VERSION 5.8 ;
BUSBITCHARS "[]" ;
DIVIDERCHAR "/" ;
UNITS
    DATABASE MICRONS 1000 ;
END UNITS

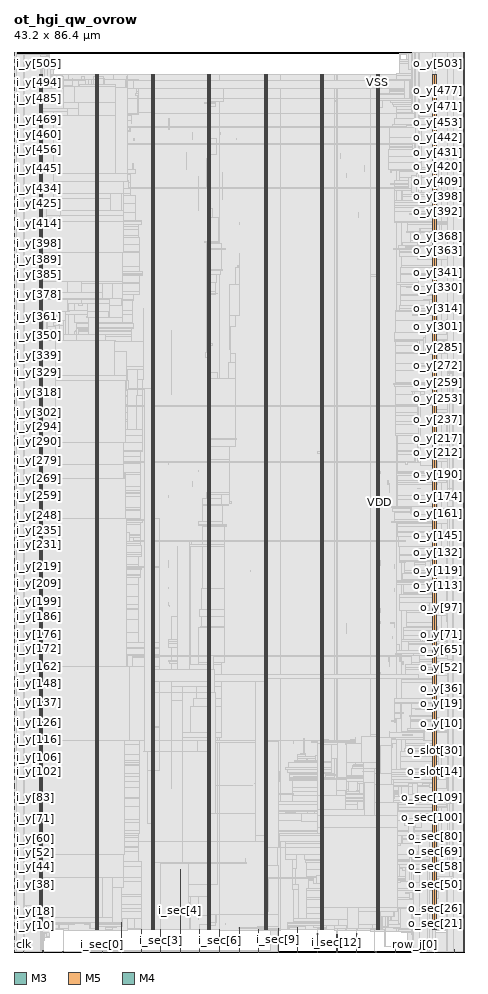
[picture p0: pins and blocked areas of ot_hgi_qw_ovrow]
MACRO ot_hgi_qw_ovrow
  FOREIGN ot_hgi_qw_ovrow 0 0 ;
  CLASS BLOCK ;
  SIZE 43.2 BY 86.4 ;
  PIN clk
    DIRECTION INPUT ;
    USE SIGNAL ;
    PORT
      LAYER M3 ;
        RECT  0.936 0 0.954 0.038 ;
    END
    PORT
      LAYER M3 ;
        RECT  0.936 0.012 0.954 0.077 ;
    END
  END clk
  PIN i_n[0]
    DIRECTION INPUT ;
    USE SIGNAL ;
    PORT
      LAYER M5 ;
        RECT  2.784 0 2.808 0.084 ;
    END
    PORT
      LAYER M5 ;
        RECT  2.784 0.016 2.808 0.037 ;
    END
    PORT
      LAYER M5 ;
        RECT  2.688 0.037 2.808 0.179 ;
    END
  END i_n[0]
  PIN i_n[1]
    DIRECTION INPUT ;
    USE SIGNAL ;
    PORT
      LAYER M3 ;
        RECT  4.68 0 4.698 0.038 ;
    END
    PORT
      LAYER M3 ;
        RECT  4.68 0.012 4.698 0.031 ;
    END
    PORT
      LAYER M3 ;
        RECT  4.68 0.031 4.77 0.059 ;
    END
  END i_n[1]
  PIN i_n[2]
    DIRECTION INPUT ;
    USE SIGNAL ;
    PORT
      LAYER M5 ;
        RECT  6.576 0 6.6 0.084 ;
    END
    PORT
      LAYER M5 ;
        RECT  6.576 0.016 6.6 0.131 ;
    END
  END i_n[2]
  PIN i_sec[0]
    DIRECTION INPUT ;
    USE SIGNAL ;
    PORT
      LAYER M3 ;
        RECT  8.46 0 8.478 0.038 ;
    END
    PORT
      LAYER M3 ;
        RECT  8.46 0.012 8.478 0.059 ;
    END
  END i_sec[0]
  PIN i_sec[10]
    DIRECTION INPUT ;
    USE SIGNAL ;
    PORT
      LAYER M3 ;
        RECT  27.216 0 27.234 0.038 ;
    END
    PORT
      LAYER M3 ;
        RECT  27.216 0.012 27.234 2.371 ;
    END
  END i_sec[10]
  PIN i_sec[11]
    DIRECTION INPUT ;
    USE SIGNAL ;
    PORT
      LAYER M5 ;
        RECT  29.088 0 29.112 0.084 ;
    END
    PORT
      LAYER M5 ;
        RECT  29.088 0.016 29.112 1.763 ;
    END
  END i_sec[11]
  PIN i_sec[12]
    DIRECTION INPUT ;
    USE SIGNAL ;
    PORT
      LAYER M3 ;
        RECT  30.996 0 31.014 0.038 ;
    END
    PORT
      LAYER M3 ;
        RECT  30.996 0.012 31.014 1.723 ;
    END
  END i_sec[12]
  PIN i_sec[13]
    DIRECTION INPUT ;
    USE SIGNAL ;
    PORT
      LAYER M5 ;
        RECT  32.88 0 32.904 0.084 ;
    END
    PORT
      LAYER M5 ;
        RECT  32.88 0.016 32.904 1.763 ;
    END
  END i_sec[13]
  PIN i_sec[14]
    DIRECTION INPUT ;
    USE SIGNAL ;
    PORT
      LAYER M3 ;
        RECT  34.74 0 34.758 0.038 ;
    END
    PORT
      LAYER M3 ;
        RECT  34.74 0.012 34.758 0.031 ;
    END
    PORT
      LAYER M3 ;
        RECT  34.596 0.031 34.758 0.059 ;
    END
  END i_sec[14]
  PIN i_sec[1]
    DIRECTION INPUT ;
    USE SIGNAL ;
    PORT
      LAYER M5 ;
        RECT  10.32 0 10.344 0.084 ;
    END
    PORT
      LAYER M5 ;
        RECT  10.32 0.016 10.344 2.821 ;
    END
  END i_sec[1]
  PIN i_sec[2]
    DIRECTION INPUT ;
    USE SIGNAL ;
    PORT
      LAYER M3 ;
        RECT  12.204 0 12.222 0.038 ;
    END
    PORT
      LAYER M3 ;
        RECT  12.204 0.012 12.222 2.191 ;
    END
  END i_sec[2]
  PIN i_sec[3]
    DIRECTION INPUT ;
    USE SIGNAL ;
    PORT
      LAYER M5 ;
        RECT  14.064 0 14.088 0.084 ;
    END
    PORT
      LAYER M5 ;
        RECT  14.064 0.016 14.088 2.137 ;
    END
  END i_sec[3]
  PIN i_sec[4]
    DIRECTION INPUT ;
    USE SIGNAL ;
    PORT
      LAYER M3 ;
        RECT  15.948 0 15.966 0.038 ;
    END
    PORT
      LAYER M3 ;
        RECT  15.948 0.012 15.966 7.889 ;
    END
  END i_sec[4]
  PIN i_sec[5]
    DIRECTION INPUT ;
    USE SIGNAL ;
    PORT
      LAYER M5 ;
        RECT  17.808 0 17.832 0.084 ;
    END
    PORT
      LAYER M5 ;
        RECT  17.808 0.016 17.832 2.137 ;
    END
  END i_sec[5]
  PIN i_sec[6]
    DIRECTION INPUT ;
    USE SIGNAL ;
    PORT
      LAYER M3 ;
        RECT  19.728 0 19.746 0.038 ;
    END
    PORT
      LAYER M3 ;
        RECT  19.728 0.012 19.746 2.129 ;
    END
  END i_sec[6]
  PIN i_sec[7]
    DIRECTION INPUT ;
    USE SIGNAL ;
    PORT
      LAYER M5 ;
        RECT  21.6 0 21.624 0.084 ;
    END
    PORT
      LAYER M5 ;
        RECT  21.6 0.016 21.624 2.339 ;
    END
  END i_sec[7]
  PIN i_sec[8]
    DIRECTION INPUT ;
    USE SIGNAL ;
    PORT
      LAYER M3 ;
        RECT  23.472 0 23.49 0.038 ;
    END
    PORT
      LAYER M3 ;
        RECT  23.472 0.012 23.49 2.143 ;
    END
  END i_sec[8]
  PIN i_sec[9]
    DIRECTION INPUT ;
    USE SIGNAL ;
    PORT
      LAYER M5 ;
        RECT  25.344 0 25.368 0.084 ;
    END
    PORT
      LAYER M5 ;
        RECT  25.344 0.016 25.368 2.291 ;
    END
  END i_sec[9]
  PIN i_v
    DIRECTION INPUT ;
    USE SIGNAL ;
    PORT
      LAYER M5 ;
        RECT  36.624 0 36.648 0.084 ;
    END
    PORT
      LAYER M5 ;
        RECT  36.624 0.016 36.648 0.563 ;
    END
  END i_v
  PIN i_y[0]
    DIRECTION INPUT ;
    USE SIGNAL ;
    PORT
      LAYER M4 ;
        RECT  0 0.096 0.084 0.12 ;
    END
  END i_y[0]
  PIN i_y[100]
    DIRECTION INPUT ;
    USE SIGNAL ;
    PORT
      LAYER M4 ;
        RECT  0 16.944 0.084 16.968 ;
    END
  END i_y[100]
  PIN i_y[101]
    DIRECTION INPUT ;
    USE SIGNAL ;
    PORT
      LAYER M4 ;
        RECT  0 17.136 0.084 17.16 ;
    END
  END i_y[101]
  PIN i_y[102]
    DIRECTION INPUT ;
    USE SIGNAL ;
    PORT
      LAYER M4 ;
        RECT  0 17.28 0.084 17.304 ;
    END
  END i_y[102]
  PIN i_y[103]
    DIRECTION INPUT ;
    USE SIGNAL ;
    PORT
      LAYER M4 ;
        RECT  0 17.472 0.084 17.496 ;
    END
  END i_y[103]
  PIN i_y[104]
    DIRECTION INPUT ;
    USE SIGNAL ;
    PORT
      LAYER M4 ;
        RECT  0 17.616 0.084 17.64 ;
    END
  END i_y[104]
  PIN i_y[105]
    DIRECTION INPUT ;
    USE SIGNAL ;
    PORT
      LAYER M4 ;
        RECT  0 17.808 0.084 17.832 ;
    END
  END i_y[105]
  PIN i_y[106]
    DIRECTION INPUT ;
    USE SIGNAL ;
    PORT
      LAYER M4 ;
        RECT  0 17.952 0.084 17.976 ;
    END
  END i_y[106]
  PIN i_y[107]
    DIRECTION INPUT ;
    USE SIGNAL ;
    PORT
      LAYER M4 ;
        RECT  0 18.144 0.084 18.168 ;
    END
  END i_y[107]
  PIN i_y[108]
    DIRECTION INPUT ;
    USE SIGNAL ;
    PORT
      LAYER M4 ;
        RECT  0 18.288 0.084 18.312 ;
    END
  END i_y[108]
  PIN i_y[109]
    DIRECTION INPUT ;
    USE SIGNAL ;
    PORT
      LAYER M4 ;
        RECT  0 18.48 0.084 18.504 ;
    END
  END i_y[109]
  PIN i_y[10]
    DIRECTION INPUT ;
    USE SIGNAL ;
    PORT
      LAYER M4 ;
        RECT  0 1.776 0.084 1.8 ;
    END
  END i_y[10]
  PIN i_y[110]
    DIRECTION INPUT ;
    USE SIGNAL ;
    PORT
      LAYER M4 ;
        RECT  0 18.624 0.084 18.648 ;
    END
  END i_y[110]
  PIN i_y[111]
    DIRECTION INPUT ;
    USE SIGNAL ;
    PORT
      LAYER M4 ;
        RECT  0 18.816 0.084 18.84 ;
    END
  END i_y[111]
  PIN i_y[112]
    DIRECTION INPUT ;
    USE SIGNAL ;
    PORT
      LAYER M4 ;
        RECT  0 18.96 0.084 18.984 ;
    END
  END i_y[112]
  PIN i_y[113]
    DIRECTION INPUT ;
    USE SIGNAL ;
    PORT
      LAYER M4 ;
        RECT  0 19.152 0.084 19.176 ;
    END
  END i_y[113]
  PIN i_y[114]
    DIRECTION INPUT ;
    USE SIGNAL ;
    PORT
      LAYER M4 ;
        RECT  0 19.296 0.084 19.32 ;
    END
  END i_y[114]
  PIN i_y[115]
    DIRECTION INPUT ;
    USE SIGNAL ;
    PORT
      LAYER M4 ;
        RECT  0 19.488 0.084 19.512 ;
    END
  END i_y[115]
  PIN i_y[116]
    DIRECTION INPUT ;
    USE SIGNAL ;
    PORT
      LAYER M4 ;
        RECT  0 19.632 0.084 19.656 ;
    END
  END i_y[116]
  PIN i_y[117]
    DIRECTION INPUT ;
    USE SIGNAL ;
    PORT
      LAYER M4 ;
        RECT  0 19.824 0.084 19.848 ;
    END
  END i_y[117]
  PIN i_y[118]
    DIRECTION INPUT ;
    USE SIGNAL ;
    PORT
      LAYER M4 ;
        RECT  0 19.968 0.084 19.992 ;
    END
  END i_y[118]
  PIN i_y[119]
    DIRECTION INPUT ;
    USE SIGNAL ;
    PORT
      LAYER M4 ;
        RECT  0 20.16 0.084 20.184 ;
    END
  END i_y[119]
  PIN i_y[11]
    DIRECTION INPUT ;
    USE SIGNAL ;
    PORT
      LAYER M4 ;
        RECT  0 1.92 0.084 1.944 ;
    END
  END i_y[11]
  PIN i_y[120]
    DIRECTION INPUT ;
    USE SIGNAL ;
    PORT
      LAYER M4 ;
        RECT  0 20.304 0.084 20.328 ;
    END
  END i_y[120]
  PIN i_y[121]
    DIRECTION INPUT ;
    USE SIGNAL ;
    PORT
      LAYER M4 ;
        RECT  0 20.496 0.084 20.52 ;
    END
  END i_y[121]
  PIN i_y[122]
    DIRECTION INPUT ;
    USE SIGNAL ;
    PORT
      LAYER M4 ;
        RECT  0 20.64 0.084 20.664 ;
    END
  END i_y[122]
  PIN i_y[123]
    DIRECTION INPUT ;
    USE SIGNAL ;
    PORT
      LAYER M4 ;
        RECT  0 20.832 0.084 20.856 ;
    END
  END i_y[123]
  PIN i_y[124]
    DIRECTION INPUT ;
    USE SIGNAL ;
    PORT
      LAYER M4 ;
        RECT  0 20.976 0.084 21 ;
    END
  END i_y[124]
  PIN i_y[125]
    DIRECTION INPUT ;
    USE SIGNAL ;
    PORT
      LAYER M4 ;
        RECT  0 21.168 0.084 21.192 ;
    END
  END i_y[125]
  PIN i_y[126]
    DIRECTION INPUT ;
    USE SIGNAL ;
    PORT
      LAYER M4 ;
        RECT  0 21.312 0.084 21.336 ;
    END
  END i_y[126]
  PIN i_y[127]
    DIRECTION INPUT ;
    USE SIGNAL ;
    PORT
      LAYER M4 ;
        RECT  0 21.504 0.084 21.528 ;
    END
  END i_y[127]
  PIN i_y[128]
    DIRECTION INPUT ;
    USE SIGNAL ;
    PORT
      LAYER M4 ;
        RECT  0 21.696 0.084 21.72 ;
    END
  END i_y[128]
  PIN i_y[129]
    DIRECTION INPUT ;
    USE SIGNAL ;
    PORT
      LAYER M4 ;
        RECT  0 21.84 0.084 21.864 ;
    END
  END i_y[129]
  PIN i_y[12]
    DIRECTION INPUT ;
    USE SIGNAL ;
    PORT
      LAYER M4 ;
        RECT  0 2.112 0.084 2.136 ;
    END
  END i_y[12]
  PIN i_y[130]
    DIRECTION INPUT ;
    USE SIGNAL ;
    PORT
      LAYER M4 ;
        RECT  0 22.032 0.084 22.056 ;
    END
  END i_y[130]
  PIN i_y[131]
    DIRECTION INPUT ;
    USE SIGNAL ;
    PORT
      LAYER M4 ;
        RECT  0 22.176 0.084 22.2 ;
    END
  END i_y[131]
  PIN i_y[132]
    DIRECTION INPUT ;
    USE SIGNAL ;
    PORT
      LAYER M4 ;
        RECT  0 22.368 0.084 22.392 ;
    END
  END i_y[132]
  PIN i_y[133]
    DIRECTION INPUT ;
    USE SIGNAL ;
    PORT
      LAYER M4 ;
        RECT  0 22.512 0.084 22.536 ;
    END
  END i_y[133]
  PIN i_y[134]
    DIRECTION INPUT ;
    USE SIGNAL ;
    PORT
      LAYER M4 ;
        RECT  0 22.704 0.084 22.728 ;
    END
  END i_y[134]
  PIN i_y[135]
    DIRECTION INPUT ;
    USE SIGNAL ;
    PORT
      LAYER M4 ;
        RECT  0 22.848 0.084 22.872 ;
    END
  END i_y[135]
  PIN i_y[136]
    DIRECTION INPUT ;
    USE SIGNAL ;
    PORT
      LAYER M4 ;
        RECT  0 23.04 0.084 23.064 ;
    END
  END i_y[136]
  PIN i_y[137]
    DIRECTION INPUT ;
    USE SIGNAL ;
    PORT
      LAYER M4 ;
        RECT  0 23.184 0.084 23.208 ;
    END
  END i_y[137]
  PIN i_y[138]
    DIRECTION INPUT ;
    USE SIGNAL ;
    PORT
      LAYER M4 ;
        RECT  0 23.376 0.084 23.4 ;
    END
  END i_y[138]
  PIN i_y[139]
    DIRECTION INPUT ;
    USE SIGNAL ;
    PORT
      LAYER M4 ;
        RECT  0 23.52 0.084 23.544 ;
    END
  END i_y[139]
  PIN i_y[13]
    DIRECTION INPUT ;
    USE SIGNAL ;
    PORT
      LAYER M4 ;
        RECT  0 2.256 0.084 2.28 ;
    END
  END i_y[13]
  PIN i_y[140]
    DIRECTION INPUT ;
    USE SIGNAL ;
    PORT
      LAYER M4 ;
        RECT  0 23.712 0.084 23.736 ;
    END
  END i_y[140]
  PIN i_y[141]
    DIRECTION INPUT ;
    USE SIGNAL ;
    PORT
      LAYER M4 ;
        RECT  0 23.856 0.084 23.88 ;
    END
  END i_y[141]
  PIN i_y[142]
    DIRECTION INPUT ;
    USE SIGNAL ;
    PORT
      LAYER M4 ;
        RECT  0 24.048 0.084 24.072 ;
    END
  END i_y[142]
  PIN i_y[143]
    DIRECTION INPUT ;
    USE SIGNAL ;
    PORT
      LAYER M4 ;
        RECT  0 24.192 0.084 24.216 ;
    END
  END i_y[143]
  PIN i_y[144]
    DIRECTION INPUT ;
    USE SIGNAL ;
    PORT
      LAYER M4 ;
        RECT  0 24.384 0.084 24.408 ;
    END
  END i_y[144]
  PIN i_y[145]
    DIRECTION INPUT ;
    USE SIGNAL ;
    PORT
      LAYER M4 ;
        RECT  0 24.528 0.084 24.552 ;
    END
  END i_y[145]
  PIN i_y[146]
    DIRECTION INPUT ;
    USE SIGNAL ;
    PORT
      LAYER M4 ;
        RECT  0 24.72 0.084 24.744 ;
    END
  END i_y[146]
  PIN i_y[147]
    DIRECTION INPUT ;
    USE SIGNAL ;
    PORT
      LAYER M4 ;
        RECT  0 24.864 0.084 24.888 ;
    END
  END i_y[147]
  PIN i_y[148]
    DIRECTION INPUT ;
    USE SIGNAL ;
    PORT
      LAYER M4 ;
        RECT  0 25.056 0.084 25.08 ;
    END
  END i_y[148]
  PIN i_y[149]
    DIRECTION INPUT ;
    USE SIGNAL ;
    PORT
      LAYER M4 ;
        RECT  0 25.2 0.084 25.224 ;
    END
  END i_y[149]
  PIN i_y[14]
    DIRECTION INPUT ;
    USE SIGNAL ;
    PORT
      LAYER M4 ;
        RECT  0 2.448 0.084 2.472 ;
    END
  END i_y[14]
  PIN i_y[150]
    DIRECTION INPUT ;
    USE SIGNAL ;
    PORT
      LAYER M4 ;
        RECT  0 25.392 0.084 25.416 ;
    END
  END i_y[150]
  PIN i_y[151]
    DIRECTION INPUT ;
    USE SIGNAL ;
    PORT
      LAYER M4 ;
        RECT  0 25.536 0.084 25.56 ;
    END
  END i_y[151]
  PIN i_y[152]
    DIRECTION INPUT ;
    USE SIGNAL ;
    PORT
      LAYER M4 ;
        RECT  0 25.728 0.084 25.752 ;
    END
  END i_y[152]
  PIN i_y[153]
    DIRECTION INPUT ;
    USE SIGNAL ;
    PORT
      LAYER M4 ;
        RECT  0 25.872 0.084 25.896 ;
    END
  END i_y[153]
  PIN i_y[154]
    DIRECTION INPUT ;
    USE SIGNAL ;
    PORT
      LAYER M4 ;
        RECT  0 26.064 0.084 26.088 ;
    END
  END i_y[154]
  PIN i_y[155]
    DIRECTION INPUT ;
    USE SIGNAL ;
    PORT
      LAYER M4 ;
        RECT  0 26.208 0.084 26.232 ;
    END
  END i_y[155]
  PIN i_y[156]
    DIRECTION INPUT ;
    USE SIGNAL ;
    PORT
      LAYER M4 ;
        RECT  0 26.4 0.084 26.424 ;
    END
  END i_y[156]
  PIN i_y[157]
    DIRECTION INPUT ;
    USE SIGNAL ;
    PORT
      LAYER M4 ;
        RECT  0 26.544 0.084 26.568 ;
    END
  END i_y[157]
  PIN i_y[158]
    DIRECTION INPUT ;
    USE SIGNAL ;
    PORT
      LAYER M4 ;
        RECT  0 26.736 0.084 26.76 ;
    END
  END i_y[158]
  PIN i_y[159]
    DIRECTION INPUT ;
    USE SIGNAL ;
    PORT
      LAYER M4 ;
        RECT  0 26.928 0.084 26.952 ;
    END
  END i_y[159]
  PIN i_y[15]
    DIRECTION INPUT ;
    USE SIGNAL ;
    PORT
      LAYER M4 ;
        RECT  0 2.592 0.084 2.616 ;
    END
  END i_y[15]
  PIN i_y[160]
    DIRECTION INPUT ;
    USE SIGNAL ;
    PORT
      LAYER M4 ;
        RECT  0 27.072 0.084 27.096 ;
    END
  END i_y[160]
  PIN i_y[161]
    DIRECTION INPUT ;
    USE SIGNAL ;
    PORT
      LAYER M4 ;
        RECT  0 27.264 0.084 27.288 ;
    END
  END i_y[161]
  PIN i_y[162]
    DIRECTION INPUT ;
    USE SIGNAL ;
    PORT
      LAYER M4 ;
        RECT  0 27.408 0.084 27.432 ;
    END
  END i_y[162]
  PIN i_y[163]
    DIRECTION INPUT ;
    USE SIGNAL ;
    PORT
      LAYER M4 ;
        RECT  0 27.6 0.084 27.624 ;
    END
  END i_y[163]
  PIN i_y[164]
    DIRECTION INPUT ;
    USE SIGNAL ;
    PORT
      LAYER M4 ;
        RECT  0 27.744 0.084 27.768 ;
    END
  END i_y[164]
  PIN i_y[165]
    DIRECTION INPUT ;
    USE SIGNAL ;
    PORT
      LAYER M4 ;
        RECT  0 27.936 0.084 27.96 ;
    END
  END i_y[165]
  PIN i_y[166]
    DIRECTION INPUT ;
    USE SIGNAL ;
    PORT
      LAYER M4 ;
        RECT  0 28.08 0.084 28.104 ;
    END
  END i_y[166]
  PIN i_y[167]
    DIRECTION INPUT ;
    USE SIGNAL ;
    PORT
      LAYER M4 ;
        RECT  0 28.272 0.084 28.296 ;
    END
  END i_y[167]
  PIN i_y[168]
    DIRECTION INPUT ;
    USE SIGNAL ;
    PORT
      LAYER M4 ;
        RECT  0 28.416 0.084 28.44 ;
    END
  END i_y[168]
  PIN i_y[169]
    DIRECTION INPUT ;
    USE SIGNAL ;
    PORT
      LAYER M4 ;
        RECT  0 28.608 0.084 28.632 ;
    END
  END i_y[169]
  PIN i_y[16]
    DIRECTION INPUT ;
    USE SIGNAL ;
    PORT
      LAYER M4 ;
        RECT  0 2.784 0.084 2.808 ;
    END
  END i_y[16]
  PIN i_y[170]
    DIRECTION INPUT ;
    USE SIGNAL ;
    PORT
      LAYER M4 ;
        RECT  0 28.752 0.084 28.776 ;
    END
  END i_y[170]
  PIN i_y[171]
    DIRECTION INPUT ;
    USE SIGNAL ;
    PORT
      LAYER M4 ;
        RECT  0 28.944 0.084 28.968 ;
    END
  END i_y[171]
  PIN i_y[172]
    DIRECTION INPUT ;
    USE SIGNAL ;
    PORT
      LAYER M4 ;
        RECT  0 29.088 0.084 29.112 ;
    END
  END i_y[172]
  PIN i_y[173]
    DIRECTION INPUT ;
    USE SIGNAL ;
    PORT
      LAYER M4 ;
        RECT  0 29.28 0.084 29.304 ;
    END
  END i_y[173]
  PIN i_y[174]
    DIRECTION INPUT ;
    USE SIGNAL ;
    PORT
      LAYER M4 ;
        RECT  0 29.424 0.084 29.448 ;
    END
  END i_y[174]
  PIN i_y[175]
    DIRECTION INPUT ;
    USE SIGNAL ;
    PORT
      LAYER M4 ;
        RECT  0 29.616 0.084 29.64 ;
    END
  END i_y[175]
  PIN i_y[176]
    DIRECTION INPUT ;
    USE SIGNAL ;
    PORT
      LAYER M4 ;
        RECT  0 29.76 0.084 29.784 ;
    END
  END i_y[176]
  PIN i_y[177]
    DIRECTION INPUT ;
    USE SIGNAL ;
    PORT
      LAYER M4 ;
        RECT  0 29.952 0.084 29.976 ;
    END
  END i_y[177]
  PIN i_y[178]
    DIRECTION INPUT ;
    USE SIGNAL ;
    PORT
      LAYER M4 ;
        RECT  0 30.096 0.084 30.12 ;
    END
  END i_y[178]
  PIN i_y[179]
    DIRECTION INPUT ;
    USE SIGNAL ;
    PORT
      LAYER M4 ;
        RECT  0 30.288 0.084 30.312 ;
    END
  END i_y[179]
  PIN i_y[17]
    DIRECTION INPUT ;
    USE SIGNAL ;
    PORT
      LAYER M4 ;
        RECT  0 2.928 0.084 2.952 ;
    END
  END i_y[17]
  PIN i_y[180]
    DIRECTION INPUT ;
    USE SIGNAL ;
    PORT
      LAYER M4 ;
        RECT  0 30.432 0.084 30.456 ;
    END
  END i_y[180]
  PIN i_y[181]
    DIRECTION INPUT ;
    USE SIGNAL ;
    PORT
      LAYER M4 ;
        RECT  0 30.624 0.084 30.648 ;
    END
  END i_y[181]
  PIN i_y[182]
    DIRECTION INPUT ;
    USE SIGNAL ;
    PORT
      LAYER M4 ;
        RECT  0 30.768 0.084 30.792 ;
    END
  END i_y[182]
  PIN i_y[183]
    DIRECTION INPUT ;
    USE SIGNAL ;
    PORT
      LAYER M4 ;
        RECT  0 30.96 0.084 30.984 ;
    END
  END i_y[183]
  PIN i_y[184]
    DIRECTION INPUT ;
    USE SIGNAL ;
    PORT
      LAYER M4 ;
        RECT  0 31.104 0.084 31.128 ;
    END
  END i_y[184]
  PIN i_y[185]
    DIRECTION INPUT ;
    USE SIGNAL ;
    PORT
      LAYER M4 ;
        RECT  0 31.296 0.084 31.32 ;
    END
  END i_y[185]
  PIN i_y[186]
    DIRECTION INPUT ;
    USE SIGNAL ;
    PORT
      LAYER M4 ;
        RECT  0 31.44 0.084 31.464 ;
    END
  END i_y[186]
  PIN i_y[187]
    DIRECTION INPUT ;
    USE SIGNAL ;
    PORT
      LAYER M4 ;
        RECT  0 31.632 0.084 31.656 ;
    END
  END i_y[187]
  PIN i_y[188]
    DIRECTION INPUT ;
    USE SIGNAL ;
    PORT
      LAYER M4 ;
        RECT  0 31.776 0.084 31.8 ;
    END
  END i_y[188]
  PIN i_y[189]
    DIRECTION INPUT ;
    USE SIGNAL ;
    PORT
      LAYER M4 ;
        RECT  0 31.968 0.084 31.992 ;
    END
  END i_y[189]
  PIN i_y[18]
    DIRECTION INPUT ;
    USE SIGNAL ;
    PORT
      LAYER M4 ;
        RECT  0 3.12 0.084 3.144 ;
    END
  END i_y[18]
  PIN i_y[190]
    DIRECTION INPUT ;
    USE SIGNAL ;
    PORT
      LAYER M4 ;
        RECT  0 32.112 0.084 32.136 ;
    END
  END i_y[190]
  PIN i_y[191]
    DIRECTION INPUT ;
    USE SIGNAL ;
    PORT
      LAYER M4 ;
        RECT  0 32.304 0.084 32.328 ;
    END
  END i_y[191]
  PIN i_y[192]
    DIRECTION INPUT ;
    USE SIGNAL ;
    PORT
      LAYER M4 ;
        RECT  0 32.496 0.084 32.52 ;
    END
  END i_y[192]
  PIN i_y[193]
    DIRECTION INPUT ;
    USE SIGNAL ;
    PORT
      LAYER M4 ;
        RECT  0 32.64 0.084 32.664 ;
    END
  END i_y[193]
  PIN i_y[194]
    DIRECTION INPUT ;
    USE SIGNAL ;
    PORT
      LAYER M4 ;
        RECT  0 32.832 0.084 32.856 ;
    END
  END i_y[194]
  PIN i_y[195]
    DIRECTION INPUT ;
    USE SIGNAL ;
    PORT
      LAYER M4 ;
        RECT  0 32.976 0.084 33 ;
    END
  END i_y[195]
  PIN i_y[196]
    DIRECTION INPUT ;
    USE SIGNAL ;
    PORT
      LAYER M4 ;
        RECT  0 33.168 0.084 33.192 ;
    END
  END i_y[196]
  PIN i_y[197]
    DIRECTION INPUT ;
    USE SIGNAL ;
    PORT
      LAYER M4 ;
        RECT  0 33.312 0.084 33.336 ;
    END
  END i_y[197]
  PIN i_y[198]
    DIRECTION INPUT ;
    USE SIGNAL ;
    PORT
      LAYER M4 ;
        RECT  0 33.504 0.084 33.528 ;
    END
  END i_y[198]
  PIN i_y[199]
    DIRECTION INPUT ;
    USE SIGNAL ;
    PORT
      LAYER M4 ;
        RECT  0 33.648 0.084 33.672 ;
    END
  END i_y[199]
  PIN i_y[19]
    DIRECTION INPUT ;
    USE SIGNAL ;
    PORT
      LAYER M4 ;
        RECT  0 3.264 0.084 3.288 ;
    END
  END i_y[19]
  PIN i_y[1]
    DIRECTION INPUT ;
    USE SIGNAL ;
    PORT
      LAYER M4 ;
        RECT  0 0.24 0.084 0.264 ;
    END
  END i_y[1]
  PIN i_y[200]
    DIRECTION INPUT ;
    USE SIGNAL ;
    PORT
      LAYER M4 ;
        RECT  0 33.84 0.084 33.864 ;
    END
  END i_y[200]
  PIN i_y[201]
    DIRECTION INPUT ;
    USE SIGNAL ;
    PORT
      LAYER M4 ;
        RECT  0 33.984 0.084 34.008 ;
    END
  END i_y[201]
  PIN i_y[202]
    DIRECTION INPUT ;
    USE SIGNAL ;
    PORT
      LAYER M4 ;
        RECT  0 34.176 0.084 34.2 ;
    END
  END i_y[202]
  PIN i_y[203]
    DIRECTION INPUT ;
    USE SIGNAL ;
    PORT
      LAYER M4 ;
        RECT  0 34.32 0.084 34.344 ;
    END
  END i_y[203]
  PIN i_y[204]
    DIRECTION INPUT ;
    USE SIGNAL ;
    PORT
      LAYER M4 ;
        RECT  0 34.512 0.084 34.536 ;
    END
  END i_y[204]
  PIN i_y[205]
    DIRECTION INPUT ;
    USE SIGNAL ;
    PORT
      LAYER M4 ;
        RECT  0 34.656 0.084 34.68 ;
    END
  END i_y[205]
  PIN i_y[206]
    DIRECTION INPUT ;
    USE SIGNAL ;
    PORT
      LAYER M4 ;
        RECT  0 34.848 0.084 34.872 ;
    END
  END i_y[206]
  PIN i_y[207]
    DIRECTION INPUT ;
    USE SIGNAL ;
    PORT
      LAYER M4 ;
        RECT  0 34.992 0.084 35.016 ;
    END
  END i_y[207]
  PIN i_y[208]
    DIRECTION INPUT ;
    USE SIGNAL ;
    PORT
      LAYER M4 ;
        RECT  0 35.184 0.084 35.208 ;
    END
  END i_y[208]
  PIN i_y[209]
    DIRECTION INPUT ;
    USE SIGNAL ;
    PORT
      LAYER M4 ;
        RECT  0 35.328 0.084 35.352 ;
    END
  END i_y[209]
  PIN i_y[20]
    DIRECTION INPUT ;
    USE SIGNAL ;
    PORT
      LAYER M4 ;
        RECT  0 3.456 0.084 3.48 ;
    END
  END i_y[20]
  PIN i_y[210]
    DIRECTION INPUT ;
    USE SIGNAL ;
    PORT
      LAYER M4 ;
        RECT  0 35.52 0.084 35.544 ;
    END
  END i_y[210]
  PIN i_y[211]
    DIRECTION INPUT ;
    USE SIGNAL ;
    PORT
      LAYER M4 ;
        RECT  0 35.664 0.084 35.688 ;
    END
  END i_y[211]
  PIN i_y[212]
    DIRECTION INPUT ;
    USE SIGNAL ;
    PORT
      LAYER M4 ;
        RECT  0 35.856 0.084 35.88 ;
    END
  END i_y[212]
  PIN i_y[213]
    DIRECTION INPUT ;
    USE SIGNAL ;
    PORT
      LAYER M4 ;
        RECT  0 36 0.084 36.024 ;
    END
  END i_y[213]
  PIN i_y[214]
    DIRECTION INPUT ;
    USE SIGNAL ;
    PORT
      LAYER M4 ;
        RECT  0 36.192 0.084 36.216 ;
    END
  END i_y[214]
  PIN i_y[215]
    DIRECTION INPUT ;
    USE SIGNAL ;
    PORT
      LAYER M4 ;
        RECT  0 36.336 0.084 36.36 ;
    END
  END i_y[215]
  PIN i_y[216]
    DIRECTION INPUT ;
    USE SIGNAL ;
    PORT
      LAYER M4 ;
        RECT  0 36.528 0.084 36.552 ;
    END
  END i_y[216]
  PIN i_y[217]
    DIRECTION INPUT ;
    USE SIGNAL ;
    PORT
      LAYER M4 ;
        RECT  0 36.672 0.084 36.696 ;
    END
  END i_y[217]
  PIN i_y[218]
    DIRECTION INPUT ;
    USE SIGNAL ;
    PORT
      LAYER M4 ;
        RECT  0 36.864 0.084 36.888 ;
    END
  END i_y[218]
  PIN i_y[219]
    DIRECTION INPUT ;
    USE SIGNAL ;
    PORT
      LAYER M4 ;
        RECT  0 37.008 0.084 37.032 ;
    END
  END i_y[219]
  PIN i_y[21]
    DIRECTION INPUT ;
    USE SIGNAL ;
    PORT
      LAYER M4 ;
        RECT  0 3.6 0.084 3.624 ;
    END
  END i_y[21]
  PIN i_y[220]
    DIRECTION INPUT ;
    USE SIGNAL ;
    PORT
      LAYER M4 ;
        RECT  0 37.2 0.084 37.224 ;
    END
  END i_y[220]
  PIN i_y[221]
    DIRECTION INPUT ;
    USE SIGNAL ;
    PORT
      LAYER M4 ;
        RECT  0 37.344 0.084 37.368 ;
    END
  END i_y[221]
  PIN i_y[222]
    DIRECTION INPUT ;
    USE SIGNAL ;
    PORT
      LAYER M4 ;
        RECT  0 37.536 0.084 37.56 ;
    END
  END i_y[222]
  PIN i_y[223]
    DIRECTION INPUT ;
    USE SIGNAL ;
    PORT
      LAYER M4 ;
        RECT  0 37.728 0.084 37.752 ;
    END
  END i_y[223]
  PIN i_y[224]
    DIRECTION INPUT ;
    USE SIGNAL ;
    PORT
      LAYER M4 ;
        RECT  0 37.872 0.084 37.896 ;
    END
  END i_y[224]
  PIN i_y[225]
    DIRECTION INPUT ;
    USE SIGNAL ;
    PORT
      LAYER M4 ;
        RECT  0 38.064 0.084 38.088 ;
    END
  END i_y[225]
  PIN i_y[226]
    DIRECTION INPUT ;
    USE SIGNAL ;
    PORT
      LAYER M4 ;
        RECT  0 38.208 0.084 38.232 ;
    END
  END i_y[226]
  PIN i_y[227]
    DIRECTION INPUT ;
    USE SIGNAL ;
    PORT
      LAYER M4 ;
        RECT  0 38.4 0.084 38.424 ;
    END
  END i_y[227]
  PIN i_y[228]
    DIRECTION INPUT ;
    USE SIGNAL ;
    PORT
      LAYER M4 ;
        RECT  0 38.544 0.084 38.568 ;
    END
  END i_y[228]
  PIN i_y[229]
    DIRECTION INPUT ;
    USE SIGNAL ;
    PORT
      LAYER M4 ;
        RECT  0 38.736 0.084 38.76 ;
    END
  END i_y[229]
  PIN i_y[22]
    DIRECTION INPUT ;
    USE SIGNAL ;
    PORT
      LAYER M4 ;
        RECT  0 3.792 0.084 3.816 ;
    END
  END i_y[22]
  PIN i_y[230]
    DIRECTION INPUT ;
    USE SIGNAL ;
    PORT
      LAYER M4 ;
        RECT  0 38.88 0.084 38.904 ;
    END
  END i_y[230]
  PIN i_y[231]
    DIRECTION INPUT ;
    USE SIGNAL ;
    PORT
      LAYER M4 ;
        RECT  0 39.072 0.084 39.096 ;
    END
  END i_y[231]
  PIN i_y[232]
    DIRECTION INPUT ;
    USE SIGNAL ;
    PORT
      LAYER M4 ;
        RECT  0 39.216 0.084 39.24 ;
    END
  END i_y[232]
  PIN i_y[233]
    DIRECTION INPUT ;
    USE SIGNAL ;
    PORT
      LAYER M4 ;
        RECT  0 39.408 0.084 39.432 ;
    END
  END i_y[233]
  PIN i_y[234]
    DIRECTION INPUT ;
    USE SIGNAL ;
    PORT
      LAYER M4 ;
        RECT  0 39.552 0.084 39.576 ;
    END
  END i_y[234]
  PIN i_y[235]
    DIRECTION INPUT ;
    USE SIGNAL ;
    PORT
      LAYER M4 ;
        RECT  0 39.744 0.084 39.768 ;
    END
  END i_y[235]
  PIN i_y[236]
    DIRECTION INPUT ;
    USE SIGNAL ;
    PORT
      LAYER M4 ;
        RECT  0 39.888 0.084 39.912 ;
    END
  END i_y[236]
  PIN i_y[237]
    DIRECTION INPUT ;
    USE SIGNAL ;
    PORT
      LAYER M4 ;
        RECT  0 40.08 0.084 40.104 ;
    END
  END i_y[237]
  PIN i_y[238]
    DIRECTION INPUT ;
    USE SIGNAL ;
    PORT
      LAYER M4 ;
        RECT  0 40.224 0.084 40.248 ;
    END
  END i_y[238]
  PIN i_y[239]
    DIRECTION INPUT ;
    USE SIGNAL ;
    PORT
      LAYER M4 ;
        RECT  0 40.416 0.084 40.44 ;
    END
  END i_y[239]
  PIN i_y[23]
    DIRECTION INPUT ;
    USE SIGNAL ;
    PORT
      LAYER M4 ;
        RECT  0 3.936 0.084 3.96 ;
    END
  END i_y[23]
  PIN i_y[240]
    DIRECTION INPUT ;
    USE SIGNAL ;
    PORT
      LAYER M4 ;
        RECT  0 40.56 0.084 40.584 ;
    END
  END i_y[240]
  PIN i_y[241]
    DIRECTION INPUT ;
    USE SIGNAL ;
    PORT
      LAYER M4 ;
        RECT  0 40.752 0.084 40.776 ;
    END
  END i_y[241]
  PIN i_y[242]
    DIRECTION INPUT ;
    USE SIGNAL ;
    PORT
      LAYER M4 ;
        RECT  0 40.896 0.084 40.92 ;
    END
  END i_y[242]
  PIN i_y[243]
    DIRECTION INPUT ;
    USE SIGNAL ;
    PORT
      LAYER M4 ;
        RECT  0 41.088 0.084 41.112 ;
    END
  END i_y[243]
  PIN i_y[244]
    DIRECTION INPUT ;
    USE SIGNAL ;
    PORT
      LAYER M4 ;
        RECT  0 41.232 0.084 41.256 ;
    END
  END i_y[244]
  PIN i_y[245]
    DIRECTION INPUT ;
    USE SIGNAL ;
    PORT
      LAYER M4 ;
        RECT  0 41.424 0.084 41.448 ;
    END
  END i_y[245]
  PIN i_y[246]
    DIRECTION INPUT ;
    USE SIGNAL ;
    PORT
      LAYER M4 ;
        RECT  0 41.568 0.084 41.592 ;
    END
  END i_y[246]
  PIN i_y[247]
    DIRECTION INPUT ;
    USE SIGNAL ;
    PORT
      LAYER M4 ;
        RECT  0 41.76 0.084 41.784 ;
    END
  END i_y[247]
  PIN i_y[248]
    DIRECTION INPUT ;
    USE SIGNAL ;
    PORT
      LAYER M4 ;
        RECT  0 41.904 0.084 41.928 ;
    END
  END i_y[248]
  PIN i_y[249]
    DIRECTION INPUT ;
    USE SIGNAL ;
    PORT
      LAYER M4 ;
        RECT  0 42.096 0.084 42.12 ;
    END
  END i_y[249]
  PIN i_y[24]
    DIRECTION INPUT ;
    USE SIGNAL ;
    PORT
      LAYER M4 ;
        RECT  0 4.128 0.084 4.152 ;
    END
  END i_y[24]
  PIN i_y[250]
    DIRECTION INPUT ;
    USE SIGNAL ;
    PORT
      LAYER M4 ;
        RECT  0 42.24 0.084 42.264 ;
    END
  END i_y[250]
  PIN i_y[251]
    DIRECTION INPUT ;
    USE SIGNAL ;
    PORT
      LAYER M4 ;
        RECT  0 42.432 0.084 42.456 ;
    END
  END i_y[251]
  PIN i_y[252]
    DIRECTION INPUT ;
    USE SIGNAL ;
    PORT
      LAYER M4 ;
        RECT  0 42.576 0.084 42.6 ;
    END
  END i_y[252]
  PIN i_y[253]
    DIRECTION INPUT ;
    USE SIGNAL ;
    PORT
      LAYER M4 ;
        RECT  0 42.768 0.084 42.792 ;
    END
  END i_y[253]
  PIN i_y[254]
    DIRECTION INPUT ;
    USE SIGNAL ;
    PORT
      LAYER M4 ;
        RECT  0 42.912 0.084 42.936 ;
    END
  END i_y[254]
  PIN i_y[255]
    DIRECTION INPUT ;
    USE SIGNAL ;
    PORT
      LAYER M4 ;
        RECT  0 43.104 0.084 43.128 ;
    END
  END i_y[255]
  PIN i_y[256]
    DIRECTION INPUT ;
    USE SIGNAL ;
    PORT
      LAYER M4 ;
        RECT  0 43.296 0.084 43.32 ;
    END
  END i_y[256]
  PIN i_y[257]
    DIRECTION INPUT ;
    USE SIGNAL ;
    PORT
      LAYER M4 ;
        RECT  0 43.44 0.084 43.464 ;
    END
  END i_y[257]
  PIN i_y[258]
    DIRECTION INPUT ;
    USE SIGNAL ;
    PORT
      LAYER M4 ;
        RECT  0 43.632 0.084 43.656 ;
    END
  END i_y[258]
  PIN i_y[259]
    DIRECTION INPUT ;
    USE SIGNAL ;
    PORT
      LAYER M4 ;
        RECT  0 43.776 0.084 43.8 ;
    END
  END i_y[259]
  PIN i_y[25]
    DIRECTION INPUT ;
    USE SIGNAL ;
    PORT
      LAYER M4 ;
        RECT  0 4.272 0.084 4.296 ;
    END
  END i_y[25]
  PIN i_y[260]
    DIRECTION INPUT ;
    USE SIGNAL ;
    PORT
      LAYER M4 ;
        RECT  0 43.968 0.084 43.992 ;
    END
  END i_y[260]
  PIN i_y[261]
    DIRECTION INPUT ;
    USE SIGNAL ;
    PORT
      LAYER M4 ;
        RECT  0 44.112 0.084 44.136 ;
    END
  END i_y[261]
  PIN i_y[262]
    DIRECTION INPUT ;
    USE SIGNAL ;
    PORT
      LAYER M4 ;
        RECT  0 44.304 0.084 44.328 ;
    END
  END i_y[262]
  PIN i_y[263]
    DIRECTION INPUT ;
    USE SIGNAL ;
    PORT
      LAYER M4 ;
        RECT  0 44.448 0.084 44.472 ;
    END
  END i_y[263]
  PIN i_y[264]
    DIRECTION INPUT ;
    USE SIGNAL ;
    PORT
      LAYER M4 ;
        RECT  0 44.64 0.084 44.664 ;
    END
  END i_y[264]
  PIN i_y[265]
    DIRECTION INPUT ;
    USE SIGNAL ;
    PORT
      LAYER M4 ;
        RECT  0 44.784 0.084 44.808 ;
    END
  END i_y[265]
  PIN i_y[266]
    DIRECTION INPUT ;
    USE SIGNAL ;
    PORT
      LAYER M4 ;
        RECT  0 44.976 0.084 45 ;
    END
  END i_y[266]
  PIN i_y[267]
    DIRECTION INPUT ;
    USE SIGNAL ;
    PORT
      LAYER M4 ;
        RECT  0 45.12 0.084 45.144 ;
    END
  END i_y[267]
  PIN i_y[268]
    DIRECTION INPUT ;
    USE SIGNAL ;
    PORT
      LAYER M4 ;
        RECT  0 45.312 0.084 45.336 ;
    END
  END i_y[268]
  PIN i_y[269]
    DIRECTION INPUT ;
    USE SIGNAL ;
    PORT
      LAYER M4 ;
        RECT  0 45.456 0.084 45.48 ;
    END
  END i_y[269]
  PIN i_y[26]
    DIRECTION INPUT ;
    USE SIGNAL ;
    PORT
      LAYER M4 ;
        RECT  0 4.464 0.084 4.488 ;
    END
  END i_y[26]
  PIN i_y[270]
    DIRECTION INPUT ;
    USE SIGNAL ;
    PORT
      LAYER M4 ;
        RECT  0 45.648 0.084 45.672 ;
    END
  END i_y[270]
  PIN i_y[271]
    DIRECTION INPUT ;
    USE SIGNAL ;
    PORT
      LAYER M4 ;
        RECT  0 45.792 0.084 45.816 ;
    END
  END i_y[271]
  PIN i_y[272]
    DIRECTION INPUT ;
    USE SIGNAL ;
    PORT
      LAYER M4 ;
        RECT  0 45.984 0.084 46.008 ;
    END
  END i_y[272]
  PIN i_y[273]
    DIRECTION INPUT ;
    USE SIGNAL ;
    PORT
      LAYER M4 ;
        RECT  0 46.128 0.084 46.152 ;
    END
  END i_y[273]
  PIN i_y[274]
    DIRECTION INPUT ;
    USE SIGNAL ;
    PORT
      LAYER M4 ;
        RECT  0 46.32 0.084 46.344 ;
    END
  END i_y[274]
  PIN i_y[275]
    DIRECTION INPUT ;
    USE SIGNAL ;
    PORT
      LAYER M4 ;
        RECT  0 46.464 0.084 46.488 ;
    END
  END i_y[275]
  PIN i_y[276]
    DIRECTION INPUT ;
    USE SIGNAL ;
    PORT
      LAYER M4 ;
        RECT  0 46.656 0.084 46.68 ;
    END
  END i_y[276]
  PIN i_y[277]
    DIRECTION INPUT ;
    USE SIGNAL ;
    PORT
      LAYER M4 ;
        RECT  0 46.8 0.084 46.824 ;
    END
  END i_y[277]
  PIN i_y[278]
    DIRECTION INPUT ;
    USE SIGNAL ;
    PORT
      LAYER M4 ;
        RECT  0 46.992 0.084 47.016 ;
    END
  END i_y[278]
  PIN i_y[279]
    DIRECTION INPUT ;
    USE SIGNAL ;
    PORT
      LAYER M4 ;
        RECT  0 47.136 0.084 47.16 ;
    END
  END i_y[279]
  PIN i_y[27]
    DIRECTION INPUT ;
    USE SIGNAL ;
    PORT
      LAYER M4 ;
        RECT  0 4.608 0.084 4.632 ;
    END
  END i_y[27]
  PIN i_y[280]
    DIRECTION INPUT ;
    USE SIGNAL ;
    PORT
      LAYER M4 ;
        RECT  0 47.328 0.084 47.352 ;
    END
  END i_y[280]
  PIN i_y[281]
    DIRECTION INPUT ;
    USE SIGNAL ;
    PORT
      LAYER M4 ;
        RECT  0 47.472 0.084 47.496 ;
    END
  END i_y[281]
  PIN i_y[282]
    DIRECTION INPUT ;
    USE SIGNAL ;
    PORT
      LAYER M4 ;
        RECT  0 47.664 0.084 47.688 ;
    END
  END i_y[282]
  PIN i_y[283]
    DIRECTION INPUT ;
    USE SIGNAL ;
    PORT
      LAYER M4 ;
        RECT  0 47.808 0.084 47.832 ;
    END
  END i_y[283]
  PIN i_y[284]
    DIRECTION INPUT ;
    USE SIGNAL ;
    PORT
      LAYER M4 ;
        RECT  0 48 0.084 48.024 ;
    END
  END i_y[284]
  PIN i_y[285]
    DIRECTION INPUT ;
    USE SIGNAL ;
    PORT
      LAYER M4 ;
        RECT  0 48.144 0.084 48.168 ;
    END
  END i_y[285]
  PIN i_y[286]
    DIRECTION INPUT ;
    USE SIGNAL ;
    PORT
      LAYER M4 ;
        RECT  0 48.336 0.084 48.36 ;
    END
  END i_y[286]
  PIN i_y[287]
    DIRECTION INPUT ;
    USE SIGNAL ;
    PORT
      LAYER M4 ;
        RECT  0 48.528 0.084 48.552 ;
    END
  END i_y[287]
  PIN i_y[288]
    DIRECTION INPUT ;
    USE SIGNAL ;
    PORT
      LAYER M4 ;
        RECT  0 48.672 0.084 48.696 ;
    END
  END i_y[288]
  PIN i_y[289]
    DIRECTION INPUT ;
    USE SIGNAL ;
    PORT
      LAYER M4 ;
        RECT  0 48.864 0.084 48.888 ;
    END
  END i_y[289]
  PIN i_y[28]
    DIRECTION INPUT ;
    USE SIGNAL ;
    PORT
      LAYER M4 ;
        RECT  0 4.8 0.084 4.824 ;
    END
  END i_y[28]
  PIN i_y[290]
    DIRECTION INPUT ;
    USE SIGNAL ;
    PORT
      LAYER M4 ;
        RECT  0 49.008 0.084 49.032 ;
    END
  END i_y[290]
  PIN i_y[291]
    DIRECTION INPUT ;
    USE SIGNAL ;
    PORT
      LAYER M4 ;
        RECT  0 49.2 0.084 49.224 ;
    END
  END i_y[291]
  PIN i_y[292]
    DIRECTION INPUT ;
    USE SIGNAL ;
    PORT
      LAYER M4 ;
        RECT  0 49.344 0.084 49.368 ;
    END
  END i_y[292]
  PIN i_y[293]
    DIRECTION INPUT ;
    USE SIGNAL ;
    PORT
      LAYER M4 ;
        RECT  0 49.536 0.084 49.56 ;
    END
  END i_y[293]
  PIN i_y[294]
    DIRECTION INPUT ;
    USE SIGNAL ;
    PORT
      LAYER M4 ;
        RECT  0 49.68 0.084 49.704 ;
    END
  END i_y[294]
  PIN i_y[295]
    DIRECTION INPUT ;
    USE SIGNAL ;
    PORT
      LAYER M4 ;
        RECT  0 49.872 0.084 49.896 ;
    END
  END i_y[295]
  PIN i_y[296]
    DIRECTION INPUT ;
    USE SIGNAL ;
    PORT
      LAYER M4 ;
        RECT  0 50.016 0.084 50.04 ;
    END
  END i_y[296]
  PIN i_y[297]
    DIRECTION INPUT ;
    USE SIGNAL ;
    PORT
      LAYER M4 ;
        RECT  0 50.208 0.084 50.232 ;
    END
  END i_y[297]
  PIN i_y[298]
    DIRECTION INPUT ;
    USE SIGNAL ;
    PORT
      LAYER M4 ;
        RECT  0 50.352 0.084 50.376 ;
    END
  END i_y[298]
  PIN i_y[299]
    DIRECTION INPUT ;
    USE SIGNAL ;
    PORT
      LAYER M4 ;
        RECT  0 50.544 0.084 50.568 ;
    END
  END i_y[299]
  PIN i_y[29]
    DIRECTION INPUT ;
    USE SIGNAL ;
    PORT
      LAYER M4 ;
        RECT  0 4.944 0.084 4.968 ;
    END
  END i_y[29]
  PIN i_y[2]
    DIRECTION INPUT ;
    USE SIGNAL ;
    PORT
      LAYER M4 ;
        RECT  0 0.432 0.084 0.456 ;
    END
  END i_y[2]
  PIN i_y[300]
    DIRECTION INPUT ;
    USE SIGNAL ;
    PORT
      LAYER M4 ;
        RECT  0 50.688 0.084 50.712 ;
    END
  END i_y[300]
  PIN i_y[301]
    DIRECTION INPUT ;
    USE SIGNAL ;
    PORT
      LAYER M4 ;
        RECT  0 50.88 0.084 50.904 ;
    END
  END i_y[301]
  PIN i_y[302]
    DIRECTION INPUT ;
    USE SIGNAL ;
    PORT
      LAYER M4 ;
        RECT  0 51.024 0.084 51.048 ;
    END
  END i_y[302]
  PIN i_y[303]
    DIRECTION INPUT ;
    USE SIGNAL ;
    PORT
      LAYER M4 ;
        RECT  0 51.216 0.084 51.24 ;
    END
  END i_y[303]
  PIN i_y[304]
    DIRECTION INPUT ;
    USE SIGNAL ;
    PORT
      LAYER M4 ;
        RECT  0 51.36 0.084 51.384 ;
    END
  END i_y[304]
  PIN i_y[305]
    DIRECTION INPUT ;
    USE SIGNAL ;
    PORT
      LAYER M4 ;
        RECT  0 51.552 0.084 51.576 ;
    END
  END i_y[305]
  PIN i_y[306]
    DIRECTION INPUT ;
    USE SIGNAL ;
    PORT
      LAYER M4 ;
        RECT  0 51.696 0.084 51.72 ;
    END
  END i_y[306]
  PIN i_y[307]
    DIRECTION INPUT ;
    USE SIGNAL ;
    PORT
      LAYER M4 ;
        RECT  0 51.888 0.084 51.912 ;
    END
  END i_y[307]
  PIN i_y[308]
    DIRECTION INPUT ;
    USE SIGNAL ;
    PORT
      LAYER M4 ;
        RECT  0 52.032 0.084 52.056 ;
    END
  END i_y[308]
  PIN i_y[309]
    DIRECTION INPUT ;
    USE SIGNAL ;
    PORT
      LAYER M4 ;
        RECT  0 52.224 0.084 52.248 ;
    END
  END i_y[309]
  PIN i_y[30]
    DIRECTION INPUT ;
    USE SIGNAL ;
    PORT
      LAYER M4 ;
        RECT  0 5.136 0.084 5.16 ;
    END
  END i_y[30]
  PIN i_y[310]
    DIRECTION INPUT ;
    USE SIGNAL ;
    PORT
      LAYER M4 ;
        RECT  0 52.368 0.084 52.392 ;
    END
  END i_y[310]
  PIN i_y[311]
    DIRECTION INPUT ;
    USE SIGNAL ;
    PORT
      LAYER M4 ;
        RECT  0 52.56 0.084 52.584 ;
    END
  END i_y[311]
  PIN i_y[312]
    DIRECTION INPUT ;
    USE SIGNAL ;
    PORT
      LAYER M4 ;
        RECT  0 52.704 0.084 52.728 ;
    END
  END i_y[312]
  PIN i_y[313]
    DIRECTION INPUT ;
    USE SIGNAL ;
    PORT
      LAYER M4 ;
        RECT  0 52.896 0.084 52.92 ;
    END
  END i_y[313]
  PIN i_y[314]
    DIRECTION INPUT ;
    USE SIGNAL ;
    PORT
      LAYER M4 ;
        RECT  0 53.04 0.084 53.064 ;
    END
  END i_y[314]
  PIN i_y[315]
    DIRECTION INPUT ;
    USE SIGNAL ;
    PORT
      LAYER M4 ;
        RECT  0 53.232 0.084 53.256 ;
    END
  END i_y[315]
  PIN i_y[316]
    DIRECTION INPUT ;
    USE SIGNAL ;
    PORT
      LAYER M4 ;
        RECT  0 53.376 0.084 53.4 ;
    END
  END i_y[316]
  PIN i_y[317]
    DIRECTION INPUT ;
    USE SIGNAL ;
    PORT
      LAYER M4 ;
        RECT  0 53.568 0.084 53.592 ;
    END
  END i_y[317]
  PIN i_y[318]
    DIRECTION INPUT ;
    USE SIGNAL ;
    PORT
      LAYER M4 ;
        RECT  0 53.712 0.084 53.736 ;
    END
  END i_y[318]
  PIN i_y[319]
    DIRECTION INPUT ;
    USE SIGNAL ;
    PORT
      LAYER M4 ;
        RECT  0 53.904 0.084 53.928 ;
    END
  END i_y[319]
  PIN i_y[31]
    DIRECTION INPUT ;
    USE SIGNAL ;
    PORT
      LAYER M4 ;
        RECT  0 5.328 0.084 5.352 ;
    END
  END i_y[31]
  PIN i_y[320]
    DIRECTION INPUT ;
    USE SIGNAL ;
    PORT
      LAYER M4 ;
        RECT  0 54.096 0.084 54.12 ;
    END
  END i_y[320]
  PIN i_y[321]
    DIRECTION INPUT ;
    USE SIGNAL ;
    PORT
      LAYER M4 ;
        RECT  0 54.24 0.084 54.264 ;
    END
  END i_y[321]
  PIN i_y[322]
    DIRECTION INPUT ;
    USE SIGNAL ;
    PORT
      LAYER M4 ;
        RECT  0 54.432 0.084 54.456 ;
    END
  END i_y[322]
  PIN i_y[323]
    DIRECTION INPUT ;
    USE SIGNAL ;
    PORT
      LAYER M4 ;
        RECT  0 54.576 0.084 54.6 ;
    END
  END i_y[323]
  PIN i_y[324]
    DIRECTION INPUT ;
    USE SIGNAL ;
    PORT
      LAYER M4 ;
        RECT  0 54.768 0.084 54.792 ;
    END
  END i_y[324]
  PIN i_y[325]
    DIRECTION INPUT ;
    USE SIGNAL ;
    PORT
      LAYER M4 ;
        RECT  0 54.912 0.084 54.936 ;
    END
  END i_y[325]
  PIN i_y[326]
    DIRECTION INPUT ;
    USE SIGNAL ;
    PORT
      LAYER M4 ;
        RECT  0 55.104 0.084 55.128 ;
    END
  END i_y[326]
  PIN i_y[327]
    DIRECTION INPUT ;
    USE SIGNAL ;
    PORT
      LAYER M4 ;
        RECT  0 55.248 0.084 55.272 ;
    END
  END i_y[327]
  PIN i_y[328]
    DIRECTION INPUT ;
    USE SIGNAL ;
    PORT
      LAYER M4 ;
        RECT  0 55.44 0.084 55.464 ;
    END
  END i_y[328]
  PIN i_y[329]
    DIRECTION INPUT ;
    USE SIGNAL ;
    PORT
      LAYER M4 ;
        RECT  0 55.584 0.084 55.608 ;
    END
  END i_y[329]
  PIN i_y[32]
    DIRECTION INPUT ;
    USE SIGNAL ;
    PORT
      LAYER M4 ;
        RECT  0 5.472 0.084 5.496 ;
    END
  END i_y[32]
  PIN i_y[330]
    DIRECTION INPUT ;
    USE SIGNAL ;
    PORT
      LAYER M4 ;
        RECT  0 55.776 0.084 55.8 ;
    END
  END i_y[330]
  PIN i_y[331]
    DIRECTION INPUT ;
    USE SIGNAL ;
    PORT
      LAYER M4 ;
        RECT  0 55.92 0.084 55.944 ;
    END
  END i_y[331]
  PIN i_y[332]
    DIRECTION INPUT ;
    USE SIGNAL ;
    PORT
      LAYER M4 ;
        RECT  0 56.112 0.084 56.136 ;
    END
  END i_y[332]
  PIN i_y[333]
    DIRECTION INPUT ;
    USE SIGNAL ;
    PORT
      LAYER M4 ;
        RECT  0 56.256 0.084 56.28 ;
    END
  END i_y[333]
  PIN i_y[334]
    DIRECTION INPUT ;
    USE SIGNAL ;
    PORT
      LAYER M4 ;
        RECT  0 56.448 0.084 56.472 ;
    END
  END i_y[334]
  PIN i_y[335]
    DIRECTION INPUT ;
    USE SIGNAL ;
    PORT
      LAYER M4 ;
        RECT  0 56.592 0.084 56.616 ;
    END
  END i_y[335]
  PIN i_y[336]
    DIRECTION INPUT ;
    USE SIGNAL ;
    PORT
      LAYER M4 ;
        RECT  0 56.784 0.084 56.808 ;
    END
  END i_y[336]
  PIN i_y[337]
    DIRECTION INPUT ;
    USE SIGNAL ;
    PORT
      LAYER M4 ;
        RECT  0 56.928 0.084 56.952 ;
    END
  END i_y[337]
  PIN i_y[338]
    DIRECTION INPUT ;
    USE SIGNAL ;
    PORT
      LAYER M4 ;
        RECT  0 57.12 0.084 57.144 ;
    END
  END i_y[338]
  PIN i_y[339]
    DIRECTION INPUT ;
    USE SIGNAL ;
    PORT
      LAYER M4 ;
        RECT  0 57.264 0.084 57.288 ;
    END
  END i_y[339]
  PIN i_y[33]
    DIRECTION INPUT ;
    USE SIGNAL ;
    PORT
      LAYER M4 ;
        RECT  0 5.664 0.084 5.688 ;
    END
  END i_y[33]
  PIN i_y[340]
    DIRECTION INPUT ;
    USE SIGNAL ;
    PORT
      LAYER M4 ;
        RECT  0 57.456 0.084 57.48 ;
    END
  END i_y[340]
  PIN i_y[341]
    DIRECTION INPUT ;
    USE SIGNAL ;
    PORT
      LAYER M4 ;
        RECT  0 57.6 0.084 57.624 ;
    END
  END i_y[341]
  PIN i_y[342]
    DIRECTION INPUT ;
    USE SIGNAL ;
    PORT
      LAYER M4 ;
        RECT  0 57.792 0.084 57.816 ;
    END
  END i_y[342]
  PIN i_y[343]
    DIRECTION INPUT ;
    USE SIGNAL ;
    PORT
      LAYER M4 ;
        RECT  0 57.936 0.084 57.96 ;
    END
  END i_y[343]
  PIN i_y[344]
    DIRECTION INPUT ;
    USE SIGNAL ;
    PORT
      LAYER M4 ;
        RECT  0 58.128 0.084 58.152 ;
    END
  END i_y[344]
  PIN i_y[345]
    DIRECTION INPUT ;
    USE SIGNAL ;
    PORT
      LAYER M4 ;
        RECT  0 58.272 0.084 58.296 ;
    END
  END i_y[345]
  PIN i_y[346]
    DIRECTION INPUT ;
    USE SIGNAL ;
    PORT
      LAYER M4 ;
        RECT  0 58.464 0.084 58.488 ;
    END
  END i_y[346]
  PIN i_y[347]
    DIRECTION INPUT ;
    USE SIGNAL ;
    PORT
      LAYER M4 ;
        RECT  0 58.608 0.084 58.632 ;
    END
  END i_y[347]
  PIN i_y[348]
    DIRECTION INPUT ;
    USE SIGNAL ;
    PORT
      LAYER M4 ;
        RECT  0 58.8 0.084 58.824 ;
    END
  END i_y[348]
  PIN i_y[349]
    DIRECTION INPUT ;
    USE SIGNAL ;
    PORT
      LAYER M4 ;
        RECT  0 58.944 0.084 58.968 ;
    END
  END i_y[349]
  PIN i_y[34]
    DIRECTION INPUT ;
    USE SIGNAL ;
    PORT
      LAYER M4 ;
        RECT  0 5.808 0.084 5.832 ;
    END
  END i_y[34]
  PIN i_y[350]
    DIRECTION INPUT ;
    USE SIGNAL ;
    PORT
      LAYER M4 ;
        RECT  0 59.136 0.084 59.16 ;
    END
  END i_y[350]
  PIN i_y[351]
    DIRECTION INPUT ;
    USE SIGNAL ;
    PORT
      LAYER M4 ;
        RECT  0 59.328 0.084 59.352 ;
    END
  END i_y[351]
  PIN i_y[352]
    DIRECTION INPUT ;
    USE SIGNAL ;
    PORT
      LAYER M4 ;
        RECT  0 59.472 0.084 59.496 ;
    END
  END i_y[352]
  PIN i_y[353]
    DIRECTION INPUT ;
    USE SIGNAL ;
    PORT
      LAYER M4 ;
        RECT  0 59.664 0.084 59.688 ;
    END
  END i_y[353]
  PIN i_y[354]
    DIRECTION INPUT ;
    USE SIGNAL ;
    PORT
      LAYER M4 ;
        RECT  0 59.808 0.084 59.832 ;
    END
  END i_y[354]
  PIN i_y[355]
    DIRECTION INPUT ;
    USE SIGNAL ;
    PORT
      LAYER M4 ;
        RECT  0 60 0.084 60.024 ;
    END
  END i_y[355]
  PIN i_y[356]
    DIRECTION INPUT ;
    USE SIGNAL ;
    PORT
      LAYER M4 ;
        RECT  0 60.144 0.084 60.168 ;
    END
  END i_y[356]
  PIN i_y[357]
    DIRECTION INPUT ;
    USE SIGNAL ;
    PORT
      LAYER M4 ;
        RECT  0 60.336 0.084 60.36 ;
    END
  END i_y[357]
  PIN i_y[358]
    DIRECTION INPUT ;
    USE SIGNAL ;
    PORT
      LAYER M4 ;
        RECT  0 60.48 0.084 60.504 ;
    END
  END i_y[358]
  PIN i_y[359]
    DIRECTION INPUT ;
    USE SIGNAL ;
    PORT
      LAYER M4 ;
        RECT  0 60.672 0.084 60.696 ;
    END
  END i_y[359]
  PIN i_y[35]
    DIRECTION INPUT ;
    USE SIGNAL ;
    PORT
      LAYER M4 ;
        RECT  0 6 0.084 6.024 ;
    END
  END i_y[35]
  PIN i_y[360]
    DIRECTION INPUT ;
    USE SIGNAL ;
    PORT
      LAYER M4 ;
        RECT  0 60.816 0.084 60.84 ;
    END
  END i_y[360]
  PIN i_y[361]
    DIRECTION INPUT ;
    USE SIGNAL ;
    PORT
      LAYER M4 ;
        RECT  0 61.008 0.084 61.032 ;
    END
  END i_y[361]
  PIN i_y[362]
    DIRECTION INPUT ;
    USE SIGNAL ;
    PORT
      LAYER M4 ;
        RECT  0 61.152 0.084 61.176 ;
    END
  END i_y[362]
  PIN i_y[363]
    DIRECTION INPUT ;
    USE SIGNAL ;
    PORT
      LAYER M4 ;
        RECT  0 61.344 0.084 61.368 ;
    END
  END i_y[363]
  PIN i_y[364]
    DIRECTION INPUT ;
    USE SIGNAL ;
    PORT
      LAYER M4 ;
        RECT  0 61.488 0.084 61.512 ;
    END
  END i_y[364]
  PIN i_y[365]
    DIRECTION INPUT ;
    USE SIGNAL ;
    PORT
      LAYER M4 ;
        RECT  0 61.68 0.084 61.704 ;
    END
  END i_y[365]
  PIN i_y[366]
    DIRECTION INPUT ;
    USE SIGNAL ;
    PORT
      LAYER M4 ;
        RECT  0 61.824 0.084 61.848 ;
    END
  END i_y[366]
  PIN i_y[367]
    DIRECTION INPUT ;
    USE SIGNAL ;
    PORT
      LAYER M4 ;
        RECT  0 62.016 0.084 62.04 ;
    END
  END i_y[367]
  PIN i_y[368]
    DIRECTION INPUT ;
    USE SIGNAL ;
    PORT
      LAYER M4 ;
        RECT  0 62.16 0.084 62.184 ;
    END
  END i_y[368]
  PIN i_y[369]
    DIRECTION INPUT ;
    USE SIGNAL ;
    PORT
      LAYER M4 ;
        RECT  0 62.352 0.084 62.376 ;
    END
  END i_y[369]
  PIN i_y[36]
    DIRECTION INPUT ;
    USE SIGNAL ;
    PORT
      LAYER M4 ;
        RECT  0 6.144 0.084 6.168 ;
    END
  END i_y[36]
  PIN i_y[370]
    DIRECTION INPUT ;
    USE SIGNAL ;
    PORT
      LAYER M4 ;
        RECT  0 62.496 0.084 62.52 ;
    END
  END i_y[370]
  PIN i_y[371]
    DIRECTION INPUT ;
    USE SIGNAL ;
    PORT
      LAYER M4 ;
        RECT  0 62.688 0.084 62.712 ;
    END
  END i_y[371]
  PIN i_y[372]
    DIRECTION INPUT ;
    USE SIGNAL ;
    PORT
      LAYER M4 ;
        RECT  0 62.832 0.084 62.856 ;
    END
  END i_y[372]
  PIN i_y[373]
    DIRECTION INPUT ;
    USE SIGNAL ;
    PORT
      LAYER M4 ;
        RECT  0 63.024 0.084 63.048 ;
    END
  END i_y[373]
  PIN i_y[374]
    DIRECTION INPUT ;
    USE SIGNAL ;
    PORT
      LAYER M4 ;
        RECT  0 63.168 0.084 63.192 ;
    END
  END i_y[374]
  PIN i_y[375]
    DIRECTION INPUT ;
    USE SIGNAL ;
    PORT
      LAYER M4 ;
        RECT  0 63.36 0.084 63.384 ;
    END
  END i_y[375]
  PIN i_y[376]
    DIRECTION INPUT ;
    USE SIGNAL ;
    PORT
      LAYER M4 ;
        RECT  0 63.504 0.084 63.528 ;
    END
  END i_y[376]
  PIN i_y[377]
    DIRECTION INPUT ;
    USE SIGNAL ;
    PORT
      LAYER M4 ;
        RECT  0 63.696 0.084 63.72 ;
    END
  END i_y[377]
  PIN i_y[378]
    DIRECTION INPUT ;
    USE SIGNAL ;
    PORT
      LAYER M4 ;
        RECT  0 63.84 0.084 63.864 ;
    END
  END i_y[378]
  PIN i_y[379]
    DIRECTION INPUT ;
    USE SIGNAL ;
    PORT
      LAYER M4 ;
        RECT  0 64.032 0.084 64.056 ;
    END
  END i_y[379]
  PIN i_y[37]
    DIRECTION INPUT ;
    USE SIGNAL ;
    PORT
      LAYER M4 ;
        RECT  0 6.336 0.084 6.36 ;
    END
  END i_y[37]
  PIN i_y[380]
    DIRECTION INPUT ;
    USE SIGNAL ;
    PORT
      LAYER M4 ;
        RECT  0 64.176 0.084 64.2 ;
    END
  END i_y[380]
  PIN i_y[381]
    DIRECTION INPUT ;
    USE SIGNAL ;
    PORT
      LAYER M4 ;
        RECT  0 64.368 0.084 64.392 ;
    END
  END i_y[381]
  PIN i_y[382]
    DIRECTION INPUT ;
    USE SIGNAL ;
    PORT
      LAYER M4 ;
        RECT  0 64.512 0.084 64.536 ;
    END
  END i_y[382]
  PIN i_y[383]
    DIRECTION INPUT ;
    USE SIGNAL ;
    PORT
      LAYER M4 ;
        RECT  0 64.704 0.084 64.728 ;
    END
  END i_y[383]
  PIN i_y[384]
    DIRECTION INPUT ;
    USE SIGNAL ;
    PORT
      LAYER M4 ;
        RECT  0 64.896 0.084 64.92 ;
    END
  END i_y[384]
  PIN i_y[385]
    DIRECTION INPUT ;
    USE SIGNAL ;
    PORT
      LAYER M4 ;
        RECT  0 65.04 0.084 65.064 ;
    END
  END i_y[385]
  PIN i_y[386]
    DIRECTION INPUT ;
    USE SIGNAL ;
    PORT
      LAYER M4 ;
        RECT  0 65.232 0.084 65.256 ;
    END
  END i_y[386]
  PIN i_y[387]
    DIRECTION INPUT ;
    USE SIGNAL ;
    PORT
      LAYER M4 ;
        RECT  0 65.376 0.084 65.4 ;
    END
  END i_y[387]
  PIN i_y[388]
    DIRECTION INPUT ;
    USE SIGNAL ;
    PORT
      LAYER M4 ;
        RECT  0 65.568 0.084 65.592 ;
    END
  END i_y[388]
  PIN i_y[389]
    DIRECTION INPUT ;
    USE SIGNAL ;
    PORT
      LAYER M4 ;
        RECT  0 65.712 0.084 65.736 ;
    END
  END i_y[389]
  PIN i_y[38]
    DIRECTION INPUT ;
    USE SIGNAL ;
    PORT
      LAYER M4 ;
        RECT  0 6.48 0.084 6.504 ;
    END
  END i_y[38]
  PIN i_y[390]
    DIRECTION INPUT ;
    USE SIGNAL ;
    PORT
      LAYER M4 ;
        RECT  0 65.904 0.084 65.928 ;
    END
  END i_y[390]
  PIN i_y[391]
    DIRECTION INPUT ;
    USE SIGNAL ;
    PORT
      LAYER M4 ;
        RECT  0 66.048 0.084 66.072 ;
    END
  END i_y[391]
  PIN i_y[392]
    DIRECTION INPUT ;
    USE SIGNAL ;
    PORT
      LAYER M4 ;
        RECT  0 66.24 0.084 66.264 ;
    END
  END i_y[392]
  PIN i_y[393]
    DIRECTION INPUT ;
    USE SIGNAL ;
    PORT
      LAYER M4 ;
        RECT  0 66.384 0.084 66.408 ;
    END
  END i_y[393]
  PIN i_y[394]
    DIRECTION INPUT ;
    USE SIGNAL ;
    PORT
      LAYER M4 ;
        RECT  0 66.576 0.084 66.6 ;
    END
  END i_y[394]
  PIN i_y[395]
    DIRECTION INPUT ;
    USE SIGNAL ;
    PORT
      LAYER M4 ;
        RECT  0 66.72 0.084 66.744 ;
    END
  END i_y[395]
  PIN i_y[396]
    DIRECTION INPUT ;
    USE SIGNAL ;
    PORT
      LAYER M4 ;
        RECT  0 66.912 0.084 66.936 ;
    END
  END i_y[396]
  PIN i_y[397]
    DIRECTION INPUT ;
    USE SIGNAL ;
    PORT
      LAYER M4 ;
        RECT  0 67.056 0.084 67.08 ;
    END
  END i_y[397]
  PIN i_y[398]
    DIRECTION INPUT ;
    USE SIGNAL ;
    PORT
      LAYER M4 ;
        RECT  0 67.248 0.084 67.272 ;
    END
  END i_y[398]
  PIN i_y[399]
    DIRECTION INPUT ;
    USE SIGNAL ;
    PORT
      LAYER M4 ;
        RECT  0 67.392 0.084 67.416 ;
    END
  END i_y[399]
  PIN i_y[39]
    DIRECTION INPUT ;
    USE SIGNAL ;
    PORT
      LAYER M4 ;
        RECT  0 6.672 0.084 6.696 ;
    END
  END i_y[39]
  PIN i_y[3]
    DIRECTION INPUT ;
    USE SIGNAL ;
    PORT
      LAYER M4 ;
        RECT  0 0.576 0.084 0.6 ;
    END
  END i_y[3]
  PIN i_y[400]
    DIRECTION INPUT ;
    USE SIGNAL ;
    PORT
      LAYER M4 ;
        RECT  0 67.584 0.084 67.608 ;
    END
  END i_y[400]
  PIN i_y[401]
    DIRECTION INPUT ;
    USE SIGNAL ;
    PORT
      LAYER M4 ;
        RECT  0 67.728 0.084 67.752 ;
    END
  END i_y[401]
  PIN i_y[402]
    DIRECTION INPUT ;
    USE SIGNAL ;
    PORT
      LAYER M4 ;
        RECT  0 67.92 0.084 67.944 ;
    END
  END i_y[402]
  PIN i_y[403]
    DIRECTION INPUT ;
    USE SIGNAL ;
    PORT
      LAYER M4 ;
        RECT  0 68.064 0.084 68.088 ;
    END
  END i_y[403]
  PIN i_y[404]
    DIRECTION INPUT ;
    USE SIGNAL ;
    PORT
      LAYER M4 ;
        RECT  0 68.256 0.084 68.28 ;
    END
  END i_y[404]
  PIN i_y[405]
    DIRECTION INPUT ;
    USE SIGNAL ;
    PORT
      LAYER M4 ;
        RECT  0 68.4 0.084 68.424 ;
    END
  END i_y[405]
  PIN i_y[406]
    DIRECTION INPUT ;
    USE SIGNAL ;
    PORT
      LAYER M4 ;
        RECT  0 68.592 0.084 68.616 ;
    END
  END i_y[406]
  PIN i_y[407]
    DIRECTION INPUT ;
    USE SIGNAL ;
    PORT
      LAYER M4 ;
        RECT  0 68.736 0.084 68.76 ;
    END
  END i_y[407]
  PIN i_y[408]
    DIRECTION INPUT ;
    USE SIGNAL ;
    PORT
      LAYER M4 ;
        RECT  0 68.928 0.084 68.952 ;
    END
  END i_y[408]
  PIN i_y[409]
    DIRECTION INPUT ;
    USE SIGNAL ;
    PORT
      LAYER M4 ;
        RECT  0 69.072 0.084 69.096 ;
    END
  END i_y[409]
  PIN i_y[40]
    DIRECTION INPUT ;
    USE SIGNAL ;
    PORT
      LAYER M4 ;
        RECT  0 6.816 0.084 6.84 ;
    END
  END i_y[40]
  PIN i_y[410]
    DIRECTION INPUT ;
    USE SIGNAL ;
    PORT
      LAYER M4 ;
        RECT  0 69.264 0.084 69.288 ;
    END
  END i_y[410]
  PIN i_y[411]
    DIRECTION INPUT ;
    USE SIGNAL ;
    PORT
      LAYER M4 ;
        RECT  0 69.408 0.084 69.432 ;
    END
  END i_y[411]
  PIN i_y[412]
    DIRECTION INPUT ;
    USE SIGNAL ;
    PORT
      LAYER M4 ;
        RECT  0 69.6 0.084 69.624 ;
    END
  END i_y[412]
  PIN i_y[413]
    DIRECTION INPUT ;
    USE SIGNAL ;
    PORT
      LAYER M4 ;
        RECT  0 69.744 0.084 69.768 ;
    END
  END i_y[413]
  PIN i_y[414]
    DIRECTION INPUT ;
    USE SIGNAL ;
    PORT
      LAYER M4 ;
        RECT  0 69.936 0.084 69.96 ;
    END
  END i_y[414]
  PIN i_y[415]
    DIRECTION INPUT ;
    USE SIGNAL ;
    PORT
      LAYER M4 ;
        RECT  0 70.128 0.084 70.152 ;
    END
  END i_y[415]
  PIN i_y[416]
    DIRECTION INPUT ;
    USE SIGNAL ;
    PORT
      LAYER M4 ;
        RECT  0 70.272 0.084 70.296 ;
    END
  END i_y[416]
  PIN i_y[417]
    DIRECTION INPUT ;
    USE SIGNAL ;
    PORT
      LAYER M4 ;
        RECT  0 70.464 0.084 70.488 ;
    END
  END i_y[417]
  PIN i_y[418]
    DIRECTION INPUT ;
    USE SIGNAL ;
    PORT
      LAYER M4 ;
        RECT  0 70.608 0.084 70.632 ;
    END
  END i_y[418]
  PIN i_y[419]
    DIRECTION INPUT ;
    USE SIGNAL ;
    PORT
      LAYER M4 ;
        RECT  0 70.8 0.084 70.824 ;
    END
  END i_y[419]
  PIN i_y[41]
    DIRECTION INPUT ;
    USE SIGNAL ;
    PORT
      LAYER M4 ;
        RECT  0 7.008 0.084 7.032 ;
    END
  END i_y[41]
  PIN i_y[420]
    DIRECTION INPUT ;
    USE SIGNAL ;
    PORT
      LAYER M4 ;
        RECT  0 70.944 0.084 70.968 ;
    END
  END i_y[420]
  PIN i_y[421]
    DIRECTION INPUT ;
    USE SIGNAL ;
    PORT
      LAYER M4 ;
        RECT  0 71.136 0.084 71.16 ;
    END
  END i_y[421]
  PIN i_y[422]
    DIRECTION INPUT ;
    USE SIGNAL ;
    PORT
      LAYER M4 ;
        RECT  0 71.28 0.084 71.304 ;
    END
  END i_y[422]
  PIN i_y[423]
    DIRECTION INPUT ;
    USE SIGNAL ;
    PORT
      LAYER M4 ;
        RECT  0 71.472 0.084 71.496 ;
    END
  END i_y[423]
  PIN i_y[424]
    DIRECTION INPUT ;
    USE SIGNAL ;
    PORT
      LAYER M4 ;
        RECT  0 71.616 0.084 71.64 ;
    END
  END i_y[424]
  PIN i_y[425]
    DIRECTION INPUT ;
    USE SIGNAL ;
    PORT
      LAYER M4 ;
        RECT  0 71.808 0.084 71.832 ;
    END
  END i_y[425]
  PIN i_y[426]
    DIRECTION INPUT ;
    USE SIGNAL ;
    PORT
      LAYER M4 ;
        RECT  0 71.952 0.084 71.976 ;
    END
  END i_y[426]
  PIN i_y[427]
    DIRECTION INPUT ;
    USE SIGNAL ;
    PORT
      LAYER M4 ;
        RECT  0 72.144 0.084 72.168 ;
    END
  END i_y[427]
  PIN i_y[428]
    DIRECTION INPUT ;
    USE SIGNAL ;
    PORT
      LAYER M4 ;
        RECT  0 72.288 0.084 72.312 ;
    END
  END i_y[428]
  PIN i_y[429]
    DIRECTION INPUT ;
    USE SIGNAL ;
    PORT
      LAYER M4 ;
        RECT  0 72.48 0.084 72.504 ;
    END
  END i_y[429]
  PIN i_y[42]
    DIRECTION INPUT ;
    USE SIGNAL ;
    PORT
      LAYER M4 ;
        RECT  0 7.152 0.084 7.176 ;
    END
  END i_y[42]
  PIN i_y[430]
    DIRECTION INPUT ;
    USE SIGNAL ;
    PORT
      LAYER M4 ;
        RECT  0 72.624 0.084 72.648 ;
    END
  END i_y[430]
  PIN i_y[431]
    DIRECTION INPUT ;
    USE SIGNAL ;
    PORT
      LAYER M4 ;
        RECT  0 72.816 0.084 72.84 ;
    END
  END i_y[431]
  PIN i_y[432]
    DIRECTION INPUT ;
    USE SIGNAL ;
    PORT
      LAYER M4 ;
        RECT  0 72.96 0.084 72.984 ;
    END
  END i_y[432]
  PIN i_y[433]
    DIRECTION INPUT ;
    USE SIGNAL ;
    PORT
      LAYER M4 ;
        RECT  0 73.152 0.084 73.176 ;
    END
  END i_y[433]
  PIN i_y[434]
    DIRECTION INPUT ;
    USE SIGNAL ;
    PORT
      LAYER M4 ;
        RECT  0 73.296 0.084 73.32 ;
    END
  END i_y[434]
  PIN i_y[435]
    DIRECTION INPUT ;
    USE SIGNAL ;
    PORT
      LAYER M4 ;
        RECT  0 73.488 0.084 73.512 ;
    END
  END i_y[435]
  PIN i_y[436]
    DIRECTION INPUT ;
    USE SIGNAL ;
    PORT
      LAYER M4 ;
        RECT  0 73.632 0.084 73.656 ;
    END
  END i_y[436]
  PIN i_y[437]
    DIRECTION INPUT ;
    USE SIGNAL ;
    PORT
      LAYER M4 ;
        RECT  0 73.824 0.084 73.848 ;
    END
  END i_y[437]
  PIN i_y[438]
    DIRECTION INPUT ;
    USE SIGNAL ;
    PORT
      LAYER M4 ;
        RECT  0 73.968 0.084 73.992 ;
    END
  END i_y[438]
  PIN i_y[439]
    DIRECTION INPUT ;
    USE SIGNAL ;
    PORT
      LAYER M4 ;
        RECT  0 74.16 0.084 74.184 ;
    END
  END i_y[439]
  PIN i_y[43]
    DIRECTION INPUT ;
    USE SIGNAL ;
    PORT
      LAYER M4 ;
        RECT  0 7.344 0.084 7.368 ;
    END
  END i_y[43]
  PIN i_y[440]
    DIRECTION INPUT ;
    USE SIGNAL ;
    PORT
      LAYER M4 ;
        RECT  0 74.304 0.084 74.328 ;
    END
  END i_y[440]
  PIN i_y[441]
    DIRECTION INPUT ;
    USE SIGNAL ;
    PORT
      LAYER M4 ;
        RECT  0 74.496 0.084 74.52 ;
    END
  END i_y[441]
  PIN i_y[442]
    DIRECTION INPUT ;
    USE SIGNAL ;
    PORT
      LAYER M4 ;
        RECT  0 74.64 0.084 74.664 ;
    END
  END i_y[442]
  PIN i_y[443]
    DIRECTION INPUT ;
    USE SIGNAL ;
    PORT
      LAYER M4 ;
        RECT  0 74.832 0.084 74.856 ;
    END
  END i_y[443]
  PIN i_y[444]
    DIRECTION INPUT ;
    USE SIGNAL ;
    PORT
      LAYER M4 ;
        RECT  0 74.976 0.084 75 ;
    END
  END i_y[444]
  PIN i_y[445]
    DIRECTION INPUT ;
    USE SIGNAL ;
    PORT
      LAYER M4 ;
        RECT  0 75.168 0.084 75.192 ;
    END
  END i_y[445]
  PIN i_y[446]
    DIRECTION INPUT ;
    USE SIGNAL ;
    PORT
      LAYER M4 ;
        RECT  0 75.312 0.084 75.336 ;
    END
  END i_y[446]
  PIN i_y[447]
    DIRECTION INPUT ;
    USE SIGNAL ;
    PORT
      LAYER M4 ;
        RECT  0 75.504 0.084 75.528 ;
    END
  END i_y[447]
  PIN i_y[448]
    DIRECTION INPUT ;
    USE SIGNAL ;
    PORT
      LAYER M4 ;
        RECT  0 75.696 0.084 75.72 ;
    END
  END i_y[448]
  PIN i_y[449]
    DIRECTION INPUT ;
    USE SIGNAL ;
    PORT
      LAYER M4 ;
        RECT  0 75.84 0.084 75.864 ;
    END
  END i_y[449]
  PIN i_y[44]
    DIRECTION INPUT ;
    USE SIGNAL ;
    PORT
      LAYER M4 ;
        RECT  0 7.488 0.084 7.512 ;
    END
  END i_y[44]
  PIN i_y[450]
    DIRECTION INPUT ;
    USE SIGNAL ;
    PORT
      LAYER M4 ;
        RECT  0 76.032 0.084 76.056 ;
    END
  END i_y[450]
  PIN i_y[451]
    DIRECTION INPUT ;
    USE SIGNAL ;
    PORT
      LAYER M4 ;
        RECT  0 76.176 0.084 76.2 ;
    END
  END i_y[451]
  PIN i_y[452]
    DIRECTION INPUT ;
    USE SIGNAL ;
    PORT
      LAYER M4 ;
        RECT  0 76.368 0.084 76.392 ;
    END
  END i_y[452]
  PIN i_y[453]
    DIRECTION INPUT ;
    USE SIGNAL ;
    PORT
      LAYER M4 ;
        RECT  0 76.512 0.084 76.536 ;
    END
  END i_y[453]
  PIN i_y[454]
    DIRECTION INPUT ;
    USE SIGNAL ;
    PORT
      LAYER M4 ;
        RECT  0 76.704 0.084 76.728 ;
    END
  END i_y[454]
  PIN i_y[455]
    DIRECTION INPUT ;
    USE SIGNAL ;
    PORT
      LAYER M4 ;
        RECT  0 76.848 0.084 76.872 ;
    END
  END i_y[455]
  PIN i_y[456]
    DIRECTION INPUT ;
    USE SIGNAL ;
    PORT
      LAYER M4 ;
        RECT  0 77.04 0.084 77.064 ;
    END
  END i_y[456]
  PIN i_y[457]
    DIRECTION INPUT ;
    USE SIGNAL ;
    PORT
      LAYER M4 ;
        RECT  0 77.184 0.084 77.208 ;
    END
  END i_y[457]
  PIN i_y[458]
    DIRECTION INPUT ;
    USE SIGNAL ;
    PORT
      LAYER M4 ;
        RECT  0 77.376 0.084 77.4 ;
    END
  END i_y[458]
  PIN i_y[459]
    DIRECTION INPUT ;
    USE SIGNAL ;
    PORT
      LAYER M4 ;
        RECT  0 77.52 0.084 77.544 ;
    END
  END i_y[459]
  PIN i_y[45]
    DIRECTION INPUT ;
    USE SIGNAL ;
    PORT
      LAYER M4 ;
        RECT  0 7.68 0.084 7.704 ;
    END
  END i_y[45]
  PIN i_y[460]
    DIRECTION INPUT ;
    USE SIGNAL ;
    PORT
      LAYER M4 ;
        RECT  0 77.712 0.084 77.736 ;
    END
  END i_y[460]
  PIN i_y[461]
    DIRECTION INPUT ;
    USE SIGNAL ;
    PORT
      LAYER M4 ;
        RECT  0 77.856 0.084 77.88 ;
    END
  END i_y[461]
  PIN i_y[462]
    DIRECTION INPUT ;
    USE SIGNAL ;
    PORT
      LAYER M4 ;
        RECT  0 78.048 0.084 78.072 ;
    END
  END i_y[462]
  PIN i_y[463]
    DIRECTION INPUT ;
    USE SIGNAL ;
    PORT
      LAYER M4 ;
        RECT  0 78.192 0.084 78.216 ;
    END
  END i_y[463]
  PIN i_y[464]
    DIRECTION INPUT ;
    USE SIGNAL ;
    PORT
      LAYER M4 ;
        RECT  0 78.384 0.084 78.408 ;
    END
  END i_y[464]
  PIN i_y[465]
    DIRECTION INPUT ;
    USE SIGNAL ;
    PORT
      LAYER M4 ;
        RECT  0 78.528 0.084 78.552 ;
    END
  END i_y[465]
  PIN i_y[466]
    DIRECTION INPUT ;
    USE SIGNAL ;
    PORT
      LAYER M4 ;
        RECT  0 78.72 0.084 78.744 ;
    END
  END i_y[466]
  PIN i_y[467]
    DIRECTION INPUT ;
    USE SIGNAL ;
    PORT
      LAYER M4 ;
        RECT  0 78.864 0.084 78.888 ;
    END
  END i_y[467]
  PIN i_y[468]
    DIRECTION INPUT ;
    USE SIGNAL ;
    PORT
      LAYER M4 ;
        RECT  0 79.056 0.084 79.08 ;
    END
  END i_y[468]
  PIN i_y[469]
    DIRECTION INPUT ;
    USE SIGNAL ;
    PORT
      LAYER M4 ;
        RECT  0 79.2 0.084 79.224 ;
    END
  END i_y[469]
  PIN i_y[46]
    DIRECTION INPUT ;
    USE SIGNAL ;
    PORT
      LAYER M4 ;
        RECT  0 7.824 0.084 7.848 ;
    END
  END i_y[46]
  PIN i_y[470]
    DIRECTION INPUT ;
    USE SIGNAL ;
    PORT
      LAYER M4 ;
        RECT  0 79.392 0.084 79.416 ;
    END
  END i_y[470]
  PIN i_y[471]
    DIRECTION INPUT ;
    USE SIGNAL ;
    PORT
      LAYER M4 ;
        RECT  0 79.536 0.084 79.56 ;
    END
  END i_y[471]
  PIN i_y[472]
    DIRECTION INPUT ;
    USE SIGNAL ;
    PORT
      LAYER M4 ;
        RECT  0 79.728 0.084 79.752 ;
    END
  END i_y[472]
  PIN i_y[473]
    DIRECTION INPUT ;
    USE SIGNAL ;
    PORT
      LAYER M4 ;
        RECT  0 79.872 0.084 79.896 ;
    END
  END i_y[473]
  PIN i_y[474]
    DIRECTION INPUT ;
    USE SIGNAL ;
    PORT
      LAYER M4 ;
        RECT  0 80.064 0.084 80.088 ;
    END
  END i_y[474]
  PIN i_y[475]
    DIRECTION INPUT ;
    USE SIGNAL ;
    PORT
      LAYER M4 ;
        RECT  0 80.208 0.084 80.232 ;
    END
  END i_y[475]
  PIN i_y[476]
    DIRECTION INPUT ;
    USE SIGNAL ;
    PORT
      LAYER M4 ;
        RECT  0 80.4 0.084 80.424 ;
    END
  END i_y[476]
  PIN i_y[477]
    DIRECTION INPUT ;
    USE SIGNAL ;
    PORT
      LAYER M4 ;
        RECT  0 80.544 0.084 80.568 ;
    END
  END i_y[477]
  PIN i_y[478]
    DIRECTION INPUT ;
    USE SIGNAL ;
    PORT
      LAYER M4 ;
        RECT  0 80.736 0.084 80.76 ;
    END
  END i_y[478]
  PIN i_y[479]
    DIRECTION INPUT ;
    USE SIGNAL ;
    PORT
      LAYER M4 ;
        RECT  0 80.928 0.084 80.952 ;
    END
  END i_y[479]
  PIN i_y[47]
    DIRECTION INPUT ;
    USE SIGNAL ;
    PORT
      LAYER M4 ;
        RECT  0 8.016 0.084 8.04 ;
    END
  END i_y[47]
  PIN i_y[480]
    DIRECTION INPUT ;
    USE SIGNAL ;
    PORT
      LAYER M4 ;
        RECT  0 81.072 0.084 81.096 ;
    END
  END i_y[480]
  PIN i_y[481]
    DIRECTION INPUT ;
    USE SIGNAL ;
    PORT
      LAYER M4 ;
        RECT  0 81.264 0.084 81.288 ;
    END
  END i_y[481]
  PIN i_y[482]
    DIRECTION INPUT ;
    USE SIGNAL ;
    PORT
      LAYER M4 ;
        RECT  0 81.408 0.084 81.432 ;
    END
  END i_y[482]
  PIN i_y[483]
    DIRECTION INPUT ;
    USE SIGNAL ;
    PORT
      LAYER M4 ;
        RECT  0 81.6 0.084 81.624 ;
    END
  END i_y[483]
  PIN i_y[484]
    DIRECTION INPUT ;
    USE SIGNAL ;
    PORT
      LAYER M4 ;
        RECT  0 81.744 0.084 81.768 ;
    END
  END i_y[484]
  PIN i_y[485]
    DIRECTION INPUT ;
    USE SIGNAL ;
    PORT
      LAYER M4 ;
        RECT  0 81.936 0.084 81.96 ;
    END
  END i_y[485]
  PIN i_y[486]
    DIRECTION INPUT ;
    USE SIGNAL ;
    PORT
      LAYER M4 ;
        RECT  0 82.08 0.084 82.104 ;
    END
  END i_y[486]
  PIN i_y[487]
    DIRECTION INPUT ;
    USE SIGNAL ;
    PORT
      LAYER M4 ;
        RECT  0 82.272 0.084 82.296 ;
    END
  END i_y[487]
  PIN i_y[488]
    DIRECTION INPUT ;
    USE SIGNAL ;
    PORT
      LAYER M4 ;
        RECT  0 82.416 0.084 82.44 ;
    END
  END i_y[488]
  PIN i_y[489]
    DIRECTION INPUT ;
    USE SIGNAL ;
    PORT
      LAYER M4 ;
        RECT  0 82.608 0.084 82.632 ;
    END
  END i_y[489]
  PIN i_y[48]
    DIRECTION INPUT ;
    USE SIGNAL ;
    PORT
      LAYER M4 ;
        RECT  0 8.16 0.084 8.184 ;
    END
  END i_y[48]
  PIN i_y[490]
    DIRECTION INPUT ;
    USE SIGNAL ;
    PORT
      LAYER M4 ;
        RECT  0 82.752 0.084 82.776 ;
    END
  END i_y[490]
  PIN i_y[491]
    DIRECTION INPUT ;
    USE SIGNAL ;
    PORT
      LAYER M4 ;
        RECT  0 82.944 0.084 82.968 ;
    END
  END i_y[491]
  PIN i_y[492]
    DIRECTION INPUT ;
    USE SIGNAL ;
    PORT
      LAYER M4 ;
        RECT  0 83.088 0.084 83.112 ;
    END
  END i_y[492]
  PIN i_y[493]
    DIRECTION INPUT ;
    USE SIGNAL ;
    PORT
      LAYER M4 ;
        RECT  0 83.28 0.084 83.304 ;
    END
  END i_y[493]
  PIN i_y[494]
    DIRECTION INPUT ;
    USE SIGNAL ;
    PORT
      LAYER M4 ;
        RECT  0 83.424 0.084 83.448 ;
    END
  END i_y[494]
  PIN i_y[495]
    DIRECTION INPUT ;
    USE SIGNAL ;
    PORT
      LAYER M4 ;
        RECT  0 83.616 0.084 83.64 ;
    END
  END i_y[495]
  PIN i_y[496]
    DIRECTION INPUT ;
    USE SIGNAL ;
    PORT
      LAYER M4 ;
        RECT  0 83.76 0.084 83.784 ;
    END
  END i_y[496]
  PIN i_y[497]
    DIRECTION INPUT ;
    USE SIGNAL ;
    PORT
      LAYER M4 ;
        RECT  0 83.952 0.084 83.976 ;
    END
  END i_y[497]
  PIN i_y[498]
    DIRECTION INPUT ;
    USE SIGNAL ;
    PORT
      LAYER M4 ;
        RECT  0 84.096 0.084 84.12 ;
    END
  END i_y[498]
  PIN i_y[499]
    DIRECTION INPUT ;
    USE SIGNAL ;
    PORT
      LAYER M4 ;
        RECT  0 84.288 0.084 84.312 ;
    END
  END i_y[499]
  PIN i_y[49]
    DIRECTION INPUT ;
    USE SIGNAL ;
    PORT
      LAYER M4 ;
        RECT  0 8.352 0.084 8.376 ;
    END
  END i_y[49]
  PIN i_y[4]
    DIRECTION INPUT ;
    USE SIGNAL ;
    PORT
      LAYER M4 ;
        RECT  0 0.768 0.084 0.792 ;
    END
  END i_y[4]
  PIN i_y[500]
    DIRECTION INPUT ;
    USE SIGNAL ;
    PORT
      LAYER M4 ;
        RECT  0 84.432 0.084 84.456 ;
    END
  END i_y[500]
  PIN i_y[501]
    DIRECTION INPUT ;
    USE SIGNAL ;
    PORT
      LAYER M4 ;
        RECT  0 84.624 0.084 84.648 ;
    END
  END i_y[501]
  PIN i_y[502]
    DIRECTION INPUT ;
    USE SIGNAL ;
    PORT
      LAYER M4 ;
        RECT  0 84.768 0.084 84.792 ;
    END
  END i_y[502]
  PIN i_y[503]
    DIRECTION INPUT ;
    USE SIGNAL ;
    PORT
      LAYER M4 ;
        RECT  0 84.96 0.084 84.984 ;
    END
  END i_y[503]
  PIN i_y[504]
    DIRECTION INPUT ;
    USE SIGNAL ;
    PORT
      LAYER M4 ;
        RECT  0 85.104 0.084 85.128 ;
    END
  END i_y[504]
  PIN i_y[505]
    DIRECTION INPUT ;
    USE SIGNAL ;
    PORT
      LAYER M4 ;
        RECT  0 85.296 0.084 85.32 ;
    END
  END i_y[505]
  PIN i_y[506]
    DIRECTION INPUT ;
    USE SIGNAL ;
    PORT
      LAYER M4 ;
        RECT  0 85.44 0.084 85.464 ;
    END
  END i_y[506]
  PIN i_y[507]
    DIRECTION INPUT ;
    USE SIGNAL ;
    PORT
      LAYER M4 ;
        RECT  0 85.632 0.084 85.656 ;
    END
  END i_y[507]
  PIN i_y[508]
    DIRECTION INPUT ;
    USE SIGNAL ;
    PORT
      LAYER M4 ;
        RECT  0 85.776 0.084 85.8 ;
    END
  END i_y[508]
  PIN i_y[509]
    DIRECTION INPUT ;
    USE SIGNAL ;
    PORT
      LAYER M4 ;
        RECT  0 85.968 0.084 85.992 ;
    END
  END i_y[509]
  PIN i_y[50]
    DIRECTION INPUT ;
    USE SIGNAL ;
    PORT
      LAYER M4 ;
        RECT  0 8.496 0.084 8.52 ;
    END
  END i_y[50]
  PIN i_y[510]
    DIRECTION INPUT ;
    USE SIGNAL ;
    PORT
      LAYER M4 ;
        RECT  0 86.112 0.084 86.136 ;
    END
  END i_y[510]
  PIN i_y[511]
    DIRECTION INPUT ;
    USE SIGNAL ;
    PORT
      LAYER M4 ;
        RECT  0 86.304 0.084 86.328 ;
    END
  END i_y[511]
  PIN i_y[51]
    DIRECTION INPUT ;
    USE SIGNAL ;
    PORT
      LAYER M4 ;
        RECT  0 8.688 0.084 8.712 ;
    END
  END i_y[51]
  PIN i_y[52]
    DIRECTION INPUT ;
    USE SIGNAL ;
    PORT
      LAYER M4 ;
        RECT  0 8.832 0.084 8.856 ;
    END
  END i_y[52]
  PIN i_y[53]
    DIRECTION INPUT ;
    USE SIGNAL ;
    PORT
      LAYER M4 ;
        RECT  0 9.024 0.084 9.048 ;
    END
  END i_y[53]
  PIN i_y[54]
    DIRECTION INPUT ;
    USE SIGNAL ;
    PORT
      LAYER M4 ;
        RECT  0 9.168 0.084 9.192 ;
    END
  END i_y[54]
  PIN i_y[55]
    DIRECTION INPUT ;
    USE SIGNAL ;
    PORT
      LAYER M4 ;
        RECT  0 9.36 0.084 9.384 ;
    END
  END i_y[55]
  PIN i_y[56]
    DIRECTION INPUT ;
    USE SIGNAL ;
    PORT
      LAYER M4 ;
        RECT  0 9.504 0.084 9.528 ;
    END
  END i_y[56]
  PIN i_y[57]
    DIRECTION INPUT ;
    USE SIGNAL ;
    PORT
      LAYER M4 ;
        RECT  0 9.696 0.084 9.72 ;
    END
  END i_y[57]
  PIN i_y[58]
    DIRECTION INPUT ;
    USE SIGNAL ;
    PORT
      LAYER M4 ;
        RECT  0 9.84 0.084 9.864 ;
    END
  END i_y[58]
  PIN i_y[59]
    DIRECTION INPUT ;
    USE SIGNAL ;
    PORT
      LAYER M4 ;
        RECT  0 10.032 0.084 10.056 ;
    END
  END i_y[59]
  PIN i_y[5]
    DIRECTION INPUT ;
    USE SIGNAL ;
    PORT
      LAYER M4 ;
        RECT  0 0.912 0.084 0.936 ;
    END
  END i_y[5]
  PIN i_y[60]
    DIRECTION INPUT ;
    USE SIGNAL ;
    PORT
      LAYER M4 ;
        RECT  0 10.176 0.084 10.2 ;
    END
  END i_y[60]
  PIN i_y[61]
    DIRECTION INPUT ;
    USE SIGNAL ;
    PORT
      LAYER M4 ;
        RECT  0 10.368 0.084 10.392 ;
    END
  END i_y[61]
  PIN i_y[62]
    DIRECTION INPUT ;
    USE SIGNAL ;
    PORT
      LAYER M4 ;
        RECT  0 10.512 0.084 10.536 ;
    END
  END i_y[62]
  PIN i_y[63]
    DIRECTION INPUT ;
    USE SIGNAL ;
    PORT
      LAYER M4 ;
        RECT  0 10.704 0.084 10.728 ;
    END
  END i_y[63]
  PIN i_y[64]
    DIRECTION INPUT ;
    USE SIGNAL ;
    PORT
      LAYER M4 ;
        RECT  0 10.896 0.084 10.92 ;
    END
  END i_y[64]
  PIN i_y[65]
    DIRECTION INPUT ;
    USE SIGNAL ;
    PORT
      LAYER M4 ;
        RECT  0 11.04 0.084 11.064 ;
    END
  END i_y[65]
  PIN i_y[66]
    DIRECTION INPUT ;
    USE SIGNAL ;
    PORT
      LAYER M4 ;
        RECT  0 11.232 0.084 11.256 ;
    END
  END i_y[66]
  PIN i_y[67]
    DIRECTION INPUT ;
    USE SIGNAL ;
    PORT
      LAYER M4 ;
        RECT  0 11.376 0.084 11.4 ;
    END
  END i_y[67]
  PIN i_y[68]
    DIRECTION INPUT ;
    USE SIGNAL ;
    PORT
      LAYER M4 ;
        RECT  0 11.568 0.084 11.592 ;
    END
  END i_y[68]
  PIN i_y[69]
    DIRECTION INPUT ;
    USE SIGNAL ;
    PORT
      LAYER M4 ;
        RECT  0 11.712 0.084 11.736 ;
    END
  END i_y[69]
  PIN i_y[6]
    DIRECTION INPUT ;
    USE SIGNAL ;
    PORT
      LAYER M4 ;
        RECT  0 1.104 0.084 1.128 ;
    END
  END i_y[6]
  PIN i_y[70]
    DIRECTION INPUT ;
    USE SIGNAL ;
    PORT
      LAYER M4 ;
        RECT  0 11.904 0.084 11.928 ;
    END
  END i_y[70]
  PIN i_y[71]
    DIRECTION INPUT ;
    USE SIGNAL ;
    PORT
      LAYER M4 ;
        RECT  0 12.048 0.084 12.072 ;
    END
  END i_y[71]
  PIN i_y[72]
    DIRECTION INPUT ;
    USE SIGNAL ;
    PORT
      LAYER M4 ;
        RECT  0 12.24 0.084 12.264 ;
    END
  END i_y[72]
  PIN i_y[73]
    DIRECTION INPUT ;
    USE SIGNAL ;
    PORT
      LAYER M4 ;
        RECT  0 12.384 0.084 12.408 ;
    END
  END i_y[73]
  PIN i_y[74]
    DIRECTION INPUT ;
    USE SIGNAL ;
    PORT
      LAYER M4 ;
        RECT  0 12.576 0.084 12.6 ;
    END
  END i_y[74]
  PIN i_y[75]
    DIRECTION INPUT ;
    USE SIGNAL ;
    PORT
      LAYER M4 ;
        RECT  0 12.72 0.084 12.744 ;
    END
  END i_y[75]
  PIN i_y[76]
    DIRECTION INPUT ;
    USE SIGNAL ;
    PORT
      LAYER M4 ;
        RECT  0 12.912 0.084 12.936 ;
    END
  END i_y[76]
  PIN i_y[77]
    DIRECTION INPUT ;
    USE SIGNAL ;
    PORT
      LAYER M4 ;
        RECT  0 13.056 0.084 13.08 ;
    END
  END i_y[77]
  PIN i_y[78]
    DIRECTION INPUT ;
    USE SIGNAL ;
    PORT
      LAYER M4 ;
        RECT  0 13.248 0.084 13.272 ;
    END
  END i_y[78]
  PIN i_y[79]
    DIRECTION INPUT ;
    USE SIGNAL ;
    PORT
      LAYER M4 ;
        RECT  0 13.392 0.084 13.416 ;
    END
  END i_y[79]
  PIN i_y[7]
    DIRECTION INPUT ;
    USE SIGNAL ;
    PORT
      LAYER M4 ;
        RECT  0 1.248 0.084 1.272 ;
    END
  END i_y[7]
  PIN i_y[80]
    DIRECTION INPUT ;
    USE SIGNAL ;
    PORT
      LAYER M4 ;
        RECT  0 13.584 0.084 13.608 ;
    END
  END i_y[80]
  PIN i_y[81]
    DIRECTION INPUT ;
    USE SIGNAL ;
    PORT
      LAYER M4 ;
        RECT  0 13.728 0.084 13.752 ;
    END
  END i_y[81]
  PIN i_y[82]
    DIRECTION INPUT ;
    USE SIGNAL ;
    PORT
      LAYER M4 ;
        RECT  0 13.92 0.084 13.944 ;
    END
  END i_y[82]
  PIN i_y[83]
    DIRECTION INPUT ;
    USE SIGNAL ;
    PORT
      LAYER M4 ;
        RECT  0 14.064 0.084 14.088 ;
    END
  END i_y[83]
  PIN i_y[84]
    DIRECTION INPUT ;
    USE SIGNAL ;
    PORT
      LAYER M4 ;
        RECT  0 14.256 0.084 14.28 ;
    END
  END i_y[84]
  PIN i_y[85]
    DIRECTION INPUT ;
    USE SIGNAL ;
    PORT
      LAYER M4 ;
        RECT  0 14.4 0.084 14.424 ;
    END
  END i_y[85]
  PIN i_y[86]
    DIRECTION INPUT ;
    USE SIGNAL ;
    PORT
      LAYER M4 ;
        RECT  0 14.592 0.084 14.616 ;
    END
  END i_y[86]
  PIN i_y[87]
    DIRECTION INPUT ;
    USE SIGNAL ;
    PORT
      LAYER M4 ;
        RECT  0 14.736 0.084 14.76 ;
    END
  END i_y[87]
  PIN i_y[88]
    DIRECTION INPUT ;
    USE SIGNAL ;
    PORT
      LAYER M4 ;
        RECT  0 14.928 0.084 14.952 ;
    END
  END i_y[88]
  PIN i_y[89]
    DIRECTION INPUT ;
    USE SIGNAL ;
    PORT
      LAYER M4 ;
        RECT  0 15.072 0.084 15.096 ;
    END
  END i_y[89]
  PIN i_y[8]
    DIRECTION INPUT ;
    USE SIGNAL ;
    PORT
      LAYER M4 ;
        RECT  0 1.44 0.084 1.464 ;
    END
  END i_y[8]
  PIN i_y[90]
    DIRECTION INPUT ;
    USE SIGNAL ;
    PORT
      LAYER M4 ;
        RECT  0 15.264 0.084 15.288 ;
    END
  END i_y[90]
  PIN i_y[91]
    DIRECTION INPUT ;
    USE SIGNAL ;
    PORT
      LAYER M4 ;
        RECT  0 15.408 0.084 15.432 ;
    END
  END i_y[91]
  PIN i_y[92]
    DIRECTION INPUT ;
    USE SIGNAL ;
    PORT
      LAYER M4 ;
        RECT  0 15.6 0.084 15.624 ;
    END
  END i_y[92]
  PIN i_y[93]
    DIRECTION INPUT ;
    USE SIGNAL ;
    PORT
      LAYER M4 ;
        RECT  0 15.744 0.084 15.768 ;
    END
  END i_y[93]
  PIN i_y[94]
    DIRECTION INPUT ;
    USE SIGNAL ;
    PORT
      LAYER M4 ;
        RECT  0 15.936 0.084 15.96 ;
    END
  END i_y[94]
  PIN i_y[95]
    DIRECTION INPUT ;
    USE SIGNAL ;
    PORT
      LAYER M4 ;
        RECT  0 16.128 0.084 16.152 ;
    END
  END i_y[95]
  PIN i_y[96]
    DIRECTION INPUT ;
    USE SIGNAL ;
    PORT
      LAYER M4 ;
        RECT  0 16.272 0.084 16.296 ;
    END
  END i_y[96]
  PIN i_y[97]
    DIRECTION INPUT ;
    USE SIGNAL ;
    PORT
      LAYER M4 ;
        RECT  0 16.464 0.084 16.488 ;
    END
  END i_y[97]
  PIN i_y[98]
    DIRECTION INPUT ;
    USE SIGNAL ;
    PORT
      LAYER M4 ;
        RECT  0 16.608 0.084 16.632 ;
    END
  END i_y[98]
  PIN i_y[99]
    DIRECTION INPUT ;
    USE SIGNAL ;
    PORT
      LAYER M4 ;
        RECT  0 16.8 0.084 16.824 ;
    END
  END i_y[99]
  PIN i_y[9]
    DIRECTION INPUT ;
    USE SIGNAL ;
    PORT
      LAYER M4 ;
        RECT  0 1.584 0.084 1.608 ;
    END
  END i_y[9]
  PIN o_sec[0]
    DIRECTION OUTPUT ;
    USE SIGNAL ;
    PORT
      LAYER M4 ;
        RECT  43.116 0.048 43.2 0.072 ;
    END
  END o_sec[0]
  PIN o_sec[100]
    DIRECTION OUTPUT ;
    USE SIGNAL ;
    PORT
      LAYER M4 ;
        RECT  43.116 12.912 43.2 12.936 ;
    END
  END o_sec[100]
  PIN o_sec[101]
    DIRECTION OUTPUT ;
    USE SIGNAL ;
    PORT
      LAYER M4 ;
        RECT  43.116 13.056 43.2 13.08 ;
    END
  END o_sec[101]
  PIN o_sec[102]
    DIRECTION OUTPUT ;
    USE SIGNAL ;
    PORT
      LAYER M4 ;
        RECT  43.116 13.152 43.2 13.176 ;
    END
  END o_sec[102]
  PIN o_sec[103]
    DIRECTION OUTPUT ;
    USE SIGNAL ;
    PORT
      LAYER M4 ;
        RECT  43.116 13.296 43.2 13.32 ;
    END
  END o_sec[103]
  PIN o_sec[104]
    DIRECTION OUTPUT ;
    USE SIGNAL ;
    PORT
      LAYER M4 ;
        RECT  43.116 13.44 43.2 13.464 ;
    END
  END o_sec[104]
  PIN o_sec[105]
    DIRECTION OUTPUT ;
    USE SIGNAL ;
    PORT
      LAYER M4 ;
        RECT  43.116 13.536 43.2 13.56 ;
    END
  END o_sec[105]
  PIN o_sec[106]
    DIRECTION OUTPUT ;
    USE SIGNAL ;
    PORT
      LAYER M4 ;
        RECT  43.116 13.68 43.2 13.704 ;
    END
  END o_sec[106]
  PIN o_sec[107]
    DIRECTION OUTPUT ;
    USE SIGNAL ;
    PORT
      LAYER M4 ;
        RECT  43.116 13.824 43.2 13.848 ;
    END
  END o_sec[107]
  PIN o_sec[108]
    DIRECTION OUTPUT ;
    USE SIGNAL ;
    PORT
      LAYER M4 ;
        RECT  43.116 13.92 43.2 13.944 ;
    END
  END o_sec[108]
  PIN o_sec[109]
    DIRECTION OUTPUT ;
    USE SIGNAL ;
    PORT
      LAYER M4 ;
        RECT  43.116 14.064 43.2 14.088 ;
    END
  END o_sec[109]
  PIN o_sec[10]
    DIRECTION OUTPUT ;
    USE SIGNAL ;
    PORT
      LAYER M4 ;
        RECT  43.116 1.344 43.2 1.368 ;
    END
  END o_sec[10]
  PIN o_sec[110]
    DIRECTION OUTPUT ;
    USE SIGNAL ;
    PORT
      LAYER M4 ;
        RECT  43.116 14.208 43.2 14.232 ;
    END
  END o_sec[110]
  PIN o_sec[111]
    DIRECTION OUTPUT ;
    USE SIGNAL ;
    PORT
      LAYER M4 ;
        RECT  43.116 14.304 43.2 14.328 ;
    END
  END o_sec[111]
  PIN o_sec[112]
    DIRECTION OUTPUT ;
    USE SIGNAL ;
    PORT
      LAYER M4 ;
        RECT  43.116 14.448 43.2 14.472 ;
    END
  END o_sec[112]
  PIN o_sec[113]
    DIRECTION OUTPUT ;
    USE SIGNAL ;
    PORT
      LAYER M4 ;
        RECT  43.116 14.592 43.2 14.616 ;
    END
  END o_sec[113]
  PIN o_sec[114]
    DIRECTION OUTPUT ;
    USE SIGNAL ;
    PORT
      LAYER M4 ;
        RECT  43.116 14.688 43.2 14.712 ;
    END
  END o_sec[114]
  PIN o_sec[115]
    DIRECTION OUTPUT ;
    USE SIGNAL ;
    PORT
      LAYER M4 ;
        RECT  43.116 14.832 43.2 14.856 ;
    END
  END o_sec[115]
  PIN o_sec[116]
    DIRECTION OUTPUT ;
    USE SIGNAL ;
    PORT
      LAYER M4 ;
        RECT  43.116 14.976 43.2 15 ;
    END
  END o_sec[116]
  PIN o_sec[117]
    DIRECTION OUTPUT ;
    USE SIGNAL ;
    PORT
      LAYER M4 ;
        RECT  43.116 15.072 43.2 15.096 ;
    END
  END o_sec[117]
  PIN o_sec[118]
    DIRECTION OUTPUT ;
    USE SIGNAL ;
    PORT
      LAYER M4 ;
        RECT  43.116 15.216 43.2 15.24 ;
    END
  END o_sec[118]
  PIN o_sec[119]
    DIRECTION OUTPUT ;
    USE SIGNAL ;
    PORT
      LAYER M4 ;
        RECT  43.116 15.36 43.2 15.384 ;
    END
  END o_sec[119]
  PIN o_sec[11]
    DIRECTION OUTPUT ;
    USE SIGNAL ;
    PORT
      LAYER M4 ;
        RECT  43.116 1.488 43.2 1.512 ;
    END
  END o_sec[11]
  PIN o_sec[12]
    DIRECTION OUTPUT ;
    USE SIGNAL ;
    PORT
      LAYER M4 ;
        RECT  43.116 1.584 43.2 1.608 ;
    END
  END o_sec[12]
  PIN o_sec[13]
    DIRECTION OUTPUT ;
    USE SIGNAL ;
    PORT
      LAYER M4 ;
        RECT  43.116 1.728 43.2 1.752 ;
    END
  END o_sec[13]
  PIN o_sec[14]
    DIRECTION OUTPUT ;
    USE SIGNAL ;
    PORT
      LAYER M4 ;
        RECT  43.116 1.872 43.2 1.896 ;
    END
  END o_sec[14]
  PIN o_sec[15]
    DIRECTION OUTPUT ;
    USE SIGNAL ;
    PORT
      LAYER M4 ;
        RECT  43.116 1.968 43.2 1.992 ;
    END
  END o_sec[15]
  PIN o_sec[16]
    DIRECTION OUTPUT ;
    USE SIGNAL ;
    PORT
      LAYER M4 ;
        RECT  43.116 2.112 43.2 2.136 ;
    END
  END o_sec[16]
  PIN o_sec[17]
    DIRECTION OUTPUT ;
    USE SIGNAL ;
    PORT
      LAYER M4 ;
        RECT  43.116 2.256 43.2 2.28 ;
    END
  END o_sec[17]
  PIN o_sec[18]
    DIRECTION OUTPUT ;
    USE SIGNAL ;
    PORT
      LAYER M4 ;
        RECT  43.116 2.352 43.2 2.376 ;
    END
  END o_sec[18]
  PIN o_sec[19]
    DIRECTION OUTPUT ;
    USE SIGNAL ;
    PORT
      LAYER M4 ;
        RECT  43.116 2.496 43.2 2.52 ;
    END
  END o_sec[19]
  PIN o_sec[1]
    DIRECTION OUTPUT ;
    USE SIGNAL ;
    PORT
      LAYER M4 ;
        RECT  43.116 0.192 43.2 0.216 ;
    END
  END o_sec[1]
  PIN o_sec[20]
    DIRECTION OUTPUT ;
    USE SIGNAL ;
    PORT
      LAYER M4 ;
        RECT  43.116 2.64 43.2 2.664 ;
    END
  END o_sec[20]
  PIN o_sec[21]
    DIRECTION OUTPUT ;
    USE SIGNAL ;
    PORT
      LAYER M4 ;
        RECT  43.116 2.736 43.2 2.76 ;
    END
  END o_sec[21]
  PIN o_sec[22]
    DIRECTION OUTPUT ;
    USE SIGNAL ;
    PORT
      LAYER M4 ;
        RECT  43.116 2.88 43.2 2.904 ;
    END
  END o_sec[22]
  PIN o_sec[23]
    DIRECTION OUTPUT ;
    USE SIGNAL ;
    PORT
      LAYER M4 ;
        RECT  43.116 3.024 43.2 3.048 ;
    END
  END o_sec[23]
  PIN o_sec[24]
    DIRECTION OUTPUT ;
    USE SIGNAL ;
    PORT
      LAYER M4 ;
        RECT  43.116 3.12 43.2 3.144 ;
    END
  END o_sec[24]
  PIN o_sec[25]
    DIRECTION OUTPUT ;
    USE SIGNAL ;
    PORT
      LAYER M4 ;
        RECT  43.116 3.264 43.2 3.288 ;
    END
  END o_sec[25]
  PIN o_sec[26]
    DIRECTION OUTPUT ;
    USE SIGNAL ;
    PORT
      LAYER M4 ;
        RECT  43.116 3.408 43.2 3.432 ;
    END
  END o_sec[26]
  PIN o_sec[27]
    DIRECTION OUTPUT ;
    USE SIGNAL ;
    PORT
      LAYER M4 ;
        RECT  43.116 3.504 43.2 3.528 ;
    END
  END o_sec[27]
  PIN o_sec[28]
    DIRECTION OUTPUT ;
    USE SIGNAL ;
    PORT
      LAYER M4 ;
        RECT  43.116 3.648 43.2 3.672 ;
    END
  END o_sec[28]
  PIN o_sec[29]
    DIRECTION OUTPUT ;
    USE SIGNAL ;
    PORT
      LAYER M4 ;
        RECT  43.116 3.792 43.2 3.816 ;
    END
  END o_sec[29]
  PIN o_sec[2]
    DIRECTION OUTPUT ;
    USE SIGNAL ;
    PORT
      LAYER M4 ;
        RECT  43.116 0.288 43.2 0.312 ;
    END
  END o_sec[2]
  PIN o_sec[30]
    DIRECTION OUTPUT ;
    USE SIGNAL ;
    PORT
      LAYER M4 ;
        RECT  43.116 3.888 43.2 3.912 ;
    END
  END o_sec[30]
  PIN o_sec[31]
    DIRECTION OUTPUT ;
    USE SIGNAL ;
    PORT
      LAYER M4 ;
        RECT  43.116 4.032 43.2 4.056 ;
    END
  END o_sec[31]
  PIN o_sec[32]
    DIRECTION OUTPUT ;
    USE SIGNAL ;
    PORT
      LAYER M4 ;
        RECT  43.116 4.176 43.2 4.2 ;
    END
  END o_sec[32]
  PIN o_sec[33]
    DIRECTION OUTPUT ;
    USE SIGNAL ;
    PORT
      LAYER M4 ;
        RECT  43.116 4.272 43.2 4.296 ;
    END
  END o_sec[33]
  PIN o_sec[34]
    DIRECTION OUTPUT ;
    USE SIGNAL ;
    PORT
      LAYER M4 ;
        RECT  43.116 4.416 43.2 4.44 ;
    END
  END o_sec[34]
  PIN o_sec[35]
    DIRECTION OUTPUT ;
    USE SIGNAL ;
    PORT
      LAYER M4 ;
        RECT  43.116 4.56 43.2 4.584 ;
    END
  END o_sec[35]
  PIN o_sec[36]
    DIRECTION OUTPUT ;
    USE SIGNAL ;
    PORT
      LAYER M4 ;
        RECT  43.116 4.704 43.2 4.728 ;
    END
  END o_sec[36]
  PIN o_sec[37]
    DIRECTION OUTPUT ;
    USE SIGNAL ;
    PORT
      LAYER M4 ;
        RECT  43.116 4.8 43.2 4.824 ;
    END
  END o_sec[37]
  PIN o_sec[38]
    DIRECTION OUTPUT ;
    USE SIGNAL ;
    PORT
      LAYER M4 ;
        RECT  43.116 4.944 43.2 4.968 ;
    END
  END o_sec[38]
  PIN o_sec[39]
    DIRECTION OUTPUT ;
    USE SIGNAL ;
    PORT
      LAYER M4 ;
        RECT  43.116 5.088 43.2 5.112 ;
    END
  END o_sec[39]
  PIN o_sec[3]
    DIRECTION OUTPUT ;
    USE SIGNAL ;
    PORT
      LAYER M4 ;
        RECT  43.116 0.432 43.2 0.456 ;
    END
  END o_sec[3]
  PIN o_sec[40]
    DIRECTION OUTPUT ;
    USE SIGNAL ;
    PORT
      LAYER M4 ;
        RECT  43.116 5.184 43.2 5.208 ;
    END
  END o_sec[40]
  PIN o_sec[41]
    DIRECTION OUTPUT ;
    USE SIGNAL ;
    PORT
      LAYER M4 ;
        RECT  43.116 5.328 43.2 5.352 ;
    END
  END o_sec[41]
  PIN o_sec[42]
    DIRECTION OUTPUT ;
    USE SIGNAL ;
    PORT
      LAYER M4 ;
        RECT  43.116 5.472 43.2 5.496 ;
    END
  END o_sec[42]
  PIN o_sec[43]
    DIRECTION OUTPUT ;
    USE SIGNAL ;
    PORT
      LAYER M4 ;
        RECT  43.116 5.568 43.2 5.592 ;
    END
  END o_sec[43]
  PIN o_sec[44]
    DIRECTION OUTPUT ;
    USE SIGNAL ;
    PORT
      LAYER M4 ;
        RECT  43.116 5.712 43.2 5.736 ;
    END
  END o_sec[44]
  PIN o_sec[45]
    DIRECTION OUTPUT ;
    USE SIGNAL ;
    PORT
      LAYER M4 ;
        RECT  43.116 5.856 43.2 5.88 ;
    END
  END o_sec[45]
  PIN o_sec[46]
    DIRECTION OUTPUT ;
    USE SIGNAL ;
    PORT
      LAYER M4 ;
        RECT  43.116 5.952 43.2 5.976 ;
    END
  END o_sec[46]
  PIN o_sec[47]
    DIRECTION OUTPUT ;
    USE SIGNAL ;
    PORT
      LAYER M4 ;
        RECT  43.116 6.096 43.2 6.12 ;
    END
  END o_sec[47]
  PIN o_sec[48]
    DIRECTION OUTPUT ;
    USE SIGNAL ;
    PORT
      LAYER M4 ;
        RECT  43.116 6.24 43.2 6.264 ;
    END
  END o_sec[48]
  PIN o_sec[49]
    DIRECTION OUTPUT ;
    USE SIGNAL ;
    PORT
      LAYER M4 ;
        RECT  43.116 6.336 43.2 6.36 ;
    END
  END o_sec[49]
  PIN o_sec[4]
    DIRECTION OUTPUT ;
    USE SIGNAL ;
    PORT
      LAYER M4 ;
        RECT  43.116 0.576 43.2 0.6 ;
    END
  END o_sec[4]
  PIN o_sec[50]
    DIRECTION OUTPUT ;
    USE SIGNAL ;
    PORT
      LAYER M4 ;
        RECT  43.116 6.48 43.2 6.504 ;
    END
  END o_sec[50]
  PIN o_sec[51]
    DIRECTION OUTPUT ;
    USE SIGNAL ;
    PORT
      LAYER M4 ;
        RECT  43.116 6.624 43.2 6.648 ;
    END
  END o_sec[51]
  PIN o_sec[52]
    DIRECTION OUTPUT ;
    USE SIGNAL ;
    PORT
      LAYER M4 ;
        RECT  43.116 6.72 43.2 6.744 ;
    END
  END o_sec[52]
  PIN o_sec[53]
    DIRECTION OUTPUT ;
    USE SIGNAL ;
    PORT
      LAYER M4 ;
        RECT  43.116 6.864 43.2 6.888 ;
    END
  END o_sec[53]
  PIN o_sec[54]
    DIRECTION OUTPUT ;
    USE SIGNAL ;
    PORT
      LAYER M4 ;
        RECT  43.116 7.008 43.2 7.032 ;
    END
  END o_sec[54]
  PIN o_sec[55]
    DIRECTION OUTPUT ;
    USE SIGNAL ;
    PORT
      LAYER M4 ;
        RECT  43.116 7.104 43.2 7.128 ;
    END
  END o_sec[55]
  PIN o_sec[56]
    DIRECTION OUTPUT ;
    USE SIGNAL ;
    PORT
      LAYER M4 ;
        RECT  43.116 7.248 43.2 7.272 ;
    END
  END o_sec[56]
  PIN o_sec[57]
    DIRECTION OUTPUT ;
    USE SIGNAL ;
    PORT
      LAYER M4 ;
        RECT  43.116 7.392 43.2 7.416 ;
    END
  END o_sec[57]
  PIN o_sec[58]
    DIRECTION OUTPUT ;
    USE SIGNAL ;
    PORT
      LAYER M4 ;
        RECT  43.116 7.488 43.2 7.512 ;
    END
  END o_sec[58]
  PIN o_sec[59]
    DIRECTION OUTPUT ;
    USE SIGNAL ;
    PORT
      LAYER M4 ;
        RECT  43.116 7.632 43.2 7.656 ;
    END
  END o_sec[59]
  PIN o_sec[5]
    DIRECTION OUTPUT ;
    USE SIGNAL ;
    PORT
      LAYER M4 ;
        RECT  43.116 0.672 43.2 0.696 ;
    END
  END o_sec[5]
  PIN o_sec[60]
    DIRECTION OUTPUT ;
    USE SIGNAL ;
    PORT
      LAYER M4 ;
        RECT  43.116 7.776 43.2 7.8 ;
    END
  END o_sec[60]
  PIN o_sec[61]
    DIRECTION OUTPUT ;
    USE SIGNAL ;
    PORT
      LAYER M4 ;
        RECT  43.116 7.872 43.2 7.896 ;
    END
  END o_sec[61]
  PIN o_sec[62]
    DIRECTION OUTPUT ;
    USE SIGNAL ;
    PORT
      LAYER M4 ;
        RECT  43.116 8.016 43.2 8.04 ;
    END
  END o_sec[62]
  PIN o_sec[63]
    DIRECTION OUTPUT ;
    USE SIGNAL ;
    PORT
      LAYER M4 ;
        RECT  43.116 8.16 43.2 8.184 ;
    END
  END o_sec[63]
  PIN o_sec[64]
    DIRECTION OUTPUT ;
    USE SIGNAL ;
    PORT
      LAYER M4 ;
        RECT  43.116 8.304 43.2 8.328 ;
    END
  END o_sec[64]
  PIN o_sec[65]
    DIRECTION OUTPUT ;
    USE SIGNAL ;
    PORT
      LAYER M4 ;
        RECT  43.116 8.4 43.2 8.424 ;
    END
  END o_sec[65]
  PIN o_sec[66]
    DIRECTION OUTPUT ;
    USE SIGNAL ;
    PORT
      LAYER M4 ;
        RECT  43.116 8.544 43.2 8.568 ;
    END
  END o_sec[66]
  PIN o_sec[67]
    DIRECTION OUTPUT ;
    USE SIGNAL ;
    PORT
      LAYER M4 ;
        RECT  43.116 8.688 43.2 8.712 ;
    END
  END o_sec[67]
  PIN o_sec[68]
    DIRECTION OUTPUT ;
    USE SIGNAL ;
    PORT
      LAYER M4 ;
        RECT  43.116 8.784 43.2 8.808 ;
    END
  END o_sec[68]
  PIN o_sec[69]
    DIRECTION OUTPUT ;
    USE SIGNAL ;
    PORT
      LAYER M4 ;
        RECT  43.116 8.928 43.2 8.952 ;
    END
  END o_sec[69]
  PIN o_sec[6]
    DIRECTION OUTPUT ;
    USE SIGNAL ;
    PORT
      LAYER M4 ;
        RECT  43.116 0.816 43.2 0.84 ;
    END
  END o_sec[6]
  PIN o_sec[70]
    DIRECTION OUTPUT ;
    USE SIGNAL ;
    PORT
      LAYER M4 ;
        RECT  43.116 9.072 43.2 9.096 ;
    END
  END o_sec[70]
  PIN o_sec[71]
    DIRECTION OUTPUT ;
    USE SIGNAL ;
    PORT
      LAYER M4 ;
        RECT  43.116 9.168 43.2 9.192 ;
    END
  END o_sec[71]
  PIN o_sec[72]
    DIRECTION OUTPUT ;
    USE SIGNAL ;
    PORT
      LAYER M4 ;
        RECT  43.116 9.312 43.2 9.336 ;
    END
  END o_sec[72]
  PIN o_sec[73]
    DIRECTION OUTPUT ;
    USE SIGNAL ;
    PORT
      LAYER M4 ;
        RECT  43.116 9.456 43.2 9.48 ;
    END
  END o_sec[73]
  PIN o_sec[74]
    DIRECTION OUTPUT ;
    USE SIGNAL ;
    PORT
      LAYER M4 ;
        RECT  43.116 9.552 43.2 9.576 ;
    END
  END o_sec[74]
  PIN o_sec[75]
    DIRECTION OUTPUT ;
    USE SIGNAL ;
    PORT
      LAYER M4 ;
        RECT  43.116 9.696 43.2 9.72 ;
    END
  END o_sec[75]
  PIN o_sec[76]
    DIRECTION OUTPUT ;
    USE SIGNAL ;
    PORT
      LAYER M4 ;
        RECT  43.116 9.84 43.2 9.864 ;
    END
  END o_sec[76]
  PIN o_sec[77]
    DIRECTION OUTPUT ;
    USE SIGNAL ;
    PORT
      LAYER M4 ;
        RECT  43.116 9.936 43.2 9.96 ;
    END
  END o_sec[77]
  PIN o_sec[78]
    DIRECTION OUTPUT ;
    USE SIGNAL ;
    PORT
      LAYER M4 ;
        RECT  43.116 10.08 43.2 10.104 ;
    END
  END o_sec[78]
  PIN o_sec[79]
    DIRECTION OUTPUT ;
    USE SIGNAL ;
    PORT
      LAYER M4 ;
        RECT  43.116 10.224 43.2 10.248 ;
    END
  END o_sec[79]
  PIN o_sec[7]
    DIRECTION OUTPUT ;
    USE SIGNAL ;
    PORT
      LAYER M4 ;
        RECT  43.116 0.96 43.2 0.984 ;
    END
  END o_sec[7]
  PIN o_sec[80]
    DIRECTION OUTPUT ;
    USE SIGNAL ;
    PORT
      LAYER M4 ;
        RECT  43.116 10.32 43.2 10.344 ;
    END
  END o_sec[80]
  PIN o_sec[81]
    DIRECTION OUTPUT ;
    USE SIGNAL ;
    PORT
      LAYER M4 ;
        RECT  43.116 10.464 43.2 10.488 ;
    END
  END o_sec[81]
  PIN o_sec[82]
    DIRECTION OUTPUT ;
    USE SIGNAL ;
    PORT
      LAYER M4 ;
        RECT  43.116 10.608 43.2 10.632 ;
    END
  END o_sec[82]
  PIN o_sec[83]
    DIRECTION OUTPUT ;
    USE SIGNAL ;
    PORT
      LAYER M4 ;
        RECT  43.116 10.704 43.2 10.728 ;
    END
  END o_sec[83]
  PIN o_sec[84]
    DIRECTION OUTPUT ;
    USE SIGNAL ;
    PORT
      LAYER M4 ;
        RECT  43.116 10.848 43.2 10.872 ;
    END
  END o_sec[84]
  PIN o_sec[85]
    DIRECTION OUTPUT ;
    USE SIGNAL ;
    PORT
      LAYER M4 ;
        RECT  43.116 10.992 43.2 11.016 ;
    END
  END o_sec[85]
  PIN o_sec[86]
    DIRECTION OUTPUT ;
    USE SIGNAL ;
    PORT
      LAYER M4 ;
        RECT  43.116 11.088 43.2 11.112 ;
    END
  END o_sec[86]
  PIN o_sec[87]
    DIRECTION OUTPUT ;
    USE SIGNAL ;
    PORT
      LAYER M4 ;
        RECT  43.116 11.232 43.2 11.256 ;
    END
  END o_sec[87]
  PIN o_sec[88]
    DIRECTION OUTPUT ;
    USE SIGNAL ;
    PORT
      LAYER M4 ;
        RECT  43.116 11.376 43.2 11.4 ;
    END
  END o_sec[88]
  PIN o_sec[89]
    DIRECTION OUTPUT ;
    USE SIGNAL ;
    PORT
      LAYER M4 ;
        RECT  43.116 11.472 43.2 11.496 ;
    END
  END o_sec[89]
  PIN o_sec[8]
    DIRECTION OUTPUT ;
    USE SIGNAL ;
    PORT
      LAYER M4 ;
        RECT  43.116 1.104 43.2 1.128 ;
    END
  END o_sec[8]
  PIN o_sec[90]
    DIRECTION OUTPUT ;
    USE SIGNAL ;
    PORT
      LAYER M4 ;
        RECT  43.116 11.616 43.2 11.64 ;
    END
  END o_sec[90]
  PIN o_sec[91]
    DIRECTION OUTPUT ;
    USE SIGNAL ;
    PORT
      LAYER M4 ;
        RECT  43.116 11.76 43.2 11.784 ;
    END
  END o_sec[91]
  PIN o_sec[92]
    DIRECTION OUTPUT ;
    USE SIGNAL ;
    PORT
      LAYER M4 ;
        RECT  43.116 11.904 43.2 11.928 ;
    END
  END o_sec[92]
  PIN o_sec[93]
    DIRECTION OUTPUT ;
    USE SIGNAL ;
    PORT
      LAYER M4 ;
        RECT  43.116 12 43.2 12.024 ;
    END
  END o_sec[93]
  PIN o_sec[94]
    DIRECTION OUTPUT ;
    USE SIGNAL ;
    PORT
      LAYER M4 ;
        RECT  43.116 12.144 43.2 12.168 ;
    END
  END o_sec[94]
  PIN o_sec[95]
    DIRECTION OUTPUT ;
    USE SIGNAL ;
    PORT
      LAYER M4 ;
        RECT  43.116 12.288 43.2 12.312 ;
    END
  END o_sec[95]
  PIN o_sec[96]
    DIRECTION OUTPUT ;
    USE SIGNAL ;
    PORT
      LAYER M4 ;
        RECT  43.116 12.384 43.2 12.408 ;
    END
  END o_sec[96]
  PIN o_sec[97]
    DIRECTION OUTPUT ;
    USE SIGNAL ;
    PORT
      LAYER M4 ;
        RECT  43.116 12.528 43.2 12.552 ;
    END
  END o_sec[97]
  PIN o_sec[98]
    DIRECTION OUTPUT ;
    USE SIGNAL ;
    PORT
      LAYER M4 ;
        RECT  43.116 12.672 43.2 12.696 ;
    END
  END o_sec[98]
  PIN o_sec[99]
    DIRECTION OUTPUT ;
    USE SIGNAL ;
    PORT
      LAYER M4 ;
        RECT  43.116 12.768 43.2 12.792 ;
    END
  END o_sec[99]
  PIN o_sec[9]
    DIRECTION OUTPUT ;
    USE SIGNAL ;
    PORT
      LAYER M4 ;
        RECT  43.116 1.2 43.2 1.224 ;
    END
  END o_sec[9]
  PIN o_slot[0]
    DIRECTION OUTPUT ;
    USE SIGNAL ;
    PORT
      LAYER M4 ;
        RECT  43.116 15.504 43.2 15.528 ;
    END
  END o_slot[0]
  PIN o_slot[10]
    DIRECTION OUTPUT ;
    USE SIGNAL ;
    PORT
      LAYER M4 ;
        RECT  43.116 16.752 43.2 16.776 ;
    END
  END o_slot[10]
  PIN o_slot[11]
    DIRECTION OUTPUT ;
    USE SIGNAL ;
    PORT
      LAYER M4 ;
        RECT  43.116 16.896 43.2 16.92 ;
    END
  END o_slot[11]
  PIN o_slot[12]
    DIRECTION OUTPUT ;
    USE SIGNAL ;
    PORT
      LAYER M4 ;
        RECT  43.116 17.04 43.2 17.064 ;
    END
  END o_slot[12]
  PIN o_slot[13]
    DIRECTION OUTPUT ;
    USE SIGNAL ;
    PORT
      LAYER M4 ;
        RECT  43.116 17.136 43.2 17.16 ;
    END
  END o_slot[13]
  PIN o_slot[14]
    DIRECTION OUTPUT ;
    USE SIGNAL ;
    PORT
      LAYER M4 ;
        RECT  43.116 17.28 43.2 17.304 ;
    END
  END o_slot[14]
  PIN o_slot[15]
    DIRECTION OUTPUT ;
    USE SIGNAL ;
    PORT
      LAYER M4 ;
        RECT  43.116 17.424 43.2 17.448 ;
    END
  END o_slot[15]
  PIN o_slot[16]
    DIRECTION OUTPUT ;
    USE SIGNAL ;
    PORT
      LAYER M4 ;
        RECT  43.116 17.52 43.2 17.544 ;
    END
  END o_slot[16]
  PIN o_slot[17]
    DIRECTION OUTPUT ;
    USE SIGNAL ;
    PORT
      LAYER M4 ;
        RECT  43.116 17.664 43.2 17.688 ;
    END
  END o_slot[17]
  PIN o_slot[18]
    DIRECTION OUTPUT ;
    USE SIGNAL ;
    PORT
      LAYER M4 ;
        RECT  43.116 17.808 43.2 17.832 ;
    END
  END o_slot[18]
  PIN o_slot[19]
    DIRECTION OUTPUT ;
    USE SIGNAL ;
    PORT
      LAYER M4 ;
        RECT  43.116 17.904 43.2 17.928 ;
    END
  END o_slot[19]
  PIN o_slot[1]
    DIRECTION OUTPUT ;
    USE SIGNAL ;
    PORT
      LAYER M4 ;
        RECT  43.116 15.6 43.2 15.624 ;
    END
  END o_slot[1]
  PIN o_slot[20]
    DIRECTION OUTPUT ;
    USE SIGNAL ;
    PORT
      LAYER M4 ;
        RECT  43.116 18.048 43.2 18.072 ;
    END
  END o_slot[20]
  PIN o_slot[21]
    DIRECTION OUTPUT ;
    USE SIGNAL ;
    PORT
      LAYER M4 ;
        RECT  43.116 18.192 43.2 18.216 ;
    END
  END o_slot[21]
  PIN o_slot[22]
    DIRECTION OUTPUT ;
    USE SIGNAL ;
    PORT
      LAYER M4 ;
        RECT  43.116 18.288 43.2 18.312 ;
    END
  END o_slot[22]
  PIN o_slot[23]
    DIRECTION OUTPUT ;
    USE SIGNAL ;
    PORT
      LAYER M4 ;
        RECT  43.116 18.432 43.2 18.456 ;
    END
  END o_slot[23]
  PIN o_slot[24]
    DIRECTION OUTPUT ;
    USE SIGNAL ;
    PORT
      LAYER M4 ;
        RECT  43.116 18.576 43.2 18.6 ;
    END
  END o_slot[24]
  PIN o_slot[25]
    DIRECTION OUTPUT ;
    USE SIGNAL ;
    PORT
      LAYER M4 ;
        RECT  43.116 18.672 43.2 18.696 ;
    END
  END o_slot[25]
  PIN o_slot[26]
    DIRECTION OUTPUT ;
    USE SIGNAL ;
    PORT
      LAYER M4 ;
        RECT  43.116 18.816 43.2 18.84 ;
    END
  END o_slot[26]
  PIN o_slot[27]
    DIRECTION OUTPUT ;
    USE SIGNAL ;
    PORT
      LAYER M4 ;
        RECT  43.116 18.96 43.2 18.984 ;
    END
  END o_slot[27]
  PIN o_slot[28]
    DIRECTION OUTPUT ;
    USE SIGNAL ;
    PORT
      LAYER M4 ;
        RECT  43.116 19.104 43.2 19.128 ;
    END
  END o_slot[28]
  PIN o_slot[29]
    DIRECTION OUTPUT ;
    USE SIGNAL ;
    PORT
      LAYER M4 ;
        RECT  43.116 19.2 43.2 19.224 ;
    END
  END o_slot[29]
  PIN o_slot[2]
    DIRECTION OUTPUT ;
    USE SIGNAL ;
    PORT
      LAYER M4 ;
        RECT  43.116 15.744 43.2 15.768 ;
    END
  END o_slot[2]
  PIN o_slot[30]
    DIRECTION OUTPUT ;
    USE SIGNAL ;
    PORT
      LAYER M4 ;
        RECT  43.116 19.344 43.2 19.368 ;
    END
  END o_slot[30]
  PIN o_slot[31]
    DIRECTION OUTPUT ;
    USE SIGNAL ;
    PORT
      LAYER M4 ;
        RECT  43.116 19.488 43.2 19.512 ;
    END
  END o_slot[31]
  PIN o_slot[3]
    DIRECTION OUTPUT ;
    USE SIGNAL ;
    PORT
      LAYER M4 ;
        RECT  43.116 15.888 43.2 15.912 ;
    END
  END o_slot[3]
  PIN o_slot[4]
    DIRECTION OUTPUT ;
    USE SIGNAL ;
    PORT
      LAYER M4 ;
        RECT  43.116 15.984 43.2 16.008 ;
    END
  END o_slot[4]
  PIN o_slot[5]
    DIRECTION OUTPUT ;
    USE SIGNAL ;
    PORT
      LAYER M4 ;
        RECT  43.116 16.128 43.2 16.152 ;
    END
  END o_slot[5]
  PIN o_slot[6]
    DIRECTION OUTPUT ;
    USE SIGNAL ;
    PORT
      LAYER M4 ;
        RECT  43.116 16.272 43.2 16.296 ;
    END
  END o_slot[6]
  PIN o_slot[7]
    DIRECTION OUTPUT ;
    USE SIGNAL ;
    PORT
      LAYER M4 ;
        RECT  43.116 16.368 43.2 16.392 ;
    END
  END o_slot[7]
  PIN o_slot[8]
    DIRECTION OUTPUT ;
    USE SIGNAL ;
    PORT
      LAYER M4 ;
        RECT  43.116 16.512 43.2 16.536 ;
    END
  END o_slot[8]
  PIN o_slot[9]
    DIRECTION OUTPUT ;
    USE SIGNAL ;
    PORT
      LAYER M4 ;
        RECT  43.116 16.656 43.2 16.68 ;
    END
  END o_slot[9]
  PIN o_v[0]
    DIRECTION OUTPUT ;
    USE SIGNAL ;
    PORT
      LAYER M4 ;
        RECT  43.116 19.584 43.2 19.608 ;
    END
  END o_v[0]
  PIN o_v[1]
    DIRECTION OUTPUT ;
    USE SIGNAL ;
    PORT
      LAYER M4 ;
        RECT  43.116 19.728 43.2 19.752 ;
    END
  END o_v[1]
  PIN o_v[2]
    DIRECTION OUTPUT ;
    USE SIGNAL ;
    PORT
      LAYER M4 ;
        RECT  43.116 19.872 43.2 19.896 ;
    END
  END o_v[2]
  PIN o_v[3]
    DIRECTION OUTPUT ;
    USE SIGNAL ;
    PORT
      LAYER M4 ;
        RECT  43.116 19.968 43.2 19.992 ;
    END
  END o_v[3]
  PIN o_v[4]
    DIRECTION OUTPUT ;
    USE SIGNAL ;
    PORT
      LAYER M4 ;
        RECT  43.116 20.112 43.2 20.136 ;
    END
  END o_v[4]
  PIN o_v[5]
    DIRECTION OUTPUT ;
    USE SIGNAL ;
    PORT
      LAYER M4 ;
        RECT  43.116 20.256 43.2 20.28 ;
    END
  END o_v[5]
  PIN o_v[6]
    DIRECTION OUTPUT ;
    USE SIGNAL ;
    PORT
      LAYER M4 ;
        RECT  43.116 20.352 43.2 20.376 ;
    END
  END o_v[6]
  PIN o_v[7]
    DIRECTION OUTPUT ;
    USE SIGNAL ;
    PORT
      LAYER M4 ;
        RECT  43.116 20.496 43.2 20.52 ;
    END
  END o_v[7]
  PIN o_y[0]
    DIRECTION OUTPUT ;
    USE SIGNAL ;
    PORT
      LAYER M4 ;
        RECT  43.116 20.64 43.2 20.664 ;
    END
  END o_y[0]
  PIN o_y[100]
    DIRECTION OUTPUT ;
    USE SIGNAL ;
    PORT
      LAYER M4 ;
        RECT  43.116 33.504 43.2 33.528 ;
    END
  END o_y[100]
  PIN o_y[101]
    DIRECTION OUTPUT ;
    USE SIGNAL ;
    PORT
      LAYER M4 ;
        RECT  43.116 33.6 43.2 33.624 ;
    END
  END o_y[101]
  PIN o_y[102]
    DIRECTION OUTPUT ;
    USE SIGNAL ;
    PORT
      LAYER M4 ;
        RECT  43.116 33.744 43.2 33.768 ;
    END
  END o_y[102]
  PIN o_y[103]
    DIRECTION OUTPUT ;
    USE SIGNAL ;
    PORT
      LAYER M4 ;
        RECT  43.116 33.888 43.2 33.912 ;
    END
  END o_y[103]
  PIN o_y[104]
    DIRECTION OUTPUT ;
    USE SIGNAL ;
    PORT
      LAYER M4 ;
        RECT  43.116 33.984 43.2 34.008 ;
    END
  END o_y[104]
  PIN o_y[105]
    DIRECTION OUTPUT ;
    USE SIGNAL ;
    PORT
      LAYER M4 ;
        RECT  43.116 34.128 43.2 34.152 ;
    END
  END o_y[105]
  PIN o_y[106]
    DIRECTION OUTPUT ;
    USE SIGNAL ;
    PORT
      LAYER M4 ;
        RECT  43.116 34.272 43.2 34.296 ;
    END
  END o_y[106]
  PIN o_y[107]
    DIRECTION OUTPUT ;
    USE SIGNAL ;
    PORT
      LAYER M4 ;
        RECT  43.116 34.368 43.2 34.392 ;
    END
  END o_y[107]
  PIN o_y[108]
    DIRECTION OUTPUT ;
    USE SIGNAL ;
    PORT
      LAYER M4 ;
        RECT  43.116 34.512 43.2 34.536 ;
    END
  END o_y[108]
  PIN o_y[109]
    DIRECTION OUTPUT ;
    USE SIGNAL ;
    PORT
      LAYER M4 ;
        RECT  43.116 34.656 43.2 34.68 ;
    END
  END o_y[109]
  PIN o_y[10]
    DIRECTION OUTPUT ;
    USE SIGNAL ;
    PORT
      LAYER M4 ;
        RECT  43.116 21.888 43.2 21.912 ;
    END
  END o_y[10]
  PIN o_y[110]
    DIRECTION OUTPUT ;
    USE SIGNAL ;
    PORT
      LAYER M4 ;
        RECT  43.116 34.752 43.2 34.776 ;
    END
  END o_y[110]
  PIN o_y[111]
    DIRECTION OUTPUT ;
    USE SIGNAL ;
    PORT
      LAYER M4 ;
        RECT  43.116 34.896 43.2 34.92 ;
    END
  END o_y[111]
  PIN o_y[112]
    DIRECTION OUTPUT ;
    USE SIGNAL ;
    PORT
      LAYER M4 ;
        RECT  43.116 35.04 43.2 35.064 ;
    END
  END o_y[112]
  PIN o_y[113]
    DIRECTION OUTPUT ;
    USE SIGNAL ;
    PORT
      LAYER M4 ;
        RECT  43.116 35.136 43.2 35.16 ;
    END
  END o_y[113]
  PIN o_y[114]
    DIRECTION OUTPUT ;
    USE SIGNAL ;
    PORT
      LAYER M4 ;
        RECT  43.116 35.28 43.2 35.304 ;
    END
  END o_y[114]
  PIN o_y[115]
    DIRECTION OUTPUT ;
    USE SIGNAL ;
    PORT
      LAYER M4 ;
        RECT  43.116 35.424 43.2 35.448 ;
    END
  END o_y[115]
  PIN o_y[116]
    DIRECTION OUTPUT ;
    USE SIGNAL ;
    PORT
      LAYER M4 ;
        RECT  43.116 35.52 43.2 35.544 ;
    END
  END o_y[116]
  PIN o_y[117]
    DIRECTION OUTPUT ;
    USE SIGNAL ;
    PORT
      LAYER M4 ;
        RECT  43.116 35.664 43.2 35.688 ;
    END
  END o_y[117]
  PIN o_y[118]
    DIRECTION OUTPUT ;
    USE SIGNAL ;
    PORT
      LAYER M4 ;
        RECT  43.116 35.808 43.2 35.832 ;
    END
  END o_y[118]
  PIN o_y[119]
    DIRECTION OUTPUT ;
    USE SIGNAL ;
    PORT
      LAYER M4 ;
        RECT  43.116 35.904 43.2 35.928 ;
    END
  END o_y[119]
  PIN o_y[11]
    DIRECTION OUTPUT ;
    USE SIGNAL ;
    PORT
      LAYER M4 ;
        RECT  43.116 22.032 43.2 22.056 ;
    END
  END o_y[11]
  PIN o_y[120]
    DIRECTION OUTPUT ;
    USE SIGNAL ;
    PORT
      LAYER M4 ;
        RECT  43.116 36.048 43.2 36.072 ;
    END
  END o_y[120]
  PIN o_y[121]
    DIRECTION OUTPUT ;
    USE SIGNAL ;
    PORT
      LAYER M4 ;
        RECT  43.116 36.192 43.2 36.216 ;
    END
  END o_y[121]
  PIN o_y[122]
    DIRECTION OUTPUT ;
    USE SIGNAL ;
    PORT
      LAYER M4 ;
        RECT  43.116 36.288 43.2 36.312 ;
    END
  END o_y[122]
  PIN o_y[123]
    DIRECTION OUTPUT ;
    USE SIGNAL ;
    PORT
      LAYER M4 ;
        RECT  43.116 36.432 43.2 36.456 ;
    END
  END o_y[123]
  PIN o_y[124]
    DIRECTION OUTPUT ;
    USE SIGNAL ;
    PORT
      LAYER M4 ;
        RECT  43.116 36.576 43.2 36.6 ;
    END
  END o_y[124]
  PIN o_y[125]
    DIRECTION OUTPUT ;
    USE SIGNAL ;
    PORT
      LAYER M4 ;
        RECT  43.116 36.672 43.2 36.696 ;
    END
  END o_y[125]
  PIN o_y[126]
    DIRECTION OUTPUT ;
    USE SIGNAL ;
    PORT
      LAYER M4 ;
        RECT  43.116 36.816 43.2 36.84 ;
    END
  END o_y[126]
  PIN o_y[127]
    DIRECTION OUTPUT ;
    USE SIGNAL ;
    PORT
      LAYER M4 ;
        RECT  43.116 36.96 43.2 36.984 ;
    END
  END o_y[127]
  PIN o_y[128]
    DIRECTION OUTPUT ;
    USE SIGNAL ;
    PORT
      LAYER M4 ;
        RECT  43.116 37.104 43.2 37.128 ;
    END
  END o_y[128]
  PIN o_y[129]
    DIRECTION OUTPUT ;
    USE SIGNAL ;
    PORT
      LAYER M4 ;
        RECT  43.116 37.2 43.2 37.224 ;
    END
  END o_y[129]
  PIN o_y[12]
    DIRECTION OUTPUT ;
    USE SIGNAL ;
    PORT
      LAYER M4 ;
        RECT  43.116 22.176 43.2 22.2 ;
    END
  END o_y[12]
  PIN o_y[130]
    DIRECTION OUTPUT ;
    USE SIGNAL ;
    PORT
      LAYER M4 ;
        RECT  43.116 37.344 43.2 37.368 ;
    END
  END o_y[130]
  PIN o_y[131]
    DIRECTION OUTPUT ;
    USE SIGNAL ;
    PORT
      LAYER M4 ;
        RECT  43.116 37.488 43.2 37.512 ;
    END
  END o_y[131]
  PIN o_y[132]
    DIRECTION OUTPUT ;
    USE SIGNAL ;
    PORT
      LAYER M4 ;
        RECT  43.116 37.584 43.2 37.608 ;
    END
  END o_y[132]
  PIN o_y[133]
    DIRECTION OUTPUT ;
    USE SIGNAL ;
    PORT
      LAYER M4 ;
        RECT  43.116 37.728 43.2 37.752 ;
    END
  END o_y[133]
  PIN o_y[134]
    DIRECTION OUTPUT ;
    USE SIGNAL ;
    PORT
      LAYER M4 ;
        RECT  43.116 37.872 43.2 37.896 ;
    END
  END o_y[134]
  PIN o_y[135]
    DIRECTION OUTPUT ;
    USE SIGNAL ;
    PORT
      LAYER M4 ;
        RECT  43.116 37.968 43.2 37.992 ;
    END
  END o_y[135]
  PIN o_y[136]
    DIRECTION OUTPUT ;
    USE SIGNAL ;
    PORT
      LAYER M4 ;
        RECT  43.116 38.112 43.2 38.136 ;
    END
  END o_y[136]
  PIN o_y[137]
    DIRECTION OUTPUT ;
    USE SIGNAL ;
    PORT
      LAYER M4 ;
        RECT  43.116 38.256 43.2 38.28 ;
    END
  END o_y[137]
  PIN o_y[138]
    DIRECTION OUTPUT ;
    USE SIGNAL ;
    PORT
      LAYER M4 ;
        RECT  43.116 38.352 43.2 38.376 ;
    END
  END o_y[138]
  PIN o_y[139]
    DIRECTION OUTPUT ;
    USE SIGNAL ;
    PORT
      LAYER M4 ;
        RECT  43.116 38.496 43.2 38.52 ;
    END
  END o_y[139]
  PIN o_y[13]
    DIRECTION OUTPUT ;
    USE SIGNAL ;
    PORT
      LAYER M4 ;
        RECT  43.116 22.272 43.2 22.296 ;
    END
  END o_y[13]
  PIN o_y[140]
    DIRECTION OUTPUT ;
    USE SIGNAL ;
    PORT
      LAYER M4 ;
        RECT  43.116 38.64 43.2 38.664 ;
    END
  END o_y[140]
  PIN o_y[141]
    DIRECTION OUTPUT ;
    USE SIGNAL ;
    PORT
      LAYER M4 ;
        RECT  43.116 38.736 43.2 38.76 ;
    END
  END o_y[141]
  PIN o_y[142]
    DIRECTION OUTPUT ;
    USE SIGNAL ;
    PORT
      LAYER M4 ;
        RECT  43.116 38.88 43.2 38.904 ;
    END
  END o_y[142]
  PIN o_y[143]
    DIRECTION OUTPUT ;
    USE SIGNAL ;
    PORT
      LAYER M4 ;
        RECT  43.116 39.024 43.2 39.048 ;
    END
  END o_y[143]
  PIN o_y[144]
    DIRECTION OUTPUT ;
    USE SIGNAL ;
    PORT
      LAYER M4 ;
        RECT  43.116 39.12 43.2 39.144 ;
    END
  END o_y[144]
  PIN o_y[145]
    DIRECTION OUTPUT ;
    USE SIGNAL ;
    PORT
      LAYER M4 ;
        RECT  43.116 39.264 43.2 39.288 ;
    END
  END o_y[145]
  PIN o_y[146]
    DIRECTION OUTPUT ;
    USE SIGNAL ;
    PORT
      LAYER M4 ;
        RECT  43.116 39.408 43.2 39.432 ;
    END
  END o_y[146]
  PIN o_y[147]
    DIRECTION OUTPUT ;
    USE SIGNAL ;
    PORT
      LAYER M4 ;
        RECT  43.116 39.504 43.2 39.528 ;
    END
  END o_y[147]
  PIN o_y[148]
    DIRECTION OUTPUT ;
    USE SIGNAL ;
    PORT
      LAYER M4 ;
        RECT  43.116 39.648 43.2 39.672 ;
    END
  END o_y[148]
  PIN o_y[149]
    DIRECTION OUTPUT ;
    USE SIGNAL ;
    PORT
      LAYER M4 ;
        RECT  43.116 39.792 43.2 39.816 ;
    END
  END o_y[149]
  PIN o_y[14]
    DIRECTION OUTPUT ;
    USE SIGNAL ;
    PORT
      LAYER M4 ;
        RECT  43.116 22.416 43.2 22.44 ;
    END
  END o_y[14]
  PIN o_y[150]
    DIRECTION OUTPUT ;
    USE SIGNAL ;
    PORT
      LAYER M4 ;
        RECT  43.116 39.888 43.2 39.912 ;
    END
  END o_y[150]
  PIN o_y[151]
    DIRECTION OUTPUT ;
    USE SIGNAL ;
    PORT
      LAYER M4 ;
        RECT  43.116 40.032 43.2 40.056 ;
    END
  END o_y[151]
  PIN o_y[152]
    DIRECTION OUTPUT ;
    USE SIGNAL ;
    PORT
      LAYER M4 ;
        RECT  43.116 40.176 43.2 40.2 ;
    END
  END o_y[152]
  PIN o_y[153]
    DIRECTION OUTPUT ;
    USE SIGNAL ;
    PORT
      LAYER M4 ;
        RECT  43.116 40.272 43.2 40.296 ;
    END
  END o_y[153]
  PIN o_y[154]
    DIRECTION OUTPUT ;
    USE SIGNAL ;
    PORT
      LAYER M4 ;
        RECT  43.116 40.416 43.2 40.44 ;
    END
  END o_y[154]
  PIN o_y[155]
    DIRECTION OUTPUT ;
    USE SIGNAL ;
    PORT
      LAYER M4 ;
        RECT  43.116 40.56 43.2 40.584 ;
    END
  END o_y[155]
  PIN o_y[156]
    DIRECTION OUTPUT ;
    USE SIGNAL ;
    PORT
      LAYER M4 ;
        RECT  43.116 40.704 43.2 40.728 ;
    END
  END o_y[156]
  PIN o_y[157]
    DIRECTION OUTPUT ;
    USE SIGNAL ;
    PORT
      LAYER M4 ;
        RECT  43.116 40.8 43.2 40.824 ;
    END
  END o_y[157]
  PIN o_y[158]
    DIRECTION OUTPUT ;
    USE SIGNAL ;
    PORT
      LAYER M4 ;
        RECT  43.116 40.944 43.2 40.968 ;
    END
  END o_y[158]
  PIN o_y[159]
    DIRECTION OUTPUT ;
    USE SIGNAL ;
    PORT
      LAYER M4 ;
        RECT  43.116 41.088 43.2 41.112 ;
    END
  END o_y[159]
  PIN o_y[15]
    DIRECTION OUTPUT ;
    USE SIGNAL ;
    PORT
      LAYER M4 ;
        RECT  43.116 22.56 43.2 22.584 ;
    END
  END o_y[15]
  PIN o_y[160]
    DIRECTION OUTPUT ;
    USE SIGNAL ;
    PORT
      LAYER M4 ;
        RECT  43.116 41.184 43.2 41.208 ;
    END
  END o_y[160]
  PIN o_y[161]
    DIRECTION OUTPUT ;
    USE SIGNAL ;
    PORT
      LAYER M4 ;
        RECT  43.116 41.328 43.2 41.352 ;
    END
  END o_y[161]
  PIN o_y[162]
    DIRECTION OUTPUT ;
    USE SIGNAL ;
    PORT
      LAYER M4 ;
        RECT  43.116 41.472 43.2 41.496 ;
    END
  END o_y[162]
  PIN o_y[163]
    DIRECTION OUTPUT ;
    USE SIGNAL ;
    PORT
      LAYER M4 ;
        RECT  43.116 41.568 43.2 41.592 ;
    END
  END o_y[163]
  PIN o_y[164]
    DIRECTION OUTPUT ;
    USE SIGNAL ;
    PORT
      LAYER M4 ;
        RECT  43.116 41.712 43.2 41.736 ;
    END
  END o_y[164]
  PIN o_y[165]
    DIRECTION OUTPUT ;
    USE SIGNAL ;
    PORT
      LAYER M4 ;
        RECT  43.116 41.856 43.2 41.88 ;
    END
  END o_y[165]
  PIN o_y[166]
    DIRECTION OUTPUT ;
    USE SIGNAL ;
    PORT
      LAYER M4 ;
        RECT  43.116 41.952 43.2 41.976 ;
    END
  END o_y[166]
  PIN o_y[167]
    DIRECTION OUTPUT ;
    USE SIGNAL ;
    PORT
      LAYER M4 ;
        RECT  43.116 42.096 43.2 42.12 ;
    END
  END o_y[167]
  PIN o_y[168]
    DIRECTION OUTPUT ;
    USE SIGNAL ;
    PORT
      LAYER M4 ;
        RECT  43.116 42.24 43.2 42.264 ;
    END
  END o_y[168]
  PIN o_y[169]
    DIRECTION OUTPUT ;
    USE SIGNAL ;
    PORT
      LAYER M4 ;
        RECT  43.116 42.336 43.2 42.36 ;
    END
  END o_y[169]
  PIN o_y[16]
    DIRECTION OUTPUT ;
    USE SIGNAL ;
    PORT
      LAYER M4 ;
        RECT  43.116 22.704 43.2 22.728 ;
    END
  END o_y[16]
  PIN o_y[170]
    DIRECTION OUTPUT ;
    USE SIGNAL ;
    PORT
      LAYER M4 ;
        RECT  43.116 42.48 43.2 42.504 ;
    END
  END o_y[170]
  PIN o_y[171]
    DIRECTION OUTPUT ;
    USE SIGNAL ;
    PORT
      LAYER M4 ;
        RECT  43.116 42.624 43.2 42.648 ;
    END
  END o_y[171]
  PIN o_y[172]
    DIRECTION OUTPUT ;
    USE SIGNAL ;
    PORT
      LAYER M4 ;
        RECT  43.116 42.72 43.2 42.744 ;
    END
  END o_y[172]
  PIN o_y[173]
    DIRECTION OUTPUT ;
    USE SIGNAL ;
    PORT
      LAYER M4 ;
        RECT  43.116 42.864 43.2 42.888 ;
    END
  END o_y[173]
  PIN o_y[174]
    DIRECTION OUTPUT ;
    USE SIGNAL ;
    PORT
      LAYER M4 ;
        RECT  43.116 43.008 43.2 43.032 ;
    END
  END o_y[174]
  PIN o_y[175]
    DIRECTION OUTPUT ;
    USE SIGNAL ;
    PORT
      LAYER M4 ;
        RECT  43.116 43.104 43.2 43.128 ;
    END
  END o_y[175]
  PIN o_y[176]
    DIRECTION OUTPUT ;
    USE SIGNAL ;
    PORT
      LAYER M4 ;
        RECT  43.116 43.248 43.2 43.272 ;
    END
  END o_y[176]
  PIN o_y[177]
    DIRECTION OUTPUT ;
    USE SIGNAL ;
    PORT
      LAYER M4 ;
        RECT  43.116 43.392 43.2 43.416 ;
    END
  END o_y[177]
  PIN o_y[178]
    DIRECTION OUTPUT ;
    USE SIGNAL ;
    PORT
      LAYER M4 ;
        RECT  43.116 43.488 43.2 43.512 ;
    END
  END o_y[178]
  PIN o_y[179]
    DIRECTION OUTPUT ;
    USE SIGNAL ;
    PORT
      LAYER M4 ;
        RECT  43.116 43.632 43.2 43.656 ;
    END
  END o_y[179]
  PIN o_y[17]
    DIRECTION OUTPUT ;
    USE SIGNAL ;
    PORT
      LAYER M4 ;
        RECT  43.116 22.8 43.2 22.824 ;
    END
  END o_y[17]
  PIN o_y[180]
    DIRECTION OUTPUT ;
    USE SIGNAL ;
    PORT
      LAYER M4 ;
        RECT  43.116 43.776 43.2 43.8 ;
    END
  END o_y[180]
  PIN o_y[181]
    DIRECTION OUTPUT ;
    USE SIGNAL ;
    PORT
      LAYER M4 ;
        RECT  43.116 43.872 43.2 43.896 ;
    END
  END o_y[181]
  PIN o_y[182]
    DIRECTION OUTPUT ;
    USE SIGNAL ;
    PORT
      LAYER M4 ;
        RECT  43.116 44.016 43.2 44.04 ;
    END
  END o_y[182]
  PIN o_y[183]
    DIRECTION OUTPUT ;
    USE SIGNAL ;
    PORT
      LAYER M4 ;
        RECT  43.116 44.16 43.2 44.184 ;
    END
  END o_y[183]
  PIN o_y[184]
    DIRECTION OUTPUT ;
    USE SIGNAL ;
    PORT
      LAYER M4 ;
        RECT  43.116 44.304 43.2 44.328 ;
    END
  END o_y[184]
  PIN o_y[185]
    DIRECTION OUTPUT ;
    USE SIGNAL ;
    PORT
      LAYER M4 ;
        RECT  43.116 44.4 43.2 44.424 ;
    END
  END o_y[185]
  PIN o_y[186]
    DIRECTION OUTPUT ;
    USE SIGNAL ;
    PORT
      LAYER M4 ;
        RECT  43.116 44.544 43.2 44.568 ;
    END
  END o_y[186]
  PIN o_y[187]
    DIRECTION OUTPUT ;
    USE SIGNAL ;
    PORT
      LAYER M4 ;
        RECT  43.116 44.688 43.2 44.712 ;
    END
  END o_y[187]
  PIN o_y[188]
    DIRECTION OUTPUT ;
    USE SIGNAL ;
    PORT
      LAYER M4 ;
        RECT  43.116 44.784 43.2 44.808 ;
    END
  END o_y[188]
  PIN o_y[189]
    DIRECTION OUTPUT ;
    USE SIGNAL ;
    PORT
      LAYER M4 ;
        RECT  43.116 44.928 43.2 44.952 ;
    END
  END o_y[189]
  PIN o_y[18]
    DIRECTION OUTPUT ;
    USE SIGNAL ;
    PORT
      LAYER M4 ;
        RECT  43.116 22.944 43.2 22.968 ;
    END
  END o_y[18]
  PIN o_y[190]
    DIRECTION OUTPUT ;
    USE SIGNAL ;
    PORT
      LAYER M4 ;
        RECT  43.116 45.072 43.2 45.096 ;
    END
  END o_y[190]
  PIN o_y[191]
    DIRECTION OUTPUT ;
    USE SIGNAL ;
    PORT
      LAYER M4 ;
        RECT  43.116 45.168 43.2 45.192 ;
    END
  END o_y[191]
  PIN o_y[192]
    DIRECTION OUTPUT ;
    USE SIGNAL ;
    PORT
      LAYER M4 ;
        RECT  43.116 45.312 43.2 45.336 ;
    END
  END o_y[192]
  PIN o_y[193]
    DIRECTION OUTPUT ;
    USE SIGNAL ;
    PORT
      LAYER M4 ;
        RECT  43.116 45.456 43.2 45.48 ;
    END
  END o_y[193]
  PIN o_y[194]
    DIRECTION OUTPUT ;
    USE SIGNAL ;
    PORT
      LAYER M4 ;
        RECT  43.116 45.552 43.2 45.576 ;
    END
  END o_y[194]
  PIN o_y[195]
    DIRECTION OUTPUT ;
    USE SIGNAL ;
    PORT
      LAYER M4 ;
        RECT  43.116 45.696 43.2 45.72 ;
    END
  END o_y[195]
  PIN o_y[196]
    DIRECTION OUTPUT ;
    USE SIGNAL ;
    PORT
      LAYER M4 ;
        RECT  43.116 45.84 43.2 45.864 ;
    END
  END o_y[196]
  PIN o_y[197]
    DIRECTION OUTPUT ;
    USE SIGNAL ;
    PORT
      LAYER M4 ;
        RECT  43.116 45.936 43.2 45.96 ;
    END
  END o_y[197]
  PIN o_y[198]
    DIRECTION OUTPUT ;
    USE SIGNAL ;
    PORT
      LAYER M4 ;
        RECT  43.116 46.08 43.2 46.104 ;
    END
  END o_y[198]
  PIN o_y[199]
    DIRECTION OUTPUT ;
    USE SIGNAL ;
    PORT
      LAYER M4 ;
        RECT  43.116 46.224 43.2 46.248 ;
    END
  END o_y[199]
  PIN o_y[19]
    DIRECTION OUTPUT ;
    USE SIGNAL ;
    PORT
      LAYER M4 ;
        RECT  43.116 23.088 43.2 23.112 ;
    END
  END o_y[19]
  PIN o_y[1]
    DIRECTION OUTPUT ;
    USE SIGNAL ;
    PORT
      LAYER M4 ;
        RECT  43.116 20.736 43.2 20.76 ;
    END
  END o_y[1]
  PIN o_y[200]
    DIRECTION OUTPUT ;
    USE SIGNAL ;
    PORT
      LAYER M4 ;
        RECT  43.116 46.32 43.2 46.344 ;
    END
  END o_y[200]
  PIN o_y[201]
    DIRECTION OUTPUT ;
    USE SIGNAL ;
    PORT
      LAYER M4 ;
        RECT  43.116 46.464 43.2 46.488 ;
    END
  END o_y[201]
  PIN o_y[202]
    DIRECTION OUTPUT ;
    USE SIGNAL ;
    PORT
      LAYER M4 ;
        RECT  43.116 46.608 43.2 46.632 ;
    END
  END o_y[202]
  PIN o_y[203]
    DIRECTION OUTPUT ;
    USE SIGNAL ;
    PORT
      LAYER M4 ;
        RECT  43.116 46.704 43.2 46.728 ;
    END
  END o_y[203]
  PIN o_y[204]
    DIRECTION OUTPUT ;
    USE SIGNAL ;
    PORT
      LAYER M4 ;
        RECT  43.116 46.848 43.2 46.872 ;
    END
  END o_y[204]
  PIN o_y[205]
    DIRECTION OUTPUT ;
    USE SIGNAL ;
    PORT
      LAYER M4 ;
        RECT  43.116 46.992 43.2 47.016 ;
    END
  END o_y[205]
  PIN o_y[206]
    DIRECTION OUTPUT ;
    USE SIGNAL ;
    PORT
      LAYER M4 ;
        RECT  43.116 47.088 43.2 47.112 ;
    END
  END o_y[206]
  PIN o_y[207]
    DIRECTION OUTPUT ;
    USE SIGNAL ;
    PORT
      LAYER M4 ;
        RECT  43.116 47.232 43.2 47.256 ;
    END
  END o_y[207]
  PIN o_y[208]
    DIRECTION OUTPUT ;
    USE SIGNAL ;
    PORT
      LAYER M4 ;
        RECT  43.116 47.376 43.2 47.4 ;
    END
  END o_y[208]
  PIN o_y[209]
    DIRECTION OUTPUT ;
    USE SIGNAL ;
    PORT
      LAYER M4 ;
        RECT  43.116 47.472 43.2 47.496 ;
    END
  END o_y[209]
  PIN o_y[20]
    DIRECTION OUTPUT ;
    USE SIGNAL ;
    PORT
      LAYER M4 ;
        RECT  43.116 23.184 43.2 23.208 ;
    END
  END o_y[20]
  PIN o_y[210]
    DIRECTION OUTPUT ;
    USE SIGNAL ;
    PORT
      LAYER M4 ;
        RECT  43.116 47.616 43.2 47.64 ;
    END
  END o_y[210]
  PIN o_y[211]
    DIRECTION OUTPUT ;
    USE SIGNAL ;
    PORT
      LAYER M4 ;
        RECT  43.116 47.76 43.2 47.784 ;
    END
  END o_y[211]
  PIN o_y[212]
    DIRECTION OUTPUT ;
    USE SIGNAL ;
    PORT
      LAYER M4 ;
        RECT  43.116 47.904 43.2 47.928 ;
    END
  END o_y[212]
  PIN o_y[213]
    DIRECTION OUTPUT ;
    USE SIGNAL ;
    PORT
      LAYER M4 ;
        RECT  43.116 48 43.2 48.024 ;
    END
  END o_y[213]
  PIN o_y[214]
    DIRECTION OUTPUT ;
    USE SIGNAL ;
    PORT
      LAYER M4 ;
        RECT  43.116 48.144 43.2 48.168 ;
    END
  END o_y[214]
  PIN o_y[215]
    DIRECTION OUTPUT ;
    USE SIGNAL ;
    PORT
      LAYER M4 ;
        RECT  43.116 48.288 43.2 48.312 ;
    END
  END o_y[215]
  PIN o_y[216]
    DIRECTION OUTPUT ;
    USE SIGNAL ;
    PORT
      LAYER M4 ;
        RECT  43.116 48.384 43.2 48.408 ;
    END
  END o_y[216]
  PIN o_y[217]
    DIRECTION OUTPUT ;
    USE SIGNAL ;
    PORT
      LAYER M4 ;
        RECT  43.116 48.528 43.2 48.552 ;
    END
  END o_y[217]
  PIN o_y[218]
    DIRECTION OUTPUT ;
    USE SIGNAL ;
    PORT
      LAYER M4 ;
        RECT  43.116 48.672 43.2 48.696 ;
    END
  END o_y[218]
  PIN o_y[219]
    DIRECTION OUTPUT ;
    USE SIGNAL ;
    PORT
      LAYER M4 ;
        RECT  43.116 48.768 43.2 48.792 ;
    END
  END o_y[219]
  PIN o_y[21]
    DIRECTION OUTPUT ;
    USE SIGNAL ;
    PORT
      LAYER M4 ;
        RECT  43.116 23.328 43.2 23.352 ;
    END
  END o_y[21]
  PIN o_y[220]
    DIRECTION OUTPUT ;
    USE SIGNAL ;
    PORT
      LAYER M4 ;
        RECT  43.116 48.912 43.2 48.936 ;
    END
  END o_y[220]
  PIN o_y[221]
    DIRECTION OUTPUT ;
    USE SIGNAL ;
    PORT
      LAYER M4 ;
        RECT  43.116 49.056 43.2 49.08 ;
    END
  END o_y[221]
  PIN o_y[222]
    DIRECTION OUTPUT ;
    USE SIGNAL ;
    PORT
      LAYER M4 ;
        RECT  43.116 49.152 43.2 49.176 ;
    END
  END o_y[222]
  PIN o_y[223]
    DIRECTION OUTPUT ;
    USE SIGNAL ;
    PORT
      LAYER M4 ;
        RECT  43.116 49.296 43.2 49.32 ;
    END
  END o_y[223]
  PIN o_y[224]
    DIRECTION OUTPUT ;
    USE SIGNAL ;
    PORT
      LAYER M4 ;
        RECT  43.116 49.44 43.2 49.464 ;
    END
  END o_y[224]
  PIN o_y[225]
    DIRECTION OUTPUT ;
    USE SIGNAL ;
    PORT
      LAYER M4 ;
        RECT  43.116 49.536 43.2 49.56 ;
    END
  END o_y[225]
  PIN o_y[226]
    DIRECTION OUTPUT ;
    USE SIGNAL ;
    PORT
      LAYER M4 ;
        RECT  43.116 49.68 43.2 49.704 ;
    END
  END o_y[226]
  PIN o_y[227]
    DIRECTION OUTPUT ;
    USE SIGNAL ;
    PORT
      LAYER M4 ;
        RECT  43.116 49.824 43.2 49.848 ;
    END
  END o_y[227]
  PIN o_y[228]
    DIRECTION OUTPUT ;
    USE SIGNAL ;
    PORT
      LAYER M4 ;
        RECT  43.116 49.92 43.2 49.944 ;
    END
  END o_y[228]
  PIN o_y[229]
    DIRECTION OUTPUT ;
    USE SIGNAL ;
    PORT
      LAYER M4 ;
        RECT  43.116 50.064 43.2 50.088 ;
    END
  END o_y[229]
  PIN o_y[22]
    DIRECTION OUTPUT ;
    USE SIGNAL ;
    PORT
      LAYER M4 ;
        RECT  43.116 23.472 43.2 23.496 ;
    END
  END o_y[22]
  PIN o_y[230]
    DIRECTION OUTPUT ;
    USE SIGNAL ;
    PORT
      LAYER M4 ;
        RECT  43.116 50.208 43.2 50.232 ;
    END
  END o_y[230]
  PIN o_y[231]
    DIRECTION OUTPUT ;
    USE SIGNAL ;
    PORT
      LAYER M4 ;
        RECT  43.116 50.304 43.2 50.328 ;
    END
  END o_y[231]
  PIN o_y[232]
    DIRECTION OUTPUT ;
    USE SIGNAL ;
    PORT
      LAYER M4 ;
        RECT  43.116 50.448 43.2 50.472 ;
    END
  END o_y[232]
  PIN o_y[233]
    DIRECTION OUTPUT ;
    USE SIGNAL ;
    PORT
      LAYER M4 ;
        RECT  43.116 50.592 43.2 50.616 ;
    END
  END o_y[233]
  PIN o_y[234]
    DIRECTION OUTPUT ;
    USE SIGNAL ;
    PORT
      LAYER M4 ;
        RECT  43.116 50.688 43.2 50.712 ;
    END
  END o_y[234]
  PIN o_y[235]
    DIRECTION OUTPUT ;
    USE SIGNAL ;
    PORT
      LAYER M4 ;
        RECT  43.116 50.832 43.2 50.856 ;
    END
  END o_y[235]
  PIN o_y[236]
    DIRECTION OUTPUT ;
    USE SIGNAL ;
    PORT
      LAYER M4 ;
        RECT  43.116 50.976 43.2 51 ;
    END
  END o_y[236]
  PIN o_y[237]
    DIRECTION OUTPUT ;
    USE SIGNAL ;
    PORT
      LAYER M4 ;
        RECT  43.116 51.072 43.2 51.096 ;
    END
  END o_y[237]
  PIN o_y[238]
    DIRECTION OUTPUT ;
    USE SIGNAL ;
    PORT
      LAYER M4 ;
        RECT  43.116 51.216 43.2 51.24 ;
    END
  END o_y[238]
  PIN o_y[239]
    DIRECTION OUTPUT ;
    USE SIGNAL ;
    PORT
      LAYER M4 ;
        RECT  43.116 51.36 43.2 51.384 ;
    END
  END o_y[239]
  PIN o_y[23]
    DIRECTION OUTPUT ;
    USE SIGNAL ;
    PORT
      LAYER M4 ;
        RECT  43.116 23.568 43.2 23.592 ;
    END
  END o_y[23]
  PIN o_y[240]
    DIRECTION OUTPUT ;
    USE SIGNAL ;
    PORT
      LAYER M4 ;
        RECT  43.116 51.504 43.2 51.528 ;
    END
  END o_y[240]
  PIN o_y[241]
    DIRECTION OUTPUT ;
    USE SIGNAL ;
    PORT
      LAYER M4 ;
        RECT  43.116 51.6 43.2 51.624 ;
    END
  END o_y[241]
  PIN o_y[242]
    DIRECTION OUTPUT ;
    USE SIGNAL ;
    PORT
      LAYER M4 ;
        RECT  43.116 51.744 43.2 51.768 ;
    END
  END o_y[242]
  PIN o_y[243]
    DIRECTION OUTPUT ;
    USE SIGNAL ;
    PORT
      LAYER M4 ;
        RECT  43.116 51.888 43.2 51.912 ;
    END
  END o_y[243]
  PIN o_y[244]
    DIRECTION OUTPUT ;
    USE SIGNAL ;
    PORT
      LAYER M4 ;
        RECT  43.116 51.984 43.2 52.008 ;
    END
  END o_y[244]
  PIN o_y[245]
    DIRECTION OUTPUT ;
    USE SIGNAL ;
    PORT
      LAYER M4 ;
        RECT  43.116 52.128 43.2 52.152 ;
    END
  END o_y[245]
  PIN o_y[246]
    DIRECTION OUTPUT ;
    USE SIGNAL ;
    PORT
      LAYER M4 ;
        RECT  43.116 52.272 43.2 52.296 ;
    END
  END o_y[246]
  PIN o_y[247]
    DIRECTION OUTPUT ;
    USE SIGNAL ;
    PORT
      LAYER M4 ;
        RECT  43.116 52.368 43.2 52.392 ;
    END
  END o_y[247]
  PIN o_y[248]
    DIRECTION OUTPUT ;
    USE SIGNAL ;
    PORT
      LAYER M4 ;
        RECT  43.116 52.512 43.2 52.536 ;
    END
  END o_y[248]
  PIN o_y[249]
    DIRECTION OUTPUT ;
    USE SIGNAL ;
    PORT
      LAYER M4 ;
        RECT  43.116 52.656 43.2 52.68 ;
    END
  END o_y[249]
  PIN o_y[24]
    DIRECTION OUTPUT ;
    USE SIGNAL ;
    PORT
      LAYER M4 ;
        RECT  43.116 23.712 43.2 23.736 ;
    END
  END o_y[24]
  PIN o_y[250]
    DIRECTION OUTPUT ;
    USE SIGNAL ;
    PORT
      LAYER M4 ;
        RECT  43.116 52.752 43.2 52.776 ;
    END
  END o_y[250]
  PIN o_y[251]
    DIRECTION OUTPUT ;
    USE SIGNAL ;
    PORT
      LAYER M4 ;
        RECT  43.116 52.896 43.2 52.92 ;
    END
  END o_y[251]
  PIN o_y[252]
    DIRECTION OUTPUT ;
    USE SIGNAL ;
    PORT
      LAYER M4 ;
        RECT  43.116 53.04 43.2 53.064 ;
    END
  END o_y[252]
  PIN o_y[253]
    DIRECTION OUTPUT ;
    USE SIGNAL ;
    PORT
      LAYER M4 ;
        RECT  43.116 53.136 43.2 53.16 ;
    END
  END o_y[253]
  PIN o_y[254]
    DIRECTION OUTPUT ;
    USE SIGNAL ;
    PORT
      LAYER M4 ;
        RECT  43.116 53.28 43.2 53.304 ;
    END
  END o_y[254]
  PIN o_y[255]
    DIRECTION OUTPUT ;
    USE SIGNAL ;
    PORT
      LAYER M4 ;
        RECT  43.116 53.424 43.2 53.448 ;
    END
  END o_y[255]
  PIN o_y[256]
    DIRECTION OUTPUT ;
    USE SIGNAL ;
    PORT
      LAYER M4 ;
        RECT  43.116 53.52 43.2 53.544 ;
    END
  END o_y[256]
  PIN o_y[257]
    DIRECTION OUTPUT ;
    USE SIGNAL ;
    PORT
      LAYER M4 ;
        RECT  43.116 53.664 43.2 53.688 ;
    END
  END o_y[257]
  PIN o_y[258]
    DIRECTION OUTPUT ;
    USE SIGNAL ;
    PORT
      LAYER M4 ;
        RECT  43.116 53.808 43.2 53.832 ;
    END
  END o_y[258]
  PIN o_y[259]
    DIRECTION OUTPUT ;
    USE SIGNAL ;
    PORT
      LAYER M4 ;
        RECT  43.116 53.904 43.2 53.928 ;
    END
  END o_y[259]
  PIN o_y[25]
    DIRECTION OUTPUT ;
    USE SIGNAL ;
    PORT
      LAYER M4 ;
        RECT  43.116 23.856 43.2 23.88 ;
    END
  END o_y[25]
  PIN o_y[260]
    DIRECTION OUTPUT ;
    USE SIGNAL ;
    PORT
      LAYER M4 ;
        RECT  43.116 54.048 43.2 54.072 ;
    END
  END o_y[260]
  PIN o_y[261]
    DIRECTION OUTPUT ;
    USE SIGNAL ;
    PORT
      LAYER M4 ;
        RECT  43.116 54.192 43.2 54.216 ;
    END
  END o_y[261]
  PIN o_y[262]
    DIRECTION OUTPUT ;
    USE SIGNAL ;
    PORT
      LAYER M4 ;
        RECT  43.116 54.288 43.2 54.312 ;
    END
  END o_y[262]
  PIN o_y[263]
    DIRECTION OUTPUT ;
    USE SIGNAL ;
    PORT
      LAYER M4 ;
        RECT  43.116 54.432 43.2 54.456 ;
    END
  END o_y[263]
  PIN o_y[264]
    DIRECTION OUTPUT ;
    USE SIGNAL ;
    PORT
      LAYER M4 ;
        RECT  43.116 54.576 43.2 54.6 ;
    END
  END o_y[264]
  PIN o_y[265]
    DIRECTION OUTPUT ;
    USE SIGNAL ;
    PORT
      LAYER M4 ;
        RECT  43.116 54.672 43.2 54.696 ;
    END
  END o_y[265]
  PIN o_y[266]
    DIRECTION OUTPUT ;
    USE SIGNAL ;
    PORT
      LAYER M4 ;
        RECT  43.116 54.816 43.2 54.84 ;
    END
  END o_y[266]
  PIN o_y[267]
    DIRECTION OUTPUT ;
    USE SIGNAL ;
    PORT
      LAYER M4 ;
        RECT  43.116 54.96 43.2 54.984 ;
    END
  END o_y[267]
  PIN o_y[268]
    DIRECTION OUTPUT ;
    USE SIGNAL ;
    PORT
      LAYER M4 ;
        RECT  43.116 55.104 43.2 55.128 ;
    END
  END o_y[268]
  PIN o_y[269]
    DIRECTION OUTPUT ;
    USE SIGNAL ;
    PORT
      LAYER M4 ;
        RECT  43.116 55.2 43.2 55.224 ;
    END
  END o_y[269]
  PIN o_y[26]
    DIRECTION OUTPUT ;
    USE SIGNAL ;
    PORT
      LAYER M4 ;
        RECT  43.116 23.952 43.2 23.976 ;
    END
  END o_y[26]
  PIN o_y[270]
    DIRECTION OUTPUT ;
    USE SIGNAL ;
    PORT
      LAYER M4 ;
        RECT  43.116 55.344 43.2 55.368 ;
    END
  END o_y[270]
  PIN o_y[271]
    DIRECTION OUTPUT ;
    USE SIGNAL ;
    PORT
      LAYER M4 ;
        RECT  43.116 55.488 43.2 55.512 ;
    END
  END o_y[271]
  PIN o_y[272]
    DIRECTION OUTPUT ;
    USE SIGNAL ;
    PORT
      LAYER M4 ;
        RECT  43.116 55.584 43.2 55.608 ;
    END
  END o_y[272]
  PIN o_y[273]
    DIRECTION OUTPUT ;
    USE SIGNAL ;
    PORT
      LAYER M4 ;
        RECT  43.116 55.728 43.2 55.752 ;
    END
  END o_y[273]
  PIN o_y[274]
    DIRECTION OUTPUT ;
    USE SIGNAL ;
    PORT
      LAYER M4 ;
        RECT  43.116 55.872 43.2 55.896 ;
    END
  END o_y[274]
  PIN o_y[275]
    DIRECTION OUTPUT ;
    USE SIGNAL ;
    PORT
      LAYER M4 ;
        RECT  43.116 55.968 43.2 55.992 ;
    END
  END o_y[275]
  PIN o_y[276]
    DIRECTION OUTPUT ;
    USE SIGNAL ;
    PORT
      LAYER M4 ;
        RECT  43.116 56.112 43.2 56.136 ;
    END
  END o_y[276]
  PIN o_y[277]
    DIRECTION OUTPUT ;
    USE SIGNAL ;
    PORT
      LAYER M4 ;
        RECT  43.116 56.256 43.2 56.28 ;
    END
  END o_y[277]
  PIN o_y[278]
    DIRECTION OUTPUT ;
    USE SIGNAL ;
    PORT
      LAYER M4 ;
        RECT  43.116 56.352 43.2 56.376 ;
    END
  END o_y[278]
  PIN o_y[279]
    DIRECTION OUTPUT ;
    USE SIGNAL ;
    PORT
      LAYER M4 ;
        RECT  43.116 56.496 43.2 56.52 ;
    END
  END o_y[279]
  PIN o_y[27]
    DIRECTION OUTPUT ;
    USE SIGNAL ;
    PORT
      LAYER M4 ;
        RECT  43.116 24.096 43.2 24.12 ;
    END
  END o_y[27]
  PIN o_y[280]
    DIRECTION OUTPUT ;
    USE SIGNAL ;
    PORT
      LAYER M4 ;
        RECT  43.116 56.64 43.2 56.664 ;
    END
  END o_y[280]
  PIN o_y[281]
    DIRECTION OUTPUT ;
    USE SIGNAL ;
    PORT
      LAYER M4 ;
        RECT  43.116 56.736 43.2 56.76 ;
    END
  END o_y[281]
  PIN o_y[282]
    DIRECTION OUTPUT ;
    USE SIGNAL ;
    PORT
      LAYER M4 ;
        RECT  43.116 56.88 43.2 56.904 ;
    END
  END o_y[282]
  PIN o_y[283]
    DIRECTION OUTPUT ;
    USE SIGNAL ;
    PORT
      LAYER M4 ;
        RECT  43.116 57.024 43.2 57.048 ;
    END
  END o_y[283]
  PIN o_y[284]
    DIRECTION OUTPUT ;
    USE SIGNAL ;
    PORT
      LAYER M4 ;
        RECT  43.116 57.12 43.2 57.144 ;
    END
  END o_y[284]
  PIN o_y[285]
    DIRECTION OUTPUT ;
    USE SIGNAL ;
    PORT
      LAYER M4 ;
        RECT  43.116 57.264 43.2 57.288 ;
    END
  END o_y[285]
  PIN o_y[286]
    DIRECTION OUTPUT ;
    USE SIGNAL ;
    PORT
      LAYER M4 ;
        RECT  43.116 57.408 43.2 57.432 ;
    END
  END o_y[286]
  PIN o_y[287]
    DIRECTION OUTPUT ;
    USE SIGNAL ;
    PORT
      LAYER M4 ;
        RECT  43.116 57.504 43.2 57.528 ;
    END
  END o_y[287]
  PIN o_y[288]
    DIRECTION OUTPUT ;
    USE SIGNAL ;
    PORT
      LAYER M4 ;
        RECT  43.116 57.648 43.2 57.672 ;
    END
  END o_y[288]
  PIN o_y[289]
    DIRECTION OUTPUT ;
    USE SIGNAL ;
    PORT
      LAYER M4 ;
        RECT  43.116 57.792 43.2 57.816 ;
    END
  END o_y[289]
  PIN o_y[28]
    DIRECTION OUTPUT ;
    USE SIGNAL ;
    PORT
      LAYER M4 ;
        RECT  43.116 24.24 43.2 24.264 ;
    END
  END o_y[28]
  PIN o_y[290]
    DIRECTION OUTPUT ;
    USE SIGNAL ;
    PORT
      LAYER M4 ;
        RECT  43.116 57.888 43.2 57.912 ;
    END
  END o_y[290]
  PIN o_y[291]
    DIRECTION OUTPUT ;
    USE SIGNAL ;
    PORT
      LAYER M4 ;
        RECT  43.116 58.032 43.2 58.056 ;
    END
  END o_y[291]
  PIN o_y[292]
    DIRECTION OUTPUT ;
    USE SIGNAL ;
    PORT
      LAYER M4 ;
        RECT  43.116 58.176 43.2 58.2 ;
    END
  END o_y[292]
  PIN o_y[293]
    DIRECTION OUTPUT ;
    USE SIGNAL ;
    PORT
      LAYER M4 ;
        RECT  43.116 58.272 43.2 58.296 ;
    END
  END o_y[293]
  PIN o_y[294]
    DIRECTION OUTPUT ;
    USE SIGNAL ;
    PORT
      LAYER M4 ;
        RECT  43.116 58.416 43.2 58.44 ;
    END
  END o_y[294]
  PIN o_y[295]
    DIRECTION OUTPUT ;
    USE SIGNAL ;
    PORT
      LAYER M4 ;
        RECT  43.116 58.56 43.2 58.584 ;
    END
  END o_y[295]
  PIN o_y[296]
    DIRECTION OUTPUT ;
    USE SIGNAL ;
    PORT
      LAYER M4 ;
        RECT  43.116 58.704 43.2 58.728 ;
    END
  END o_y[296]
  PIN o_y[297]
    DIRECTION OUTPUT ;
    USE SIGNAL ;
    PORT
      LAYER M4 ;
        RECT  43.116 58.8 43.2 58.824 ;
    END
  END o_y[297]
  PIN o_y[298]
    DIRECTION OUTPUT ;
    USE SIGNAL ;
    PORT
      LAYER M4 ;
        RECT  43.116 58.944 43.2 58.968 ;
    END
  END o_y[298]
  PIN o_y[299]
    DIRECTION OUTPUT ;
    USE SIGNAL ;
    PORT
      LAYER M4 ;
        RECT  43.116 59.088 43.2 59.112 ;
    END
  END o_y[299]
  PIN o_y[29]
    DIRECTION OUTPUT ;
    USE SIGNAL ;
    PORT
      LAYER M4 ;
        RECT  43.116 24.336 43.2 24.36 ;
    END
  END o_y[29]
  PIN o_y[2]
    DIRECTION OUTPUT ;
    USE SIGNAL ;
    PORT
      LAYER M4 ;
        RECT  43.116 20.88 43.2 20.904 ;
    END
  END o_y[2]
  PIN o_y[300]
    DIRECTION OUTPUT ;
    USE SIGNAL ;
    PORT
      LAYER M4 ;
        RECT  43.116 59.184 43.2 59.208 ;
    END
  END o_y[300]
  PIN o_y[301]
    DIRECTION OUTPUT ;
    USE SIGNAL ;
    PORT
      LAYER M4 ;
        RECT  43.116 59.328 43.2 59.352 ;
    END
  END o_y[301]
  PIN o_y[302]
    DIRECTION OUTPUT ;
    USE SIGNAL ;
    PORT
      LAYER M4 ;
        RECT  43.116 59.472 43.2 59.496 ;
    END
  END o_y[302]
  PIN o_y[303]
    DIRECTION OUTPUT ;
    USE SIGNAL ;
    PORT
      LAYER M4 ;
        RECT  43.116 59.568 43.2 59.592 ;
    END
  END o_y[303]
  PIN o_y[304]
    DIRECTION OUTPUT ;
    USE SIGNAL ;
    PORT
      LAYER M4 ;
        RECT  43.116 59.712 43.2 59.736 ;
    END
  END o_y[304]
  PIN o_y[305]
    DIRECTION OUTPUT ;
    USE SIGNAL ;
    PORT
      LAYER M4 ;
        RECT  43.116 59.856 43.2 59.88 ;
    END
  END o_y[305]
  PIN o_y[306]
    DIRECTION OUTPUT ;
    USE SIGNAL ;
    PORT
      LAYER M4 ;
        RECT  43.116 59.952 43.2 59.976 ;
    END
  END o_y[306]
  PIN o_y[307]
    DIRECTION OUTPUT ;
    USE SIGNAL ;
    PORT
      LAYER M4 ;
        RECT  43.116 60.096 43.2 60.12 ;
    END
  END o_y[307]
  PIN o_y[308]
    DIRECTION OUTPUT ;
    USE SIGNAL ;
    PORT
      LAYER M4 ;
        RECT  43.116 60.24 43.2 60.264 ;
    END
  END o_y[308]
  PIN o_y[309]
    DIRECTION OUTPUT ;
    USE SIGNAL ;
    PORT
      LAYER M4 ;
        RECT  43.116 60.336 43.2 60.36 ;
    END
  END o_y[309]
  PIN o_y[30]
    DIRECTION OUTPUT ;
    USE SIGNAL ;
    PORT
      LAYER M4 ;
        RECT  43.116 24.48 43.2 24.504 ;
    END
  END o_y[30]
  PIN o_y[310]
    DIRECTION OUTPUT ;
    USE SIGNAL ;
    PORT
      LAYER M4 ;
        RECT  43.116 60.48 43.2 60.504 ;
    END
  END o_y[310]
  PIN o_y[311]
    DIRECTION OUTPUT ;
    USE SIGNAL ;
    PORT
      LAYER M4 ;
        RECT  43.116 60.624 43.2 60.648 ;
    END
  END o_y[311]
  PIN o_y[312]
    DIRECTION OUTPUT ;
    USE SIGNAL ;
    PORT
      LAYER M4 ;
        RECT  43.116 60.72 43.2 60.744 ;
    END
  END o_y[312]
  PIN o_y[313]
    DIRECTION OUTPUT ;
    USE SIGNAL ;
    PORT
      LAYER M4 ;
        RECT  43.116 60.864 43.2 60.888 ;
    END
  END o_y[313]
  PIN o_y[314]
    DIRECTION OUTPUT ;
    USE SIGNAL ;
    PORT
      LAYER M4 ;
        RECT  43.116 61.008 43.2 61.032 ;
    END
  END o_y[314]
  PIN o_y[315]
    DIRECTION OUTPUT ;
    USE SIGNAL ;
    PORT
      LAYER M4 ;
        RECT  43.116 61.104 43.2 61.128 ;
    END
  END o_y[315]
  PIN o_y[316]
    DIRECTION OUTPUT ;
    USE SIGNAL ;
    PORT
      LAYER M4 ;
        RECT  43.116 61.248 43.2 61.272 ;
    END
  END o_y[316]
  PIN o_y[317]
    DIRECTION OUTPUT ;
    USE SIGNAL ;
    PORT
      LAYER M4 ;
        RECT  43.116 61.392 43.2 61.416 ;
    END
  END o_y[317]
  PIN o_y[318]
    DIRECTION OUTPUT ;
    USE SIGNAL ;
    PORT
      LAYER M4 ;
        RECT  43.116 61.488 43.2 61.512 ;
    END
  END o_y[318]
  PIN o_y[319]
    DIRECTION OUTPUT ;
    USE SIGNAL ;
    PORT
      LAYER M4 ;
        RECT  43.116 61.632 43.2 61.656 ;
    END
  END o_y[319]
  PIN o_y[31]
    DIRECTION OUTPUT ;
    USE SIGNAL ;
    PORT
      LAYER M4 ;
        RECT  43.116 24.624 43.2 24.648 ;
    END
  END o_y[31]
  PIN o_y[320]
    DIRECTION OUTPUT ;
    USE SIGNAL ;
    PORT
      LAYER M4 ;
        RECT  43.116 61.776 43.2 61.8 ;
    END
  END o_y[320]
  PIN o_y[321]
    DIRECTION OUTPUT ;
    USE SIGNAL ;
    PORT
      LAYER M4 ;
        RECT  43.116 61.872 43.2 61.896 ;
    END
  END o_y[321]
  PIN o_y[322]
    DIRECTION OUTPUT ;
    USE SIGNAL ;
    PORT
      LAYER M4 ;
        RECT  43.116 62.016 43.2 62.04 ;
    END
  END o_y[322]
  PIN o_y[323]
    DIRECTION OUTPUT ;
    USE SIGNAL ;
    PORT
      LAYER M4 ;
        RECT  43.116 62.16 43.2 62.184 ;
    END
  END o_y[323]
  PIN o_y[324]
    DIRECTION OUTPUT ;
    USE SIGNAL ;
    PORT
      LAYER M4 ;
        RECT  43.116 62.304 43.2 62.328 ;
    END
  END o_y[324]
  PIN o_y[325]
    DIRECTION OUTPUT ;
    USE SIGNAL ;
    PORT
      LAYER M4 ;
        RECT  43.116 62.4 43.2 62.424 ;
    END
  END o_y[325]
  PIN o_y[326]
    DIRECTION OUTPUT ;
    USE SIGNAL ;
    PORT
      LAYER M4 ;
        RECT  43.116 62.544 43.2 62.568 ;
    END
  END o_y[326]
  PIN o_y[327]
    DIRECTION OUTPUT ;
    USE SIGNAL ;
    PORT
      LAYER M4 ;
        RECT  43.116 62.688 43.2 62.712 ;
    END
  END o_y[327]
  PIN o_y[328]
    DIRECTION OUTPUT ;
    USE SIGNAL ;
    PORT
      LAYER M4 ;
        RECT  43.116 62.784 43.2 62.808 ;
    END
  END o_y[328]
  PIN o_y[329]
    DIRECTION OUTPUT ;
    USE SIGNAL ;
    PORT
      LAYER M4 ;
        RECT  43.116 62.928 43.2 62.952 ;
    END
  END o_y[329]
  PIN o_y[32]
    DIRECTION OUTPUT ;
    USE SIGNAL ;
    PORT
      LAYER M4 ;
        RECT  43.116 24.72 43.2 24.744 ;
    END
  END o_y[32]
  PIN o_y[330]
    DIRECTION OUTPUT ;
    USE SIGNAL ;
    PORT
      LAYER M4 ;
        RECT  43.116 63.072 43.2 63.096 ;
    END
  END o_y[330]
  PIN o_y[331]
    DIRECTION OUTPUT ;
    USE SIGNAL ;
    PORT
      LAYER M4 ;
        RECT  43.116 63.168 43.2 63.192 ;
    END
  END o_y[331]
  PIN o_y[332]
    DIRECTION OUTPUT ;
    USE SIGNAL ;
    PORT
      LAYER M4 ;
        RECT  43.116 63.312 43.2 63.336 ;
    END
  END o_y[332]
  PIN o_y[333]
    DIRECTION OUTPUT ;
    USE SIGNAL ;
    PORT
      LAYER M4 ;
        RECT  43.116 63.456 43.2 63.48 ;
    END
  END o_y[333]
  PIN o_y[334]
    DIRECTION OUTPUT ;
    USE SIGNAL ;
    PORT
      LAYER M4 ;
        RECT  43.116 63.552 43.2 63.576 ;
    END
  END o_y[334]
  PIN o_y[335]
    DIRECTION OUTPUT ;
    USE SIGNAL ;
    PORT
      LAYER M4 ;
        RECT  43.116 63.696 43.2 63.72 ;
    END
  END o_y[335]
  PIN o_y[336]
    DIRECTION OUTPUT ;
    USE SIGNAL ;
    PORT
      LAYER M4 ;
        RECT  43.116 63.84 43.2 63.864 ;
    END
  END o_y[336]
  PIN o_y[337]
    DIRECTION OUTPUT ;
    USE SIGNAL ;
    PORT
      LAYER M4 ;
        RECT  43.116 63.936 43.2 63.96 ;
    END
  END o_y[337]
  PIN o_y[338]
    DIRECTION OUTPUT ;
    USE SIGNAL ;
    PORT
      LAYER M4 ;
        RECT  43.116 64.08 43.2 64.104 ;
    END
  END o_y[338]
  PIN o_y[339]
    DIRECTION OUTPUT ;
    USE SIGNAL ;
    PORT
      LAYER M4 ;
        RECT  43.116 64.224 43.2 64.248 ;
    END
  END o_y[339]
  PIN o_y[33]
    DIRECTION OUTPUT ;
    USE SIGNAL ;
    PORT
      LAYER M4 ;
        RECT  43.116 24.864 43.2 24.888 ;
    END
  END o_y[33]
  PIN o_y[340]
    DIRECTION OUTPUT ;
    USE SIGNAL ;
    PORT
      LAYER M4 ;
        RECT  43.116 64.32 43.2 64.344 ;
    END
  END o_y[340]
  PIN o_y[341]
    DIRECTION OUTPUT ;
    USE SIGNAL ;
    PORT
      LAYER M4 ;
        RECT  43.116 64.464 43.2 64.488 ;
    END
  END o_y[341]
  PIN o_y[342]
    DIRECTION OUTPUT ;
    USE SIGNAL ;
    PORT
      LAYER M4 ;
        RECT  43.116 64.608 43.2 64.632 ;
    END
  END o_y[342]
  PIN o_y[343]
    DIRECTION OUTPUT ;
    USE SIGNAL ;
    PORT
      LAYER M4 ;
        RECT  43.116 64.704 43.2 64.728 ;
    END
  END o_y[343]
  PIN o_y[344]
    DIRECTION OUTPUT ;
    USE SIGNAL ;
    PORT
      LAYER M4 ;
        RECT  43.116 64.848 43.2 64.872 ;
    END
  END o_y[344]
  PIN o_y[345]
    DIRECTION OUTPUT ;
    USE SIGNAL ;
    PORT
      LAYER M4 ;
        RECT  43.116 64.992 43.2 65.016 ;
    END
  END o_y[345]
  PIN o_y[346]
    DIRECTION OUTPUT ;
    USE SIGNAL ;
    PORT
      LAYER M4 ;
        RECT  43.116 65.088 43.2 65.112 ;
    END
  END o_y[346]
  PIN o_y[347]
    DIRECTION OUTPUT ;
    USE SIGNAL ;
    PORT
      LAYER M4 ;
        RECT  43.116 65.232 43.2 65.256 ;
    END
  END o_y[347]
  PIN o_y[348]
    DIRECTION OUTPUT ;
    USE SIGNAL ;
    PORT
      LAYER M4 ;
        RECT  43.116 65.376 43.2 65.4 ;
    END
  END o_y[348]
  PIN o_y[349]
    DIRECTION OUTPUT ;
    USE SIGNAL ;
    PORT
      LAYER M4 ;
        RECT  43.116 65.472 43.2 65.496 ;
    END
  END o_y[349]
  PIN o_y[34]
    DIRECTION OUTPUT ;
    USE SIGNAL ;
    PORT
      LAYER M4 ;
        RECT  43.116 25.008 43.2 25.032 ;
    END
  END o_y[34]
  PIN o_y[350]
    DIRECTION OUTPUT ;
    USE SIGNAL ;
    PORT
      LAYER M4 ;
        RECT  43.116 65.616 43.2 65.64 ;
    END
  END o_y[350]
  PIN o_y[351]
    DIRECTION OUTPUT ;
    USE SIGNAL ;
    PORT
      LAYER M4 ;
        RECT  43.116 65.76 43.2 65.784 ;
    END
  END o_y[351]
  PIN o_y[352]
    DIRECTION OUTPUT ;
    USE SIGNAL ;
    PORT
      LAYER M4 ;
        RECT  43.116 65.904 43.2 65.928 ;
    END
  END o_y[352]
  PIN o_y[353]
    DIRECTION OUTPUT ;
    USE SIGNAL ;
    PORT
      LAYER M4 ;
        RECT  43.116 66 43.2 66.024 ;
    END
  END o_y[353]
  PIN o_y[354]
    DIRECTION OUTPUT ;
    USE SIGNAL ;
    PORT
      LAYER M4 ;
        RECT  43.116 66.144 43.2 66.168 ;
    END
  END o_y[354]
  PIN o_y[355]
    DIRECTION OUTPUT ;
    USE SIGNAL ;
    PORT
      LAYER M4 ;
        RECT  43.116 66.288 43.2 66.312 ;
    END
  END o_y[355]
  PIN o_y[356]
    DIRECTION OUTPUT ;
    USE SIGNAL ;
    PORT
      LAYER M4 ;
        RECT  43.116 66.384 43.2 66.408 ;
    END
  END o_y[356]
  PIN o_y[357]
    DIRECTION OUTPUT ;
    USE SIGNAL ;
    PORT
      LAYER M4 ;
        RECT  43.116 66.528 43.2 66.552 ;
    END
  END o_y[357]
  PIN o_y[358]
    DIRECTION OUTPUT ;
    USE SIGNAL ;
    PORT
      LAYER M4 ;
        RECT  43.116 66.672 43.2 66.696 ;
    END
  END o_y[358]
  PIN o_y[359]
    DIRECTION OUTPUT ;
    USE SIGNAL ;
    PORT
      LAYER M4 ;
        RECT  43.116 66.768 43.2 66.792 ;
    END
  END o_y[359]
  PIN o_y[35]
    DIRECTION OUTPUT ;
    USE SIGNAL ;
    PORT
      LAYER M4 ;
        RECT  43.116 25.104 43.2 25.128 ;
    END
  END o_y[35]
  PIN o_y[360]
    DIRECTION OUTPUT ;
    USE SIGNAL ;
    PORT
      LAYER M4 ;
        RECT  43.116 66.912 43.2 66.936 ;
    END
  END o_y[360]
  PIN o_y[361]
    DIRECTION OUTPUT ;
    USE SIGNAL ;
    PORT
      LAYER M4 ;
        RECT  43.116 67.056 43.2 67.08 ;
    END
  END o_y[361]
  PIN o_y[362]
    DIRECTION OUTPUT ;
    USE SIGNAL ;
    PORT
      LAYER M4 ;
        RECT  43.116 67.152 43.2 67.176 ;
    END
  END o_y[362]
  PIN o_y[363]
    DIRECTION OUTPUT ;
    USE SIGNAL ;
    PORT
      LAYER M4 ;
        RECT  43.116 67.296 43.2 67.32 ;
    END
  END o_y[363]
  PIN o_y[364]
    DIRECTION OUTPUT ;
    USE SIGNAL ;
    PORT
      LAYER M4 ;
        RECT  43.116 67.44 43.2 67.464 ;
    END
  END o_y[364]
  PIN o_y[365]
    DIRECTION OUTPUT ;
    USE SIGNAL ;
    PORT
      LAYER M4 ;
        RECT  43.116 67.536 43.2 67.56 ;
    END
  END o_y[365]
  PIN o_y[366]
    DIRECTION OUTPUT ;
    USE SIGNAL ;
    PORT
      LAYER M4 ;
        RECT  43.116 67.68 43.2 67.704 ;
    END
  END o_y[366]
  PIN o_y[367]
    DIRECTION OUTPUT ;
    USE SIGNAL ;
    PORT
      LAYER M4 ;
        RECT  43.116 67.824 43.2 67.848 ;
    END
  END o_y[367]
  PIN o_y[368]
    DIRECTION OUTPUT ;
    USE SIGNAL ;
    PORT
      LAYER M4 ;
        RECT  43.116 67.92 43.2 67.944 ;
    END
  END o_y[368]
  PIN o_y[369]
    DIRECTION OUTPUT ;
    USE SIGNAL ;
    PORT
      LAYER M4 ;
        RECT  43.116 68.064 43.2 68.088 ;
    END
  END o_y[369]
  PIN o_y[36]
    DIRECTION OUTPUT ;
    USE SIGNAL ;
    PORT
      LAYER M4 ;
        RECT  43.116 25.248 43.2 25.272 ;
    END
  END o_y[36]
  PIN o_y[370]
    DIRECTION OUTPUT ;
    USE SIGNAL ;
    PORT
      LAYER M4 ;
        RECT  43.116 68.208 43.2 68.232 ;
    END
  END o_y[370]
  PIN o_y[371]
    DIRECTION OUTPUT ;
    USE SIGNAL ;
    PORT
      LAYER M4 ;
        RECT  43.116 68.304 43.2 68.328 ;
    END
  END o_y[371]
  PIN o_y[372]
    DIRECTION OUTPUT ;
    USE SIGNAL ;
    PORT
      LAYER M4 ;
        RECT  43.116 68.448 43.2 68.472 ;
    END
  END o_y[372]
  PIN o_y[373]
    DIRECTION OUTPUT ;
    USE SIGNAL ;
    PORT
      LAYER M4 ;
        RECT  43.116 68.592 43.2 68.616 ;
    END
  END o_y[373]
  PIN o_y[374]
    DIRECTION OUTPUT ;
    USE SIGNAL ;
    PORT
      LAYER M4 ;
        RECT  43.116 68.688 43.2 68.712 ;
    END
  END o_y[374]
  PIN o_y[375]
    DIRECTION OUTPUT ;
    USE SIGNAL ;
    PORT
      LAYER M4 ;
        RECT  43.116 68.832 43.2 68.856 ;
    END
  END o_y[375]
  PIN o_y[376]
    DIRECTION OUTPUT ;
    USE SIGNAL ;
    PORT
      LAYER M4 ;
        RECT  43.116 68.976 43.2 69 ;
    END
  END o_y[376]
  PIN o_y[377]
    DIRECTION OUTPUT ;
    USE SIGNAL ;
    PORT
      LAYER M4 ;
        RECT  43.116 69.072 43.2 69.096 ;
    END
  END o_y[377]
  PIN o_y[378]
    DIRECTION OUTPUT ;
    USE SIGNAL ;
    PORT
      LAYER M4 ;
        RECT  43.116 69.216 43.2 69.24 ;
    END
  END o_y[378]
  PIN o_y[379]
    DIRECTION OUTPUT ;
    USE SIGNAL ;
    PORT
      LAYER M4 ;
        RECT  43.116 69.36 43.2 69.384 ;
    END
  END o_y[379]
  PIN o_y[37]
    DIRECTION OUTPUT ;
    USE SIGNAL ;
    PORT
      LAYER M4 ;
        RECT  43.116 25.392 43.2 25.416 ;
    END
  END o_y[37]
  PIN o_y[380]
    DIRECTION OUTPUT ;
    USE SIGNAL ;
    PORT
      LAYER M4 ;
        RECT  43.116 69.504 43.2 69.528 ;
    END
  END o_y[380]
  PIN o_y[381]
    DIRECTION OUTPUT ;
    USE SIGNAL ;
    PORT
      LAYER M4 ;
        RECT  43.116 69.6 43.2 69.624 ;
    END
  END o_y[381]
  PIN o_y[382]
    DIRECTION OUTPUT ;
    USE SIGNAL ;
    PORT
      LAYER M4 ;
        RECT  43.116 69.744 43.2 69.768 ;
    END
  END o_y[382]
  PIN o_y[383]
    DIRECTION OUTPUT ;
    USE SIGNAL ;
    PORT
      LAYER M4 ;
        RECT  43.116 69.888 43.2 69.912 ;
    END
  END o_y[383]
  PIN o_y[384]
    DIRECTION OUTPUT ;
    USE SIGNAL ;
    PORT
      LAYER M4 ;
        RECT  43.116 69.984 43.2 70.008 ;
    END
  END o_y[384]
  PIN o_y[385]
    DIRECTION OUTPUT ;
    USE SIGNAL ;
    PORT
      LAYER M4 ;
        RECT  43.116 70.128 43.2 70.152 ;
    END
  END o_y[385]
  PIN o_y[386]
    DIRECTION OUTPUT ;
    USE SIGNAL ;
    PORT
      LAYER M4 ;
        RECT  43.116 70.272 43.2 70.296 ;
    END
  END o_y[386]
  PIN o_y[387]
    DIRECTION OUTPUT ;
    USE SIGNAL ;
    PORT
      LAYER M4 ;
        RECT  43.116 70.368 43.2 70.392 ;
    END
  END o_y[387]
  PIN o_y[388]
    DIRECTION OUTPUT ;
    USE SIGNAL ;
    PORT
      LAYER M4 ;
        RECT  43.116 70.512 43.2 70.536 ;
    END
  END o_y[388]
  PIN o_y[389]
    DIRECTION OUTPUT ;
    USE SIGNAL ;
    PORT
      LAYER M4 ;
        RECT  43.116 70.656 43.2 70.68 ;
    END
  END o_y[389]
  PIN o_y[38]
    DIRECTION OUTPUT ;
    USE SIGNAL ;
    PORT
      LAYER M4 ;
        RECT  43.116 25.488 43.2 25.512 ;
    END
  END o_y[38]
  PIN o_y[390]
    DIRECTION OUTPUT ;
    USE SIGNAL ;
    PORT
      LAYER M4 ;
        RECT  43.116 70.752 43.2 70.776 ;
    END
  END o_y[390]
  PIN o_y[391]
    DIRECTION OUTPUT ;
    USE SIGNAL ;
    PORT
      LAYER M4 ;
        RECT  43.116 70.896 43.2 70.92 ;
    END
  END o_y[391]
  PIN o_y[392]
    DIRECTION OUTPUT ;
    USE SIGNAL ;
    PORT
      LAYER M4 ;
        RECT  43.116 71.04 43.2 71.064 ;
    END
  END o_y[392]
  PIN o_y[393]
    DIRECTION OUTPUT ;
    USE SIGNAL ;
    PORT
      LAYER M4 ;
        RECT  43.116 71.136 43.2 71.16 ;
    END
  END o_y[393]
  PIN o_y[394]
    DIRECTION OUTPUT ;
    USE SIGNAL ;
    PORT
      LAYER M4 ;
        RECT  43.116 71.28 43.2 71.304 ;
    END
  END o_y[394]
  PIN o_y[395]
    DIRECTION OUTPUT ;
    USE SIGNAL ;
    PORT
      LAYER M4 ;
        RECT  43.116 71.424 43.2 71.448 ;
    END
  END o_y[395]
  PIN o_y[396]
    DIRECTION OUTPUT ;
    USE SIGNAL ;
    PORT
      LAYER M4 ;
        RECT  43.116 71.52 43.2 71.544 ;
    END
  END o_y[396]
  PIN o_y[397]
    DIRECTION OUTPUT ;
    USE SIGNAL ;
    PORT
      LAYER M4 ;
        RECT  43.116 71.664 43.2 71.688 ;
    END
  END o_y[397]
  PIN o_y[398]
    DIRECTION OUTPUT ;
    USE SIGNAL ;
    PORT
      LAYER M4 ;
        RECT  43.116 71.808 43.2 71.832 ;
    END
  END o_y[398]
  PIN o_y[399]
    DIRECTION OUTPUT ;
    USE SIGNAL ;
    PORT
      LAYER M4 ;
        RECT  43.116 71.904 43.2 71.928 ;
    END
  END o_y[399]
  PIN o_y[39]
    DIRECTION OUTPUT ;
    USE SIGNAL ;
    PORT
      LAYER M4 ;
        RECT  43.116 25.632 43.2 25.656 ;
    END
  END o_y[39]
  PIN o_y[3]
    DIRECTION OUTPUT ;
    USE SIGNAL ;
    PORT
      LAYER M4 ;
        RECT  43.116 21.024 43.2 21.048 ;
    END
  END o_y[3]
  PIN o_y[400]
    DIRECTION OUTPUT ;
    USE SIGNAL ;
    PORT
      LAYER M4 ;
        RECT  43.116 72.048 43.2 72.072 ;
    END
  END o_y[400]
  PIN o_y[401]
    DIRECTION OUTPUT ;
    USE SIGNAL ;
    PORT
      LAYER M4 ;
        RECT  43.116 72.192 43.2 72.216 ;
    END
  END o_y[401]
  PIN o_y[402]
    DIRECTION OUTPUT ;
    USE SIGNAL ;
    PORT
      LAYER M4 ;
        RECT  43.116 72.288 43.2 72.312 ;
    END
  END o_y[402]
  PIN o_y[403]
    DIRECTION OUTPUT ;
    USE SIGNAL ;
    PORT
      LAYER M4 ;
        RECT  43.116 72.432 43.2 72.456 ;
    END
  END o_y[403]
  PIN o_y[404]
    DIRECTION OUTPUT ;
    USE SIGNAL ;
    PORT
      LAYER M4 ;
        RECT  43.116 72.576 43.2 72.6 ;
    END
  END o_y[404]
  PIN o_y[405]
    DIRECTION OUTPUT ;
    USE SIGNAL ;
    PORT
      LAYER M4 ;
        RECT  43.116 72.672 43.2 72.696 ;
    END
  END o_y[405]
  PIN o_y[406]
    DIRECTION OUTPUT ;
    USE SIGNAL ;
    PORT
      LAYER M4 ;
        RECT  43.116 72.816 43.2 72.84 ;
    END
  END o_y[406]
  PIN o_y[407]
    DIRECTION OUTPUT ;
    USE SIGNAL ;
    PORT
      LAYER M4 ;
        RECT  43.116 72.96 43.2 72.984 ;
    END
  END o_y[407]
  PIN o_y[408]
    DIRECTION OUTPUT ;
    USE SIGNAL ;
    PORT
      LAYER M4 ;
        RECT  43.116 73.104 43.2 73.128 ;
    END
  END o_y[408]
  PIN o_y[409]
    DIRECTION OUTPUT ;
    USE SIGNAL ;
    PORT
      LAYER M4 ;
        RECT  43.116 73.2 43.2 73.224 ;
    END
  END o_y[409]
  PIN o_y[40]
    DIRECTION OUTPUT ;
    USE SIGNAL ;
    PORT
      LAYER M4 ;
        RECT  43.116 25.776 43.2 25.8 ;
    END
  END o_y[40]
  PIN o_y[410]
    DIRECTION OUTPUT ;
    USE SIGNAL ;
    PORT
      LAYER M4 ;
        RECT  43.116 73.344 43.2 73.368 ;
    END
  END o_y[410]
  PIN o_y[411]
    DIRECTION OUTPUT ;
    USE SIGNAL ;
    PORT
      LAYER M4 ;
        RECT  43.116 73.488 43.2 73.512 ;
    END
  END o_y[411]
  PIN o_y[412]
    DIRECTION OUTPUT ;
    USE SIGNAL ;
    PORT
      LAYER M4 ;
        RECT  43.116 73.584 43.2 73.608 ;
    END
  END o_y[412]
  PIN o_y[413]
    DIRECTION OUTPUT ;
    USE SIGNAL ;
    PORT
      LAYER M4 ;
        RECT  43.116 73.728 43.2 73.752 ;
    END
  END o_y[413]
  PIN o_y[414]
    DIRECTION OUTPUT ;
    USE SIGNAL ;
    PORT
      LAYER M4 ;
        RECT  43.116 73.872 43.2 73.896 ;
    END
  END o_y[414]
  PIN o_y[415]
    DIRECTION OUTPUT ;
    USE SIGNAL ;
    PORT
      LAYER M4 ;
        RECT  43.116 73.968 43.2 73.992 ;
    END
  END o_y[415]
  PIN o_y[416]
    DIRECTION OUTPUT ;
    USE SIGNAL ;
    PORT
      LAYER M4 ;
        RECT  43.116 74.112 43.2 74.136 ;
    END
  END o_y[416]
  PIN o_y[417]
    DIRECTION OUTPUT ;
    USE SIGNAL ;
    PORT
      LAYER M4 ;
        RECT  43.116 74.256 43.2 74.28 ;
    END
  END o_y[417]
  PIN o_y[418]
    DIRECTION OUTPUT ;
    USE SIGNAL ;
    PORT
      LAYER M4 ;
        RECT  43.116 74.352 43.2 74.376 ;
    END
  END o_y[418]
  PIN o_y[419]
    DIRECTION OUTPUT ;
    USE SIGNAL ;
    PORT
      LAYER M4 ;
        RECT  43.116 74.496 43.2 74.52 ;
    END
  END o_y[419]
  PIN o_y[41]
    DIRECTION OUTPUT ;
    USE SIGNAL ;
    PORT
      LAYER M4 ;
        RECT  43.116 25.872 43.2 25.896 ;
    END
  END o_y[41]
  PIN o_y[420]
    DIRECTION OUTPUT ;
    USE SIGNAL ;
    PORT
      LAYER M4 ;
        RECT  43.116 74.64 43.2 74.664 ;
    END
  END o_y[420]
  PIN o_y[421]
    DIRECTION OUTPUT ;
    USE SIGNAL ;
    PORT
      LAYER M4 ;
        RECT  43.116 74.736 43.2 74.76 ;
    END
  END o_y[421]
  PIN o_y[422]
    DIRECTION OUTPUT ;
    USE SIGNAL ;
    PORT
      LAYER M4 ;
        RECT  43.116 74.88 43.2 74.904 ;
    END
  END o_y[422]
  PIN o_y[423]
    DIRECTION OUTPUT ;
    USE SIGNAL ;
    PORT
      LAYER M4 ;
        RECT  43.116 75.024 43.2 75.048 ;
    END
  END o_y[423]
  PIN o_y[424]
    DIRECTION OUTPUT ;
    USE SIGNAL ;
    PORT
      LAYER M4 ;
        RECT  43.116 75.12 43.2 75.144 ;
    END
  END o_y[424]
  PIN o_y[425]
    DIRECTION OUTPUT ;
    USE SIGNAL ;
    PORT
      LAYER M4 ;
        RECT  43.116 75.264 43.2 75.288 ;
    END
  END o_y[425]
  PIN o_y[426]
    DIRECTION OUTPUT ;
    USE SIGNAL ;
    PORT
      LAYER M4 ;
        RECT  43.116 75.408 43.2 75.432 ;
    END
  END o_y[426]
  PIN o_y[427]
    DIRECTION OUTPUT ;
    USE SIGNAL ;
    PORT
      LAYER M4 ;
        RECT  43.116 75.504 43.2 75.528 ;
    END
  END o_y[427]
  PIN o_y[428]
    DIRECTION OUTPUT ;
    USE SIGNAL ;
    PORT
      LAYER M4 ;
        RECT  43.116 75.648 43.2 75.672 ;
    END
  END o_y[428]
  PIN o_y[429]
    DIRECTION OUTPUT ;
    USE SIGNAL ;
    PORT
      LAYER M4 ;
        RECT  43.116 75.792 43.2 75.816 ;
    END
  END o_y[429]
  PIN o_y[42]
    DIRECTION OUTPUT ;
    USE SIGNAL ;
    PORT
      LAYER M4 ;
        RECT  43.116 26.016 43.2 26.04 ;
    END
  END o_y[42]
  PIN o_y[430]
    DIRECTION OUTPUT ;
    USE SIGNAL ;
    PORT
      LAYER M4 ;
        RECT  43.116 75.888 43.2 75.912 ;
    END
  END o_y[430]
  PIN o_y[431]
    DIRECTION OUTPUT ;
    USE SIGNAL ;
    PORT
      LAYER M4 ;
        RECT  43.116 76.032 43.2 76.056 ;
    END
  END o_y[431]
  PIN o_y[432]
    DIRECTION OUTPUT ;
    USE SIGNAL ;
    PORT
      LAYER M4 ;
        RECT  43.116 76.176 43.2 76.2 ;
    END
  END o_y[432]
  PIN o_y[433]
    DIRECTION OUTPUT ;
    USE SIGNAL ;
    PORT
      LAYER M4 ;
        RECT  43.116 76.272 43.2 76.296 ;
    END
  END o_y[433]
  PIN o_y[434]
    DIRECTION OUTPUT ;
    USE SIGNAL ;
    PORT
      LAYER M4 ;
        RECT  43.116 76.416 43.2 76.44 ;
    END
  END o_y[434]
  PIN o_y[435]
    DIRECTION OUTPUT ;
    USE SIGNAL ;
    PORT
      LAYER M4 ;
        RECT  43.116 76.56 43.2 76.584 ;
    END
  END o_y[435]
  PIN o_y[436]
    DIRECTION OUTPUT ;
    USE SIGNAL ;
    PORT
      LAYER M4 ;
        RECT  43.116 76.704 43.2 76.728 ;
    END
  END o_y[436]
  PIN o_y[437]
    DIRECTION OUTPUT ;
    USE SIGNAL ;
    PORT
      LAYER M4 ;
        RECT  43.116 76.8 43.2 76.824 ;
    END
  END o_y[437]
  PIN o_y[438]
    DIRECTION OUTPUT ;
    USE SIGNAL ;
    PORT
      LAYER M4 ;
        RECT  43.116 76.944 43.2 76.968 ;
    END
  END o_y[438]
  PIN o_y[439]
    DIRECTION OUTPUT ;
    USE SIGNAL ;
    PORT
      LAYER M4 ;
        RECT  43.116 77.088 43.2 77.112 ;
    END
  END o_y[439]
  PIN o_y[43]
    DIRECTION OUTPUT ;
    USE SIGNAL ;
    PORT
      LAYER M4 ;
        RECT  43.116 26.16 43.2 26.184 ;
    END
  END o_y[43]
  PIN o_y[440]
    DIRECTION OUTPUT ;
    USE SIGNAL ;
    PORT
      LAYER M4 ;
        RECT  43.116 77.184 43.2 77.208 ;
    END
  END o_y[440]
  PIN o_y[441]
    DIRECTION OUTPUT ;
    USE SIGNAL ;
    PORT
      LAYER M4 ;
        RECT  43.116 77.328 43.2 77.352 ;
    END
  END o_y[441]
  PIN o_y[442]
    DIRECTION OUTPUT ;
    USE SIGNAL ;
    PORT
      LAYER M4 ;
        RECT  43.116 77.472 43.2 77.496 ;
    END
  END o_y[442]
  PIN o_y[443]
    DIRECTION OUTPUT ;
    USE SIGNAL ;
    PORT
      LAYER M4 ;
        RECT  43.116 77.568 43.2 77.592 ;
    END
  END o_y[443]
  PIN o_y[444]
    DIRECTION OUTPUT ;
    USE SIGNAL ;
    PORT
      LAYER M4 ;
        RECT  43.116 77.712 43.2 77.736 ;
    END
  END o_y[444]
  PIN o_y[445]
    DIRECTION OUTPUT ;
    USE SIGNAL ;
    PORT
      LAYER M4 ;
        RECT  43.116 77.856 43.2 77.88 ;
    END
  END o_y[445]
  PIN o_y[446]
    DIRECTION OUTPUT ;
    USE SIGNAL ;
    PORT
      LAYER M4 ;
        RECT  43.116 77.952 43.2 77.976 ;
    END
  END o_y[446]
  PIN o_y[447]
    DIRECTION OUTPUT ;
    USE SIGNAL ;
    PORT
      LAYER M4 ;
        RECT  43.116 78.096 43.2 78.12 ;
    END
  END o_y[447]
  PIN o_y[448]
    DIRECTION OUTPUT ;
    USE SIGNAL ;
    PORT
      LAYER M4 ;
        RECT  43.116 78.24 43.2 78.264 ;
    END
  END o_y[448]
  PIN o_y[449]
    DIRECTION OUTPUT ;
    USE SIGNAL ;
    PORT
      LAYER M4 ;
        RECT  43.116 78.336 43.2 78.36 ;
    END
  END o_y[449]
  PIN o_y[44]
    DIRECTION OUTPUT ;
    USE SIGNAL ;
    PORT
      LAYER M4 ;
        RECT  43.116 26.304 43.2 26.328 ;
    END
  END o_y[44]
  PIN o_y[450]
    DIRECTION OUTPUT ;
    USE SIGNAL ;
    PORT
      LAYER M4 ;
        RECT  43.116 78.48 43.2 78.504 ;
    END
  END o_y[450]
  PIN o_y[451]
    DIRECTION OUTPUT ;
    USE SIGNAL ;
    PORT
      LAYER M4 ;
        RECT  43.116 78.624 43.2 78.648 ;
    END
  END o_y[451]
  PIN o_y[452]
    DIRECTION OUTPUT ;
    USE SIGNAL ;
    PORT
      LAYER M4 ;
        RECT  43.116 78.72 43.2 78.744 ;
    END
  END o_y[452]
  PIN o_y[453]
    DIRECTION OUTPUT ;
    USE SIGNAL ;
    PORT
      LAYER M4 ;
        RECT  43.116 78.864 43.2 78.888 ;
    END
  END o_y[453]
  PIN o_y[454]
    DIRECTION OUTPUT ;
    USE SIGNAL ;
    PORT
      LAYER M4 ;
        RECT  43.116 79.008 43.2 79.032 ;
    END
  END o_y[454]
  PIN o_y[455]
    DIRECTION OUTPUT ;
    USE SIGNAL ;
    PORT
      LAYER M4 ;
        RECT  43.116 79.104 43.2 79.128 ;
    END
  END o_y[455]
  PIN o_y[456]
    DIRECTION OUTPUT ;
    USE SIGNAL ;
    PORT
      LAYER M4 ;
        RECT  43.116 79.248 43.2 79.272 ;
    END
  END o_y[456]
  PIN o_y[457]
    DIRECTION OUTPUT ;
    USE SIGNAL ;
    PORT
      LAYER M4 ;
        RECT  43.116 79.392 43.2 79.416 ;
    END
  END o_y[457]
  PIN o_y[458]
    DIRECTION OUTPUT ;
    USE SIGNAL ;
    PORT
      LAYER M4 ;
        RECT  43.116 79.488 43.2 79.512 ;
    END
  END o_y[458]
  PIN o_y[459]
    DIRECTION OUTPUT ;
    USE SIGNAL ;
    PORT
      LAYER M4 ;
        RECT  43.116 79.632 43.2 79.656 ;
    END
  END o_y[459]
  PIN o_y[45]
    DIRECTION OUTPUT ;
    USE SIGNAL ;
    PORT
      LAYER M4 ;
        RECT  43.116 26.4 43.2 26.424 ;
    END
  END o_y[45]
  PIN o_y[460]
    DIRECTION OUTPUT ;
    USE SIGNAL ;
    PORT
      LAYER M4 ;
        RECT  43.116 79.776 43.2 79.8 ;
    END
  END o_y[460]
  PIN o_y[461]
    DIRECTION OUTPUT ;
    USE SIGNAL ;
    PORT
      LAYER M4 ;
        RECT  43.116 79.872 43.2 79.896 ;
    END
  END o_y[461]
  PIN o_y[462]
    DIRECTION OUTPUT ;
    USE SIGNAL ;
    PORT
      LAYER M4 ;
        RECT  43.116 80.016 43.2 80.04 ;
    END
  END o_y[462]
  PIN o_y[463]
    DIRECTION OUTPUT ;
    USE SIGNAL ;
    PORT
      LAYER M4 ;
        RECT  43.116 80.16 43.2 80.184 ;
    END
  END o_y[463]
  PIN o_y[464]
    DIRECTION OUTPUT ;
    USE SIGNAL ;
    PORT
      LAYER M4 ;
        RECT  43.116 80.304 43.2 80.328 ;
    END
  END o_y[464]
  PIN o_y[465]
    DIRECTION OUTPUT ;
    USE SIGNAL ;
    PORT
      LAYER M4 ;
        RECT  43.116 80.4 43.2 80.424 ;
    END
  END o_y[465]
  PIN o_y[466]
    DIRECTION OUTPUT ;
    USE SIGNAL ;
    PORT
      LAYER M4 ;
        RECT  43.116 80.544 43.2 80.568 ;
    END
  END o_y[466]
  PIN o_y[467]
    DIRECTION OUTPUT ;
    USE SIGNAL ;
    PORT
      LAYER M4 ;
        RECT  43.116 80.688 43.2 80.712 ;
    END
  END o_y[467]
  PIN o_y[468]
    DIRECTION OUTPUT ;
    USE SIGNAL ;
    PORT
      LAYER M4 ;
        RECT  43.116 80.784 43.2 80.808 ;
    END
  END o_y[468]
  PIN o_y[469]
    DIRECTION OUTPUT ;
    USE SIGNAL ;
    PORT
      LAYER M4 ;
        RECT  43.116 80.928 43.2 80.952 ;
    END
  END o_y[469]
  PIN o_y[46]
    DIRECTION OUTPUT ;
    USE SIGNAL ;
    PORT
      LAYER M4 ;
        RECT  43.116 26.544 43.2 26.568 ;
    END
  END o_y[46]
  PIN o_y[470]
    DIRECTION OUTPUT ;
    USE SIGNAL ;
    PORT
      LAYER M4 ;
        RECT  43.116 81.072 43.2 81.096 ;
    END
  END o_y[470]
  PIN o_y[471]
    DIRECTION OUTPUT ;
    USE SIGNAL ;
    PORT
      LAYER M4 ;
        RECT  43.116 81.168 43.2 81.192 ;
    END
  END o_y[471]
  PIN o_y[472]
    DIRECTION OUTPUT ;
    USE SIGNAL ;
    PORT
      LAYER M4 ;
        RECT  43.116 81.312 43.2 81.336 ;
    END
  END o_y[472]
  PIN o_y[473]
    DIRECTION OUTPUT ;
    USE SIGNAL ;
    PORT
      LAYER M4 ;
        RECT  43.116 81.456 43.2 81.48 ;
    END
  END o_y[473]
  PIN o_y[474]
    DIRECTION OUTPUT ;
    USE SIGNAL ;
    PORT
      LAYER M4 ;
        RECT  43.116 81.552 43.2 81.576 ;
    END
  END o_y[474]
  PIN o_y[475]
    DIRECTION OUTPUT ;
    USE SIGNAL ;
    PORT
      LAYER M4 ;
        RECT  43.116 81.696 43.2 81.72 ;
    END
  END o_y[475]
  PIN o_y[476]
    DIRECTION OUTPUT ;
    USE SIGNAL ;
    PORT
      LAYER M4 ;
        RECT  43.116 81.84 43.2 81.864 ;
    END
  END o_y[476]
  PIN o_y[477]
    DIRECTION OUTPUT ;
    USE SIGNAL ;
    PORT
      LAYER M4 ;
        RECT  43.116 81.936 43.2 81.96 ;
    END
  END o_y[477]
  PIN o_y[478]
    DIRECTION OUTPUT ;
    USE SIGNAL ;
    PORT
      LAYER M4 ;
        RECT  43.116 82.08 43.2 82.104 ;
    END
  END o_y[478]
  PIN o_y[479]
    DIRECTION OUTPUT ;
    USE SIGNAL ;
    PORT
      LAYER M4 ;
        RECT  43.116 82.224 43.2 82.248 ;
    END
  END o_y[479]
  PIN o_y[47]
    DIRECTION OUTPUT ;
    USE SIGNAL ;
    PORT
      LAYER M4 ;
        RECT  43.116 26.688 43.2 26.712 ;
    END
  END o_y[47]
  PIN o_y[480]
    DIRECTION OUTPUT ;
    USE SIGNAL ;
    PORT
      LAYER M4 ;
        RECT  43.116 82.32 43.2 82.344 ;
    END
  END o_y[480]
  PIN o_y[481]
    DIRECTION OUTPUT ;
    USE SIGNAL ;
    PORT
      LAYER M4 ;
        RECT  43.116 82.464 43.2 82.488 ;
    END
  END o_y[481]
  PIN o_y[482]
    DIRECTION OUTPUT ;
    USE SIGNAL ;
    PORT
      LAYER M4 ;
        RECT  43.116 82.608 43.2 82.632 ;
    END
  END o_y[482]
  PIN o_y[483]
    DIRECTION OUTPUT ;
    USE SIGNAL ;
    PORT
      LAYER M4 ;
        RECT  43.116 82.704 43.2 82.728 ;
    END
  END o_y[483]
  PIN o_y[484]
    DIRECTION OUTPUT ;
    USE SIGNAL ;
    PORT
      LAYER M4 ;
        RECT  43.116 82.848 43.2 82.872 ;
    END
  END o_y[484]
  PIN o_y[485]
    DIRECTION OUTPUT ;
    USE SIGNAL ;
    PORT
      LAYER M4 ;
        RECT  43.116 82.992 43.2 83.016 ;
    END
  END o_y[485]
  PIN o_y[486]
    DIRECTION OUTPUT ;
    USE SIGNAL ;
    PORT
      LAYER M4 ;
        RECT  43.116 83.088 43.2 83.112 ;
    END
  END o_y[486]
  PIN o_y[487]
    DIRECTION OUTPUT ;
    USE SIGNAL ;
    PORT
      LAYER M4 ;
        RECT  43.116 83.232 43.2 83.256 ;
    END
  END o_y[487]
  PIN o_y[488]
    DIRECTION OUTPUT ;
    USE SIGNAL ;
    PORT
      LAYER M4 ;
        RECT  43.116 83.376 43.2 83.4 ;
    END
  END o_y[488]
  PIN o_y[489]
    DIRECTION OUTPUT ;
    USE SIGNAL ;
    PORT
      LAYER M4 ;
        RECT  43.116 83.472 43.2 83.496 ;
    END
  END o_y[489]
  PIN o_y[48]
    DIRECTION OUTPUT ;
    USE SIGNAL ;
    PORT
      LAYER M4 ;
        RECT  43.116 26.784 43.2 26.808 ;
    END
  END o_y[48]
  PIN o_y[490]
    DIRECTION OUTPUT ;
    USE SIGNAL ;
    PORT
      LAYER M4 ;
        RECT  43.116 83.616 43.2 83.64 ;
    END
  END o_y[490]
  PIN o_y[491]
    DIRECTION OUTPUT ;
    USE SIGNAL ;
    PORT
      LAYER M4 ;
        RECT  43.116 83.76 43.2 83.784 ;
    END
  END o_y[491]
  PIN o_y[492]
    DIRECTION OUTPUT ;
    USE SIGNAL ;
    PORT
      LAYER M4 ;
        RECT  43.116 83.904 43.2 83.928 ;
    END
  END o_y[492]
  PIN o_y[493]
    DIRECTION OUTPUT ;
    USE SIGNAL ;
    PORT
      LAYER M4 ;
        RECT  43.116 84 43.2 84.024 ;
    END
  END o_y[493]
  PIN o_y[494]
    DIRECTION OUTPUT ;
    USE SIGNAL ;
    PORT
      LAYER M4 ;
        RECT  43.116 84.144 43.2 84.168 ;
    END
  END o_y[494]
  PIN o_y[495]
    DIRECTION OUTPUT ;
    USE SIGNAL ;
    PORT
      LAYER M4 ;
        RECT  43.116 84.288 43.2 84.312 ;
    END
  END o_y[495]
  PIN o_y[496]
    DIRECTION OUTPUT ;
    USE SIGNAL ;
    PORT
      LAYER M4 ;
        RECT  43.116 84.384 43.2 84.408 ;
    END
  END o_y[496]
  PIN o_y[497]
    DIRECTION OUTPUT ;
    USE SIGNAL ;
    PORT
      LAYER M4 ;
        RECT  43.116 84.528 43.2 84.552 ;
    END
  END o_y[497]
  PIN o_y[498]
    DIRECTION OUTPUT ;
    USE SIGNAL ;
    PORT
      LAYER M4 ;
        RECT  43.116 84.672 43.2 84.696 ;
    END
  END o_y[498]
  PIN o_y[499]
    DIRECTION OUTPUT ;
    USE SIGNAL ;
    PORT
      LAYER M4 ;
        RECT  43.116 84.768 43.2 84.792 ;
    END
  END o_y[499]
  PIN o_y[49]
    DIRECTION OUTPUT ;
    USE SIGNAL ;
    PORT
      LAYER M4 ;
        RECT  43.116 26.928 43.2 26.952 ;
    END
  END o_y[49]
  PIN o_y[4]
    DIRECTION OUTPUT ;
    USE SIGNAL ;
    PORT
      LAYER M4 ;
        RECT  43.116 21.12 43.2 21.144 ;
    END
  END o_y[4]
  PIN o_y[500]
    DIRECTION OUTPUT ;
    USE SIGNAL ;
    PORT
      LAYER M4 ;
        RECT  43.116 84.912 43.2 84.936 ;
    END
  END o_y[500]
  PIN o_y[501]
    DIRECTION OUTPUT ;
    USE SIGNAL ;
    PORT
      LAYER M4 ;
        RECT  43.116 85.056 43.2 85.08 ;
    END
  END o_y[501]
  PIN o_y[502]
    DIRECTION OUTPUT ;
    USE SIGNAL ;
    PORT
      LAYER M4 ;
        RECT  43.116 85.152 43.2 85.176 ;
    END
  END o_y[502]
  PIN o_y[503]
    DIRECTION OUTPUT ;
    USE SIGNAL ;
    PORT
      LAYER M4 ;
        RECT  43.116 85.296 43.2 85.32 ;
    END
  END o_y[503]
  PIN o_y[504]
    DIRECTION OUTPUT ;
    USE SIGNAL ;
    PORT
      LAYER M4 ;
        RECT  43.116 85.44 43.2 85.464 ;
    END
  END o_y[504]
  PIN o_y[505]
    DIRECTION OUTPUT ;
    USE SIGNAL ;
    PORT
      LAYER M4 ;
        RECT  43.116 85.536 43.2 85.56 ;
    END
  END o_y[505]
  PIN o_y[506]
    DIRECTION OUTPUT ;
    USE SIGNAL ;
    PORT
      LAYER M4 ;
        RECT  43.116 85.68 43.2 85.704 ;
    END
  END o_y[506]
  PIN o_y[507]
    DIRECTION OUTPUT ;
    USE SIGNAL ;
    PORT
      LAYER M4 ;
        RECT  43.116 85.824 43.2 85.848 ;
    END
  END o_y[507]
  PIN o_y[508]
    DIRECTION OUTPUT ;
    USE SIGNAL ;
    PORT
      LAYER M4 ;
        RECT  43.116 85.92 43.2 85.944 ;
    END
  END o_y[508]
  PIN o_y[509]
    DIRECTION OUTPUT ;
    USE SIGNAL ;
    PORT
      LAYER M4 ;
        RECT  43.116 86.064 43.2 86.088 ;
    END
  END o_y[509]
  PIN o_y[50]
    DIRECTION OUTPUT ;
    USE SIGNAL ;
    PORT
      LAYER M4 ;
        RECT  43.116 27.072 43.2 27.096 ;
    END
  END o_y[50]
  PIN o_y[510]
    DIRECTION OUTPUT ;
    USE SIGNAL ;
    PORT
      LAYER M4 ;
        RECT  43.116 86.208 43.2 86.232 ;
    END
  END o_y[510]
  PIN o_y[511]
    DIRECTION OUTPUT ;
    USE SIGNAL ;
    PORT
      LAYER M4 ;
        RECT  43.116 86.304 43.2 86.328 ;
    END
  END o_y[511]
  PIN o_y[51]
    DIRECTION OUTPUT ;
    USE SIGNAL ;
    PORT
      LAYER M4 ;
        RECT  43.116 27.168 43.2 27.192 ;
    END
  END o_y[51]
  PIN o_y[52]
    DIRECTION OUTPUT ;
    USE SIGNAL ;
    PORT
      LAYER M4 ;
        RECT  43.116 27.312 43.2 27.336 ;
    END
  END o_y[52]
  PIN o_y[53]
    DIRECTION OUTPUT ;
    USE SIGNAL ;
    PORT
      LAYER M4 ;
        RECT  43.116 27.456 43.2 27.48 ;
    END
  END o_y[53]
  PIN o_y[54]
    DIRECTION OUTPUT ;
    USE SIGNAL ;
    PORT
      LAYER M4 ;
        RECT  43.116 27.552 43.2 27.576 ;
    END
  END o_y[54]
  PIN o_y[55]
    DIRECTION OUTPUT ;
    USE SIGNAL ;
    PORT
      LAYER M4 ;
        RECT  43.116 27.696 43.2 27.72 ;
    END
  END o_y[55]
  PIN o_y[56]
    DIRECTION OUTPUT ;
    USE SIGNAL ;
    PORT
      LAYER M4 ;
        RECT  43.116 27.84 43.2 27.864 ;
    END
  END o_y[56]
  PIN o_y[57]
    DIRECTION OUTPUT ;
    USE SIGNAL ;
    PORT
      LAYER M4 ;
        RECT  43.116 27.936 43.2 27.96 ;
    END
  END o_y[57]
  PIN o_y[58]
    DIRECTION OUTPUT ;
    USE SIGNAL ;
    PORT
      LAYER M4 ;
        RECT  43.116 28.08 43.2 28.104 ;
    END
  END o_y[58]
  PIN o_y[59]
    DIRECTION OUTPUT ;
    USE SIGNAL ;
    PORT
      LAYER M4 ;
        RECT  43.116 28.224 43.2 28.248 ;
    END
  END o_y[59]
  PIN o_y[5]
    DIRECTION OUTPUT ;
    USE SIGNAL ;
    PORT
      LAYER M4 ;
        RECT  43.116 21.264 43.2 21.288 ;
    END
  END o_y[5]
  PIN o_y[60]
    DIRECTION OUTPUT ;
    USE SIGNAL ;
    PORT
      LAYER M4 ;
        RECT  43.116 28.32 43.2 28.344 ;
    END
  END o_y[60]
  PIN o_y[61]
    DIRECTION OUTPUT ;
    USE SIGNAL ;
    PORT
      LAYER M4 ;
        RECT  43.116 28.464 43.2 28.488 ;
    END
  END o_y[61]
  PIN o_y[62]
    DIRECTION OUTPUT ;
    USE SIGNAL ;
    PORT
      LAYER M4 ;
        RECT  43.116 28.608 43.2 28.632 ;
    END
  END o_y[62]
  PIN o_y[63]
    DIRECTION OUTPUT ;
    USE SIGNAL ;
    PORT
      LAYER M4 ;
        RECT  43.116 28.704 43.2 28.728 ;
    END
  END o_y[63]
  PIN o_y[64]
    DIRECTION OUTPUT ;
    USE SIGNAL ;
    PORT
      LAYER M4 ;
        RECT  43.116 28.848 43.2 28.872 ;
    END
  END o_y[64]
  PIN o_y[65]
    DIRECTION OUTPUT ;
    USE SIGNAL ;
    PORT
      LAYER M4 ;
        RECT  43.116 28.992 43.2 29.016 ;
    END
  END o_y[65]
  PIN o_y[66]
    DIRECTION OUTPUT ;
    USE SIGNAL ;
    PORT
      LAYER M4 ;
        RECT  43.116 29.088 43.2 29.112 ;
    END
  END o_y[66]
  PIN o_y[67]
    DIRECTION OUTPUT ;
    USE SIGNAL ;
    PORT
      LAYER M4 ;
        RECT  43.116 29.232 43.2 29.256 ;
    END
  END o_y[67]
  PIN o_y[68]
    DIRECTION OUTPUT ;
    USE SIGNAL ;
    PORT
      LAYER M4 ;
        RECT  43.116 29.376 43.2 29.4 ;
    END
  END o_y[68]
  PIN o_y[69]
    DIRECTION OUTPUT ;
    USE SIGNAL ;
    PORT
      LAYER M4 ;
        RECT  43.116 29.472 43.2 29.496 ;
    END
  END o_y[69]
  PIN o_y[6]
    DIRECTION OUTPUT ;
    USE SIGNAL ;
    PORT
      LAYER M4 ;
        RECT  43.116 21.408 43.2 21.432 ;
    END
  END o_y[6]
  PIN o_y[70]
    DIRECTION OUTPUT ;
    USE SIGNAL ;
    PORT
      LAYER M4 ;
        RECT  43.116 29.616 43.2 29.64 ;
    END
  END o_y[70]
  PIN o_y[71]
    DIRECTION OUTPUT ;
    USE SIGNAL ;
    PORT
      LAYER M4 ;
        RECT  43.116 29.76 43.2 29.784 ;
    END
  END o_y[71]
  PIN o_y[72]
    DIRECTION OUTPUT ;
    USE SIGNAL ;
    PORT
      LAYER M4 ;
        RECT  43.116 29.904 43.2 29.928 ;
    END
  END o_y[72]
  PIN o_y[73]
    DIRECTION OUTPUT ;
    USE SIGNAL ;
    PORT
      LAYER M4 ;
        RECT  43.116 30 43.2 30.024 ;
    END
  END o_y[73]
  PIN o_y[74]
    DIRECTION OUTPUT ;
    USE SIGNAL ;
    PORT
      LAYER M4 ;
        RECT  43.116 30.144 43.2 30.168 ;
    END
  END o_y[74]
  PIN o_y[75]
    DIRECTION OUTPUT ;
    USE SIGNAL ;
    PORT
      LAYER M4 ;
        RECT  43.116 30.288 43.2 30.312 ;
    END
  END o_y[75]
  PIN o_y[76]
    DIRECTION OUTPUT ;
    USE SIGNAL ;
    PORT
      LAYER M4 ;
        RECT  43.116 30.384 43.2 30.408 ;
    END
  END o_y[76]
  PIN o_y[77]
    DIRECTION OUTPUT ;
    USE SIGNAL ;
    PORT
      LAYER M4 ;
        RECT  43.116 30.528 43.2 30.552 ;
    END
  END o_y[77]
  PIN o_y[78]
    DIRECTION OUTPUT ;
    USE SIGNAL ;
    PORT
      LAYER M4 ;
        RECT  43.116 30.672 43.2 30.696 ;
    END
  END o_y[78]
  PIN o_y[79]
    DIRECTION OUTPUT ;
    USE SIGNAL ;
    PORT
      LAYER M4 ;
        RECT  43.116 30.768 43.2 30.792 ;
    END
  END o_y[79]
  PIN o_y[7]
    DIRECTION OUTPUT ;
    USE SIGNAL ;
    PORT
      LAYER M4 ;
        RECT  43.116 21.504 43.2 21.528 ;
    END
  END o_y[7]
  PIN o_y[80]
    DIRECTION OUTPUT ;
    USE SIGNAL ;
    PORT
      LAYER M4 ;
        RECT  43.116 30.912 43.2 30.936 ;
    END
  END o_y[80]
  PIN o_y[81]
    DIRECTION OUTPUT ;
    USE SIGNAL ;
    PORT
      LAYER M4 ;
        RECT  43.116 31.056 43.2 31.08 ;
    END
  END o_y[81]
  PIN o_y[82]
    DIRECTION OUTPUT ;
    USE SIGNAL ;
    PORT
      LAYER M4 ;
        RECT  43.116 31.152 43.2 31.176 ;
    END
  END o_y[82]
  PIN o_y[83]
    DIRECTION OUTPUT ;
    USE SIGNAL ;
    PORT
      LAYER M4 ;
        RECT  43.116 31.296 43.2 31.32 ;
    END
  END o_y[83]
  PIN o_y[84]
    DIRECTION OUTPUT ;
    USE SIGNAL ;
    PORT
      LAYER M4 ;
        RECT  43.116 31.44 43.2 31.464 ;
    END
  END o_y[84]
  PIN o_y[85]
    DIRECTION OUTPUT ;
    USE SIGNAL ;
    PORT
      LAYER M4 ;
        RECT  43.116 31.536 43.2 31.56 ;
    END
  END o_y[85]
  PIN o_y[86]
    DIRECTION OUTPUT ;
    USE SIGNAL ;
    PORT
      LAYER M4 ;
        RECT  43.116 31.68 43.2 31.704 ;
    END
  END o_y[86]
  PIN o_y[87]
    DIRECTION OUTPUT ;
    USE SIGNAL ;
    PORT
      LAYER M4 ;
        RECT  43.116 31.824 43.2 31.848 ;
    END
  END o_y[87]
  PIN o_y[88]
    DIRECTION OUTPUT ;
    USE SIGNAL ;
    PORT
      LAYER M4 ;
        RECT  43.116 31.92 43.2 31.944 ;
    END
  END o_y[88]
  PIN o_y[89]
    DIRECTION OUTPUT ;
    USE SIGNAL ;
    PORT
      LAYER M4 ;
        RECT  43.116 32.064 43.2 32.088 ;
    END
  END o_y[89]
  PIN o_y[8]
    DIRECTION OUTPUT ;
    USE SIGNAL ;
    PORT
      LAYER M4 ;
        RECT  43.116 21.648 43.2 21.672 ;
    END
  END o_y[8]
  PIN o_y[90]
    DIRECTION OUTPUT ;
    USE SIGNAL ;
    PORT
      LAYER M4 ;
        RECT  43.116 32.208 43.2 32.232 ;
    END
  END o_y[90]
  PIN o_y[91]
    DIRECTION OUTPUT ;
    USE SIGNAL ;
    PORT
      LAYER M4 ;
        RECT  43.116 32.304 43.2 32.328 ;
    END
  END o_y[91]
  PIN o_y[92]
    DIRECTION OUTPUT ;
    USE SIGNAL ;
    PORT
      LAYER M4 ;
        RECT  43.116 32.448 43.2 32.472 ;
    END
  END o_y[92]
  PIN o_y[93]
    DIRECTION OUTPUT ;
    USE SIGNAL ;
    PORT
      LAYER M4 ;
        RECT  43.116 32.592 43.2 32.616 ;
    END
  END o_y[93]
  PIN o_y[94]
    DIRECTION OUTPUT ;
    USE SIGNAL ;
    PORT
      LAYER M4 ;
        RECT  43.116 32.688 43.2 32.712 ;
    END
  END o_y[94]
  PIN o_y[95]
    DIRECTION OUTPUT ;
    USE SIGNAL ;
    PORT
      LAYER M4 ;
        RECT  43.116 32.832 43.2 32.856 ;
    END
  END o_y[95]
  PIN o_y[96]
    DIRECTION OUTPUT ;
    USE SIGNAL ;
    PORT
      LAYER M4 ;
        RECT  43.116 32.976 43.2 33 ;
    END
  END o_y[96]
  PIN o_y[97]
    DIRECTION OUTPUT ;
    USE SIGNAL ;
    PORT
      LAYER M4 ;
        RECT  43.116 33.072 43.2 33.096 ;
    END
  END o_y[97]
  PIN o_y[98]
    DIRECTION OUTPUT ;
    USE SIGNAL ;
    PORT
      LAYER M4 ;
        RECT  43.116 33.216 43.2 33.24 ;
    END
  END o_y[98]
  PIN o_y[99]
    DIRECTION OUTPUT ;
    USE SIGNAL ;
    PORT
      LAYER M4 ;
        RECT  43.116 33.36 43.2 33.384 ;
    END
  END o_y[99]
  PIN o_y[9]
    DIRECTION OUTPUT ;
    USE SIGNAL ;
    PORT
      LAYER M4 ;
        RECT  43.116 21.792 43.2 21.816 ;
    END
  END o_y[9]
  PIN row_j[0]
    DIRECTION INPUT ;
    USE SIGNAL ;
    PORT
      LAYER M3 ;
        RECT  38.484 0 38.502 0.038 ;
    END
    PORT
      LAYER M3 ;
        RECT  38.484 0.012 38.502 0.091 ;
    END
  END row_j[0]
  PIN row_j[1]
    DIRECTION INPUT ;
    USE SIGNAL ;
    PORT
      LAYER M5 ;
        RECT  40.368 0 40.392 0.084 ;
    END
    PORT
      LAYER M5 ;
        RECT  40.368 0.016 40.392 0.131 ;
    END
  END row_j[1]
  PIN rst_n
    DIRECTION INPUT ;
    USE SIGNAL ;
    PORT
      LAYER M3 ;
        RECT  42.264 0 42.282 0.038 ;
    END
    PORT
      LAYER M3 ;
        RECT  42.264 0.012 42.282 0.283 ;
    END
  END rst_n
  PIN VDD
    DIRECTION INOUT ;
    USE POWER ;
    PORT
      LAYER M5 ;
        RECT  40.392 2.151 40.512 84.249 ;
        RECT  34.992 2.151 35.112 84.249 ;
        RECT  29.592 2.151 29.712 84.249 ;
        RECT  24.192 2.151 24.312 84.249 ;
        RECT  18.792 2.151 18.912 84.249 ;
        RECT  13.392 2.151 13.512 84.249 ;
        RECT  7.992 2.151 8.112 84.249 ;
        RECT  2.592 2.151 2.712 84.249 ;
    END
  END VDD
  PIN VSS
    DIRECTION INOUT ;
    USE GROUND ;
    PORT
      LAYER M5 ;
        RECT  40.2 2.137 40.32 84.263 ;
        RECT  34.8 2.137 34.92 84.263 ;
        RECT  29.4 2.137 29.52 84.263 ;
        RECT  24 2.137 24.12 84.263 ;
        RECT  18.6 2.137 18.72 84.263 ;
        RECT  13.2 2.137 13.32 84.263 ;
        RECT  7.8 2.137 7.92 84.263 ;
        RECT  2.4 2.137 2.52 84.263 ;
    END
  END VSS
  # OT_OBS_CLOSED layer=M5 d_um=1.536 added=41
  OBS
    LAYER RVTN ;
     RECT  2.16 2.16 41.04 2.295 ;
     RECT  2.16 2.565 41.04 2.835 ;
     RECT  2.16 3.105 41.04 3.375 ;
     RECT  2.16 3.645 41.04 3.915 ;
     RECT  2.16 4.185 41.04 4.455 ;
     RECT  2.16 4.725 41.04 4.995 ;
     RECT  2.16 5.265 41.04 5.535 ;
     RECT  2.16 5.805 41.04 6.075 ;
     RECT  2.16 6.345 41.04 6.615 ;
     RECT  2.16 6.885 41.04 7.155 ;
     RECT  2.16 7.425 41.04 7.695 ;
     RECT  2.16 7.965 41.04 8.235 ;
     RECT  2.16 8.505 41.04 8.775 ;
     RECT  2.16 9.045 41.04 9.315 ;
     RECT  2.16 9.585 41.04 9.855 ;
     RECT  2.16 10.125 41.04 10.395 ;
     RECT  2.16 10.665 41.04 10.935 ;
     RECT  2.16 11.205 41.04 11.475 ;
     RECT  2.16 11.745 41.04 12.015 ;
     RECT  2.16 12.285 41.04 12.555 ;
     RECT  2.16 12.825 41.04 13.095 ;
     RECT  2.16 13.365 41.04 13.635 ;
     RECT  2.16 13.905 41.04 14.175 ;
     RECT  2.16 14.445 41.04 14.715 ;
     RECT  2.16 14.985 41.04 15.255 ;
     RECT  2.16 15.525 41.04 15.795 ;
     RECT  2.16 16.065 41.04 16.335 ;
     RECT  2.16 16.605 41.04 16.875 ;
     RECT  2.16 17.145 41.04 17.415 ;
     RECT  2.16 17.685 41.04 17.955 ;
     RECT  2.16 18.225 41.04 18.495 ;
     RECT  2.16 18.765 41.04 19.035 ;
     RECT  2.16 19.305 41.04 19.575 ;
     RECT  2.16 19.845 41.04 20.115 ;
     RECT  2.16 20.385 41.04 20.655 ;
     RECT  2.16 20.925 41.04 21.195 ;
     RECT  2.16 21.465 41.04 21.735 ;
     RECT  2.16 22.005 41.04 22.275 ;
     RECT  2.16 22.545 41.04 22.815 ;
     RECT  2.16 23.085 41.04 23.355 ;
     RECT  2.16 23.625 41.04 23.895 ;
     RECT  2.16 24.165 41.04 24.435 ;
     RECT  2.16 24.705 41.04 24.975 ;
     RECT  2.16 25.245 41.04 25.515 ;
     RECT  2.16 25.785 41.04 26.055 ;
     RECT  2.16 26.325 41.04 26.595 ;
     RECT  2.16 26.865 41.04 27.135 ;
     RECT  2.16 27.405 41.04 27.675 ;
     RECT  2.16 27.945 41.04 28.215 ;
     RECT  2.16 28.485 41.04 28.755 ;
     RECT  2.16 29.025 41.04 29.295 ;
     RECT  2.16 29.565 41.04 29.835 ;
     RECT  2.16 30.105 41.04 30.375 ;
     RECT  2.16 30.645 41.04 30.915 ;
     RECT  2.16 31.185 41.04 31.455 ;
     RECT  2.16 31.725 41.04 31.995 ;
     RECT  2.16 32.265 41.04 32.535 ;
     RECT  2.16 32.805 41.04 33.075 ;
     RECT  2.16 33.345 41.04 33.615 ;
     RECT  2.16 33.885 41.04 34.155 ;
     RECT  2.16 34.425 41.04 34.695 ;
     RECT  2.16 34.965 41.04 35.235 ;
     RECT  2.16 35.505 41.04 35.775 ;
     RECT  2.16 36.045 41.04 36.315 ;
     RECT  2.16 36.585 41.04 36.855 ;
     RECT  2.16 37.125 41.04 37.395 ;
     RECT  2.16 37.665 41.04 37.935 ;
     RECT  2.16 38.205 41.04 38.475 ;
     RECT  2.16 38.745 41.04 39.015 ;
     RECT  2.16 39.285 41.04 39.555 ;
     RECT  2.16 39.825 41.04 40.095 ;
     RECT  2.16 40.365 41.04 40.635 ;
     RECT  2.16 40.905 41.04 41.175 ;
     RECT  2.16 41.445 41.04 41.715 ;
     RECT  2.16 41.985 41.04 42.255 ;
     RECT  2.16 42.525 41.04 42.795 ;
     RECT  2.16 43.065 41.04 43.335 ;
     RECT  2.16 43.605 41.04 43.875 ;
     RECT  2.16 44.145 41.04 44.415 ;
     RECT  2.16 44.685 41.04 44.955 ;
     RECT  2.16 45.225 41.04 45.495 ;
     RECT  2.16 45.765 41.04 46.035 ;
     RECT  2.16 46.305 41.04 46.575 ;
     RECT  2.16 46.845 41.04 47.115 ;
     RECT  2.16 47.385 41.04 47.655 ;
     RECT  2.16 47.925 41.04 48.195 ;
     RECT  2.16 48.465 41.04 48.735 ;
     RECT  2.16 49.005 41.04 49.275 ;
     RECT  2.16 49.545 41.04 49.815 ;
     RECT  2.16 50.085 41.04 50.355 ;
     RECT  2.16 50.625 41.04 50.895 ;
     RECT  2.16 51.165 41.04 51.435 ;
     RECT  2.16 51.705 41.04 51.975 ;
     RECT  2.16 52.245 41.04 52.515 ;
     RECT  2.16 52.785 41.04 53.055 ;
     RECT  2.16 53.325 41.04 53.595 ;
     RECT  2.16 53.865 41.04 54.135 ;
     RECT  2.16 54.405 41.04 54.675 ;
     RECT  2.16 54.945 41.04 55.215 ;
     RECT  2.16 55.485 41.04 55.755 ;
     RECT  2.16 56.025 41.04 56.295 ;
     RECT  2.16 56.565 41.04 56.835 ;
     RECT  2.16 57.105 41.04 57.375 ;
     RECT  2.16 57.645 41.04 57.915 ;
     RECT  2.16 58.185 41.04 58.455 ;
     RECT  2.16 58.725 41.04 58.995 ;
     RECT  2.16 59.265 41.04 59.535 ;
     RECT  2.16 59.805 41.04 60.075 ;
     RECT  2.16 60.345 41.04 60.615 ;
     RECT  2.16 60.885 41.04 61.155 ;
     RECT  2.16 61.425 41.04 61.695 ;
     RECT  2.16 61.965 41.04 62.235 ;
     RECT  2.16 62.505 41.04 62.775 ;
     RECT  2.16 63.045 41.04 63.315 ;
     RECT  2.16 63.585 41.04 63.855 ;
     RECT  2.16 64.125 41.04 64.395 ;
     RECT  2.16 64.665 41.04 64.935 ;
     RECT  2.16 65.205 41.04 65.475 ;
     RECT  2.16 65.745 41.04 66.015 ;
     RECT  2.16 66.285 41.04 66.555 ;
     RECT  2.16 66.825 41.04 67.095 ;
     RECT  2.16 67.365 41.04 67.635 ;
     RECT  2.16 67.905 41.04 68.175 ;
     RECT  2.16 68.445 41.04 68.715 ;
     RECT  2.16 68.985 41.04 69.255 ;
     RECT  2.16 69.525 41.04 69.795 ;
     RECT  2.16 70.065 41.04 70.335 ;
     RECT  2.16 70.605 41.04 70.875 ;
     RECT  2.16 71.145 41.04 71.415 ;
     RECT  2.16 71.685 41.04 71.955 ;
     RECT  2.16 72.225 41.04 72.495 ;
     RECT  2.16 72.765 41.04 73.035 ;
     RECT  2.16 73.305 41.04 73.575 ;
     RECT  2.16 73.845 41.04 74.115 ;
     RECT  2.16 74.385 41.04 74.655 ;
     RECT  2.16 74.925 41.04 75.195 ;
     RECT  2.16 75.465 41.04 75.735 ;
     RECT  2.16 76.005 41.04 76.275 ;
     RECT  2.16 76.545 41.04 76.815 ;
     RECT  2.16 77.085 41.04 77.355 ;
     RECT  2.16 77.625 41.04 77.895 ;
     RECT  2.16 78.165 41.04 78.435 ;
     RECT  2.16 78.705 41.04 78.975 ;
     RECT  2.16 79.245 41.04 79.515 ;
     RECT  2.16 79.785 41.04 80.055 ;
     RECT  2.16 80.325 41.04 80.595 ;
     RECT  2.16 80.865 41.04 81.135 ;
     RECT  2.16 81.405 41.04 81.675 ;
     RECT  2.16 81.945 41.04 82.215 ;
     RECT  2.16 82.485 41.04 82.755 ;
     RECT  2.16 83.025 41.04 83.295 ;
     RECT  2.16 83.565 41.04 83.835 ;
     RECT  2.16 84.105 41.04 84.24 ;
    LAYER RVTP ;
     RECT  2.16 2.295 41.04 2.565 ;
     RECT  2.16 2.835 41.04 3.105 ;
     RECT  2.16 3.375 41.04 3.645 ;
     RECT  2.16 3.915 41.04 4.185 ;
     RECT  2.16 4.455 41.04 4.725 ;
     RECT  2.16 4.995 41.04 5.265 ;
     RECT  2.16 5.535 41.04 5.805 ;
     RECT  2.16 6.075 41.04 6.345 ;
     RECT  2.16 6.615 41.04 6.885 ;
     RECT  2.16 7.155 41.04 7.425 ;
     RECT  2.16 7.695 41.04 7.965 ;
     RECT  2.16 8.235 41.04 8.505 ;
     RECT  2.16 8.775 41.04 9.045 ;
     RECT  2.16 9.315 41.04 9.585 ;
     RECT  2.16 9.855 41.04 10.125 ;
     RECT  2.16 10.395 41.04 10.665 ;
     RECT  2.16 10.935 41.04 11.205 ;
     RECT  2.16 11.475 41.04 11.745 ;
     RECT  2.16 12.015 41.04 12.285 ;
     RECT  2.16 12.555 41.04 12.825 ;
     RECT  2.16 13.095 41.04 13.365 ;
     RECT  2.16 13.635 41.04 13.905 ;
     RECT  2.16 14.175 41.04 14.445 ;
     RECT  2.16 14.715 41.04 14.985 ;
     RECT  2.16 15.255 41.04 15.525 ;
     RECT  2.16 15.795 41.04 16.065 ;
     RECT  2.16 16.335 41.04 16.605 ;
     RECT  2.16 16.875 41.04 17.145 ;
     RECT  2.16 17.415 41.04 17.685 ;
     RECT  2.16 17.955 41.04 18.225 ;
     RECT  2.16 18.495 41.04 18.765 ;
     RECT  2.16 19.035 41.04 19.305 ;
     RECT  2.16 19.575 41.04 19.845 ;
     RECT  2.16 20.115 41.04 20.385 ;
     RECT  2.16 20.655 41.04 20.925 ;
     RECT  2.16 21.195 41.04 21.465 ;
     RECT  2.16 21.735 41.04 22.005 ;
     RECT  2.16 22.275 41.04 22.545 ;
     RECT  2.16 22.815 41.04 23.085 ;
     RECT  2.16 23.355 41.04 23.625 ;
     RECT  2.16 23.895 41.04 24.165 ;
     RECT  2.16 24.435 41.04 24.705 ;
     RECT  2.16 24.975 41.04 25.245 ;
     RECT  2.16 25.515 41.04 25.785 ;
     RECT  2.16 26.055 41.04 26.325 ;
     RECT  2.16 26.595 41.04 26.865 ;
     RECT  2.16 27.135 41.04 27.405 ;
     RECT  2.16 27.675 41.04 27.945 ;
     RECT  2.16 28.215 41.04 28.485 ;
     RECT  2.16 28.755 41.04 29.025 ;
     RECT  2.16 29.295 41.04 29.565 ;
     RECT  2.16 29.835 41.04 30.105 ;
     RECT  2.16 30.375 41.04 30.645 ;
     RECT  2.16 30.915 41.04 31.185 ;
     RECT  2.16 31.455 41.04 31.725 ;
     RECT  2.16 31.995 41.04 32.265 ;
     RECT  2.16 32.535 41.04 32.805 ;
     RECT  2.16 33.075 41.04 33.345 ;
     RECT  2.16 33.615 41.04 33.885 ;
     RECT  2.16 34.155 41.04 34.425 ;
     RECT  2.16 34.695 41.04 34.965 ;
     RECT  2.16 35.235 41.04 35.505 ;
     RECT  2.16 35.775 41.04 36.045 ;
     RECT  2.16 36.315 41.04 36.585 ;
     RECT  2.16 36.855 41.04 37.125 ;
     RECT  2.16 37.395 41.04 37.665 ;
     RECT  2.16 37.935 41.04 38.205 ;
     RECT  2.16 38.475 41.04 38.745 ;
     RECT  2.16 39.015 41.04 39.285 ;
     RECT  2.16 39.555 41.04 39.825 ;
     RECT  2.16 40.095 41.04 40.365 ;
     RECT  2.16 40.635 41.04 40.905 ;
     RECT  2.16 41.175 41.04 41.445 ;
     RECT  2.16 41.715 41.04 41.985 ;
     RECT  2.16 42.255 41.04 42.525 ;
     RECT  2.16 42.795 41.04 43.065 ;
     RECT  2.16 43.335 41.04 43.605 ;
     RECT  2.16 43.875 41.04 44.145 ;
     RECT  2.16 44.415 41.04 44.685 ;
     RECT  2.16 44.955 41.04 45.225 ;
     RECT  2.16 45.495 41.04 45.765 ;
     RECT  2.16 46.035 41.04 46.305 ;
     RECT  2.16 46.575 41.04 46.845 ;
     RECT  2.16 47.115 41.04 47.385 ;
     RECT  2.16 47.655 41.04 47.925 ;
     RECT  2.16 48.195 41.04 48.465 ;
     RECT  2.16 48.735 41.04 49.005 ;
     RECT  2.16 49.275 41.04 49.545 ;
     RECT  2.16 49.815 41.04 50.085 ;
     RECT  2.16 50.355 41.04 50.625 ;
     RECT  2.16 50.895 41.04 51.165 ;
     RECT  2.16 51.435 41.04 51.705 ;
     RECT  2.16 51.975 41.04 52.245 ;
     RECT  2.16 52.515 41.04 52.785 ;
     RECT  2.16 53.055 41.04 53.325 ;
     RECT  2.16 53.595 41.04 53.865 ;
     RECT  2.16 54.135 41.04 54.405 ;
     RECT  2.16 54.675 41.04 54.945 ;
     RECT  2.16 55.215 41.04 55.485 ;
     RECT  2.16 55.755 41.04 56.025 ;
     RECT  2.16 56.295 41.04 56.565 ;
     RECT  2.16 56.835 41.04 57.105 ;
     RECT  2.16 57.375 41.04 57.645 ;
     RECT  2.16 57.915 41.04 58.185 ;
     RECT  2.16 58.455 41.04 58.725 ;
     RECT  2.16 58.995 41.04 59.265 ;
     RECT  2.16 59.535 41.04 59.805 ;
     RECT  2.16 60.075 41.04 60.345 ;
     RECT  2.16 60.615 41.04 60.885 ;
     RECT  2.16 61.155 41.04 61.425 ;
     RECT  2.16 61.695 41.04 61.965 ;
     RECT  2.16 62.235 41.04 62.505 ;
     RECT  2.16 62.775 41.04 63.045 ;
     RECT  2.16 63.315 41.04 63.585 ;
     RECT  2.16 63.855 41.04 64.125 ;
     RECT  2.16 64.395 41.04 64.665 ;
     RECT  2.16 64.935 41.04 65.205 ;
     RECT  2.16 65.475 41.04 65.745 ;
     RECT  2.16 66.015 41.04 66.285 ;
     RECT  2.16 66.555 41.04 66.825 ;
     RECT  2.16 67.095 41.04 67.365 ;
     RECT  2.16 67.635 41.04 67.905 ;
     RECT  2.16 68.175 41.04 68.445 ;
     RECT  2.16 68.715 41.04 68.985 ;
     RECT  2.16 69.255 41.04 69.525 ;
     RECT  2.16 69.795 41.04 70.065 ;
     RECT  2.16 70.335 41.04 70.605 ;
     RECT  2.16 70.875 41.04 71.145 ;
     RECT  2.16 71.415 41.04 71.685 ;
     RECT  2.16 71.955 41.04 72.225 ;
     RECT  2.16 72.495 41.04 72.765 ;
     RECT  2.16 73.035 41.04 73.305 ;
     RECT  2.16 73.575 41.04 73.845 ;
     RECT  2.16 74.115 41.04 74.385 ;
     RECT  2.16 74.655 41.04 74.925 ;
     RECT  2.16 75.195 41.04 75.465 ;
     RECT  2.16 75.735 41.04 76.005 ;
     RECT  2.16 76.275 41.04 76.545 ;
     RECT  2.16 76.815 41.04 77.085 ;
     RECT  2.16 77.355 41.04 77.625 ;
     RECT  2.16 77.895 41.04 78.165 ;
     RECT  2.16 78.435 41.04 78.705 ;
     RECT  2.16 78.975 41.04 79.245 ;
     RECT  2.16 79.515 41.04 79.785 ;
     RECT  2.16 80.055 41.04 80.325 ;
     RECT  2.16 80.595 41.04 80.865 ;
     RECT  2.16 81.135 41.04 81.405 ;
     RECT  2.16 81.675 41.04 81.945 ;
     RECT  2.16 82.215 41.04 82.485 ;
     RECT  2.16 82.755 41.04 83.025 ;
     RECT  2.16 83.295 41.04 83.565 ;
     RECT  2.16 83.835 41.04 84.105 ;
    LAYER M1 ;
     RECT  2.16 2.151 41.04 84.249 ;
    LAYER M2 ;
     RECT  0.031 79.722 0.103 79.74 ;
     RECT  0.031 83.196 0.103 83.214 ;
     RECT  0.103 82.494 0.131 83.214 ;
     RECT  0.103 78.642 0.139 80.658 ;
     RECT  0.131 82.494 0.211 82.818 ;
     RECT  0.103 63.792 0.535 63.81 ;
     RECT  0.139 78.642 1.687 81.09 ;
     RECT  0.211 81.99 1.687 82.818 ;
     RECT  1.615 84.384 1.715 84.402 ;
     RECT  0.535 3.15 1.723 3.168 ;
     RECT  1.723 2.772 1.759 3.168 ;
     RECT  1.759 2.772 1.975 3.6 ;
     RECT  1.147 4.662 1.975 4.68 ;
     RECT  1.975 2.772 2.16 4.68 ;
     RECT  0.535 6.39 2.16 6.408 ;
     RECT  0.103 15.3 2.16 15.318 ;
     RECT  0.535 20.43 2.16 20.448 ;
     RECT  1.723 21.672 2.16 21.69 ;
     RECT  0.103 23.328 2.16 23.346 ;
     RECT  0.535 32.472 2.16 32.49 ;
     RECT  0.103 50.67 2.16 50.688 ;
     RECT  0.103 51.48 2.16 51.498 ;
     RECT  0.535 55.8 2.16 55.818 ;
     RECT  0.103 58.122 2.16 58.14 ;
     RECT  0.535 63.792 2.16 63.846 ;
     RECT  0.535 68.256 2.16 68.274 ;
     RECT  1.687 78.642 2.16 82.818 ;
     RECT  4.675 0.036 4.775 0.054 ;
     RECT  2.16 2.151 5.251 84.249 ;
     RECT  5.251 2.106 10.931 84.249 ;
     RECT  10.931 2.151 19.723 84.249 ;
     RECT  8.455 0.036 25.043 0.054 ;
     RECT  19.723 2.106 25.583 84.249 ;
     RECT  25.583 2.151 30.775 84.249 ;
     RECT  30.775 2.07 30.919 84.249 ;
     RECT  30.919 1.728 31.019 84.249 ;
     RECT  31.019 2.07 34.195 84.249 ;
     RECT  34.591 0.036 34.763 0.054 ;
     RECT  34.195 1.962 36.715 84.249 ;
     RECT  36.715 1.962 37.183 84.294 ;
     RECT  37.183 1.881 39.263 84.294 ;
     RECT  39.263 2.034 39.839 84.294 ;
     RECT  39.839 2.034 41.04 84.249 ;
     RECT  41.04 34.974 41.063 84.168 ;
     RECT  41.04 2.034 41.603 2.124 ;
     RECT  41.04 2.916 41.603 34.218 ;
     RECT  41.063 34.974 41.603 84.024 ;
     RECT  41.603 18.504 41.639 34.218 ;
     RECT  41.603 49.752 41.639 84.024 ;
     RECT  41.603 2.916 41.675 17.748 ;
     RECT  41.603 36.666 41.819 48.996 ;
     RECT  41.639 18.576 41.891 34.218 ;
     RECT  41.603 34.974 41.891 35.532 ;
     RECT  41.603 2.034 42.143 2.052 ;
     RECT  41.675 2.916 42.143 17.334 ;
     RECT  41.819 36.666 42.143 48.762 ;
     RECT  41.639 49.752 42.143 52.974 ;
     RECT  41.639 53.766 42.143 84.024 ;
     RECT  42.143 3.006 42.179 17.334 ;
     RECT  41.891 18.576 42.179 29.934 ;
     RECT  41.891 30.726 42.179 34.218 ;
     RECT  42.143 36.666 42.179 38.736 ;
     RECT  42.143 39.726 42.179 48.762 ;
     RECT  42.143 49.896 42.179 52.974 ;
     RECT  42.143 53.766 42.179 59.49 ;
     RECT  42.143 60.246 42.179 60.264 ;
     RECT  42.143 61.056 42.179 84.024 ;
     RECT  42.179 3.186 42.215 9.342 ;
     RECT  42.179 11.016 42.215 12.852 ;
     RECT  42.179 14.148 42.215 15.084 ;
     RECT  42.179 19.926 42.215 23.652 ;
     RECT  42.179 26.766 42.215 27.162 ;
     RECT  42.179 28.026 42.215 28.476 ;
     RECT  42.179 29.232 42.215 29.592 ;
     RECT  42.179 30.726 42.215 31.752 ;
     RECT  42.179 36.666 42.215 36.684 ;
     RECT  42.179 37.44 42.215 38.736 ;
     RECT  42.179 40.104 42.215 40.932 ;
     RECT  42.179 41.886 42.215 44.442 ;
     RECT  42.179 45.306 42.215 48.762 ;
     RECT  42.179 49.896 42.215 50.112 ;
     RECT  42.179 51.246 42.215 52.812 ;
     RECT  42.179 53.874 42.215 54.702 ;
     RECT  42.179 61.974 42.215 67.824 ;
     RECT  42.179 71.046 42.215 71.478 ;
     RECT  42.179 75.402 42.215 76.194 ;
     RECT  42.179 77.166 42.215 80.928 ;
     RECT  42.179 81.72 42.215 82.584 ;
     RECT  42.179 83.538 42.215 83.628 ;
     RECT  42.215 11.214 42.251 12.618 ;
     RECT  42.215 14.148 42.251 14.544 ;
     RECT  42.215 20.052 42.251 20.214 ;
     RECT  42.215 20.97 42.251 20.988 ;
     RECT  42.179 34.056 42.251 34.218 ;
     RECT  42.215 37.44 42.251 37.494 ;
     RECT  42.215 40.104 42.251 40.734 ;
     RECT  42.215 41.886 42.251 42.354 ;
     RECT  42.215 49.941 42.251 50.112 ;
     RECT  42.215 51.516 42.251 52.812 ;
     RECT  42.215 53.874 42.251 54.594 ;
     RECT  42.179 55.764 42.251 59.49 ;
     RECT  42.215 61.974 42.251 62.262 ;
     RECT  42.215 63.054 42.251 65.268 ;
     RECT  42.215 71.046 42.251 71.244 ;
     RECT  42.179 72.504 42.251 74.484 ;
     RECT  42.215 77.166 42.251 78.354 ;
     RECT  42.215 79.218 42.251 80.928 ;
     RECT  42.215 83.538 42.251 83.592 ;
     RECT  42.215 3.186 42.287 5.256 ;
     RECT  42.251 11.376 42.287 12.618 ;
     RECT  42.251 41.886 42.287 42.174 ;
     RECT  42.215 45.774 42.287 48.762 ;
     RECT  42.215 66.096 42.287 67.824 ;
     RECT  42.251 72.504 42.287 73.332 ;
     RECT  42.251 77.904 42.287 78.354 ;
     RECT  42.251 83.574 42.287 83.592 ;
     RECT  42.251 14.184 42.323 14.544 ;
     RECT  42.287 41.886 42.323 41.904 ;
     RECT  42.251 58.77 42.395 59.49 ;
     RECT  42.287 3.186 42.899 5.22 ;
     RECT  42.899 3.186 42.935 4.482 ;
     RECT  42.215 6.624 42.971 9.342 ;
     RECT  42.935 3.186 43.007 3.438 ;
     RECT  42.971 7.704 43.007 9.342 ;
     RECT  42.215 30.852 43.007 31.752 ;
     RECT  42.215 38.412 43.015 38.574 ;
     RECT  42.935 4.464 43.043 4.482 ;
     RECT  43.015 38.412 43.043 38.736 ;
     RECT  42.251 51.714 43.043 52.812 ;
     RECT  42.251 57.546 43.043 58.014 ;
     RECT  42.179 68.652 43.043 69.354 ;
     RECT  42.251 79.56 43.043 80.154 ;
     RECT  43.007 3.186 43.051 3.204 ;
     RECT  42.971 6.624 43.079 6.642 ;
     RECT  43.007 9.324 43.079 9.342 ;
     RECT  42.287 11.376 43.079 11.97 ;
     RECT  42.215 21.816 43.079 23.652 ;
     RECT  42.215 28.026 43.079 28.314 ;
     RECT  42.215 29.232 43.079 29.484 ;
     RECT  43.007 31.392 43.079 31.752 ;
     RECT  42.179 32.886 43.079 33.174 ;
     RECT  42.251 55.764 43.079 56.124 ;
     RECT  43.043 57.726 43.079 58.014 ;
     RECT  42.287 66.096 43.079 66.852 ;
     RECT  42.287 67.716 43.079 67.824 ;
     RECT  43.043 69.264 43.079 69.354 ;
     RECT  42.287 72.936 43.079 73.332 ;
     RECT  42.287 77.904 43.079 77.994 ;
     RECT  43.043 79.596 43.079 80.154 ;
     RECT  42.215 81.72 43.079 82.476 ;
     RECT  43.051 2.502 43.115 3.204 ;
     RECT  43.007 8.244 43.115 8.424 ;
     RECT  43.079 11.376 43.115 11.394 ;
     RECT  42.323 14.526 43.115 14.544 ;
     RECT  42.179 16.344 43.115 17.1 ;
     RECT  42.179 18.576 43.115 18.594 ;
     RECT  42.251 20.196 43.115 20.214 ;
     RECT  43.079 21.816 43.115 21.834 ;
     RECT  43.079 22.626 43.115 23.346 ;
     RECT  42.179 24.48 43.115 25.074 ;
     RECT  42.179 25.83 43.115 25.848 ;
     RECT  42.215 26.766 43.115 26.784 ;
     RECT  43.079 28.296 43.115 28.314 ;
     RECT  43.079 29.466 43.115 29.484 ;
     RECT  43.079 31.734 43.115 31.752 ;
     RECT  43.079 32.886 43.115 32.904 ;
     RECT  42.251 34.2 43.115 34.218 ;
     RECT  41.891 35.01 43.115 35.532 ;
     RECT  42.251 37.476 43.115 37.494 ;
     RECT  43.043 38.556 43.115 38.736 ;
     RECT  42.251 40.716 43.115 40.734 ;
     RECT  42.215 43.146 43.115 44.442 ;
     RECT  42.287 45.774 43.115 46.404 ;
     RECT  42.287 47.736 43.115 47.88 ;
     RECT  42.287 48.744 43.115 48.762 ;
     RECT  42.251 49.941 43.115 49.959 ;
     RECT  43.043 51.714 43.115 52.272 ;
     RECT  42.251 53.874 43.115 53.892 ;
     RECT  43.079 56.106 43.115 56.124 ;
     RECT  43.079 57.996 43.115 58.014 ;
     RECT  42.395 59.472 43.115 59.49 ;
     RECT  42.251 62.244 43.115 62.262 ;
     RECT  42.251 63.054 43.115 63.27 ;
     RECT  42.251 64.368 43.115 65.268 ;
     RECT  43.079 66.834 43.115 66.852 ;
     RECT  43.079 67.716 43.115 67.734 ;
     RECT  43.079 69.336 43.115 69.354 ;
     RECT  42.251 71.226 43.115 71.244 ;
     RECT  43.079 72.936 43.115 72.954 ;
     RECT  42.251 74.466 43.115 74.484 ;
     RECT  42.215 75.402 43.115 75.42 ;
     RECT  43.079 77.976 43.115 77.994 ;
     RECT  43.079 79.686 43.115 80.154 ;
     RECT  42.251 80.91 43.115 80.928 ;
     RECT  43.079 81.756 43.115 82.476 ;
     RECT  43.115 2.502 43.187 2.52 ;
     RECT  43.115 8.406 43.187 8.424 ;
    LAYER M3 ;
     RECT  25.02 0.031 25.038 0.043 ;
     RECT  25.02 0.043 25.326 0.091 ;
     RECT  38.34 0.091 38.502 0.187 ;
     RECT  2.808 0.091 2.826 0.235 ;
     RECT  38.34 0.187 38.718 0.427 ;
     RECT  1.98 0.427 1.998 0.571 ;
     RECT  41.868 0.283 42.282 0.571 ;
     RECT  37.728 0.427 38.718 0.811 ;
     RECT  2.808 0.235 2.862 1.099 ;
     RECT  37.728 0.811 38.754 1.099 ;
     RECT  39.708 0.043 39.726 1.099 ;
     RECT  1.728 0.571 1.998 1.243 ;
     RECT  2.808 1.099 2.898 1.243 ;
     RECT  41.868 0.571 43.002 1.339 ;
     RECT  1.728 1.243 2.898 1.435 ;
     RECT  41.868 1.339 43.11 1.579 ;
     RECT  37.728 1.099 39.726 1.876 ;
     RECT  0.54 0.907 0.558 1.915 ;
     RECT  1.728 1.435 3.438 1.915 ;
     RECT  34.596 0.059 34.614 1.957 ;
     RECT  37.188 1.876 39.726 1.993 ;
     RECT  30.924 1.723 31.014 2.065 ;
     RECT  4.752 0.059 4.77 2.101 ;
     RECT  24.588 0.091 25.326 2.101 ;
     RECT  32.868 1.723 32.886 2.101 ;
     RECT  35.604 0.523 35.622 2.101 ;
     RECT  41.58 1.579 43.11 2.107 ;
     RECT  24.588 2.101 25.578 2.143 ;
     RECT  29.16 1.723 29.178 2.143 ;
     RECT  34.2 1.957 34.614 2.143 ;
     RECT  35.604 2.101 35.694 2.143 ;
     RECT  36.936 1.993 39.726 2.143 ;
     RECT  40.716 2.065 40.734 2.143 ;
     RECT  0.54 1.915 3.438 2.191 ;
     RECT  10.908 2.101 10.926 2.191 ;
     RECT  23.472 2.143 25.578 2.219 ;
     RECT  36.936 2.143 40.734 2.219 ;
     RECT  7.815 2.143 7.905 2.227 ;
     RECT  32.868 2.101 32.958 2.227 ;
     RECT  0.54 2.191 3.618 2.251 ;
     RECT  4.752 2.101 5.274 2.251 ;
     RECT  26.46 2.191 26.478 2.263 ;
     RECT  29.16 2.143 29.505 2.263 ;
     RECT  30.78 2.065 31.014 2.263 ;
     RECT  31.86 2.191 31.878 2.263 ;
     RECT  32.868 2.227 33.102 2.263 ;
     RECT  10.908 2.191 12.222 2.291 ;
     RECT  23.472 2.219 25.362 2.299 ;
     RECT  36.936 2.219 40.662 2.299 ;
     RECT  8.784 2.191 9.486 2.371 ;
     RECT  26.244 2.263 26.478 2.371 ;
     RECT  29.16 2.263 30.006 2.371 ;
     RECT  34.2 2.143 35.694 2.371 ;
     RECT  36.468 2.299 40.662 2.371 ;
     RECT  7.272 2.227 7.905 2.413 ;
     RECT  8.784 2.371 9.81 2.413 ;
     RECT  13.215 2.143 13.305 2.413 ;
     RECT  18.615 2.143 18.705 2.413 ;
     RECT  7.272 2.413 9.81 2.461 ;
     RECT  26.244 2.371 27.234 2.461 ;
     RECT  27.972 2.263 27.99 2.461 ;
     RECT  23.364 2.299 25.362 2.489 ;
     RECT  41.544 2.107 43.11 2.497 ;
     RECT  26.244 2.461 27.99 2.533 ;
     RECT  28.764 2.371 30.006 2.533 ;
     RECT  18.615 2.413 18.897 2.587 ;
     RECT  0.54 2.251 5.274 2.605 ;
     RECT  7.272 2.461 10.422 2.605 ;
     RECT  30.78 2.263 31.878 2.605 ;
     RECT  32.868 2.263 33.246 2.605 ;
     RECT  34.2 2.371 40.662 2.605 ;
     RECT  30.78 2.605 40.662 2.669 ;
     RECT  6.804 2.605 10.422 2.731 ;
     RECT  26.244 2.533 30.006 2.731 ;
     RECT  30.78 2.669 33.39 2.731 ;
     RECT  20.268 2.641 20.286 2.759 ;
     RECT  26.244 2.731 33.39 2.759 ;
     RECT  0.54 2.605 5.778 2.767 ;
     RECT  6.552 2.731 10.422 2.767 ;
     RECT  26.244 2.759 33.282 2.795 ;
     RECT  18.615 2.587 19.35 2.861 ;
     RECT  26.82 2.795 33.282 2.957 ;
     RECT  0.54 2.767 10.422 3.109 ;
     RECT  34.2 2.669 40.662 3.109 ;
     RECT  34.2 3.109 40.806 3.115 ;
     RECT  41.544 2.497 43.182 3.115 ;
     RECT  0.54 3.109 10.458 3.173 ;
     RECT  1.152 3.173 10.458 3.181 ;
     RECT  11.52 2.291 12.222 3.181 ;
     RECT  26.82 2.957 33.246 3.209 ;
     RECT  34.2 3.115 43.182 3.299 ;
     RECT  41.508 3.299 43.182 3.479 ;
     RECT  17.676 3.109 17.694 3.541 ;
     RECT  18.615 2.861 18.897 3.541 ;
     RECT  24.015 2.489 25.362 3.595 ;
     RECT  23.94 3.595 25.362 3.641 ;
     RECT  28.116 3.209 33.246 3.685 ;
     RECT  34.2 3.299 40.734 3.685 ;
     RECT  1.152 3.181 12.222 3.931 ;
     RECT  0.54 3.931 12.222 4.145 ;
     RECT  28.116 3.685 40.734 4.267 ;
     RECT  41.544 3.479 43.182 4.267 ;
     RECT  0.54 4.145 1.278 4.493 ;
     RECT  16.884 2.263 16.902 4.531 ;
     RECT  2.304 4.145 12.222 4.541 ;
     RECT  0.54 4.493 1.17 4.685 ;
     RECT  16.884 4.531 16.938 4.765 ;
     RECT  0.54 4.685 0.558 4.795 ;
     RECT  0.324 4.795 0.558 4.939 ;
     RECT  28.116 4.267 43.182 5.071 ;
     RECT  2.304 4.541 8.874 5.131 ;
     RECT  28.044 5.071 43.182 5.225 ;
     RECT  28.044 5.225 42.282 5.261 ;
     RECT  2.268 5.131 8.874 5.305 ;
     RECT  9.612 4.541 12.222 5.305 ;
     RECT  16.776 4.765 16.938 5.341 ;
     RECT  17.676 3.541 18.897 5.341 ;
     RECT  2.268 5.305 12.222 5.495 ;
     RECT  0.108 4.939 0.558 5.597 ;
     RECT  28.044 5.261 42.21 5.909 ;
     RECT  26.82 3.209 27.306 6.007 ;
     RECT  28.044 5.909 42.174 6.143 ;
     RECT  0.54 5.597 0.558 6.413 ;
     RECT  26.748 6.007 27.306 6.449 ;
     RECT  16.776 5.341 18.897 6.511 ;
     RECT  43.02 5.225 43.182 6.619 ;
     RECT  2.304 5.495 12.222 6.811 ;
     RECT  28.26 6.143 42.174 6.859 ;
     RECT  28.26 6.859 42.21 6.925 ;
     RECT  28.26 6.925 42.246 7.037 ;
     RECT  28.26 7.037 42.21 7.087 ;
     RECT  42.984 6.619 43.182 7.099 ;
     RECT  2.196 6.811 12.222 7.115 ;
     RECT  42.948 7.099 43.182 7.151 ;
     RECT  28.116 7.087 42.21 7.223 ;
     RECT  28.116 7.223 42.174 7.259 ;
     RECT  1.152 7.483 1.17 7.661 ;
     RECT  28.116 7.259 36.126 7.949 ;
     RECT  37.008 7.259 42.174 7.969 ;
     RECT  26.748 6.449 27.054 8.041 ;
     RECT  2.304 7.115 12.222 8.195 ;
     RECT  34.092 7.949 36.126 8.275 ;
     RECT  24.015 3.641 25.362 8.339 ;
     RECT  34.092 8.275 36.234 8.401 ;
     RECT  37.008 7.969 42.21 8.401 ;
     RECT  2.304 8.195 3.438 8.429 ;
     RECT  42.984 7.151 43.182 8.429 ;
     RECT  16.776 6.511 19.494 8.509 ;
     RECT  28.116 7.949 33.174 8.581 ;
     RECT  2.304 8.429 3.186 8.683 ;
     RECT  4.212 8.195 12.222 8.699 ;
     RECT  34.092 8.401 42.21 8.717 ;
     RECT  27.936 8.581 33.174 8.815 ;
     RECT  34.092 8.717 42.174 8.815 ;
     RECT  26.748 8.041 27.126 8.851 ;
     RECT  27.936 8.815 42.174 8.851 ;
     RECT  22.248 8.539 22.266 8.969 ;
     RECT  2.268 8.683 3.186 9.005 ;
     RECT  42.984 8.429 43.074 9.149 ;
     RECT  2.304 9.005 3.186 9.319 ;
     RECT  43.056 9.149 43.074 9.347 ;
     RECT  27.9 8.851 42.174 9.383 ;
     RECT  26.064 8.851 27.126 9.391 ;
     RECT  27.9 9.383 40.698 9.391 ;
     RECT  2.304 9.319 3.438 9.661 ;
     RECT  4.212 8.699 11.97 9.661 ;
     RECT  2.304 9.661 11.97 10.049 ;
     RECT  4.32 10.049 11.97 10.121 ;
     RECT  4.392 10.121 11.97 10.157 ;
     RECT  26.064 9.391 40.698 10.4 ;
     RECT  41.544 9.383 42.174 10.459 ;
     RECT  24.015 8.339 25.326 10.603 ;
     RECT  26.064 10.4 36.594 10.603 ;
     RECT  41.544 10.459 42.21 10.987 ;
     RECT  4.5 10.157 11.97 11.011 ;
     RECT  24.015 10.603 36.594 11.173 ;
     RECT  37.332 10.4 40.698 11.173 ;
     RECT  4.428 11.011 11.97 11.209 ;
     RECT  43.02 11.083 43.038 11.213 ;
     RECT  41.544 10.987 42.246 11.237 ;
     RECT  2.304 10.049 3.402 11.371 ;
     RECT  4.356 11.209 11.97 11.371 ;
     RECT  24.015 11.173 40.698 11.551 ;
     RECT  41.544 11.237 42.21 11.551 ;
     RECT  24.015 11.551 42.21 11.645 ;
     RECT  2.304 11.371 12.042 11.669 ;
     RECT  43.092 11.371 43.11 11.947 ;
     RECT  2.304 11.669 3.114 11.975 ;
     RECT  43.056 11.947 43.11 12.029 ;
     RECT  13.215 2.413 13.497 12.289 ;
     RECT  41.58 11.645 42.21 12.317 ;
     RECT  43.056 12.029 43.074 12.317 ;
     RECT  41.616 12.317 42.21 12.361 ;
     RECT  2.415 11.975 3.114 12.475 ;
     RECT  3.852 11.669 12.042 12.475 ;
     RECT  0.108 12.379 0.126 12.509 ;
     RECT  24.015 11.645 40.734 12.587 ;
     RECT  41.616 12.361 42.246 12.595 ;
     RECT  2.415 12.475 12.042 12.715 ;
     RECT  41.616 12.595 42.282 12.797 ;
     RECT  41.616 12.797 42.246 12.941 ;
     RECT  24.015 12.587 28.134 13.531 ;
     RECT  28.872 12.587 40.734 13.531 ;
     RECT  24.015 13.531 40.734 13.565 ;
     RECT  42.084 12.941 42.246 13.675 ;
     RECT  33.768 13.565 40.734 13.915 ;
     RECT  41.58 13.675 42.246 13.915 ;
     RECT  2.304 12.715 12.042 14.009 ;
     RECT  24.015 13.565 32.958 14.171 ;
     RECT  33.768 13.915 42.246 14.179 ;
     RECT  33.768 14.179 42.318 14.369 ;
     RECT  24.015 14.171 29.862 14.405 ;
     RECT  30.708 14.171 32.958 14.449 ;
     RECT  33.768 14.369 35.19 14.449 ;
     RECT  30.708 14.449 35.19 14.525 ;
     RECT  35.928 14.369 42.318 14.549 ;
     RECT  43.092 13.531 43.11 14.549 ;
     RECT  37.872 14.549 42.318 14.621 ;
     RECT  30.816 14.525 35.19 14.711 ;
     RECT  2.304 14.009 2.79 14.731 ;
     RECT  3.564 14.009 12.042 14.731 ;
     RECT  2.304 14.731 12.042 14.813 ;
     RECT  30.852 14.711 35.19 14.819 ;
     RECT  35.928 14.549 37.062 14.909 ;
     RECT  35.928 14.909 36.954 15.089 ;
     RECT  37.872 14.621 42.21 15.089 ;
     RECT  31.104 14.819 35.19 15.151 ;
     RECT  35.928 15.089 36.918 15.151 ;
     RECT  24.015 14.405 25.434 15.163 ;
     RECT  2.304 14.813 3.474 15.179 ;
     RECT  31.104 15.151 36.918 15.179 ;
     RECT  24.015 15.163 25.47 15.251 ;
     RECT  33.876 15.179 36.918 15.296 ;
     RECT  26.748 14.405 29.862 15.421 ;
     RECT  0.108 15.295 0.126 15.437 ;
     RECT  2.304 15.179 3.33 15.449 ;
     RECT  31.104 15.179 33.138 15.449 ;
     RECT  32.868 15.449 33.138 15.521 ;
     RECT  2.304 15.449 3.186 15.533 ;
     RECT  31.392 15.449 32.13 15.593 ;
     RECT  26.748 15.421 30.042 15.763 ;
     RECT  4.392 14.813 12.042 15.829 ;
     RECT  34.164 15.296 36.918 15.871 ;
     RECT  37.872 15.089 42.174 15.871 ;
     RECT  34.164 15.871 42.174 15.899 ;
     RECT  43.02 15.787 43.038 15.917 ;
     RECT  0.144 15.787 0.162 15.965 ;
     RECT  34.164 15.899 41.022 15.989 ;
     RECT  2.304 15.533 3.114 16.025 ;
     RECT  22.86 15.979 22.878 16.025 ;
     RECT  23.184 16.141 23.202 16.205 ;
     RECT  32.94 15.521 33.138 16.219 ;
     RECT  24.015 15.251 25.326 16.295 ;
     RECT  34.416 15.989 41.022 16.301 ;
     RECT  32.112 15.593 32.13 16.375 ;
     RECT  32.94 16.219 33.606 16.375 ;
     RECT  4.356 15.829 12.042 16.405 ;
     RECT  32.112 16.375 33.606 16.411 ;
     RECT  42.084 15.899 42.174 16.411 ;
     RECT  26.748 15.763 30.582 16.501 ;
     RECT  34.416 16.301 40.734 16.529 ;
     RECT  26.496 16.501 30.582 16.537 ;
     RECT  26.496 16.537 30.942 16.609 ;
     RECT  31.86 16.411 33.606 16.609 ;
     RECT  26.496 16.609 33.606 16.709 ;
     RECT  42.084 16.411 42.21 16.747 ;
     RECT  2.304 16.025 3.078 16.799 ;
     RECT  31.932 16.709 33.606 16.835 ;
     RECT  4.32 16.405 12.042 16.843 ;
     RECT  34.704 16.529 40.734 16.877 ;
     RECT  3.96 16.843 12.042 16.879 ;
     RECT  41.544 16.747 42.21 16.925 ;
     RECT  31.932 16.835 33.57 16.943 ;
     RECT  26.496 16.709 31.086 17.041 ;
     RECT  43.092 16.339 43.11 17.041 ;
     RECT  26.46 17.041 31.086 17.069 ;
     RECT  34.815 16.877 40.734 17.077 ;
     RECT  41.544 16.925 42.174 17.077 ;
     RECT  3.42 16.879 12.042 17.105 ;
     RECT  26.46 17.069 30.726 17.105 ;
     RECT  43.056 17.041 43.11 17.165 ;
     RECT  26.46 17.105 30.51 17.185 ;
     RECT  34.815 17.077 42.174 17.249 ;
     RECT  2.304 16.799 2.697 17.275 ;
     RECT  25.488 16.411 25.506 17.339 ;
     RECT  41.544 17.249 42.174 17.339 ;
     RECT  12.816 12.289 13.497 17.383 ;
     RECT  43.056 17.165 43.074 17.453 ;
     RECT  26.244 17.185 30.51 17.491 ;
     RECT  34.815 17.249 40.734 17.519 ;
     RECT  2.268 17.275 2.697 17.581 ;
     RECT  3.42 17.105 3.438 17.581 ;
     RECT  32.364 16.943 33.57 17.609 ;
     RECT  37.08 17.519 40.734 17.609 ;
     RECT  34.815 17.519 36.27 17.611 ;
     RECT  34.596 17.611 36.27 17.617 ;
     RECT  32.472 17.609 33.57 17.645 ;
     RECT  34.452 17.617 36.27 17.689 ;
     RECT  26.1 17.491 30.51 17.717 ;
     RECT  32.544 17.645 33.57 17.761 ;
     RECT  34.308 17.689 36.27 17.761 ;
     RECT  41.544 17.339 41.67 17.789 ;
     RECT  32.544 17.761 36.27 17.879 ;
     RECT  2.268 17.581 3.438 17.887 ;
     RECT  4.284 17.105 12.042 17.887 ;
     RECT  34.596 17.879 35.097 17.915 ;
     RECT  32.58 17.879 33.57 18.023 ;
     RECT  2.268 17.887 12.042 18.029 ;
     RECT  36.18 17.879 36.27 18.059 ;
     RECT  26.316 17.717 30.51 18.149 ;
     RECT  2.268 18.029 2.754 18.221 ;
     RECT  3.492 18.029 12.042 18.221 ;
     RECT  37.116 17.609 40.734 18.301 ;
     RECT  2.268 18.221 2.697 18.329 ;
     RECT  26.892 18.149 30.51 18.329 ;
     RECT  32.76 18.023 33.57 18.329 ;
     RECT  3.564 18.221 12.042 18.419 ;
     RECT  26.892 18.329 29.697 18.419 ;
     RECT  41.58 17.789 41.67 18.427 ;
     RECT  30.492 18.329 30.51 18.571 ;
     RECT  27.18 18.419 29.697 18.599 ;
     RECT  43.092 17.899 43.11 18.599 ;
     RECT  33.552 18.329 33.57 18.661 ;
     RECT  27.252 18.599 29.697 18.761 ;
     RECT  27.252 18.761 28.17 18.797 ;
     RECT  37.116 18.301 40.77 18.811 ;
     RECT  41.58 18.427 42.174 18.811 ;
     RECT  28.944 18.761 29.697 18.869 ;
     RECT  2.304 18.329 2.697 18.955 ;
     RECT  3.96 18.419 12.042 18.959 ;
     RECT  27.252 18.797 28.026 18.995 ;
     RECT  27.504 18.995 28.026 19.067 ;
     RECT  27.828 19.067 28.026 19.103 ;
     RECT  2.304 18.955 2.754 19.147 ;
     RECT  37.116 18.811 42.174 19.229 ;
     RECT  1.728 19.147 2.754 19.291 ;
     RECT  37.476 19.229 42.174 19.301 ;
     RECT  1.728 19.291 2.862 19.535 ;
     RECT  37.512 19.301 42.174 19.571 ;
     RECT  33.552 18.661 34.038 19.615 ;
     RECT  34.815 17.915 35.097 19.615 ;
     RECT  36.18 18.059 36.198 19.615 ;
     RECT  33.552 19.615 35.097 19.651 ;
     RECT  36.18 19.615 36.342 19.651 ;
     RECT  33.552 19.651 36.342 19.769 ;
     RECT  32.76 18.329 32.778 19.771 ;
     RECT  33.552 19.769 35.097 19.771 ;
     RECT  32.76 19.771 35.097 19.811 ;
     RECT  37.62 19.571 42.174 19.867 ;
     RECT  29.304 18.869 29.697 19.885 ;
     RECT  30.492 18.571 31.05 19.885 ;
     RECT  4.284 18.959 12.042 19.921 ;
     RECT  29.304 19.885 31.05 19.963 ;
     RECT  32.76 19.811 32.778 20.047 ;
     RECT  35.82 19.769 36.342 20.047 ;
     RECT  37.62 19.867 42.21 20.047 ;
     RECT  29.124 19.963 31.05 20.083 ;
     RECT  31.788 19.963 31.806 20.083 ;
     RECT  29.124 20.083 31.806 20.119 ;
     RECT  32.544 20.047 32.778 20.119 ;
     RECT  26.856 20.011 26.874 20.219 ;
     RECT  28.584 20.119 32.778 20.219 ;
     RECT  43.092 19.339 43.11 20.219 ;
     RECT  29.415 20.219 32.778 20.309 ;
     RECT  28.584 20.219 28.602 20.345 ;
     RECT  29.415 20.309 31.05 20.345 ;
     RECT  31.788 20.309 32.778 20.345 ;
     RECT  3.924 19.921 12.042 20.353 ;
     RECT  29.415 20.345 30.15 20.381 ;
     RECT  32.328 20.345 32.778 20.381 ;
     RECT  35.82 20.047 36.738 20.425 ;
     RECT  37.62 20.047 42.246 20.425 ;
     RECT  27.828 19.103 27.846 20.489 ;
     RECT  31.032 20.345 31.05 20.489 ;
     RECT  32.76 20.381 32.778 20.579 ;
     RECT  35.82 20.425 42.246 20.615 ;
     RECT  16.164 8.509 19.494 20.623 ;
     RECT  0.54 20.425 0.558 20.669 ;
     RECT  33.66 19.811 35.097 20.683 ;
     RECT  33.408 20.683 35.097 20.687 ;
     RECT  33.408 20.687 33.426 20.723 ;
     RECT  34.236 20.687 35.097 20.849 ;
     RECT  1.728 19.535 2.79 21.001 ;
     RECT  3.636 20.353 12.042 21.001 ;
     RECT  16.164 20.623 19.962 21.119 ;
     RECT  36 20.615 42.246 21.119 ;
     RECT  36 21.119 36.018 21.191 ;
     RECT  37.188 21.119 42.246 21.191 ;
     RECT  37.764 21.191 42.246 21.227 ;
     RECT  37.764 21.227 40.698 21.425 ;
     RECT  41.616 21.227 42.246 21.437 ;
     RECT  34.776 20.849 35.097 21.497 ;
     RECT  1.728 21.001 12.042 21.541 ;
     RECT  12.816 17.383 13.95 21.541 ;
     RECT  1.728 21.541 13.95 21.659 ;
     RECT  1.728 21.659 12.078 21.695 ;
     RECT  43.092 21.787 43.11 22.027 ;
     RECT  36.504 22.009 36.522 22.045 ;
     RECT  36.504 22.045 36.63 22.081 ;
     RECT  38.088 21.425 40.698 22.081 ;
     RECT  41.616 21.437 42.174 22.081 ;
     RECT  36.252 22.081 36.63 22.199 ;
     RECT  38.088 22.081 42.174 22.208 ;
     RECT  38.088 22.208 41.67 22.301 ;
     RECT  36.504 22.199 36.63 22.441 ;
     RECT  38.088 22.301 41.634 22.585 ;
     RECT  37.98 22.585 41.634 22.739 ;
     RECT  30.78 22.711 30.798 22.883 ;
     RECT  36.504 22.441 37.098 22.891 ;
     RECT  2.304 21.695 12.078 22.919 ;
     RECT  2.304 22.919 12.042 23.009 ;
     RECT  36.504 22.891 37.422 23.009 ;
     RECT  34.815 21.497 35.097 23.053 ;
     RECT  38.196 22.739 41.634 23.357 ;
     RECT  0.108 23.323 0.126 23.549 ;
     RECT  16.92 21.119 19.962 23.549 ;
     RECT  34.776 23.053 35.097 23.657 ;
     RECT  43.056 22.027 43.11 23.741 ;
     RECT  2.304 23.009 3.618 23.803 ;
     RECT  4.428 23.009 12.042 23.803 ;
     RECT  36.504 23.009 37.134 23.863 ;
     RECT  36.504 23.863 37.458 23.899 ;
     RECT  38.196 23.357 41.058 23.899 ;
     RECT  36.504 23.899 41.058 23.981 ;
     RECT  15.084 15.691 15.102 24.169 ;
     RECT  16.164 21.119 16.182 24.169 ;
     RECT  17.244 23.549 19.962 24.359 ;
     RECT  36.504 23.981 41.022 24.359 ;
     RECT  43.056 23.741 43.074 24.475 ;
     RECT  2.304 23.803 12.042 24.629 ;
     RECT  34.815 23.657 35.097 24.673 ;
     RECT  42.156 24.232 42.174 24.715 ;
     RECT  34.776 24.673 35.097 24.773 ;
     RECT  41.94 24.715 42.174 24.809 ;
     RECT  2.304 24.629 2.754 24.859 ;
     RECT  3.924 24.629 12.042 25.169 ;
     RECT  43.056 24.475 43.11 25.277 ;
     RECT  4.464 25.169 12.042 25.475 ;
     RECT  15.084 24.169 16.182 25.483 ;
     RECT  17.532 24.359 19.962 25.483 ;
     RECT  2.268 24.859 2.754 25.531 ;
     RECT  34.815 24.773 35.097 25.717 ;
     RECT  37.224 24.359 41.022 25.825 ;
     RECT  43.092 25.277 43.11 25.853 ;
     RECT  2.268 25.531 3.078 25.889 ;
     RECT  3.492 26.095 3.51 26.141 ;
     RECT  37.188 25.825 41.022 26.155 ;
     RECT  42.084 24.809 42.174 26.155 ;
     RECT  4.536 25.475 12.042 26.221 ;
     RECT  15.084 25.483 19.962 26.249 ;
     RECT  37.188 26.155 42.174 26.249 ;
     RECT  15.084 26.249 15.678 26.257 ;
     RECT  34.776 25.717 35.097 26.257 ;
     RECT  34.776 26.257 35.154 26.293 ;
     RECT  2.268 25.889 2.754 26.321 ;
     RECT  2.268 26.321 2.697 26.357 ;
     RECT  14.868 26.257 15.678 26.357 ;
     RECT  16.452 26.249 19.962 26.357 ;
     RECT  34.776 26.293 35.226 26.789 ;
     RECT  2.304 26.357 2.697 27.067 ;
     RECT  37.584 26.249 42.174 27.139 ;
     RECT  2.304 27.067 2.79 27.211 ;
     RECT  3.816 26.221 12.042 27.211 ;
     RECT  37.584 27.139 42.21 27.341 ;
     RECT  2.304 27.211 12.042 27.365 ;
     RECT  3.96 27.365 12.042 27.409 ;
     RECT  12.816 21.659 13.95 27.409 ;
     RECT  16.884 26.357 19.962 27.599 ;
     RECT  37.584 27.341 42.174 27.599 ;
     RECT  15.084 26.357 15.678 27.715 ;
     RECT  17.712 27.599 19.962 27.751 ;
     RECT  14.94 27.715 15.678 27.841 ;
     RECT  37.332 27.607 37.35 27.841 ;
     RECT  37.044 27.841 37.35 27.869 ;
     RECT  38.124 27.599 42.174 27.869 ;
     RECT  36 27.445 36.018 27.877 ;
     RECT  43.092 26.761 43.11 27.931 ;
     RECT  14.868 27.841 15.678 27.941 ;
     RECT  43.056 27.931 43.11 28.049 ;
     RECT  2.304 27.365 3.114 28.139 ;
     RECT  38.376 27.869 42.174 28.219 ;
     RECT  3.96 27.409 13.95 28.291 ;
     RECT  43.092 28.049 43.11 28.319 ;
     RECT  35.928 27.877 36.018 28.409 ;
     RECT  38.376 28.219 42.21 28.493 ;
     RECT  3.96 28.291 13.986 28.561 ;
     RECT  37.044 27.869 37.062 28.561 ;
     RECT  36.576 28.561 37.062 28.651 ;
     RECT  38.376 28.493 40.842 28.651 ;
     RECT  36.576 28.651 40.842 28.679 ;
     RECT  41.58 28.493 42.21 28.843 ;
     RECT  36.684 28.679 40.842 28.985 ;
     RECT  41.58 28.843 42.246 28.987 ;
     RECT  2.304 28.139 2.79 29.083 ;
     RECT  2.268 29.083 2.79 29.101 ;
     RECT  3.852 28.561 13.986 29.101 ;
     RECT  2.268 29.101 13.986 29.219 ;
     RECT  15.084 27.941 15.678 29.227 ;
     RECT  43.092 29.083 43.11 29.227 ;
     RECT  43.056 29.227 43.11 29.371 ;
     RECT  2.268 29.219 3.582 29.399 ;
     RECT  41.58 28.987 42.282 29.399 ;
     RECT  36.684 28.985 36.99 29.489 ;
     RECT  43.02 29.371 43.11 29.489 ;
     RECT  2.268 29.399 3.114 29.525 ;
     RECT  37.836 28.985 40.842 29.533 ;
     RECT  41.58 29.399 42.21 29.533 ;
     RECT  43.02 29.489 43.038 29.549 ;
     RECT  37.836 29.533 42.21 29.597 ;
     RECT  14.868 29.227 15.678 29.641 ;
     RECT  4.608 29.219 13.986 29.669 ;
     RECT  2.304 29.525 3.114 29.759 ;
     RECT  4.608 29.669 12.294 29.759 ;
     RECT  37.836 29.597 42.174 29.767 ;
     RECT  14.832 29.641 15.678 29.795 ;
     RECT  37.224 29.767 42.174 29.831 ;
     RECT  14.868 29.795 15.678 30.029 ;
     RECT  37.224 29.831 39.006 30.029 ;
     RECT  39.888 29.831 42.174 30.029 ;
     RECT  34.815 26.789 35.097 30.037 ;
     RECT  41.544 30.029 42.174 30.209 ;
     RECT  36.36 30.073 36.378 30.299 ;
     RECT  37.368 30.029 39.006 30.371 ;
     RECT  2.304 29.759 3.078 30.613 ;
     RECT  3.852 30.283 3.87 30.613 ;
     RECT  2.304 30.613 3.87 30.715 ;
     RECT  4.608 29.759 11.97 30.715 ;
     RECT  41.58 30.209 42.174 30.721 ;
     RECT  43.02 30.763 43.038 30.847 ;
     RECT  37.44 30.371 39.006 30.883 ;
     RECT  39.888 30.029 40.662 30.883 ;
     RECT  0.108 30.763 0.126 30.893 ;
     RECT  42.984 30.847 43.038 30.907 ;
     RECT  17.712 27.751 20.25 31.109 ;
     RECT  37.44 30.883 40.662 31.109 ;
     RECT  17.928 31.109 20.25 31.289 ;
     RECT  37.656 31.109 40.662 31.289 ;
     RECT  36.504 31.153 36.522 31.495 ;
     RECT  31.932 30.577 31.95 31.523 ;
     RECT  34.776 30.037 35.097 31.531 ;
     RECT  41.58 30.721 42.21 31.559 ;
     RECT  36.144 31.495 36.522 31.649 ;
     RECT  37.656 31.289 40.59 31.649 ;
     RECT  41.58 31.559 42.174 31.693 ;
     RECT  42.984 30.907 43.11 31.709 ;
     RECT  34.776 31.531 35.154 31.721 ;
     RECT  2.304 30.715 11.97 31.919 ;
     RECT  34.776 31.721 35.097 31.919 ;
     RECT  4.644 31.919 11.97 31.955 ;
     RECT  15.084 30.029 15.678 32.189 ;
     RECT  17.964 31.289 20.25 32.233 ;
     RECT  37.656 31.649 40.554 32.587 ;
     RECT  41.472 31.693 42.174 32.587 ;
     RECT  34.815 31.919 35.097 32.611 ;
     RECT  0.54 32.467 0.558 32.669 ;
     RECT  43.092 31.709 43.11 32.683 ;
     RECT  37.656 32.587 42.174 32.773 ;
     RECT  2.304 31.919 2.862 32.881 ;
     RECT  3.708 31.919 3.726 32.881 ;
     RECT  4.68 31.955 11.97 32.881 ;
     RECT  17.784 32.233 20.25 32.909 ;
     RECT  43.056 32.683 43.11 32.909 ;
     RECT  2.304 32.881 11.97 32.971 ;
     RECT  34.815 32.611 35.154 32.999 ;
     RECT  43.056 32.909 43.074 33.179 ;
     RECT  14.904 33.151 14.922 33.241 ;
     RECT  14.832 33.241 14.922 33.269 ;
     RECT  2.268 32.971 11.97 33.341 ;
     RECT  14.832 33.269 14.85 33.539 ;
     RECT  36.972 32.773 42.174 33.595 ;
     RECT  36.972 33.595 42.21 34.051 ;
     RECT  0.108 33.979 0.126 34.109 ;
     RECT  2.304 33.341 11.97 34.115 ;
     RECT  36.972 34.051 42.246 34.349 ;
     RECT  2.304 34.115 3.366 34.421 ;
     RECT  37.44 34.349 42.246 34.457 ;
     RECT  37.44 34.457 40.698 34.493 ;
     RECT  34.815 32.999 35.097 34.501 ;
     RECT  17.964 32.909 20.25 34.889 ;
     RECT  36.504 34.627 36.522 34.889 ;
     RECT  2.304 34.421 2.898 34.925 ;
     RECT  14.832 34.897 14.85 35.033 ;
     RECT  43.092 34.123 43.11 35.035 ;
     RECT  34.776 34.501 35.097 35.267 ;
     RECT  4.14 34.115 11.97 35.311 ;
     RECT  37.44 34.493 40.626 35.311 ;
     RECT  36.756 35.311 40.626 35.437 ;
     RECT  2.304 34.925 2.862 35.545 ;
     RECT  36.756 35.437 40.734 35.545 ;
     RECT  41.616 34.457 42.246 35.549 ;
     RECT  2.268 35.545 2.862 35.671 ;
     RECT  2.268 35.671 3.042 35.693 ;
     RECT  36.756 35.545 40.842 35.699 ;
     RECT  43.02 35.035 43.11 35.789 ;
     RECT  37.26 35.699 40.842 35.803 ;
     RECT  41.58 35.581 41.598 35.803 ;
     RECT  3.78 35.311 11.97 35.977 ;
     RECT  34.815 35.267 35.097 36.049 ;
     RECT  43.092 35.789 43.11 36.077 ;
     RECT  2.304 35.693 3.042 36.121 ;
     RECT  3.78 35.977 12.15 36.121 ;
     RECT  2.304 36.121 12.15 36.239 ;
     RECT  37.26 35.803 41.598 36.311 ;
     RECT  37.476 36.311 41.598 36.419 ;
     RECT  41.58 36.419 41.598 36.571 ;
     RECT  37.476 36.419 40.554 36.581 ;
     RECT  22.716 36.481 22.734 36.617 ;
     RECT  41.58 36.571 42.21 36.667 ;
     RECT  3.852 36.239 12.15 36.751 ;
     RECT  41.58 36.667 42.93 36.845 ;
     RECT  3.852 36.751 12.186 36.931 ;
     RECT  13.215 29.669 13.986 36.931 ;
     RECT  3.852 36.931 13.986 36.989 ;
     RECT  34.776 36.049 35.097 37.093 ;
     RECT  38.412 36.581 40.554 37.165 ;
     RECT  2.304 36.239 3.078 37.201 ;
     RECT  3.852 36.989 11.97 37.201 ;
     RECT  36.504 36.823 36.522 37.229 ;
     RECT  38.412 37.165 40.59 37.363 ;
     RECT  34.776 37.093 35.154 37.391 ;
     RECT  37.476 36.581 37.494 37.435 ;
     RECT  41.58 36.845 42.246 37.463 ;
     RECT  36.972 37.435 37.566 37.471 ;
     RECT  38.412 37.363 40.662 37.471 ;
     RECT  43.092 37.195 43.11 37.499 ;
     RECT  36.972 37.471 40.662 37.561 ;
     RECT  34.815 37.391 35.154 37.589 ;
     RECT  14.832 36.931 14.85 37.625 ;
     RECT  2.304 37.201 11.97 37.939 ;
     RECT  41.58 37.463 42.21 37.963 ;
     RECT  41.544 37.963 42.21 38.003 ;
     RECT  36.972 37.561 40.698 38.107 ;
     RECT  2.304 37.939 12.258 38.129 ;
     RECT  4.068 38.129 12.258 38.165 ;
     RECT  36.972 38.107 41.058 38.165 ;
     RECT  4.068 38.165 12.222 38.399 ;
     RECT  43.02 38.407 43.038 38.491 ;
     RECT  43.02 38.491 43.11 38.741 ;
     RECT  36.972 38.165 41.022 38.911 ;
     RECT  15.66 32.189 15.678 38.939 ;
     RECT  16.884 27.599 16.902 38.947 ;
     RECT  18.108 34.889 20.25 38.947 ;
     RECT  4.248 38.399 12.222 39.047 ;
     RECT  43.092 38.741 43.11 39.053 ;
     RECT  34.815 37.589 35.097 39.091 ;
     RECT  16.884 38.947 20.25 39.119 ;
     RECT  4.248 39.047 12.186 39.209 ;
     RECT  2.304 38.129 3.294 39.289 ;
     RECT  34.776 39.091 35.097 39.445 ;
     RECT  13.215 36.989 13.986 39.451 ;
     RECT  24.015 16.295 24.297 39.451 ;
     RECT  16.884 39.119 17.082 39.479 ;
     RECT  34.704 39.445 35.097 39.485 ;
     RECT  13.104 39.451 13.986 39.488 ;
     RECT  23.904 39.451 24.297 39.488 ;
     RECT  42.12 38.003 42.21 39.499 ;
     RECT  2.304 39.289 3.978 39.749 ;
     RECT  4.752 39.209 12.186 39.749 ;
     RECT  36.936 38.911 41.022 39.865 ;
     RECT  42.12 39.499 42.246 39.883 ;
     RECT  4.788 39.749 12.186 40.019 ;
     RECT  5.04 40.019 12.186 40.091 ;
     RECT  41.832 39.883 42.246 40.127 ;
     RECT  36.864 39.865 41.022 40.267 ;
     RECT  41.832 40.127 42.21 40.267 ;
     RECT  36.864 40.267 42.21 40.397 ;
     RECT  2.304 39.749 3.87 40.711 ;
     RECT  43.092 40.699 43.11 40.739 ;
     RECT  41.58 40.397 42.21 40.829 ;
     RECT  18.108 39.119 20.25 40.837 ;
     RECT  36.864 40.397 40.497 40.837 ;
     RECT  18.108 40.837 20.43 40.909 ;
     RECT  17.676 40.909 20.43 41.009 ;
     RECT  5.256 40.091 12.186 41.071 ;
     RECT  36.792 40.837 40.497 41.179 ;
     RECT  5.148 41.071 12.186 41.215 ;
     RECT  36.792 41.179 41.058 41.215 ;
     RECT  2.304 40.711 4.086 41.341 ;
     RECT  17.676 41.009 19.998 41.369 ;
     RECT  36.252 41.215 41.058 41.369 ;
     RECT  2.304 41.341 4.23 41.377 ;
     RECT  5.148 41.215 12.33 41.377 ;
     RECT  36.504 41.369 41.058 41.501 ;
     RECT  2.304 41.377 12.402 41.549 ;
     RECT  42.12 40.829 42.21 41.563 ;
     RECT  13.215 39.488 13.986 41.639 ;
     RECT  2.304 41.549 12.186 41.645 ;
     RECT  42.12 41.563 42.246 41.881 ;
     RECT  42.12 41.881 42.318 41.947 ;
     RECT  41.58 41.947 42.318 42.125 ;
     RECT  36.504 41.501 40.497 42.235 ;
     RECT  41.58 42.125 42.282 42.235 ;
     RECT  36.504 42.235 42.282 42.331 ;
     RECT  2.304 41.645 2.697 42.421 ;
     RECT  3.564 41.645 12.186 42.421 ;
     RECT  2.304 42.421 12.186 42.449 ;
     RECT  3.996 42.449 12.186 42.521 ;
     RECT  36.36 42.331 42.282 42.557 ;
     RECT  36.36 42.557 40.698 42.691 ;
     RECT  4.536 42.521 12.186 42.719 ;
     RECT  41.616 42.557 42.282 42.749 ;
     RECT  36.288 42.691 40.698 42.791 ;
     RECT  18.108 41.369 19.998 42.871 ;
     RECT  2.304 42.449 3.006 42.907 ;
     RECT  18.108 42.871 20.61 42.989 ;
     RECT  2.268 42.907 3.006 43.025 ;
     RECT  20.7 43.069 20.862 43.259 ;
     RECT  34.776 39.485 35.097 43.295 ;
     RECT  41.616 42.749 42.21 43.421 ;
     RECT  36.864 42.791 40.698 43.439 ;
     RECT  18.108 42.989 19.926 43.529 ;
     RECT  4.608 42.719 12.186 43.681 ;
     RECT  14.832 43.609 14.85 43.799 ;
     RECT  36.864 43.439 40.59 43.843 ;
     RECT  42.156 43.421 42.21 43.867 ;
     RECT  18.504 43.529 19.926 43.951 ;
     RECT  20.7 43.259 20.718 43.951 ;
     RECT  2.304 43.025 3.006 44.041 ;
     RECT  3.96 43.681 12.186 44.041 ;
     RECT  18.504 43.951 20.718 44.069 ;
     RECT  2.304 44.041 12.186 44.141 ;
     RECT  42.156 43.867 42.246 44.155 ;
     RECT  42.12 44.155 42.246 44.249 ;
     RECT  3.456 44.141 12.186 44.339 ;
     RECT  34.815 43.295 35.097 44.347 ;
     RECT  3.456 44.339 3.474 44.411 ;
     RECT  34.776 44.347 35.097 44.447 ;
     RECT  43.092 42.331 43.11 44.447 ;
     RECT  42.12 44.249 42.174 44.491 ;
     RECT  41.616 44.491 42.174 44.539 ;
     RECT  4.284 44.339 12.186 44.645 ;
     RECT  36.792 43.843 40.59 44.851 ;
     RECT  36 44.077 36.018 44.923 ;
     RECT  35.892 44.923 36.018 44.951 ;
     RECT  2.304 44.141 2.697 44.971 ;
     RECT  36.792 44.851 40.626 45.067 ;
     RECT  41.58 44.539 42.174 45.067 ;
     RECT  17.1 44.653 17.118 45.149 ;
     RECT  34.815 44.447 35.097 45.193 ;
     RECT  35.892 44.951 35.91 45.257 ;
     RECT  36.792 45.067 42.174 45.257 ;
     RECT  41.544 45.257 42.174 45.301 ;
     RECT  3.78 45.391 3.798 45.491 ;
     RECT  36.792 45.257 40.698 45.697 ;
     RECT  36.756 45.697 40.698 45.733 ;
     RECT  4.68 44.645 12.186 45.805 ;
     RECT  2.304 44.971 2.97 45.841 ;
     RECT  4.284 45.805 12.186 45.869 ;
     RECT  2.304 45.841 3.546 45.959 ;
     RECT  36.684 45.733 40.698 45.959 ;
     RECT  34.776 45.193 35.097 45.967 ;
     RECT  4.32 45.869 12.186 46.031 ;
     RECT  36.792 45.959 40.698 46.075 ;
     RECT  41.544 45.301 42.21 46.075 ;
     RECT  36.792 46.075 42.21 46.112 ;
     RECT  34.776 45.967 35.154 46.139 ;
     RECT  17.676 46.111 17.694 46.229 ;
     RECT  41.58 46.112 42.21 46.315 ;
     RECT  43.092 45.451 43.11 46.409 ;
     RECT  2.304 45.959 3.402 46.747 ;
     RECT  2.304 46.747 3.438 46.805 ;
     RECT  4.428 46.031 12.186 46.885 ;
     RECT  14.832 46.813 14.85 46.949 ;
     RECT  41.58 46.315 42.282 46.949 ;
     RECT  3.852 46.885 12.186 47.039 ;
     RECT  36.792 46.112 40.662 47.083 ;
     RECT  18.54 44.069 20.718 47.309 ;
     RECT  3.888 47.039 12.186 47.579 ;
     RECT  36.792 47.083 41.022 47.723 ;
     RECT  2.304 46.805 2.934 47.731 ;
     RECT  42.156 46.949 42.282 47.755 ;
     RECT  29.415 20.381 29.697 47.821 ;
     RECT  3.96 47.579 12.186 48.001 ;
     RECT  36.792 47.723 40.806 48.001 ;
     RECT  29.088 47.821 29.697 48.029 ;
     RECT  36.756 48.001 40.806 48.119 ;
     RECT  3.96 48.001 12.33 48.191 ;
     RECT  3.96 48.191 9.738 48.389 ;
     RECT  2.304 47.731 3.006 48.433 ;
     RECT  4.392 48.389 9.738 48.461 ;
     RECT  18.615 47.309 20.718 48.541 ;
     RECT  41.544 47.755 42.282 48.557 ;
     RECT  43.092 47.227 43.11 48.797 ;
     RECT  36.792 48.119 40.806 48.803 ;
     RECT  10.476 48.191 12.33 48.901 ;
     RECT  0.144 48.859 0.162 48.989 ;
     RECT  2.304 48.433 3.222 49.081 ;
     RECT  18.615 48.541 21.222 49.207 ;
     RECT  34.776 46.139 35.097 49.235 ;
     RECT  18.615 49.207 21.366 49.307 ;
     RECT  41.58 48.557 42.282 49.325 ;
     RECT  2.304 49.081 3.258 49.351 ;
     RECT  4.392 48.461 4.662 49.351 ;
     RECT  2.304 49.351 4.662 49.477 ;
     RECT  5.472 48.461 9.738 49.477 ;
     RECT  2.304 49.477 9.738 49.517 ;
     RECT  5.328 49.517 9.738 49.549 ;
     RECT  10.476 48.901 12.366 49.549 ;
     RECT  36.792 48.803 40.734 49.549 ;
     RECT  2.304 49.517 4.338 49.739 ;
     RECT  36.576 49.549 40.734 49.775 ;
     RECT  41.58 49.325 42.246 49.855 ;
     RECT  43.092 49.915 43.11 49.964 ;
     RECT  2.304 49.739 4.302 50.009 ;
     RECT  4.284 50.009 4.302 50.045 ;
     RECT  41.544 49.855 42.246 50.117 ;
     RECT  5.328 49.549 12.366 50.189 ;
     RECT  36.576 49.775 40.554 50.683 ;
     RECT  41.544 50.117 42.21 50.683 ;
     RECT  4.572 50.731 4.59 50.971 ;
     RECT  5.328 50.189 10.926 50.971 ;
     RECT  36.576 50.683 42.21 50.971 ;
     RECT  4.572 50.971 10.926 51.089 ;
     RECT  4.572 51.089 5.634 51.125 ;
     RECT  2.304 50.009 3.51 51.241 ;
     RECT  4.572 51.125 5.598 51.241 ;
     RECT  36.576 50.971 42.246 51.539 ;
     RECT  2.304 51.241 5.598 51.809 ;
     RECT  36.576 51.539 42.21 51.809 ;
     RECT  6.408 51.089 10.926 51.821 ;
     RECT  0.108 50.665 0.126 52.061 ;
     RECT  3.42 51.809 5.598 52.169 ;
     RECT  36.576 51.809 42.174 52.349 ;
     RECT  34.815 49.235 35.097 52.405 ;
     RECT  13.215 41.639 13.497 52.411 ;
     RECT  24.015 39.488 24.297 52.411 ;
     RECT  34.704 52.405 35.097 52.445 ;
     RECT  13.104 52.411 13.497 52.448 ;
     RECT  23.904 52.411 24.297 52.448 ;
     RECT  3.888 52.169 5.598 52.493 ;
     RECT  36.576 52.349 41.31 52.541 ;
     RECT  4.284 52.493 5.598 52.591 ;
     RECT  6.552 51.821 10.926 52.591 ;
     RECT  43.092 51.709 43.11 52.747 ;
     RECT  34.776 52.445 35.097 52.781 ;
     RECT  43.02 52.747 43.11 52.817 ;
     RECT  4.284 52.591 10.926 53.321 ;
     RECT  4.284 53.321 10.89 53.393 ;
     RECT  2.304 51.809 2.697 53.401 ;
     RECT  4.284 53.393 4.518 53.401 ;
     RECT  11.736 50.189 12.366 53.429 ;
     RECT  36.576 52.541 41.022 53.519 ;
     RECT  42.156 52.349 42.174 53.659 ;
     RECT  42.156 53.659 42.21 53.671 ;
     RECT  2.304 53.401 3.258 53.761 ;
     RECT  2.304 53.761 3.402 53.869 ;
     RECT  4.176 53.401 4.518 53.869 ;
     RECT  34.815 52.781 35.097 53.869 ;
     RECT  43.092 52.817 43.11 53.897 ;
     RECT  2.304 53.869 4.518 54.095 ;
     RECT  5.328 53.393 10.89 54.283 ;
     RECT  36.576 53.519 40.698 54.301 ;
     RECT  41.616 53.671 42.21 54.317 ;
     RECT  36.54 54.301 40.698 54.445 ;
     RECT  36.54 54.445 40.806 54.481 ;
     RECT  41.832 54.317 42.21 54.571 ;
     RECT  36.468 54.481 40.806 54.599 ;
     RECT  36.576 54.599 40.806 54.635 ;
     RECT  0.108 54.571 0.126 54.701 ;
     RECT  41.832 54.571 42.246 54.845 ;
     RECT  4.536 54.283 10.89 54.859 ;
     RECT  4.536 54.859 10.962 54.905 ;
     RECT  11.808 53.429 12.366 54.985 ;
     RECT  18.615 49.307 21.294 55.013 ;
     RECT  2.304 54.095 3.762 55.021 ;
     RECT  4.536 54.905 10.89 55.021 ;
     RECT  2.304 55.021 10.89 55.139 ;
     RECT  34.776 53.869 35.097 55.247 ;
     RECT  41.832 54.845 42.21 55.291 ;
     RECT  41.616 55.291 42.21 55.483 ;
     RECT  18.615 55.013 19.53 55.589 ;
     RECT  41.58 55.483 42.21 55.589 ;
     RECT  5.328 55.139 10.89 55.651 ;
     RECT  41.616 55.589 42.21 55.723 ;
     RECT  2.304 55.139 4.374 55.751 ;
     RECT  43.092 55.579 43.11 55.759 ;
     RECT  36.576 54.635 40.554 55.795 ;
     RECT  4.356 55.751 4.374 55.867 ;
     RECT  5.328 55.651 10.926 55.921 ;
     RECT  11.808 54.985 12.402 55.921 ;
     RECT  0.54 55.795 0.558 55.949 ;
     RECT  43.056 55.759 43.11 56.129 ;
     RECT  43.056 56.129 43.074 56.141 ;
     RECT  4.356 55.867 4.446 56.219 ;
     RECT  5.328 55.921 12.402 56.219 ;
     RECT  4.572 56.371 4.59 56.443 ;
     RECT  5.328 56.219 5.346 56.443 ;
     RECT  36.576 55.795 40.734 56.489 ;
     RECT  20.592 55.013 21.294 56.597 ;
     RECT  41.616 55.723 42.246 56.635 ;
     RECT  34.815 55.247 35.097 56.803 ;
     RECT  2.304 55.751 3.618 56.839 ;
     RECT  41.58 56.635 42.246 56.867 ;
     RECT  34.776 56.803 35.097 56.903 ;
     RECT  4.572 56.443 5.346 57.019 ;
     RECT  18.615 55.589 18.897 57.109 ;
     RECT  2.304 56.839 3.69 57.271 ;
     RECT  4.5 57.019 5.346 57.271 ;
     RECT  2.304 57.271 5.346 57.307 ;
     RECT  2.304 57.307 5.418 57.371 ;
     RECT  43.092 56.875 43.11 57.403 ;
     RECT  36.576 56.489 40.662 57.451 ;
     RECT  41.58 56.867 42.21 57.451 ;
     RECT  20.772 56.597 21.294 57.479 ;
     RECT  43.056 57.403 43.11 57.541 ;
     RECT  2.304 57.371 3.474 57.569 ;
     RECT  18.396 57.109 18.897 57.569 ;
     RECT  36.576 57.451 42.21 57.569 ;
     RECT  2.304 57.569 3.402 57.641 ;
     RECT  43.02 57.541 43.11 57.677 ;
     RECT  43.056 57.677 43.11 57.749 ;
     RECT  4.32 57.371 5.418 57.839 ;
     RECT  20.772 57.479 20.826 57.847 ;
     RECT  34.815 56.903 35.097 57.847 ;
     RECT  4.536 57.839 5.418 57.991 ;
     RECT  43.092 57.749 43.11 58.019 ;
     RECT  4.536 57.991 5.454 58.109 ;
     RECT  0.108 58.117 0.126 58.157 ;
     RECT  18.468 57.569 18.897 58.189 ;
     RECT  36.648 57.569 42.21 58.261 ;
     RECT  4.536 58.109 5.346 58.289 ;
     RECT  4.536 58.289 5.13 58.379 ;
     RECT  18.468 58.189 19.098 58.379 ;
     RECT  2.304 57.641 3.222 58.531 ;
     RECT  36.648 58.261 42.246 58.621 ;
     RECT  2.304 58.531 3.762 58.649 ;
     RECT  6.192 56.219 12.402 58.649 ;
     RECT  36.504 58.621 42.246 58.699 ;
     RECT  2.304 58.649 3.042 58.721 ;
     RECT  34.776 57.847 35.097 58.721 ;
     RECT  36.504 58.699 42.282 58.765 ;
     RECT  36.504 58.765 42.39 58.829 ;
     RECT  5.112 58.379 5.13 58.955 ;
     RECT  6.192 58.649 11.25 59.071 ;
     RECT  6.048 59.071 11.25 59.269 ;
     RECT  36.504 58.829 42.174 59.459 ;
     RECT  2.304 58.721 3.006 59.503 ;
     RECT  5.832 59.269 11.25 59.531 ;
     RECT  5.94 59.531 11.25 59.639 ;
     RECT  15.084 53.527 15.102 59.639 ;
     RECT  3.924 58.699 4.014 59.701 ;
     RECT  2.304 59.503 3.042 59.803 ;
     RECT  3.78 59.701 4.014 59.803 ;
     RECT  6.012 59.639 11.25 59.881 ;
     RECT  43.092 59.467 43.11 59.885 ;
     RECT  6.012 59.881 11.466 59.999 ;
     RECT  2.304 59.803 4.014 60.035 ;
     RECT  20.664 57.847 20.826 60.043 ;
     RECT  3.78 60.035 4.014 60.151 ;
     RECT  4.86 59.341 4.878 60.151 ;
     RECT  34.815 58.721 35.097 60.241 ;
     RECT  6.012 59.999 11.43 60.341 ;
     RECT  34.776 60.241 35.097 60.341 ;
     RECT  3.78 60.151 4.878 60.385 ;
     RECT  6.012 60.341 11.358 60.421 ;
     RECT  36.648 59.459 42.174 60.647 ;
     RECT  41.544 60.647 42.174 60.749 ;
     RECT  2.304 60.035 2.754 60.961 ;
     RECT  3.78 60.385 4.914 60.961 ;
     RECT  2.304 60.961 4.914 61.079 ;
     RECT  41.58 60.749 42.174 61.099 ;
     RECT  20.664 60.043 21.258 61.123 ;
     RECT  4.86 61.079 4.914 61.231 ;
     RECT  5.832 60.421 11.358 61.231 ;
     RECT  36.648 60.647 40.626 61.465 ;
     RECT  0.144 61.387 0.162 61.517 ;
     RECT  4.86 61.231 11.358 61.565 ;
     RECT  36.648 61.465 40.698 61.619 ;
     RECT  34.815 60.341 35.097 61.735 ;
     RECT  12.384 58.649 12.402 61.763 ;
     RECT  37.008 61.619 40.698 61.799 ;
     RECT  41.58 61.099 42.21 61.867 ;
     RECT  34.776 61.735 35.097 61.961 ;
     RECT  41.58 61.867 42.246 61.997 ;
     RECT  37.008 61.799 40.626 62.033 ;
     RECT  2.304 61.079 3.942 62.041 ;
     RECT  4.86 61.565 4.878 62.041 ;
     RECT  41.58 61.997 42.21 62.069 ;
     RECT  42.156 62.069 42.21 62.195 ;
     RECT  5.832 61.565 11.358 62.545 ;
     RECT  37.08 62.033 40.626 62.545 ;
     RECT  5.652 62.545 11.358 62.581 ;
     RECT  5.652 62.581 11.502 62.669 ;
     RECT  43.092 62.239 43.11 62.683 ;
     RECT  0.144 62.683 0.162 62.813 ;
     RECT  34.815 61.961 35.097 62.851 ;
     RECT  42.192 62.195 42.21 62.861 ;
     RECT  43.02 62.683 43.11 62.861 ;
     RECT  37.08 62.545 41.058 63.067 ;
     RECT  5.76 62.669 11.502 63.085 ;
     RECT  18.468 58.379 18.897 63.121 ;
     RECT  37.08 63.067 42.174 63.149 ;
     RECT  2.304 62.041 4.878 63.211 ;
     RECT  18.468 63.121 19.314 63.211 ;
     RECT  2.304 63.211 4.914 63.239 ;
     RECT  18.468 63.211 19.494 63.248 ;
     RECT  4.284 63.239 4.914 63.275 ;
     RECT  43.092 62.861 43.11 63.341 ;
     RECT  18.468 63.248 19.386 63.383 ;
     RECT  5.76 63.085 12.078 63.391 ;
     RECT  4.284 63.275 4.878 63.821 ;
     RECT  0.108 63.787 0.126 63.823 ;
     RECT  42.12 63.149 42.174 63.835 ;
     RECT  0.108 63.823 0.558 63.869 ;
     RECT  37.08 63.149 41.058 63.931 ;
     RECT  42.12 63.835 42.21 63.931 ;
     RECT  20.664 61.123 21.654 64.049 ;
     RECT  0.54 63.869 0.558 64.061 ;
     RECT  37.08 63.931 42.246 64.093 ;
     RECT  4.536 63.821 4.878 64.129 ;
     RECT  5.688 63.391 12.078 64.129 ;
     RECT  4.536 64.129 12.078 64.229 ;
     RECT  2.304 63.239 3.438 64.291 ;
     RECT  18.504 63.383 19.386 64.291 ;
     RECT  36.684 64.093 42.246 64.319 ;
     RECT  2.304 64.291 3.798 64.391 ;
     RECT  4.536 64.229 4.878 64.397 ;
     RECT  34.776 62.851 35.097 64.867 ;
     RECT  5.688 64.229 12.078 64.939 ;
     RECT  4.572 64.397 4.878 65.011 ;
     RECT  5.688 64.939 12.294 65.011 ;
     RECT  18.504 64.291 19.458 65.011 ;
     RECT  37.116 64.319 42.246 65.021 ;
     RECT  34.2 64.867 35.097 65.039 ;
     RECT  4.572 65.011 12.294 65.129 ;
     RECT  34.776 65.039 35.097 65.129 ;
     RECT  37.116 65.021 40.734 65.129 ;
     RECT  2.304 64.391 3.042 65.227 ;
     RECT  43.092 64.315 43.11 65.273 ;
     RECT  2.304 65.227 3.078 65.281 ;
     RECT  4.572 65.129 4.698 65.281 ;
     RECT  5.724 65.129 12.294 65.309 ;
     RECT  18.504 65.011 19.854 65.407 ;
     RECT  4.212 65.281 4.698 65.435 ;
     RECT  18.504 65.407 20.034 65.507 ;
     RECT  21.24 64.049 21.654 65.669 ;
     RECT  37.116 65.129 40.626 65.669 ;
     RECT  5.724 65.309 12.078 65.777 ;
     RECT  21.42 65.669 21.654 65.813 ;
     RECT  21.492 65.813 21.654 65.939 ;
     RECT  37.188 65.669 40.554 65.939 ;
     RECT  34.815 65.129 35.097 65.983 ;
     RECT  5.724 65.777 8.262 66.011 ;
     RECT  4.212 65.435 4.554 66.091 ;
     RECT  2.304 65.281 3.186 66.181 ;
     RECT  4.032 66.091 4.554 66.181 ;
     RECT  2.304 66.181 4.554 66.209 ;
     RECT  41.58 65.021 42.246 66.209 ;
     RECT  2.304 66.209 3.798 66.353 ;
     RECT  43.056 66.091 43.074 66.379 ;
     RECT  5.832 66.011 8.262 66.389 ;
     RECT  4.896 66.475 4.914 66.515 ;
     RECT  41.832 66.209 42.246 66.659 ;
     RECT  43.056 66.379 43.11 66.701 ;
     RECT  37.188 65.939 40.497 66.757 ;
     RECT  21.636 65.939 21.654 67.019 ;
     RECT  36.972 66.757 40.497 67.135 ;
     RECT  2.304 66.353 3.69 67.171 ;
     RECT  5.832 66.389 8.226 67.171 ;
     RECT  9.036 65.777 12.078 67.171 ;
     RECT  2.304 67.171 4.698 67.243 ;
     RECT  2.304 67.243 4.734 67.261 ;
     RECT  5.832 67.171 12.078 67.261 ;
     RECT  41.904 66.659 42.246 67.261 ;
     RECT  36.972 67.135 40.59 67.291 ;
     RECT  18.504 65.507 19.962 67.441 ;
     RECT  36.972 67.291 41.022 67.441 ;
     RECT  36.432 67.441 41.022 67.531 ;
     RECT  41.904 67.261 42.282 67.531 ;
     RECT  43.092 66.701 43.11 67.531 ;
     RECT  18.504 67.441 20.322 67.559 ;
     RECT  36.432 67.531 42.282 67.559 ;
     RECT  43.056 67.531 43.11 67.829 ;
     RECT  36.9 67.559 42.282 67.853 ;
     RECT  36.9 67.853 42.174 67.865 ;
     RECT  2.304 67.261 12.078 67.901 ;
     RECT  2.304 67.901 4.734 67.945 ;
     RECT  18.504 67.559 19.962 68.009 ;
     RECT  2.268 67.945 4.734 68.093 ;
     RECT  18.504 68.009 19.674 68.107 ;
     RECT  37.332 67.865 42.174 68.135 ;
     RECT  18.252 68.107 19.674 68.243 ;
     RECT  34.776 65.983 35.097 68.243 ;
     RECT  38.052 68.135 42.174 68.333 ;
     RECT  0.54 68.251 0.558 68.429 ;
     RECT  41.616 68.333 42.174 68.587 ;
     RECT  5.832 67.901 12.078 68.639 ;
     RECT  43.092 67.829 43.11 68.647 ;
     RECT  41.616 68.587 42.21 68.717 ;
     RECT  41.652 68.717 42.21 68.719 ;
     RECT  2.304 68.093 4.734 68.755 ;
     RECT  5.832 68.639 11.97 68.755 ;
     RECT  2.304 68.755 11.97 68.813 ;
     RECT  41.652 68.719 42.246 68.861 ;
     RECT  42.12 68.861 42.246 69.005 ;
     RECT  38.052 68.333 40.806 69.061 ;
     RECT  37.656 69.061 40.806 69.179 ;
     RECT  5.832 68.813 11.97 69.323 ;
     RECT  43.02 68.647 43.11 69.359 ;
     RECT  43.02 69.359 43.038 69.533 ;
     RECT  42.12 69.005 42.174 69.595 ;
     RECT  10.26 69.323 11.97 69.629 ;
     RECT  10.332 69.629 11.97 69.835 ;
     RECT  2.304 68.813 4.77 69.871 ;
     RECT  5.832 69.323 9.522 69.871 ;
     RECT  37.764 69.179 40.806 69.883 ;
     RECT  41.58 69.595 42.174 69.883 ;
     RECT  21.636 69.871 21.654 69.989 ;
     RECT  36.54 69.997 36.558 70.069 ;
     RECT  37.764 69.883 42.174 70.069 ;
     RECT  10.332 69.835 12.258 70.097 ;
     RECT  36.54 70.069 42.174 70.097 ;
     RECT  10.548 70.097 12.258 70.259 ;
     RECT  2.304 69.871 9.522 70.529 ;
     RECT  18.615 68.243 19.674 70.529 ;
     RECT  5.688 70.529 9.522 70.589 ;
     RECT  5.688 70.589 8.55 70.601 ;
     RECT  5.796 70.601 8.55 70.643 ;
     RECT  2.304 70.529 4.914 70.733 ;
     RECT  2.304 70.733 4.842 70.799 ;
     RECT  5.904 70.643 8.55 70.871 ;
     RECT  9.324 70.589 9.522 70.951 ;
     RECT  10.548 70.259 11.646 70.951 ;
     RECT  33.084 70.537 33.102 70.979 ;
     RECT  41.58 70.097 42.174 71.035 ;
     RECT  41.544 71.035 42.174 71.041 ;
     RECT  36.54 70.097 40.59 71.131 ;
     RECT  41.544 71.041 42.246 71.131 ;
     RECT  18.615 70.529 19.098 71.339 ;
     RECT  2.304 70.799 4.698 71.375 ;
     RECT  36.54 71.131 42.246 71.519 ;
     RECT  36.54 71.519 40.734 71.645 ;
     RECT  5.904 70.871 8.478 71.689 ;
     RECT  5.796 71.689 8.478 71.761 ;
     RECT  3.456 71.375 4.698 71.851 ;
     RECT  5.796 71.761 8.55 71.851 ;
     RECT  9.324 70.951 11.646 71.879 ;
     RECT  5.76 71.851 8.55 71.888 ;
     RECT  3.456 71.851 5.022 71.899 ;
     RECT  5.76 71.888 6.066 71.899 ;
     RECT  3.456 71.899 6.066 71.951 ;
     RECT  36.54 71.645 40.698 71.959 ;
     RECT  34.815 68.243 35.097 72.031 ;
     RECT  36.504 71.959 40.698 72.149 ;
     RECT  6.804 71.888 8.55 72.257 ;
     RECT  2.304 71.375 2.697 72.301 ;
     RECT  3.456 71.951 4.59 72.301 ;
     RECT  2.304 72.301 4.59 72.365 ;
     RECT  36.504 72.149 36.558 72.419 ;
     RECT  41.58 71.519 42.246 72.499 ;
     RECT  37.332 72.149 40.698 72.535 ;
     RECT  9.396 71.879 11.646 72.599 ;
     RECT  3.456 72.365 4.59 72.689 ;
     RECT  37.332 72.535 40.842 72.689 ;
     RECT  43.092 70.651 43.11 72.811 ;
     RECT  3.816 72.689 4.59 72.841 ;
     RECT  5.688 71.951 6.066 72.841 ;
     RECT  9.396 72.599 11.214 72.841 ;
     RECT  6.876 72.257 8.55 72.859 ;
     RECT  9.36 72.841 11.214 72.859 ;
     RECT  3.816 72.841 6.066 72.893 ;
     RECT  3.816 72.893 4.482 72.959 ;
     RECT  43.056 72.811 43.11 72.959 ;
     RECT  41.58 72.499 42.282 73.039 ;
     RECT  36.54 72.419 36.558 73.111 ;
     RECT  37.332 72.689 40.626 73.111 ;
     RECT  4.32 72.959 4.482 73.229 ;
     RECT  5.328 72.893 6.066 73.229 ;
     RECT  4.32 73.229 4.338 73.235 ;
     RECT  2.304 72.365 2.697 73.309 ;
     RECT  5.436 73.229 6.066 73.309 ;
     RECT  6.876 72.859 11.214 73.309 ;
     RECT  43.056 72.959 43.074 73.337 ;
     RECT  18.615 71.339 18.897 73.345 ;
     RECT  36.54 73.111 40.626 73.471 ;
     RECT  36.54 73.471 40.734 73.651 ;
     RECT  41.58 73.039 42.318 73.651 ;
     RECT  2.304 73.309 3.078 73.741 ;
     RECT  36.108 73.651 42.318 73.769 ;
     RECT  5.436 73.309 11.214 73.877 ;
     RECT  5.436 73.877 9.666 74.005 ;
     RECT  5.4 74.005 9.666 74.011 ;
     RECT  36.54 73.769 42.318 74.039 ;
     RECT  5.112 74.011 9.666 74.093 ;
     RECT  4.14 73.921 4.158 74.191 ;
     RECT  37.044 74.039 42.318 74.381 ;
     RECT  4.14 74.191 4.41 74.425 ;
     RECT  2.304 73.741 3.114 74.461 ;
     RECT  17.676 71.149 17.694 74.489 ;
     RECT  34.776 72.031 35.097 74.489 ;
     RECT  43.092 73.963 43.11 74.489 ;
     RECT  2.304 74.461 3.186 74.551 ;
     RECT  5.292 74.093 9.666 74.651 ;
     RECT  5.652 74.651 9.666 74.683 ;
     RECT  10.62 73.877 11.214 74.683 ;
     RECT  5.652 74.683 11.214 74.731 ;
     RECT  31.932 74.353 31.95 74.759 ;
     RECT  41.58 74.381 42.318 74.765 ;
     RECT  2.304 74.551 3.258 74.821 ;
     RECT  4.104 74.425 4.41 74.821 ;
     RECT  2.304 74.821 4.41 74.849 ;
     RECT  20.016 72.193 20.034 74.849 ;
     RECT  3.564 74.849 4.41 74.921 ;
     RECT  37.044 74.381 40.77 74.929 ;
     RECT  36.18 74.857 36.198 75.001 ;
     RECT  37.008 74.929 40.77 75.001 ;
     RECT  3.744 74.921 4.41 75.091 ;
     RECT  3.744 75.091 4.662 75.119 ;
     RECT  5.652 74.731 11.682 75.119 ;
     RECT  36.108 75.001 40.77 75.127 ;
     RECT  11.412 75.119 11.682 75.155 ;
     RECT  5.652 75.119 10.638 75.293 ;
     RECT  10.62 75.293 10.638 75.389 ;
     RECT  4.5 75.119 4.662 75.505 ;
     RECT  33.624 74.893 33.642 75.533 ;
     RECT  5.652 75.293 9.486 75.569 ;
     RECT  41.58 74.765 42.174 75.631 ;
     RECT  11.412 75.155 11.43 75.659 ;
     RECT  34.815 74.489 35.097 75.667 ;
     RECT  2.304 74.849 2.697 75.691 ;
     RECT  3.744 75.119 3.762 75.691 ;
     RECT  5.652 75.569 9.162 75.691 ;
     RECT  4.5 75.505 4.698 75.787 ;
     RECT  5.508 75.691 9.162 75.787 ;
     RECT  35.928 75.127 40.77 75.811 ;
     RECT  41.58 75.631 42.21 75.811 ;
     RECT  4.5 75.787 9.162 75.839 ;
     RECT  9.072 75.839 9.162 76.013 ;
     RECT  18.504 73.345 18.897 76.199 ;
     RECT  9.144 76.013 9.162 76.309 ;
     RECT  9.144 76.309 9.882 76.349 ;
     RECT  35.928 75.811 42.21 76.379 ;
     RECT  43.092 75.397 43.11 76.445 ;
     RECT  2.304 75.691 3.762 76.459 ;
     RECT  4.5 75.839 8.298 76.459 ;
     RECT  9.144 76.349 9.486 76.469 ;
     RECT  10.656 76.081 10.674 76.477 ;
     RECT  0.144 76.363 0.162 76.493 ;
     RECT  18.615 76.199 18.897 76.549 ;
     RECT  31.356 76.207 31.374 76.649 ;
     RECT  16.524 75.163 16.542 76.739 ;
     RECT  2.304 76.459 8.298 76.883 ;
     RECT  5.58 76.883 8.298 76.885 ;
     RECT  5.58 76.885 8.442 76.925 ;
     RECT  5.58 76.925 8.097 77.009 ;
     RECT  35.928 76.379 41.058 77.009 ;
     RECT  41.796 76.379 42.21 77.083 ;
     RECT  9.396 76.469 9.486 77.089 ;
     RECT  10.656 76.477 10.782 77.161 ;
     RECT  5.904 77.009 8.097 77.213 ;
     RECT  36.036 77.009 41.058 77.279 ;
     RECT  36.036 77.279 40.77 77.315 ;
     RECT  9.396 77.089 9.738 77.431 ;
     RECT  10.62 77.161 10.782 77.431 ;
     RECT  9.396 77.431 9.81 77.521 ;
     RECT  41.796 77.083 42.246 77.563 ;
     RECT  8.928 77.521 9.81 77.657 ;
     RECT  5.94 77.213 8.097 77.701 ;
     RECT  8.928 77.657 9.594 77.701 ;
     RECT  10.584 77.431 10.782 77.701 ;
     RECT  5.94 77.701 9.594 77.729 ;
     RECT  41.58 77.563 42.246 77.729 ;
     RECT  5.94 77.729 6.39 77.741 ;
     RECT  2.304 76.883 4.698 77.819 ;
     RECT  7.236 77.729 9.594 77.819 ;
     RECT  10.584 77.701 10.854 77.891 ;
     RECT  43.056 77.899 43.074 77.947 ;
     RECT  34.776 75.667 35.097 77.963 ;
     RECT  3.816 77.819 4.698 77.971 ;
     RECT  7.416 77.819 9.594 77.981 ;
     RECT  43.056 77.947 43.11 77.999 ;
     RECT  2.304 77.819 2.862 78.089 ;
     RECT  11.484 77.935 11.574 78.089 ;
     RECT  18.615 76.549 19.422 78.089 ;
     RECT  21.384 77.971 21.402 78.089 ;
     RECT  42.192 77.729 42.246 78.125 ;
     RECT  36.036 77.315 40.698 78.169 ;
     RECT  7.416 77.981 8.478 78.233 ;
     RECT  5.94 77.741 6.354 78.331 ;
     RECT  42.228 78.125 42.246 78.331 ;
     RECT  43.056 77.999 43.074 78.509 ;
     RECT  3.816 77.971 4.77 78.511 ;
     RECT  5.544 78.331 6.354 78.511 ;
     RECT  29.415 48.029 29.697 78.511 ;
     RECT  17.1 77.971 17.118 78.629 ;
     RECT  19.764 78.511 19.782 78.629 ;
     RECT  7.815 78.233 8.478 78.709 ;
     RECT  9.252 77.981 9.594 78.709 ;
     RECT  3.816 78.511 6.354 78.781 ;
     RECT  10.584 77.891 10.602 78.781 ;
     RECT  29.415 78.511 29.754 78.809 ;
     RECT  10.584 78.781 11.142 78.899 ;
     RECT  7.815 78.709 9.594 78.907 ;
     RECT  2.304 78.089 2.754 78.979 ;
     RECT  3.492 78.781 6.354 78.979 ;
     RECT  11.052 78.899 11.142 79.043 ;
     RECT  7.815 78.907 9.882 79.051 ;
     RECT  42.228 78.331 42.282 79.051 ;
     RECT  2.304 78.979 6.354 79.085 ;
     RECT  36.036 78.169 41.13 79.133 ;
     RECT  7.416 79.051 9.882 79.141 ;
     RECT  7.128 79.141 9.882 79.169 ;
     RECT  36.036 79.133 41.058 79.169 ;
     RECT  42.192 79.051 42.282 79.277 ;
     RECT  36.324 79.169 41.058 79.439 ;
     RECT  42.228 79.277 42.282 79.517 ;
     RECT  7.128 79.169 9.846 79.555 ;
     RECT  43.092 79.003 43.11 79.555 ;
     RECT  2.376 79.085 6.354 79.591 ;
     RECT  7.092 79.555 9.846 79.591 ;
     RECT  2.376 79.591 9.846 79.709 ;
     RECT  0.108 78.637 0.126 79.717 ;
     RECT  11.232 79.519 11.25 79.861 ;
     RECT  2.376 79.709 4.734 79.867 ;
     RECT  2.304 79.867 4.734 79.979 ;
     RECT  14.868 78.979 14.886 79.979 ;
     RECT  36.54 79.439 41.058 79.979 ;
     RECT  0.036 79.717 0.126 79.987 ;
     RECT  34.815 77.963 35.097 79.987 ;
     RECT  42.228 79.517 42.246 80.011 ;
     RECT  5.544 79.709 9.846 80.257 ;
     RECT  10.728 79.861 11.25 80.257 ;
     RECT  5.544 80.257 11.25 80.365 ;
     RECT  34.776 79.987 35.097 80.485 ;
     RECT  24.015 52.448 24.297 80.491 ;
     RECT  5.544 80.365 11.934 80.519 ;
     RECT  34.704 80.485 35.097 80.525 ;
     RECT  23.904 80.491 24.297 80.528 ;
     RECT  42.156 80.011 42.246 80.573 ;
     RECT  36.684 79.979 41.058 80.599 ;
     RECT  42.156 80.573 42.174 80.671 ;
     RECT  36.684 80.599 41.094 80.833 ;
     RECT  42.12 80.671 42.174 80.833 ;
     RECT  5.544 80.519 10.854 80.861 ;
     RECT  2.304 79.979 4.518 80.869 ;
     RECT  0.036 79.987 0.558 80.923 ;
     RECT  2.304 80.869 4.59 80.941 ;
     RECT  5.544 80.861 8.298 80.941 ;
     RECT  43.02 79.555 43.11 80.957 ;
     RECT  0.036 80.923 1.17 81.053 ;
     RECT  9.144 80.861 10.854 81.059 ;
     RECT  43.02 80.957 43.038 81.101 ;
     RECT  34.815 80.525 35.097 81.103 ;
     RECT  18.615 78.089 18.897 81.139 ;
     RECT  11.88 80.519 11.934 81.211 ;
     RECT  36.684 80.833 42.174 81.211 ;
     RECT  11.88 81.211 11.97 81.329 ;
     RECT  36.432 81.211 42.174 81.337 ;
     RECT  9.216 81.059 10.854 81.365 ;
     RECT  18.615 81.139 19.35 81.409 ;
     RECT  0.036 81.053 0.558 81.437 ;
     RECT  9.504 81.365 10.854 81.509 ;
     RECT  36.36 81.337 42.174 81.571 ;
     RECT  18.324 81.409 19.35 81.599 ;
     RECT  18.615 81.599 19.35 81.643 ;
     RECT  2.268 80.941 8.298 81.715 ;
     RECT  34.815 81.103 35.406 81.715 ;
     RECT  36.18 81.571 42.174 81.715 ;
     RECT  30.852 81.607 30.87 81.743 ;
     RECT  11.88 81.329 11.934 81.913 ;
     RECT  1.692 81.715 8.298 82.123 ;
     RECT  1.692 82.123 8.586 82.183 ;
     RECT  11.808 81.913 11.934 82.183 ;
     RECT  9.504 81.509 9.846 82.255 ;
     RECT  34.815 81.715 42.174 82.291 ;
     RECT  1.692 82.183 8.73 82.409 ;
     RECT  9.504 82.255 9.882 82.409 ;
     RECT  11.628 82.183 11.934 82.409 ;
     RECT  34.776 82.291 42.174 82.409 ;
     RECT  1.692 82.409 8.37 82.417 ;
     RECT  1.404 82.417 8.37 82.481 ;
     RECT  43.056 81.691 43.11 82.493 ;
     RECT  9.504 82.409 9.846 82.525 ;
     RECT  36 82.409 42.174 82.561 ;
     RECT  11.772 82.409 11.934 82.651 ;
     RECT  9.468 82.525 9.846 82.723 ;
     RECT  36 82.561 42.21 82.733 ;
     RECT  36 82.733 42.174 82.787 ;
     RECT  10.764 81.509 10.854 82.939 ;
     RECT  11.772 82.651 11.97 82.949 ;
     RECT  0.036 81.437 0.234 83.219 ;
     RECT  14.796 83.101 14.814 83.219 ;
     RECT  1.404 82.481 8.298 83.227 ;
     RECT  9.108 82.723 9.846 83.227 ;
     RECT  36.072 82.787 42.174 83.261 ;
     RECT  1.404 83.227 9.846 83.263 ;
     RECT  10.728 82.939 11.034 83.263 ;
     RECT  1.404 83.263 11.034 83.299 ;
     RECT  11.772 82.949 11.934 83.299 ;
     RECT  18.615 81.643 20.07 83.371 ;
     RECT  0.108 83.219 0.234 83.453 ;
     RECT  18.216 83.371 20.07 83.489 ;
     RECT  34.776 82.409 35.097 83.533 ;
     RECT  36.072 83.261 41.31 83.533 ;
     RECT  42.084 83.261 42.174 83.533 ;
     RECT  42.084 83.533 42.246 83.569 ;
     RECT  43.056 82.493 43.074 83.645 ;
     RECT  1.404 83.299 11.934 83.669 ;
     RECT  9.324 83.669 11.934 83.693 ;
     RECT  1.404 83.669 8.586 83.759 ;
     RECT  9.324 83.693 9.594 83.759 ;
     RECT  10.548 83.693 11.934 83.759 ;
     RECT  34.776 83.533 41.31 83.759 ;
     RECT  5.58 83.759 8.586 83.795 ;
     RECT  9.54 83.759 9.594 83.795 ;
     RECT  5.58 83.795 5.598 83.831 ;
     RECT  42.084 83.569 42.282 83.933 ;
     RECT  34.776 83.759 35.097 83.939 ;
     RECT  0.18 83.453 0.234 83.981 ;
     RECT  13.215 52.448 13.497 83.987 ;
     RECT  18.615 83.489 18.897 83.987 ;
     RECT  24.015 80.528 24.297 83.987 ;
     RECT  29.415 78.809 29.697 83.987 ;
     RECT  34.815 83.939 35.097 83.987 ;
     RECT  6.516 83.795 6.75 84.029 ;
     RECT  7.668 83.795 8.586 84.029 ;
     RECT  10.836 83.759 10.854 84.029 ;
     RECT  42.156 83.933 42.282 84.029 ;
     RECT  1.404 83.759 4.734 84.065 ;
     RECT  6.516 84.029 6.534 84.065 ;
     RECT  7.815 84.029 8.586 84.065 ;
     RECT  1.404 84.065 4.626 84.101 ;
     RECT  36.684 83.759 41.31 84.137 ;
     RECT  7.815 84.065 8.154 84.173 ;
     RECT  42.192 84.029 42.282 84.173 ;
     RECT  1.404 84.101 4.014 84.209 ;
     RECT  9.54 83.795 9.558 84.209 ;
     RECT  7.815 84.173 7.905 84.257 ;
     RECT  13.215 83.987 13.305 84.257 ;
     RECT  18.615 83.987 18.705 84.257 ;
     RECT  24.015 83.987 24.105 84.257 ;
     RECT  29.415 83.987 29.505 84.257 ;
     RECT  34.815 83.987 34.905 84.257 ;
     RECT  36.72 84.137 41.31 84.299 ;
     RECT  42.228 84.173 42.282 84.317 ;
     RECT  42.228 84.317 42.246 84.413 ;
     RECT  1.404 84.209 3.834 84.797 ;
     RECT  1.404 84.797 3.402 85.133 ;
     RECT  37.044 84.299 41.31 85.325 ;
     RECT  1.404 85.133 1.422 85.469 ;
     RECT  37.044 85.325 38.43 85.469 ;
     RECT  39.204 85.325 41.31 85.565 ;
     RECT  37.044 85.469 38.25 85.709 ;
     RECT  2.34 85.133 3.402 85.805 ;
     RECT  39.204 85.565 39.222 85.853 ;
     RECT  40.572 85.565 41.31 85.949 ;
     RECT  3.06 85.805 3.402 85.997 ;
     RECT  41.292 85.949 41.31 86.093 ;
     RECT  3.384 85.997 3.402 86.141 ;
     RECT  37.044 85.709 37.062 86.237 ;
     RECT  0.216 83.981 0.234 86.333 ;
     RECT  38.232 85.709 38.25 86.333 ;
    LAYER M4 ;
     RECT  0.06 0.096 0.245 86.328 ;
     RECT  0.245 0.096 0.908 86.136 ;
     RECT  0.908 0.048 0.995 86.136 ;
     RECT  0.995 0.096 2.585 86.136 ;
     RECT  2.585 0.096 2.677 84.792 ;
     RECT  2.677 0.048 2.704 84.792 ;
     RECT  2.704 7.344 2.765 8.856 ;
     RECT  2.704 10.464 2.765 16.296 ;
     RECT  2.704 18 2.765 20.184 ;
     RECT  2.704 21.504 2.765 23.88 ;
     RECT  2.704 25.536 2.765 28.296 ;
     RECT  2.704 36 2.765 36.792 ;
     RECT  2.704 39.072 2.765 41.64 ;
     RECT  2.704 44.112 2.765 45 ;
     RECT  2.704 51.36 2.765 51.384 ;
     RECT  2.704 56.784 2.765 57.96 ;
     RECT  2.704 58.944 2.765 63.384 ;
     RECT  2.704 74.16 2.765 74.664 ;
     RECT  2.704 77.856 2.765 84.792 ;
     RECT  2.704 2.784 2.801 5.832 ;
     RECT  2.765 10.464 2.801 15.816 ;
     RECT  2.765 19.296 2.801 20.184 ;
     RECT  2.765 25.536 2.801 27.96 ;
     RECT  2.704 32.496 2.801 32.52 ;
     RECT  2.704 43.104 2.801 43.128 ;
     RECT  2.765 74.64 2.801 74.664 ;
     RECT  2.801 2.784 2.819 5.784 ;
     RECT  2.801 12.048 2.837 13.608 ;
     RECT  2.765 39.792 2.837 41.64 ;
     RECT  2.704 53.904 2.837 55.464 ;
     RECT  2.765 58.944 2.837 63.24 ;
     RECT  2.704 66.24 2.837 66.264 ;
     RECT  2.704 68.064 2.837 71.16 ;
     RECT  2.704 0.048 2.873 1.8 ;
     RECT  2.819 2.784 2.873 5.496 ;
     RECT  2.801 14.736 2.873 15.816 ;
     RECT  2.801 19.296 2.873 19.32 ;
     RECT  2.837 53.904 2.873 55.272 ;
     RECT  2.873 1.104 2.909 1.8 ;
     RECT  2.765 21.504 2.909 22.056 ;
     RECT  2.704 34.08 2.909 34.68 ;
     RECT  2.765 79.728 2.945 84.792 ;
     RECT  2.765 44.976 2.981 45 ;
     RECT  2.873 2.784 3.053 4.968 ;
     RECT  2.909 1.44 3.089 1.8 ;
     RECT  2.837 12.048 3.089 13.08 ;
     RECT  2.909 21.504 3.089 21.528 ;
     RECT  2.801 25.536 3.089 26.136 ;
     RECT  2.765 36.336 3.089 36.792 ;
     RECT  2.837 39.792 3.089 40.44 ;
     RECT  2.704 45.984 3.089 47.16 ;
     RECT  2.873 53.904 3.089 53.928 ;
     RECT  2.765 56.784 3.089 57.144 ;
     RECT  2.704 65.232 3.089 65.256 ;
     RECT  2.837 69.264 3.089 71.16 ;
     RECT  2.704 75.696 3.089 76.872 ;
     RECT  2.585 85.968 3.089 86.136 ;
     RECT  3.053 2.832 3.125 4.968 ;
     RECT  2.765 7.632 3.125 8.856 ;
     RECT  2.873 15.504 3.125 15.816 ;
     RECT  2.837 59.808 3.125 63.24 ;
     RECT  3.089 75.792 3.125 76.872 ;
     RECT  2.704 48.96 3.161 49.896 ;
     RECT  3.125 4.944 3.197 4.968 ;
     RECT  3.125 8.832 3.197 8.856 ;
     RECT  3.089 12.48 3.197 13.08 ;
     RECT  2.909 34.08 3.197 34.104 ;
     RECT  3.125 59.808 3.197 61.56 ;
     RECT  2.765 18 3.203 18.264 ;
     RECT  3.161 49.008 3.233 49.896 ;
     RECT  2.873 55.248 3.233 55.272 ;
     RECT  3.089 57.12 3.233 57.144 ;
     RECT  3.089 70.08 3.233 71.16 ;
     RECT  2.945 80.688 3.233 84.792 ;
     RECT  3.125 2.832 3.299 3.384 ;
     RECT  2.801 10.464 3.299 10.488 ;
     RECT  3.125 15.504 3.299 15.528 ;
     RECT  2.837 41.616 3.299 41.64 ;
     RECT  3.089 86.112 3.413 86.136 ;
     RECT  3.089 1.44 3.449 1.464 ;
     RECT  3.125 62.736 3.491 63.24 ;
     RECT  2.837 68.064 3.491 68.088 ;
     RECT  3.233 83.184 3.521 84.792 ;
     RECT  3.233 80.688 3.557 82.2 ;
     RECT  3.197 60.672 3.629 61.56 ;
     RECT  2.765 23.52 3.769 23.88 ;
     RECT  2.704 30.432 3.841 31.368 ;
     RECT  3.557 82.176 3.845 82.2 ;
     RECT  3.521 84.768 3.845 84.792 ;
     RECT  2.704 72.336 3.875 72.36 ;
     RECT  3.788 78.096 3.875 78.12 ;
     RECT  3.557 80.688 3.875 80.712 ;
     RECT  3.769 22.752 3.913 23.88 ;
     RECT  3.197 12.528 3.923 12.552 ;
     RECT  3.203 18.24 3.923 18.264 ;
     RECT  3.841 30.288 3.949 31.368 ;
     RECT  3.884 40.992 3.971 41.016 ;
     RECT  3.913 58.704 3.997 58.728 ;
     RECT  3.089 26.112 4.021 26.136 ;
     RECT  3.089 36.768 4.021 36.792 ;
     RECT  3.125 7.632 4.097 7.656 ;
     RECT  3.125 75.792 4.097 76.488 ;
     RECT  3.921 20.784 4.165 20.808 ;
     RECT  4.129 14.352 4.213 14.808 ;
     RECT  4.165 20.784 4.213 20.856 ;
     RECT  4.021 26.112 4.229 26.76 ;
     RECT  2.801 27.936 4.229 27.96 ;
     RECT  4.021 36.768 4.229 37.08 ;
     RECT  4.213 14.352 4.259 14.376 ;
     RECT  3.299 2.832 4.261 2.856 ;
     RECT  3.913 22.704 4.261 23.88 ;
     RECT  4.229 26.112 4.261 27.96 ;
     RECT  3.913 33.648 4.261 33.672 ;
     RECT  4.229 36.768 4.261 37.608 ;
     RECT  3.521 83.184 4.261 83.688 ;
     RECT  4.261 2.832 4.268 3.768 ;
     RECT  3.089 46.752 4.268 47.16 ;
     RECT  3.233 49.872 4.268 49.896 ;
     RECT  3.877 52.464 4.268 52.488 ;
     RECT  3.629 60.672 4.268 60.696 ;
     RECT  4.268 46.752 4.273 47.832 ;
     RECT  4.268 52.464 4.273 52.872 ;
     RECT  4.193 9.648 4.277 9.672 ;
     RECT  4.22 74.304 4.307 74.328 ;
     RECT  4.213 20.736 4.309 20.856 ;
     RECT  4.261 22.704 4.309 24.504 ;
     RECT  3.233 70.08 4.309 70.296 ;
     RECT  4.261 26.112 4.313 28.488 ;
     RECT  4.261 36.48 4.313 37.608 ;
     RECT  4.268 49.68 4.313 49.896 ;
     RECT  4.165 16.416 4.316 16.44 ;
     RECT  4.229 44.448 4.316 44.472 ;
     RECT  4.268 7.296 4.345 7.32 ;
     RECT  4.273 51.888 4.345 52.872 ;
     RECT  4.261 33.6 4.353 33.672 ;
     RECT  4.268 2.256 4.355 3.768 ;
     RECT  4.345 6.816 4.355 7.32 ;
     RECT  4.268 12.384 4.355 12.408 ;
     RECT  4.273 45.84 4.355 47.832 ;
     RECT  4.313 49.68 4.355 49.704 ;
     RECT  4.268 60.192 4.355 60.696 ;
     RECT  4.268 63.792 4.355 63.816 ;
     RECT  3.949 30.288 4.357 31.416 ;
     RECT  4.345 51.888 4.357 53.592 ;
     RECT  4.309 22.416 4.381 24.504 ;
     RECT  4.313 27.936 4.385 28.488 ;
     RECT  4.316 15.84 4.403 16.44 ;
     RECT  4.316 43.824 4.403 44.472 ;
     RECT  4.309 20.736 4.405 21.144 ;
     RECT  4.381 22.416 4.405 24.648 ;
     RECT  4.313 26.112 4.405 26.856 ;
     RECT  4.355 6.816 4.429 6.84 ;
     RECT  4.357 52.368 4.429 53.592 ;
     RECT  4.345 62.64 4.429 62.664 ;
     RECT  4.357 29.952 4.453 31.416 ;
     RECT  4.344 38.16 4.453 38.184 ;
     RECT  4.097 75.792 4.453 76.2 ;
     RECT  4.355 45.84 4.457 47.256 ;
     RECT  4.353 65.328 4.481 65.352 ;
     RECT  4.453 38.16 4.489 38.664 ;
     RECT  4.309 57.6 4.489 57.624 ;
     RECT  4.405 11.04 4.492 11.064 ;
     RECT  4.457 45.84 4.493 45.96 ;
     RECT  4.412 8.448 4.499 8.472 ;
     RECT  4.457 47.232 4.499 47.256 ;
     RECT  4.481 64.368 4.499 65.352 ;
     RECT  4.405 20.736 4.501 26.856 ;
     RECT  4.353 32.928 4.501 33.672 ;
     RECT  4.316 34.896 4.501 34.92 ;
     RECT  3.089 39.792 4.501 39.816 ;
     RECT  4.417 55.872 4.501 55.896 ;
     RECT  4.309 70.08 4.501 70.728 ;
     RECT  4.501 32.928 4.525 34.92 ;
     RECT  4.313 36.48 4.525 37.08 ;
     RECT  4.453 75.12 4.54 76.2 ;
     RECT  4.355 2.832 4.547 3.768 ;
     RECT  4.489 38.16 4.547 38.76 ;
     RECT  4.46 48.912 4.547 49.512 ;
     RECT  4.213 17.616 4.565 17.64 ;
     RECT  4.499 64.368 4.565 64.392 ;
     RECT  4.412 79.632 4.565 79.656 ;
     RECT  4.261 82.656 4.565 83.688 ;
     RECT  4.403 15.984 4.588 16.44 ;
     RECT  4.429 52.368 4.588 53.016 ;
     RECT  4.501 55.056 4.588 55.08 ;
     RECT  4.501 65.376 4.588 66.168 ;
     RECT  4.501 67.44 4.588 68.28 ;
     RECT  4.385 28.272 4.597 28.488 ;
     RECT  4.453 29.952 4.597 31.656 ;
     RECT  4.501 13.536 4.601 14.232 ;
     RECT  4.453 5.088 4.604 5.112 ;
     RECT  4.547 38.208 4.604 38.76 ;
     RECT  4.501 39.792 4.604 40.008 ;
     RECT  4.501 42.672 4.625 42.696 ;
     RECT  4.561 50.736 4.645 50.76 ;
     RECT  4.604 4.848 4.652 5.112 ;
     RECT  4.625 42.672 4.652 42.792 ;
     RECT  4.501 69.36 4.652 70.776 ;
     RECT  4.565 83.184 4.661 83.688 ;
     RECT  4.604 38.208 4.691 40.008 ;
     RECT  4.588 67.44 4.705 67.8 ;
     RECT  4.645 77.568 4.732 77.592 ;
     RECT  4.652 6.672 4.739 6.696 ;
     RECT  4.652 42.672 4.739 43.176 ;
     RECT  4.652 69.36 4.739 71.496 ;
     RECT  4.489 57.024 4.741 57.624 ;
     RECT  4.661 83.184 4.745 83.832 ;
     RECT  4.403 44.256 4.748 44.472 ;
     RECT  4.493 45.84 4.748 45.864 ;
     RECT  4.739 69.36 4.787 70.776 ;
     RECT  4.705 67.248 4.789 67.8 ;
     RECT  4.748 42.192 4.835 42.216 ;
     RECT  4.748 44.256 4.835 45.864 ;
     RECT  4.652 4.848 4.844 5.352 ;
     RECT  4.54 75.552 4.883 76.2 ;
     RECT  4.601 14.208 4.889 14.232 ;
     RECT  4.787 70.272 4.917 70.776 ;
     RECT  4.917 70.272 4.925 70.728 ;
     RECT  4.844 4.848 4.931 5.928 ;
     RECT  4.501 20.256 4.931 26.856 ;
     RECT  4.691 39.216 4.931 40.008 ;
     RECT  4.355 60.672 4.931 60.696 ;
     RECT  4.588 65.376 4.931 65.4 ;
     RECT  4.597 28.272 4.993 31.656 ;
     RECT  4.525 32.928 4.993 37.08 ;
     RECT  4.588 52.416 5.027 53.016 ;
     RECT  4.931 4.848 5.029 5.112 ;
     RECT  4.988 48.432 5.075 48.456 ;
     RECT  4.547 49.488 5.075 49.512 ;
     RECT  4.844 66.48 5.075 66.504 ;
     RECT  4.883 75.696 5.077 76.2 ;
     RECT  4.245 72.864 5.101 73.224 ;
     RECT  5.029 3.936 5.123 5.112 ;
     RECT  4.741 54.288 5.123 54.84 ;
     RECT  4.789 67.728 5.133 67.8 ;
     RECT  4.588 15.984 5.141 16.008 ;
     RECT  5.057 58.704 5.141 58.728 ;
     RECT  5.057 80.976 5.141 81 ;
     RECT  5.123 54.288 5.149 54.744 ;
     RECT  5.077 68.784 5.164 68.808 ;
     RECT  5.077 78.528 5.164 79.224 ;
     RECT  5.123 4.368 5.177 5.112 ;
     RECT  5.027 52.464 5.213 53.016 ;
     RECT  4.835 44.256 5.267 44.28 ;
     RECT  4.931 20.256 5.269 21.048 ;
     RECT  4.837 19.104 5.281 19.128 ;
     RECT  5.269 20.16 5.281 21.048 ;
     RECT  4.741 56.448 5.285 57.624 ;
     RECT  4.993 28.272 5.353 37.08 ;
     RECT  5.281 18.672 5.356 21.048 ;
     RECT  5.077 61.536 5.357 61.56 ;
     RECT  5.317 81.984 5.389 82.008 ;
     RECT  5.101 72.864 5.425 74.088 ;
     RECT  4.835 45.552 5.501 45.864 ;
     RECT  5.356 18.672 5.507 19.416 ;
     RECT  5.285 56.976 5.507 57.624 ;
     RECT  4.931 22.752 5.509 26.856 ;
     RECT  5.353 27.984 5.509 37.08 ;
     RECT  5.501 45.6 5.516 45.864 ;
     RECT  5.509 22.752 5.555 37.08 ;
     RECT  5.497 10.8 5.581 10.824 ;
     RECT  5.101 17.088 5.603 17.112 ;
     RECT  5.516 45.6 5.603 46.104 ;
     RECT  5.497 55.872 5.603 55.896 ;
     RECT  5.389 81.6 5.605 82.008 ;
     RECT  4.745 83.184 5.605 83.688 ;
     RECT  4.844 63.216 5.641 63.24 ;
     RECT  5.533 8.448 5.651 8.472 ;
     RECT  5.564 49.152 5.651 49.176 ;
     RECT  5.425 72.864 5.677 74.568 ;
     RECT  5.423 43.776 5.699 43.8 ;
     RECT  5.612 80.256 5.699 80.28 ;
     RECT  5.641 62.64 5.701 63.24 ;
     RECT  4.931 39.36 5.708 40.008 ;
     RECT  5.677 71.904 5.721 74.568 ;
     RECT  5.555 22.752 5.74 24.936 ;
     RECT  5.701 62.64 5.789 63.288 ;
     RECT  5.177 4.368 5.795 4.968 ;
     RECT  5.708 39.36 5.795 41.256 ;
     RECT  5.708 47.04 5.795 47.064 ;
     RECT  5.708 64.368 5.795 64.392 ;
     RECT  5.741 54.144 5.825 54.168 ;
     RECT  4.925 70.272 5.836 70.68 ;
     RECT  5.605 9.936 5.852 10.056 ;
     RECT  5.795 4.944 5.897 4.968 ;
     RECT  5.857 68.88 5.9 68.952 ;
     RECT  5.077 75.696 5.929 77.208 ;
     RECT  5.852 9.072 5.939 10.056 ;
     RECT  5.852 12.912 5.939 12.936 ;
     RECT  5.795 39.36 5.939 40.824 ;
     RECT  5.133 67.728 5.941 67.752 ;
     RECT  5.893 43.152 5.948 43.176 ;
     RECT  5.939 39.888 5.987 40.824 ;
     RECT  5.948 42.576 5.987 43.176 ;
     RECT  4.691 38.208 6.001 38.232 ;
     RECT  5.965 59.28 6.001 59.304 ;
     RECT  5.555 25.968 6.035 37.08 ;
     RECT  5.987 42.576 6.035 42.6 ;
     RECT  5.948 50.4 6.035 50.424 ;
     RECT  5.852 11.808 6.037 11.832 ;
     RECT  5.836 70.656 6.037 70.68 ;
     RECT  5.721 71.712 6.037 74.568 ;
     RECT  5.507 19.344 6.049 19.368 ;
     RECT  5.941 53.04 6.049 53.64 ;
     RECT  6.037 14.064 6.073 14.088 ;
     RECT  5.987 39.888 6.083 39.912 ;
     RECT  5.9 68.88 6.083 69.672 ;
     RECT  6.044 48.384 6.085 48.408 ;
     RECT  6.037 70.656 6.101 74.568 ;
     RECT  5.941 67.248 6.113 67.752 ;
     RECT  6.037 11.376 6.121 11.832 ;
     RECT  6.037 13.008 6.124 13.032 ;
     RECT  6.073 14.064 6.124 14.232 ;
     RECT  6.044 17.616 6.131 17.64 ;
     RECT  6.085 47.904 6.131 48.408 ;
     RECT  5.929 75.696 6.14 77.736 ;
     RECT  6.073 64.944 6.157 64.968 ;
     RECT  6.001 38.208 6.179 38.76 ;
     RECT  5.605 81.6 6.179 83.688 ;
     RECT  6.14 6.816 6.227 6.84 ;
     RECT  6.035 26.352 6.227 37.08 ;
     RECT  6.179 38.208 6.227 38.376 ;
     RECT  6.131 47.904 6.227 47.928 ;
     RECT  6.14 75.696 6.227 77.784 ;
     RECT  6.14 79.2 6.227 79.224 ;
     RECT  6.001 59.28 6.229 59.832 ;
     RECT  6.181 3.936 6.265 3.96 ;
     RECT  6.227 27.888 6.277 37.08 ;
     RECT  6.227 38.208 6.277 38.232 ;
     RECT  6.101 70.656 6.277 74.664 ;
     RECT  6.227 75.696 6.277 77.736 ;
     RECT  6.277 27.888 6.293 38.232 ;
     RECT  6.121 11.424 6.325 11.832 ;
     RECT  5.356 21.024 6.325 21.048 ;
     RECT  5.74 22.752 6.325 22.776 ;
     RECT  6.293 29.376 6.371 38.232 ;
     RECT  5.603 45.6 6.373 45.624 ;
     RECT  6.081 55.824 6.38 55.848 ;
     RECT  6.113 67.584 6.383 67.752 ;
     RECT  6.083 68.88 6.383 68.952 ;
     RECT  6.325 11.424 6.409 11.976 ;
     RECT  6.409 11.952 6.419 11.976 ;
     RECT  5.939 10.032 6.437 10.056 ;
     RECT  5.74 23.856 6.541 24.936 ;
     RECT  6.181 62.112 6.545 62.328 ;
     RECT  6.545 62.304 6.563 62.328 ;
     RECT  6.383 65.376 6.563 65.4 ;
     RECT  2.873 0.048 6.565 0.072 ;
     RECT  6.325 22.704 6.577 22.776 ;
     RECT  6.421 58.416 6.581 58.44 ;
     RECT  6.277 70.656 6.617 77.736 ;
     RECT  6.572 18.192 6.659 18.216 ;
     RECT  6.371 29.76 6.659 38.232 ;
     RECT  6.38 51.792 6.659 51.816 ;
     RECT  6.617 70.656 6.659 76.152 ;
     RECT  6.577 22.176 6.709 22.776 ;
     RECT  6.541 23.856 6.709 25.224 ;
     RECT  6.659 29.76 6.725 37.128 ;
     RECT  6.709 22.176 6.755 25.224 ;
     RECT  6.613 15.312 6.761 15.336 ;
     RECT  6.613 20.016 6.761 20.04 ;
     RECT  4.547 2.832 6.793 2.856 ;
     RECT  6.049 53.568 6.829 53.64 ;
     RECT  6.179 81.648 6.829 83.688 ;
     RECT  6.659 70.656 6.86 76.056 ;
     RECT  6.757 44.352 6.901 44.376 ;
     RECT  6.812 5.04 7.004 5.064 ;
     RECT  6.38 55.44 7.009 55.848 ;
     RECT  6.997 49.2 7.045 49.224 ;
     RECT  6.829 53.568 7.093 53.928 ;
     RECT  6.124 14.208 7.117 14.232 ;
     RECT  6.325 21.024 7.141 21.096 ;
     RECT  7.009 55.44 7.141 55.896 ;
     RECT  6.617 77.136 7.196 77.736 ;
     RECT  6.829 81.648 7.196 83.736 ;
     RECT  6.383 67.584 7.244 68.952 ;
     RECT  6.86 70.128 7.244 76.056 ;
     RECT  6.793 2.832 7.261 3.24 ;
     RECT  6.227 26.352 7.285 26.856 ;
     RECT  7.285 40.416 7.297 40.44 ;
     RECT  7.093 53.568 7.333 54.072 ;
     RECT  7.141 55.296 7.333 55.896 ;
     RECT  7.117 13.776 7.369 14.232 ;
     RECT  6.755 22.464 7.369 25.224 ;
     RECT  7.285 26.208 7.369 26.856 ;
     RECT  7.369 22.464 7.429 26.856 ;
     RECT  6.293 27.888 7.429 28.152 ;
     RECT  7.429 22.464 7.436 28.152 ;
     RECT  7.196 77.136 7.436 77.784 ;
     RECT  7.196 81.552 7.436 83.736 ;
     RECT  7.244 17.088 7.477 17.112 ;
     RECT  7.244 7.872 7.513 7.896 ;
     RECT  7.004 65.616 7.525 66.216 ;
     RECT  6.901 58.128 7.549 58.152 ;
     RECT  7.525 64.8 7.585 66.216 ;
     RECT  7.244 67.584 7.585 76.056 ;
     RECT  7.369 13.632 7.621 14.232 ;
     RECT  7.477 17.088 7.621 17.352 ;
     RECT  6.725 34.656 7.621 37.128 ;
     RECT  6.659 38.208 7.621 38.232 ;
     RECT  7.333 52.56 7.621 52.584 ;
     RECT  7.333 53.568 7.621 55.896 ;
     RECT  7.621 52.56 7.649 55.896 ;
     RECT  5.507 56.976 7.649 57 ;
     RECT  7.004 5.04 7.669 5.928 ;
     RECT  7.513 7.2 7.669 7.896 ;
     RECT  7.261 79.2 7.669 79.224 ;
     RECT  7.436 81.216 7.669 83.736 ;
     RECT  7.261 2.256 7.808 3.24 ;
     RECT  7.669 5.04 7.808 7.896 ;
     RECT  7.117 9.072 7.808 9.096 ;
     RECT  7.669 10.128 7.808 10.152 ;
     RECT  7.436 11.28 7.808 11.304 ;
     RECT  7.436 12.336 7.808 12.36 ;
     RECT  7.621 13.632 7.808 14.52 ;
     RECT  6.853 15.984 7.808 16.056 ;
     RECT  7.621 17.088 7.808 18.168 ;
     RECT  7.081 19.344 7.808 19.368 ;
     RECT  7.141 21.024 7.808 21.48 ;
     RECT  7.436 22.464 7.808 28.488 ;
     RECT  6.725 29.76 7.808 33.672 ;
     RECT  7.621 34.656 7.808 38.232 ;
     RECT  7.297 39.552 7.808 40.44 ;
     RECT  7.004 42.096 7.808 42.12 ;
     RECT  7.244 43.248 7.808 43.272 ;
     RECT  6.901 44.352 7.808 45.192 ;
     RECT  7.436 46.752 7.808 46.776 ;
     RECT  7.477 47.856 7.808 47.88 ;
     RECT  7.045 49.2 7.808 49.56 ;
     RECT  6.685 50.736 7.808 51.336 ;
     RECT  7.649 52.56 7.808 57 ;
     RECT  7.549 58.128 7.808 58.728 ;
     RECT  6.229 59.808 7.808 59.832 ;
     RECT  7.004 60.96 7.808 60.984 ;
     RECT  7.1 62.592 7.808 62.616 ;
     RECT  7.1 63.744 7.808 63.768 ;
     RECT  7.585 64.8 7.808 76.056 ;
     RECT  7.436 77.136 7.808 78.12 ;
     RECT  7.669 79.2 7.808 79.704 ;
     RECT  7.669 80.784 7.808 83.736 ;
     RECT  7.808 2.148 7.912 84.252 ;
     RECT  7.912 2.418 8.104 83.982 ;
     RECT  8.104 3.312 8.243 4.248 ;
     RECT  8.104 8.496 8.243 9.24 ;
     RECT  8.104 11.856 8.243 12.936 ;
     RECT  8.104 22.704 8.243 26.616 ;
     RECT  8.104 45.6 8.243 48.696 ;
     RECT  8.104 61.536 8.243 61.752 ;
     RECT  8.104 69.12 8.243 78.648 ;
     RECT  8.104 57.024 8.245 57.048 ;
     RECT  8.104 20.16 8.291 21.384 ;
     RECT  8.104 28.416 8.309 28.488 ;
     RECT  8.104 30.576 8.309 42.6 ;
     RECT  8.243 45.6 8.309 47.88 ;
     RECT  8.104 50.16 8.317 50.76 ;
     RECT  8.104 18.816 8.339 18.84 ;
     RECT  8.291 20.784 8.339 21.384 ;
     RECT  8.243 24.912 8.339 26.616 ;
     RECT  8.243 69.12 8.345 77.976 ;
     RECT  8.345 69.12 8.387 71.256 ;
     RECT  8.309 45.792 8.417 47.88 ;
     RECT  8.104 5.904 8.483 5.928 ;
     RECT  8.317 50.736 8.483 50.76 ;
     RECT  8.104 62.736 8.483 62.952 ;
     RECT  8.243 3.312 8.524 3.336 ;
     RECT  8.243 22.704 8.525 23.928 ;
     RECT  8.104 17.088 8.531 17.64 ;
     RECT  8.339 20.784 8.531 20.808 ;
     RECT  8.417 46.032 8.561 47.88 ;
     RECT  8.104 43.92 8.597 43.944 ;
     RECT  8.243 61.536 8.597 61.56 ;
     RECT  8.309 30.672 8.62 42.6 ;
     RECT  8.525 22.704 8.627 22.776 ;
     RECT  8.104 29.472 8.627 29.496 ;
     RECT  8.62 30.672 8.627 41.64 ;
     RECT  8.345 72.432 8.627 77.976 ;
     RECT  8.104 79.824 8.627 79.992 ;
     RECT  8.104 81.936 8.627 83.832 ;
     RECT  8.627 83.04 8.641 83.832 ;
     RECT  8.627 30.672 8.705 41.208 ;
     RECT  8.705 31.872 8.813 41.208 ;
     RECT  8.104 64.224 8.819 65.208 ;
     RECT  8.387 69.12 8.819 71.208 ;
     RECT  8.627 77.568 8.819 77.976 ;
     RECT  8.104 52.896 8.821 54.024 ;
     RECT  8.531 17.088 8.849 17.112 ;
     RECT  8.104 59.28 8.849 59.304 ;
     RECT  8.627 79.824 8.849 79.848 ;
     RECT  8.243 12.528 8.915 12.552 ;
     RECT  8.104 14.352 8.956 15.336 ;
     RECT  8.813 31.872 8.956 41.016 ;
     RECT  8.956 14.784 8.965 15.336 ;
     RECT  8.956 32.064 9.011 41.016 ;
     RECT  8.561 46.896 9.011 47.88 ;
     RECT  8.821 52.896 9.011 53.928 ;
     RECT  9.011 52.896 9.029 52.92 ;
     RECT  9.011 35.856 9.059 41.016 ;
     RECT  8.819 69.984 9.101 71.208 ;
     RECT  8.627 81.936 9.164 81.96 ;
     RECT  8.243 8.496 9.203 8.52 ;
     RECT  9.157 11.424 9.245 11.544 ;
     RECT  9.245 11.52 9.251 11.544 ;
     RECT  9.164 81.312 9.251 81.96 ;
     RECT  8.309 28.416 9.308 28.44 ;
     RECT  9.205 15.648 9.347 15.672 ;
     RECT  9.059 35.856 9.347 40.008 ;
     RECT  9.011 47.04 9.347 47.88 ;
     RECT  9.26 52.08 9.347 52.44 ;
     RECT  8.339 26.352 9.349 26.616 ;
     RECT  9.277 57.024 9.361 57.048 ;
     RECT  9.308 28.416 9.395 28.824 ;
     RECT  8.627 72.432 9.395 76.008 ;
     RECT  9.397 7.2 9.421 7.224 ;
     RECT  8.339 24.912 9.421 24.936 ;
     RECT  9.349 26.256 9.421 26.616 ;
     RECT  9.277 43.872 9.421 43.896 ;
     RECT  9.356 10.176 9.443 10.2 ;
     RECT  9.313 16.656 9.443 16.68 ;
     RECT  9.277 19.584 9.443 19.704 ;
     RECT  9.421 6.864 9.484 7.224 ;
     RECT  9.347 36.384 9.491 40.008 ;
     RECT  9.385 57.6 9.491 57.624 ;
     RECT  8.483 62.736 9.491 62.76 ;
     RECT  9.404 68.88 9.491 68.904 ;
     RECT  9.101 69.984 9.491 70.008 ;
     RECT  9.101 71.184 9.491 71.208 ;
     RECT  9.395 72.432 9.491 75.336 ;
     RECT  9.109 60.96 9.497 60.984 ;
     RECT  9.011 32.064 9.532 34.056 ;
     RECT  9.532 32.832 9.533 34.056 ;
     RECT  9.491 72.432 9.533 75.288 ;
     RECT  9.491 36.768 9.539 40.008 ;
     RECT  9.059 40.992 9.587 41.016 ;
     RECT  9.493 49.584 9.587 49.608 ;
     RECT  8.705 30.672 9.589 30.696 ;
     RECT  9.421 43.728 9.596 43.896 ;
     RECT  9.529 4.512 9.613 4.536 ;
     RECT  9.529 20.544 9.613 20.76 ;
     RECT  9.613 20.736 9.635 20.76 ;
     RECT  9.421 26.256 9.635 27.336 ;
     RECT  9.421 2.832 9.637 2.856 ;
     RECT  8.819 77.568 9.637 77.592 ;
     RECT  9.539 38.784 9.649 40.008 ;
     RECT  9.596 13.296 9.683 13.32 ;
     RECT  9.565 18.432 9.683 18.456 ;
     RECT  9.533 32.832 9.683 33.528 ;
     RECT  9.596 42.48 9.683 42.504 ;
     RECT  9.596 43.68 9.683 43.896 ;
     RECT  9.347 47.04 9.683 47.736 ;
     RECT  9.637 2.832 9.721 3.432 ;
     RECT  9.683 43.728 9.745 43.896 ;
     RECT  9.637 77.424 9.779 77.592 ;
     RECT  9.692 79.152 9.779 79.224 ;
     RECT  9.589 30.192 9.781 30.696 ;
     RECT  9.349 22.176 9.785 22.2 ;
     RECT  9.637 58.704 9.785 58.728 ;
     RECT  9.565 72.192 9.785 72.216 ;
     RECT  9.421 24.624 9.836 24.936 ;
     RECT  9.635 26.256 9.836 27.24 ;
     RECT  9.836 24.624 9.853 27.24 ;
     RECT  9.781 30.192 9.853 30.744 ;
     RECT  9.683 32.832 9.857 33.288 ;
     RECT  9.721 2.832 9.875 2.856 ;
     RECT  9.853 24.48 9.877 27.24 ;
     RECT  9.733 76.32 9.893 76.344 ;
     RECT  9.829 17.568 9.916 17.688 ;
     RECT  9.877 24.048 9.923 27.24 ;
     RECT  9.853 29.472 9.923 30.744 ;
     RECT  9.745 43.728 9.923 44.472 ;
     RECT  9.916 17.664 9.937 17.688 ;
     RECT  9.923 24.048 9.997 24.936 ;
     RECT  9.484 6.864 10.033 6.888 ;
     RECT  9.533 73.344 10.037 75.288 ;
     RECT  9.961 55.296 10.115 55.32 ;
     RECT  9.857 32.832 10.145 32.856 ;
     RECT  9.923 43.728 10.181 43.896 ;
     RECT  9.997 23.184 10.217 24.936 ;
     RECT  9.923 29.472 10.217 30.216 ;
     RECT  10.037 73.344 10.289 75.192 ;
     RECT  10.22 62.064 10.307 62.088 ;
     RECT  10.177 65.904 10.307 65.928 ;
     RECT  10.22 72.048 10.307 72.072 ;
     RECT  10.289 73.344 10.333 74.712 ;
     RECT  10.393 67.968 10.401 67.992 ;
     RECT  9.539 36.768 10.444 37.32 ;
     RECT  10.033 6.24 10.46 6.888 ;
     RECT  10.393 60.384 10.477 60.408 ;
     RECT  10.217 23.184 10.493 23.352 ;
     RECT  10.46 6.24 10.547 7.224 ;
     RECT  10.401 67.2 10.547 67.992 ;
     RECT  10.429 69.84 10.547 69.864 ;
     RECT  10.463 45.408 10.573 45.432 ;
     RECT  10.493 22.8 10.577 23.352 ;
     RECT  10.577 23.328 10.595 23.352 ;
     RECT  10.217 29.472 10.595 29.496 ;
     RECT  10.321 21.168 10.597 21.192 ;
     RECT  10.573 41.472 10.607 41.496 ;
     RECT  10.556 9.408 10.643 9.432 ;
     RECT  9.649 39.456 10.645 40.008 ;
     RECT  10.573 45.408 10.645 45.96 ;
     RECT  9.011 53.904 10.645 53.928 ;
     RECT  10.645 45.408 10.691 46.056 ;
     RECT  10.501 48.912 10.713 48.936 ;
     RECT  8.641 83.04 10.717 83.736 ;
     RECT  10.691 45.936 10.721 46.056 ;
     RECT  10.597 21.12 10.741 21.192 ;
     RECT  10.645 38.64 10.741 40.008 ;
     RECT  10.721 46.032 10.757 46.056 ;
     RECT  10.717 82.944 10.757 83.736 ;
     RECT  10.741 21.12 10.787 21.528 ;
     RECT  10.741 38.64 10.787 40.296 ;
     RECT  10.607 41.472 10.787 41.64 ;
     RECT  10.787 41.472 10.793 41.496 ;
     RECT  10.717 57.6 10.801 57.624 ;
     RECT  9.251 81.936 10.825 81.96 ;
     RECT  10.757 82.944 10.825 83.688 ;
     RECT  10.645 53.904 10.829 54.888 ;
     RECT  9.923 25.968 10.861 27.24 ;
     RECT  9.395 28.416 10.861 28.44 ;
     RECT  10.825 81.936 10.909 83.688 ;
     RECT  10.787 21.504 10.973 21.528 ;
     RECT  10.829 54.048 10.973 54.888 ;
     RECT  10.333 73.344 10.973 74.04 ;
     RECT  10.787 39.456 11.045 40.296 ;
     RECT  10.861 25.968 11.369 28.44 ;
     RECT  11.045 39.456 11.441 39.768 ;
     RECT  10.909 82.944 11.513 83.688 ;
     RECT  10.444 36.768 12.197 36.792 ;
     RECT  10.309 10.608 13.208 10.632 ;
     RECT  12.469 19.248 13.208 19.272 ;
     RECT  11.029 20.304 13.208 20.328 ;
     RECT  10.217 24.912 13.208 24.936 ;
     RECT  11.369 25.968 13.208 27.096 ;
     RECT  11.369 28.416 13.208 28.44 ;
     RECT  12.469 36.96 13.208 36.984 ;
     RECT  11.441 39.456 13.208 39.48 ;
     RECT  9.683 47.04 13.208 47.064 ;
     RECT  9.347 52.416 13.208 52.44 ;
     RECT  10.973 54.048 13.208 54.072 ;
     RECT  10.973 73.344 13.208 73.368 ;
     RECT  9.779 77.568 13.208 77.592 ;
     RECT  9.779 79.2 13.208 79.224 ;
     RECT  11.869 80.592 13.208 80.616 ;
     RECT  10.909 81.936 13.208 81.96 ;
     RECT  11.513 82.944 13.208 83.64 ;
     RECT  13.208 2.148 13.312 84.252 ;
     RECT  13.312 2.418 13.504 83.982 ;
     RECT  13.504 19.248 17.629 19.272 ;
     RECT  13.504 20.304 17.629 20.328 ;
     RECT  17.797 2.592 18.608 2.616 ;
     RECT  13.504 8.544 18.608 8.568 ;
     RECT  13.504 10.608 18.608 10.632 ;
     RECT  17.629 19.248 18.608 20.328 ;
     RECT  13.504 24.912 18.608 24.936 ;
     RECT  13.504 25.968 18.608 27.096 ;
     RECT  13.504 28.416 18.608 28.44 ;
     RECT  13.504 39.456 18.608 39.48 ;
     RECT  13.504 47.04 18.608 47.064 ;
     RECT  13.504 52.416 18.608 52.44 ;
     RECT  13.504 73.344 18.608 73.368 ;
     RECT  13.504 77.568 18.608 77.592 ;
     RECT  13.504 79.2 18.608 79.224 ;
     RECT  13.504 80.496 18.608 80.52 ;
     RECT  13.504 81.936 18.608 81.96 ;
     RECT  13.504 82.944 18.608 83.64 ;
     RECT  18.608 2.148 18.712 84.252 ;
     RECT  18.712 2.418 18.904 83.982 ;
     RECT  18.904 25.968 19.109 28.44 ;
     RECT  18.904 19.344 19.235 20.52 ;
     RECT  19.109 25.968 19.235 27.096 ;
     RECT  19.235 19.344 19.331 20.328 ;
     RECT  18.904 24.912 19.331 24.936 ;
     RECT  18.904 2.592 19.361 3.624 ;
     RECT  19.361 2.832 19.405 3.624 ;
     RECT  18.904 63.216 19.505 63.24 ;
     RECT  18.904 8.544 22.277 8.568 ;
     RECT  18.904 15.984 22.889 16.008 ;
     RECT  18.904 10.608 23.173 10.632 ;
     RECT  21.589 2.304 24.008 2.328 ;
     RECT  19.405 3.6 24.008 3.624 ;
     RECT  23.173 10.608 24.008 11.256 ;
     RECT  18.904 13.296 24.008 13.32 ;
     RECT  23.132 16.176 24.008 16.2 ;
     RECT  19.331 20.16 24.008 20.328 ;
     RECT  19.235 25.968 24.008 26.616 ;
     RECT  19.109 28.416 24.008 28.44 ;
     RECT  18.904 39.456 24.008 39.48 ;
     RECT  18.904 47.04 24.008 47.064 ;
     RECT  18.904 52.416 24.008 52.44 ;
     RECT  18.904 73.344 24.008 73.368 ;
     RECT  18.904 77.568 24.008 77.592 ;
     RECT  18.904 79.2 24.008 79.224 ;
     RECT  18.904 80.496 24.008 80.52 ;
     RECT  18.904 81.936 24.008 81.96 ;
     RECT  18.904 82.944 24.008 83.64 ;
     RECT  24.008 2.148 24.112 84.252 ;
     RECT  24.112 2.418 24.304 83.982 ;
     RECT  24.304 3.936 24.419 3.96 ;
     RECT  6.565 0.048 24.617 0.12 ;
     RECT  24.304 10.608 25.333 11.4 ;
     RECT  24.617 0.048 25.337 0.072 ;
     RECT  25.292 2.256 25.379 2.28 ;
     RECT  24.304 20.16 25.379 20.328 ;
     RECT  25.333 10.032 25.445 11.4 ;
     RECT  24.304 13.296 26.017 13.32 ;
     RECT  25.292 15.168 26.773 15.192 ;
     RECT  26.773 15.024 26.813 15.192 ;
     RECT  26.017 13.296 26.993 13.416 ;
     RECT  26.845 16.848 27.457 16.872 ;
     RECT  26.993 13.296 27.565 13.32 ;
     RECT  28.033 18.432 28.213 18.456 ;
     RECT  24.304 7.104 28.717 7.128 ;
     RECT  28.213 18.432 28.933 18.552 ;
     RECT  28.717 6.576 29.005 7.128 ;
     RECT  25.379 20.304 29.113 20.328 ;
     RECT  25.445 11.376 29.125 11.4 ;
     RECT  27.565 12.528 29.125 13.32 ;
     RECT  29.077 1.728 29.189 1.752 ;
     RECT  27.889 2.88 29.408 2.904 ;
     RECT  29.005 6.576 29.408 7.368 ;
     RECT  25.445 10.032 29.408 10.056 ;
     RECT  29.125 11.376 29.408 13.32 ;
     RECT  26.813 15.024 29.408 15.048 ;
     RECT  27.457 16.8 29.408 16.872 ;
     RECT  28.933 18.432 29.408 18.84 ;
     RECT  29.113 19.968 29.408 20.328 ;
     RECT  24.304 26.256 29.408 26.616 ;
     RECT  24.304 28.416 29.408 28.44 ;
     RECT  24.304 39.456 29.408 39.48 ;
     RECT  24.304 47.04 29.408 47.064 ;
     RECT  24.304 52.416 29.408 52.44 ;
     RECT  24.304 73.344 29.408 73.368 ;
     RECT  24.304 77.568 29.408 77.592 ;
     RECT  24.304 79.2 29.408 79.224 ;
     RECT  24.304 80.496 29.408 80.52 ;
     RECT  24.304 81.936 29.408 81.96 ;
     RECT  24.304 82.944 29.408 83.64 ;
     RECT  29.408 2.148 29.512 84.252 ;
     RECT  29.512 2.418 29.704 83.982 ;
     RECT  29.704 16.8 29.873 17.112 ;
     RECT  29.704 15.024 30.323 15.048 ;
     RECT  29.704 11.088 30.377 13.656 ;
     RECT  30.377 11.088 30.412 13.272 ;
     RECT  29.704 3.12 30.515 3.144 ;
     RECT  30.412 11.088 30.515 12.648 ;
     RECT  29.704 7.104 30.557 10.104 ;
     RECT  29.873 16.8 30.733 16.92 ;
     RECT  30.515 11.088 30.755 11.4 ;
     RECT  30.557 9.264 30.769 10.104 ;
     RECT  30.755 11.088 30.769 11.256 ;
     RECT  29.704 5.232 30.805 6.072 ;
     RECT  30.557 7.104 30.805 8.136 ;
     RECT  29.704 20.16 30.809 20.184 ;
     RECT  30.515 12.624 30.853 12.648 ;
     RECT  30.733 16.704 30.913 16.92 ;
     RECT  30.805 5.232 30.953 8.136 ;
     RECT  30.913 16.56 30.953 16.92 ;
     RECT  30.697 14.496 30.995 14.616 ;
     RECT  30.953 16.56 30.997 16.728 ;
     RECT  30.877 2.832 31.052 2.856 ;
     RECT  31.052 2.592 31.133 2.856 ;
     RECT  31.133 2.592 31.139 2.616 ;
     RECT  30.953 5.232 31.139 6.264 ;
     RECT  31.139 5.808 31.241 6.264 ;
     RECT  31.436 4.704 31.477 4.728 ;
     RECT  31.477 3.936 31.523 4.728 ;
     RECT  31.523 3.936 31.601 4.392 ;
     RECT  31.453 13.824 31.619 13.848 ;
     RECT  31.453 14.832 31.619 14.856 ;
     RECT  30.953 7.632 31.861 8.136 ;
     RECT  30.769 9.264 31.861 11.256 ;
     RECT  31.813 15.216 31.861 15.24 ;
     RECT  31.777 19.968 31.907 19.992 ;
     RECT  31.772 13.44 31.921 13.704 ;
     RECT  31.861 15.216 31.925 15.528 ;
     RECT  31.925 15.504 31.948 15.528 ;
     RECT  31.861 7.632 31.993 11.256 ;
     RECT  31.921 12.48 31.993 13.704 ;
     RECT  31.849 2.256 32.051 2.28 ;
     RECT  31.241 6 32.245 6.264 ;
     RECT  31.993 7.632 32.245 13.704 ;
     RECT  30.997 16.704 32.285 16.728 ;
     RECT  32.245 6 32.437 13.704 ;
     RECT  31.601 4.272 32.483 4.392 ;
     RECT  32.437 5.424 32.609 13.704 ;
     RECT  32.609 5.424 32.627 10.872 ;
     RECT  32.609 11.856 32.645 13.704 ;
     RECT  32.627 10.08 32.653 10.872 ;
     RECT  32.713 2.784 32.821 2.808 ;
     RECT  32.821 2.784 32.929 2.952 ;
     RECT  32.857 1.728 32.941 1.752 ;
     RECT  32.627 5.424 33.001 9 ;
     RECT  32.929 2.784 33.029 3.384 ;
     RECT  33.029 2.256 33.113 3.384 ;
     RECT  33.325 18.192 33.409 18.216 ;
     RECT  33.349 19.776 33.437 20.712 ;
     RECT  33.001 5.136 33.443 9 ;
     RECT  33.5 17.328 33.587 17.352 ;
     RECT  33.113 2.64 33.596 3.384 ;
     RECT  33.548 16.224 33.635 16.248 ;
     RECT  32.653 10.08 33.637 10.776 ;
     RECT  32.645 11.856 33.637 13.656 ;
     RECT  33.596 2.64 33.683 3.72 ;
     RECT  33.865 15.264 33.973 16.056 ;
     RECT  33.443 5.136 34.009 8.904 ;
     RECT  33.683 2.64 34.297 3.384 ;
     RECT  34.009 4.848 34.501 8.904 ;
     RECT  33.973 15.216 34.693 16.056 ;
     RECT  34.556 17.616 34.693 17.64 ;
     RECT  34.501 4.704 34.765 8.904 ;
     RECT  34.297 2.256 34.808 3.384 ;
     RECT  34.765 4.656 34.808 8.904 ;
     RECT  33.637 10.08 34.808 13.656 ;
     RECT  34.693 15.216 34.808 17.64 ;
     RECT  33.437 20.064 34.808 20.184 ;
     RECT  29.704 26.256 34.808 26.616 ;
     RECT  29.704 28.416 34.808 28.44 ;
     RECT  29.704 39.456 34.808 39.48 ;
     RECT  29.704 47.04 34.808 47.064 ;
     RECT  29.704 52.416 34.808 52.44 ;
     RECT  34.765 58.56 34.808 58.584 ;
     RECT  29.704 73.344 34.808 73.368 ;
     RECT  29.704 77.568 34.808 77.592 ;
     RECT  29.704 79.2 34.808 79.224 ;
     RECT  29.704 80.496 34.808 80.52 ;
     RECT  29.704 81.936 34.808 81.96 ;
     RECT  29.704 82.944 34.808 83.64 ;
     RECT  34.808 2.148 34.912 84.252 ;
     RECT  34.912 2.256 35.104 83.982 ;
     RECT  35.104 19.776 35.219 20.184 ;
     RECT  35.104 2.256 35.267 17.112 ;
     RECT  35.267 2.256 35.417 13.8 ;
     RECT  35.417 2.448 35.633 13.8 ;
     RECT  35.633 2.448 35.651 8.472 ;
     RECT  35.633 9.648 35.692 13.8 ;
     RECT  35.651 2.448 35.699 8.328 ;
     RECT  35.692 9.648 35.699 11.112 ;
     RECT  35.699 10.272 35.795 11.112 ;
     RECT  35.699 2.448 35.891 6.888 ;
     RECT  35.891 2.448 35.921 4.68 ;
     RECT  35.692 12.192 35.993 13.8 ;
     RECT  35.993 12.192 36.035 12.216 ;
     RECT  35.219 20.16 36.101 20.184 ;
     RECT  35.921 3.072 36.173 4.68 ;
     RECT  35.267 15.072 36.188 17.112 ;
     RECT  36.173 3.072 36.217 4.536 ;
     RECT  35.699 8.304 36.275 8.328 ;
     RECT  36.188 15.072 36.275 17.496 ;
     RECT  36.275 15.072 36.281 16.872 ;
     RECT  35.795 10.272 36.316 10.872 ;
     RECT  36.281 15.072 36.413 16.536 ;
     RECT  36.413 14.784 36.425 16.536 ;
     RECT  36.425 14.784 36.467 16.056 ;
     RECT  36.467 14.784 36.497 15.48 ;
     RECT  35.891 5.712 36.541 6.888 ;
     RECT  36.229 20.544 36.605 20.568 ;
     RECT  35.593 0.528 36.659 0.552 ;
     RECT  36.541 5.808 36.749 6.888 ;
     RECT  35.993 13.536 36.757 13.8 ;
     RECT  36.716 9.216 36.803 9.24 ;
     RECT  36.757 11.904 36.844 11.928 ;
     RECT  36.217 3.072 36.925 4.2 ;
     RECT  36.757 13.536 36.929 14.376 ;
     RECT  36.497 15.456 36.929 15.48 ;
     RECT  36.316 10.272 37.073 10.392 ;
     RECT  36.925 2.736 37.105 4.2 ;
     RECT  36.749 6.672 37.145 6.888 ;
     RECT  37.033 8.064 37.285 8.088 ;
     RECT  35.104 82.944 37.465 83.64 ;
     RECT  35.104 81.936 37.501 81.96 ;
     RECT  37.465 82.944 37.501 83.688 ;
     RECT  37.145 6.816 37.537 6.888 ;
     RECT  37.285 7.872 37.537 8.088 ;
     RECT  35.104 47.04 37.537 47.064 ;
     RECT  35.104 39.456 37.541 39.48 ;
     RECT  35.104 79.2 37.681 79.224 ;
     RECT  37.033 86.208 37.681 86.232 ;
     RECT  37.321 10.848 37.717 10.872 ;
     RECT  35.104 77.568 37.753 77.592 ;
     RECT  37.537 46.8 37.793 47.064 ;
     RECT  35.104 73.344 37.861 73.368 ;
     RECT  37.537 74.352 37.861 74.376 ;
     RECT  37.717 10.848 37.897 10.92 ;
     RECT  37.465 12.192 37.897 12.792 ;
     RECT  37.681 85.68 37.897 86.232 ;
     RECT  37.501 81.936 37.933 83.688 ;
     RECT  37.573 5.664 38.005 5.688 ;
     RECT  37.537 6.816 38.005 8.088 ;
     RECT  37.933 81.936 38.041 83.736 ;
     RECT  37.069 42.768 38.077 42.792 ;
     RECT  38.005 6.816 38.113 9.048 ;
     RECT  35.104 28.416 38.113 28.44 ;
     RECT  38.041 81.936 38.113 83.784 ;
     RECT  37.897 84.768 38.113 86.232 ;
     RECT  37.105 2.304 38.149 4.2 ;
     RECT  35.104 80.496 38.149 80.52 ;
     RECT  38.113 81.936 38.149 86.232 ;
     RECT  38.113 6.72 38.153 9.048 ;
     RECT  38.077 42.144 38.185 42.792 ;
     RECT  37.861 73.344 38.185 74.376 ;
     RECT  38.149 80.496 38.221 86.232 ;
     RECT  38.005 5.184 38.257 5.688 ;
     RECT  37.861 15.936 38.257 16.152 ;
     RECT  37.249 20.832 38.261 20.856 ;
     RECT  37.717 0.432 38.293 0.456 ;
     RECT  38.149 1.728 38.293 4.2 ;
     RECT  38.185 53.808 38.293 53.832 ;
     RECT  37.753 77.568 38.293 77.64 ;
     RECT  38.293 0.432 38.329 4.2 ;
     RECT  37.717 63.792 38.329 63.816 ;
     RECT  38.329 0.096 38.365 4.2 ;
     RECT  38.257 5.184 38.365 5.736 ;
     RECT  37.897 10.848 38.365 12.792 ;
     RECT  38.153 6.72 38.369 8.088 ;
     RECT  38.293 53.52 38.401 53.832 ;
     RECT  38.293 77.136 38.401 77.64 ;
     RECT  38.365 10.656 38.405 12.792 ;
     RECT  37.793 47.04 38.437 47.064 ;
     RECT  37.681 79.2 38.473 79.368 ;
     RECT  38.221 80.496 38.473 86.328 ;
     RECT  38.437 47.04 38.509 47.592 ;
     RECT  37.573 67.68 38.509 67.704 ;
     RECT  38.401 77.136 38.509 78.024 ;
     RECT  38.473 79.2 38.509 86.328 ;
     RECT  38.405 11.952 38.545 12.792 ;
     RECT  38.509 47.04 38.581 47.64 ;
     RECT  38.185 72.912 38.653 74.568 ;
     RECT  38.581 47.04 38.689 47.88 ;
     RECT  38.437 18.576 38.693 18.6 ;
     RECT  38.689 47.04 38.725 48.84 ;
     RECT  38.509 67.536 38.725 67.704 ;
     RECT  38.257 15.264 38.729 16.152 ;
     RECT  38.185 9.216 38.761 9.24 ;
     RECT  38.729 16.032 38.761 16.152 ;
     RECT  38.653 51.216 38.761 51.24 ;
     RECT  35.104 52.416 38.761 52.44 ;
     RECT  38.185 57.552 38.761 57.576 ;
     RECT  38.185 58.656 38.761 58.68 ;
     RECT  38.725 67.536 38.761 67.848 ;
     RECT  38.761 51.216 38.797 52.44 ;
     RECT  38.509 77.136 38.797 86.328 ;
     RECT  35.104 26.256 38.801 26.616 ;
     RECT  38.329 63.744 38.801 63.816 ;
     RECT  38.725 47.04 38.833 49.752 ;
     RECT  38.797 50.928 38.833 52.44 ;
     RECT  38.401 64.896 38.833 64.92 ;
     RECT  38.689 66.528 38.833 66.552 ;
     RECT  38.761 67.536 38.833 68.52 ;
     RECT  38.761 9.216 38.869 9.624 ;
     RECT  38.405 10.656 38.869 10.92 ;
     RECT  38.653 72.912 38.869 74.712 ;
     RECT  38.761 57.552 38.905 58.68 ;
     RECT  38.113 27.84 38.909 28.44 ;
     RECT  38.797 76.704 38.909 86.328 ;
     RECT  38.365 0.096 38.941 5.736 ;
     RECT  38.369 6.72 38.941 7.896 ;
     RECT  38.833 66.528 38.941 68.52 ;
     RECT  38.833 47.04 38.977 52.44 ;
     RECT  38.401 53.424 38.981 53.832 ;
     RECT  38.941 66.528 38.981 69.48 ;
     RECT  38.761 44.496 39.053 44.52 ;
     RECT  38.869 72.912 39.157 75.048 ;
     RECT  38.909 76.704 39.157 79.224 ;
     RECT  38.545 11.952 39.161 13.32 ;
     RECT  39.157 72.912 39.161 79.224 ;
     RECT  38.761 16.032 39.233 16.296 ;
     RECT  38.941 21.12 39.265 21.144 ;
     RECT  39.157 33.264 39.265 33.288 ;
     RECT  38.905 57.408 39.265 58.68 ;
     RECT  38.257 61.152 39.301 61.176 ;
     RECT  37.969 70.848 39.301 70.872 ;
     RECT  38.981 53.52 39.373 53.832 ;
     RECT  39.265 20.352 39.445 21.144 ;
     RECT  38.977 37.44 39.481 37.464 ;
     RECT  39.265 57.408 39.517 58.968 ;
     RECT  38.941 0.096 39.697 7.896 ;
     RECT  39.697 0.048 39.841 7.896 ;
     RECT  38.869 9.216 39.841 10.92 ;
     RECT  39.233 16.032 39.877 16.152 ;
     RECT  39.265 33.264 39.877 33.576 ;
     RECT  38.761 34.752 39.877 34.776 ;
     RECT  39.841 35.76 39.877 35.784 ;
     RECT  39.301 61.152 39.913 61.32 ;
     RECT  39.301 62.64 39.913 62.664 ;
     RECT  39.481 36.816 40.021 37.464 ;
     RECT  38.905 56.256 40.057 56.28 ;
     RECT  39.161 75.36 40.129 79.224 ;
     RECT  38.909 80.256 40.129 86.328 ;
     RECT  39.841 0.048 40.208 10.92 ;
     RECT  39.161 12.72 40.208 13.32 ;
     RECT  39.877 15.792 40.208 16.152 ;
     RECT  39.481 18.288 40.208 18.312 ;
     RECT  39.445 20.304 40.208 21.144 ;
     RECT  38.545 23.28 40.208 23.304 ;
     RECT  39.589 24.912 40.208 24.936 ;
     RECT  38.801 26.256 40.208 26.28 ;
     RECT  38.909 28.128 40.208 28.44 ;
     RECT  39.877 32.304 40.208 33.576 ;
     RECT  39.877 34.752 40.208 35.784 ;
     RECT  40.021 36.816 40.208 37.608 ;
     RECT  38.797 38.736 40.208 38.76 ;
     RECT  38.581 40.368 40.208 40.392 ;
     RECT  38.185 42.048 40.208 42.792 ;
     RECT  38.977 46.752 40.208 52.44 ;
     RECT  39.373 53.52 40.208 54.696 ;
     RECT  40.057 55.968 40.208 56.28 ;
     RECT  39.517 57.408 40.208 59.544 ;
     RECT  39.913 61.152 40.208 62.664 ;
     RECT  38.833 63.936 40.208 64.92 ;
     RECT  38.981 66.528 40.208 67.704 ;
     RECT  38.981 69.216 40.208 69.48 ;
     RECT  39.301 70.8 40.208 70.872 ;
     RECT  39.161 72.912 40.208 74.376 ;
     RECT  40.129 75.36 40.208 86.328 ;
     RECT  40.208 0.048 40.504 86.328 ;
     RECT  40.504 18.816 40.529 21.192 ;
     RECT  40.504 50.112 40.565 53.448 ;
     RECT  40.504 62.256 40.601 65.016 ;
     RECT  40.504 55.968 40.673 55.992 ;
     RECT  40.504 0.048 41.533 1.896 ;
     RECT  40.504 2.88 41.533 6.12 ;
     RECT  40.504 13.92 41.533 13.944 ;
     RECT  40.504 15.744 41.533 16.536 ;
     RECT  40.504 29.52 41.533 29.544 ;
     RECT  40.504 32.304 41.533 38.76 ;
     RECT  40.504 45.072 41.533 45.096 ;
     RECT  40.504 46.08 41.533 46.104 ;
     RECT  40.565 50.688 41.533 50.712 ;
     RECT  40.504 59.328 41.533 60.504 ;
     RECT  40.504 71.136 41.533 71.16 ;
     RECT  41.533 0.048 41.569 6.12 ;
     RECT  40.504 8.784 41.569 10.104 ;
     RECT  40.504 11.184 41.569 11.64 ;
     RECT  41.533 13.92 41.569 14.232 ;
     RECT  41.533 15.744 41.569 17.688 ;
     RECT  40.529 18.816 41.569 21.048 ;
     RECT  40.504 22.56 41.569 26.568 ;
     RECT  40.504 28.464 41.569 28.488 ;
     RECT  41.533 29.52 41.569 30.024 ;
     RECT  41.533 31.824 41.569 38.76 ;
     RECT  40.504 40.176 41.569 40.2 ;
     RECT  40.504 41.184 41.569 42.264 ;
     RECT  41.533 45.072 41.569 46.104 ;
     RECT  40.504 47.088 41.569 47.4 ;
     RECT  41.533 48.528 41.569 48.552 ;
     RECT  41.533 50.304 41.569 50.712 ;
     RECT  41.533 59.328 41.569 60.744 ;
     RECT  40.601 62.4 41.569 65.016 ;
     RECT  40.504 69.888 41.569 69.912 ;
     RECT  41.533 71.04 41.569 71.16 ;
     RECT  40.504 72.432 41.569 73.128 ;
     RECT  40.504 74.352 41.569 74.376 ;
     RECT  40.504 75.456 41.569 86.328 ;
     RECT  41.569 8.784 41.605 11.64 ;
     RECT  41.569 13.68 41.605 14.232 ;
     RECT  41.569 15.744 41.605 21.048 ;
     RECT  41.569 22.416 41.605 26.568 ;
     RECT  41.569 44.544 41.605 50.712 ;
     RECT  40.565 52.128 41.605 53.448 ;
     RECT  41.569 55.488 41.605 55.512 ;
     RECT  41.569 56.64 41.605 56.664 ;
     RECT  41.569 57.792 41.605 57.816 ;
     RECT  41.569 59.328 41.605 65.496 ;
     RECT  40.504 66.528 41.605 68.328 ;
     RECT  41.569 69.6 41.605 71.16 ;
     RECT  41.569 72.192 41.605 86.328 ;
     RECT  41.605 22.416 41.641 27.096 ;
     RECT  41.605 44.544 41.641 51.096 ;
     RECT  41.605 52.128 41.641 54.312 ;
     RECT  41.605 56.64 41.641 57.816 ;
     RECT  41.605 58.944 41.641 86.328 ;
     RECT  41.605 15.36 41.677 21.048 ;
     RECT  41.641 22.272 41.677 27.096 ;
     RECT  40.504 7.248 41.821 7.8 ;
     RECT  41.605 8.784 41.821 14.232 ;
     RECT  41.569 40.176 41.821 42.264 ;
     RECT  41.641 44.544 41.821 54.312 ;
     RECT  41.605 55.344 41.821 55.512 ;
     RECT  41.677 15.36 42.073 27.096 ;
     RECT  41.821 7.248 42.109 14.232 ;
     RECT  42.073 15.216 42.109 27.096 ;
     RECT  41.569 28.08 42.109 38.76 ;
     RECT  41.821 39.888 42.109 42.264 ;
     RECT  41.605 43.392 42.109 43.416 ;
     RECT  41.821 44.544 42.109 55.512 ;
     RECT  41.569 0.048 42.145 6.264 ;
     RECT  42.109 7.248 42.145 55.512 ;
     RECT  41.641 56.64 42.145 86.328 ;
     RECT  42.145 0.048 43.164 86.328 ;
    LAYER M5 ;
     RECT  2.4 2.137 2.52 2.151 ;
     RECT  7.8 2.137 7.92 2.151 ;
     RECT  17.808 2.137 18.72 2.151 ;
     RECT  24 2.137 24.12 2.151 ;
     RECT  29.4 2.137 29.52 2.151 ;
     RECT  34.8 2.137 34.92 2.151 ;
     RECT  40.2 2.137 40.32 2.151 ;
     RECT  7.8 2.151 8.112 2.245 ;
     RECT  34.8 2.151 35.112 2.245 ;
     RECT  32.016 2.245 32.04 2.581 ;
     RECT  17.808 2.151 18.912 2.627 ;
     RECT  33.072 2.245 33.096 2.629 ;
     RECT  34.368 2.245 35.208 2.629 ;
     RECT  4.32 2.245 4.344 2.821 ;
     RECT  7.296 2.245 8.112 2.821 ;
     RECT  18.6 2.627 18.912 2.821 ;
     RECT  29.4 2.151 29.712 3.109 ;
     RECT  31.104 2.581 32.04 3.109 ;
     RECT  3.696 2.821 8.112 3.301 ;
     RECT  2.4 2.151 2.712 3.349 ;
     RECT  3.696 3.301 8.472 3.349 ;
     RECT  18.6 2.821 19.368 3.635 ;
     RECT  24 2.151 24.312 3.925 ;
     RECT  33.072 2.629 35.208 3.925 ;
     RECT  36.48 3.397 36.504 3.925 ;
     RECT  0.96 0.037 0.984 4.213 ;
     RECT  29.4 3.109 32.04 4.261 ;
     RECT  33.072 3.925 36.792 4.261 ;
     RECT  0.96 4.213 1.176 4.499 ;
     RECT  40.2 2.151 40.512 5.173 ;
     RECT  40.2 5.173 40.776 5.843 ;
     RECT  40.2 5.843 40.512 5.893 ;
     RECT  9.456 2.821 10.344 6.229 ;
     RECT  39.984 5.893 40.512 6.707 ;
     RECT  24 3.925 24.408 7.139 ;
     RECT  2.4 3.349 8.472 7.189 ;
     RECT  9.456 6.229 10.536 7.189 ;
     RECT  13.2 2.137 14.088 8.579 ;
     RECT  2.4 7.189 10.536 9.397 ;
     RECT  24 7.139 24.312 11.221 ;
     RECT  29.4 4.261 36.792 11.941 ;
     RECT  29.136 11.941 36.792 13.139 ;
     RECT  18.6 3.635 18.912 13.285 ;
     RECT  29.136 13.139 33.624 13.715 ;
     RECT  34.608 13.139 36.792 14.387 ;
     RECT  29.136 13.715 31.848 15.059 ;
     RECT  30.96 15.059 31.848 15.493 ;
     RECT  34.608 14.387 36.456 16.067 ;
     RECT  33.552 13.715 33.624 16.259 ;
     RECT  30.96 15.493 31.896 16.595 ;
     RECT  34.608 16.067 36.264 17.123 ;
     RECT  33.552 16.259 33.576 17.363 ;
     RECT  34.608 17.123 35.208 17.651 ;
     RECT  13.2 8.579 13.512 19.237 ;
     RECT  34.8 17.651 35.208 19.811 ;
     RECT  29.136 15.059 29.712 20.003 ;
     RECT  31.872 16.595 31.896 20.003 ;
     RECT  25.344 10.021 25.368 20.195 ;
     RECT  2.4 9.397 10.632 20.293 ;
     RECT  36.24 17.123 36.264 20.579 ;
     RECT  33.36 18.181 33.384 20.723 ;
     RECT  18.6 13.285 19.32 24.947 ;
     RECT  23.184 11.221 24.312 26.003 ;
     RECT  18.6 24.947 19.224 27.107 ;
     RECT  2.4 20.293 11.064 27.395 ;
     RECT  0.96 4.499 0.984 36.659 ;
     RECT  43.008 36.805 43.032 36.947 ;
     RECT  2.4 27.395 10.776 41.651 ;
     RECT  2.4 41.651 10.68 45.443 ;
     RECT  2.4 45.443 10.536 46.787 ;
     RECT  3.936 46.787 10.536 48.901 ;
     RECT  12.48 19.237 13.512 54.083 ;
     RECT  3.936 48.901 10.68 54.853 ;
     RECT  3.936 54.853 10.776 55.331 ;
     RECT  10.752 55.331 10.776 57.635 ;
     RECT  3.936 55.331 9.672 58.739 ;
     RECT  6 58.739 8.808 59.315 ;
     RECT  4.752 58.739 4.776 60.181 ;
     RECT  4.32 60.181 4.776 60.661 ;
     RECT  7.104 59.315 8.112 60.949 ;
     RECT  2.4 46.787 2.712 61.525 ;
     RECT  4.32 60.661 4.92 61.525 ;
     RECT  7.056 60.949 8.112 61.525 ;
     RECT  9.12 60.949 9.144 61.525 ;
     RECT  10.416 60.373 10.44 62.053 ;
     RECT  7.056 61.525 9.144 62.293 ;
     RECT  2.4 61.525 5.112 62.629 ;
     RECT  6.528 62.293 9.144 62.629 ;
     RECT  2.4 62.629 9.144 62.725 ;
     RECT  10.272 62.053 10.44 62.725 ;
     RECT  2.4 62.725 10.44 62.771 ;
     RECT  43.008 62.773 43.032 63.011 ;
     RECT  2.4 62.771 8.472 63.299 ;
     RECT  6.528 63.299 8.472 64.213 ;
     RECT  9.456 62.771 10.44 64.213 ;
     RECT  2.4 63.299 5.112 64.357 ;
     RECT  6.528 64.213 10.44 64.357 ;
     RECT  2.4 64.357 10.44 67.189 ;
     RECT  2.4 67.189 10.536 70.115 ;
     RECT  4.32 70.115 10.536 70.739 ;
     RECT  4.464 70.739 10.536 71.219 ;
     RECT  2.4 70.115 3.144 72.325 ;
     RECT  4.464 71.219 9.24 72.325 ;
     RECT  2.4 72.325 9.24 72.371 ;
     RECT  3.84 72.371 9.24 72.853 ;
     RECT  10.272 71.219 10.536 72.853 ;
     RECT  3.84 72.853 10.536 74.005 ;
     RECT  3.84 74.005 10.872 74.723 ;
     RECT  3.84 74.723 9.768 80.291 ;
     RECT  2.4 72.371 2.712 80.677 ;
     RECT  3.84 80.291 5.112 80.677 ;
     RECT  2.4 80.677 5.112 81.011 ;
     RECT  6.144 80.291 9.768 81.589 ;
     RECT  2.4 81.011 4.728 82.931 ;
     RECT  10.848 74.723 10.872 82.979 ;
     RECT  5.808 81.589 9.768 83.075 ;
     RECT  2.4 82.931 3.576 83.267 ;
     RECT  4.656 82.931 4.728 83.267 ;
     RECT  6.288 83.075 9.768 83.267 ;
     RECT  4.704 83.267 4.728 83.843 ;
     RECT  7.8 83.267 8.616 83.843 ;
     RECT  2.4 83.267 2.712 84.249 ;
     RECT  7.8 83.843 8.112 84.249 ;
     RECT  13.2 54.083 13.512 84.249 ;
     RECT  18.6 27.107 18.912 84.249 ;
     RECT  24 26.003 24.312 84.249 ;
     RECT  29.4 20.003 29.712 84.249 ;
     RECT  34.8 19.811 35.112 84.249 ;
     RECT  40.2 6.707 40.512 84.249 ;
     RECT  2.4 84.249 2.52 84.263 ;
     RECT  7.8 84.249 7.92 84.263 ;
     RECT  13.2 84.249 13.32 84.263 ;
     RECT  18.6 84.249 18.72 84.263 ;
     RECT  24 84.249 24.12 84.263 ;
     RECT  29.4 84.249 29.52 84.263 ;
     RECT  34.8 84.249 34.92 84.263 ;
     RECT  40.2 84.249 40.32 84.263 ;
     RECT  0.984 2.137 2.4 4.213 ;
     RECT  32.04 2.245 33.072 4.261 ;
     RECT  33.096 2.245 34.368 2.629 ;
     RECT  29.712 2.581 31.104 3.109 ;
     RECT  2.712 2.821 3.696 3.349 ;
     RECT  8.112 2.821 9.456 3.301 ;
     RECT  8.472 3.301 9.456 7.189 ;
     RECT  35.208 3.397 36.48 3.925 ;
     RECT  1.176 4.213 2.4 4.499 ;
     RECT  0.984 4.499 2.4 36.659 ;
     RECT  24.312 10.021 25.344 20.195 ;
     RECT  33.624 13.139 34.608 16.259 ;
     RECT  29.712 15.059 30.96 16.595 ;
     RECT  33.576 16.259 34.608 17.363 ;
     RECT  35.208 17.123 36.24 19.811 ;
     RECT  33.552 17.363 34.608 17.651 ;
     RECT  33.552 17.651 34.8 18.181 ;
     RECT  31.896 18.181 33.36 20.003 ;
     RECT  33.384 18.181 34.8 20.723 ;
     RECT  35.112 19.811 36.24 20.579 ;
     RECT  11.064 20.293 12.48 27.395 ;
     RECT  2.712 46.787 3.936 58.739 ;
     RECT  9.672 55.331 10.752 57.635 ;
     RECT  4.32 58.739 4.752 60.181 ;
     RECT  4.776 58.739 6 59.315 ;
     RECT  4.776 59.315 4.92 60.661 ;
     RECT  8.112 60.949 9.12 61.525 ;
     RECT  9.144 60.949 10.416 62.053 ;
     RECT  9.144 62.053 10.272 62.725 ;
     RECT  5.112 62.293 6.528 62.629 ;
     RECT  8.472 62.771 9.456 64.213 ;
     RECT  5.112 63.299 6.528 64.357 ;
     RECT  3.144 70.115 4.32 70.739 ;
     RECT  3.144 70.739 4.464 72.325 ;
     RECT  9.24 71.219 10.272 72.853 ;
     RECT  2.712 72.371 3.84 80.677 ;
     RECT  9.768 74.723 10.848 82.979 ;
     RECT  5.112 80.291 6.144 81.011 ;
     RECT  4.728 81.011 6.144 81.589 ;
     RECT  4.728 81.589 5.808 83.075 ;
     RECT  3.576 82.931 4.656 83.267 ;
  END
END ot_hgi_qw_ovrow
END LIBRARY
